VERSION 5.8 ;
BUSBITCHARS "[]" ;
DIVIDERCHAR "/" ;
UNITS
    DATABASE MICRONS 1000 ;
END UNITS

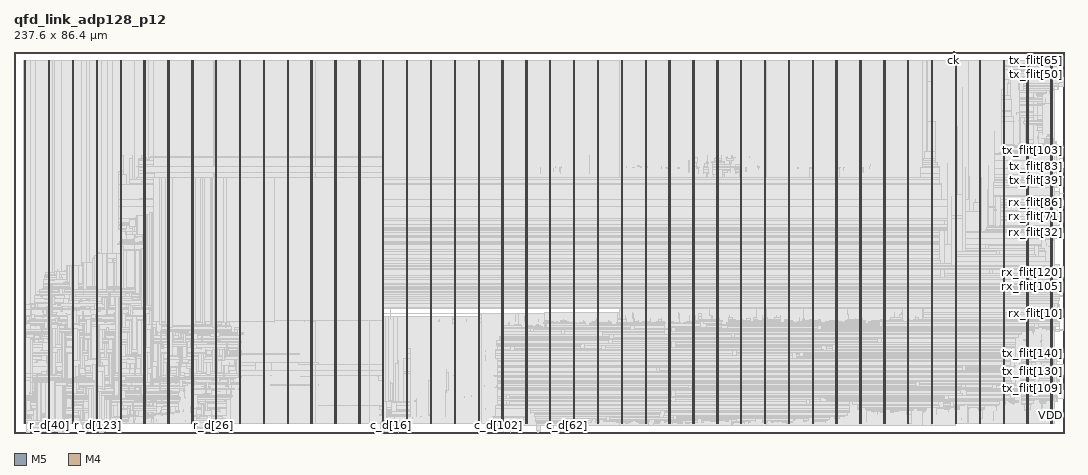
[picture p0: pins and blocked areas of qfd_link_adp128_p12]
MACRO qfd_link_adp128_p12
  FOREIGN qfd_link_adp128_p12 0 0 ;
  CLASS BLOCK ;
  SIZE 237.6 BY 86.4 ;
  PIN c_cr
    DIRECTION OUTPUT ;
    USE SIGNAL ;
    PORT
      LAYER M5 ;
        RECT  83.664 0 83.688 0.084 ;
    END
  END c_cr
  PIN c_d[0]
    DIRECTION INPUT ;
    USE SIGNAL ;
    PORT
      LAYER M5 ;
        RECT  83.76 0 83.784 0.084 ;
    END
  END c_d[0]
  PIN c_d[100]
    DIRECTION INPUT ;
    USE SIGNAL ;
    PORT
      LAYER M5 ;
        RECT  109.488 0 109.512 0.084 ;
    END
  END c_d[100]
  PIN c_d[101]
    DIRECTION INPUT ;
    USE SIGNAL ;
    PORT
      LAYER M5 ;
        RECT  109.584 0 109.608 0.084 ;
    END
  END c_d[101]
  PIN c_d[102]
    DIRECTION INPUT ;
    USE SIGNAL ;
    PORT
      LAYER M5 ;
        RECT  109.68 0 109.704 0.084 ;
    END
  END c_d[102]
  PIN c_d[103]
    DIRECTION INPUT ;
    USE SIGNAL ;
    PORT
      LAYER M5 ;
        RECT  109.776 0 109.8 0.084 ;
    END
  END c_d[103]
  PIN c_d[104]
    DIRECTION INPUT ;
    USE SIGNAL ;
    PORT
      LAYER M5 ;
        RECT  109.872 0 109.896 0.084 ;
    END
  END c_d[104]
  PIN c_d[105]
    DIRECTION INPUT ;
    USE SIGNAL ;
    PORT
      LAYER M5 ;
        RECT  109.968 0 109.992 0.084 ;
    END
  END c_d[105]
  PIN c_d[106]
    DIRECTION INPUT ;
    USE SIGNAL ;
    PORT
      LAYER M5 ;
        RECT  110.064 0 110.088 0.084 ;
    END
  END c_d[106]
  PIN c_d[107]
    DIRECTION INPUT ;
    USE SIGNAL ;
    PORT
      LAYER M5 ;
        RECT  110.16 0 110.184 0.084 ;
    END
  END c_d[107]
  PIN c_d[108]
    DIRECTION INPUT ;
    USE SIGNAL ;
    PORT
      LAYER M5 ;
        RECT  110.256 0 110.28 0.084 ;
    END
  END c_d[108]
  PIN c_d[109]
    DIRECTION INPUT ;
    USE SIGNAL ;
    PORT
      LAYER M5 ;
        RECT  110.352 0 110.376 0.084 ;
    END
  END c_d[109]
  PIN c_d[10]
    DIRECTION INPUT ;
    USE SIGNAL ;
    PORT
      LAYER M5 ;
        RECT  84.72 0 84.744 0.084 ;
    END
  END c_d[10]
  PIN c_d[110]
    DIRECTION INPUT ;
    USE SIGNAL ;
    PORT
      LAYER M5 ;
        RECT  110.448 0 110.472 0.084 ;
    END
  END c_d[110]
  PIN c_d[111]
    DIRECTION INPUT ;
    USE SIGNAL ;
    PORT
      LAYER M5 ;
        RECT  110.544 0 110.568 0.084 ;
    END
  END c_d[111]
  PIN c_d[112]
    DIRECTION INPUT ;
    USE SIGNAL ;
    PORT
      LAYER M5 ;
        RECT  110.64 0 110.664 0.084 ;
    END
  END c_d[112]
  PIN c_d[113]
    DIRECTION INPUT ;
    USE SIGNAL ;
    PORT
      LAYER M5 ;
        RECT  110.736 0 110.76 0.084 ;
    END
  END c_d[113]
  PIN c_d[114]
    DIRECTION INPUT ;
    USE SIGNAL ;
    PORT
      LAYER M5 ;
        RECT  110.832 0 110.856 0.084 ;
    END
  END c_d[114]
  PIN c_d[115]
    DIRECTION INPUT ;
    USE SIGNAL ;
    PORT
      LAYER M5 ;
        RECT  110.928 0 110.952 0.084 ;
    END
  END c_d[115]
  PIN c_d[116]
    DIRECTION INPUT ;
    USE SIGNAL ;
    PORT
      LAYER M5 ;
        RECT  111.024 0 111.048 0.084 ;
    END
  END c_d[116]
  PIN c_d[117]
    DIRECTION INPUT ;
    USE SIGNAL ;
    PORT
      LAYER M5 ;
        RECT  111.12 0 111.144 0.084 ;
    END
  END c_d[117]
  PIN c_d[118]
    DIRECTION INPUT ;
    USE SIGNAL ;
    PORT
      LAYER M5 ;
        RECT  111.216 0 111.24 0.084 ;
    END
  END c_d[118]
  PIN c_d[119]
    DIRECTION INPUT ;
    USE SIGNAL ;
    PORT
      LAYER M5 ;
        RECT  111.312 0 111.336 0.084 ;
    END
  END c_d[119]
  PIN c_d[11]
    DIRECTION INPUT ;
    USE SIGNAL ;
    PORT
      LAYER M5 ;
        RECT  84.816 0 84.84 0.084 ;
    END
  END c_d[11]
  PIN c_d[120]
    DIRECTION INPUT ;
    USE SIGNAL ;
    PORT
      LAYER M5 ;
        RECT  111.408 0 111.432 0.084 ;
    END
  END c_d[120]
  PIN c_d[121]
    DIRECTION INPUT ;
    USE SIGNAL ;
    PORT
      LAYER M5 ;
        RECT  111.504 0 111.528 0.084 ;
    END
  END c_d[121]
  PIN c_d[122]
    DIRECTION INPUT ;
    USE SIGNAL ;
    PORT
      LAYER M5 ;
        RECT  111.6 0 111.624 0.084 ;
    END
  END c_d[122]
  PIN c_d[123]
    DIRECTION INPUT ;
    USE SIGNAL ;
    PORT
      LAYER M5 ;
        RECT  111.696 0 111.72 0.084 ;
    END
  END c_d[123]
  PIN c_d[124]
    DIRECTION INPUT ;
    USE SIGNAL ;
    PORT
      LAYER M5 ;
        RECT  111.792 0 111.816 0.084 ;
    END
  END c_d[124]
  PIN c_d[125]
    DIRECTION INPUT ;
    USE SIGNAL ;
    PORT
      LAYER M5 ;
        RECT  111.888 0 111.912 0.084 ;
    END
  END c_d[125]
  PIN c_d[126]
    DIRECTION INPUT ;
    USE SIGNAL ;
    PORT
      LAYER M5 ;
        RECT  111.984 0 112.008 0.084 ;
    END
  END c_d[126]
  PIN c_d[127]
    DIRECTION INPUT ;
    USE SIGNAL ;
    PORT
      LAYER M5 ;
        RECT  42.192 0 42.216 0.084 ;
    END
  END c_d[127]
  PIN c_d[12]
    DIRECTION INPUT ;
    USE SIGNAL ;
    PORT
      LAYER M5 ;
        RECT  84.912 0 84.936 0.084 ;
    END
  END c_d[12]
  PIN c_d[13]
    DIRECTION INPUT ;
    USE SIGNAL ;
    PORT
      LAYER M5 ;
        RECT  85.008 0 85.032 0.084 ;
    END
  END c_d[13]
  PIN c_d[14]
    DIRECTION INPUT ;
    USE SIGNAL ;
    PORT
      LAYER M5 ;
        RECT  85.104 0 85.128 0.084 ;
    END
  END c_d[14]
  PIN c_d[15]
    DIRECTION INPUT ;
    USE SIGNAL ;
    PORT
      LAYER M5 ;
        RECT  85.2 0 85.224 0.084 ;
    END
  END c_d[15]
  PIN c_d[16]
    DIRECTION INPUT ;
    USE SIGNAL ;
    PORT
      LAYER M5 ;
        RECT  85.296 0 85.32 0.084 ;
    END
  END c_d[16]
  PIN c_d[17]
    DIRECTION INPUT ;
    USE SIGNAL ;
    PORT
      LAYER M5 ;
        RECT  85.392 0 85.416 0.084 ;
    END
  END c_d[17]
  PIN c_d[18]
    DIRECTION INPUT ;
    USE SIGNAL ;
    PORT
      LAYER M5 ;
        RECT  85.488 0 85.512 0.084 ;
    END
  END c_d[18]
  PIN c_d[19]
    DIRECTION INPUT ;
    USE SIGNAL ;
    PORT
      LAYER M5 ;
        RECT  85.584 0 85.608 0.084 ;
    END
  END c_d[19]
  PIN c_d[1]
    DIRECTION INPUT ;
    USE SIGNAL ;
    PORT
      LAYER M5 ;
        RECT  83.856 0 83.88 0.084 ;
    END
  END c_d[1]
  PIN c_d[20]
    DIRECTION INPUT ;
    USE SIGNAL ;
    PORT
      LAYER M5 ;
        RECT  85.68 0 85.704 0.084 ;
    END
  END c_d[20]
  PIN c_d[21]
    DIRECTION INPUT ;
    USE SIGNAL ;
    PORT
      LAYER M5 ;
        RECT  85.776 0 85.8 0.084 ;
    END
  END c_d[21]
  PIN c_d[22]
    DIRECTION INPUT ;
    USE SIGNAL ;
    PORT
      LAYER M5 ;
        RECT  85.872 0 85.896 0.084 ;
    END
  END c_d[22]
  PIN c_d[23]
    DIRECTION INPUT ;
    USE SIGNAL ;
    PORT
      LAYER M5 ;
        RECT  85.968 0 85.992 0.084 ;
    END
  END c_d[23]
  PIN c_d[24]
    DIRECTION INPUT ;
    USE SIGNAL ;
    PORT
      LAYER M5 ;
        RECT  86.064 0 86.088 0.084 ;
    END
  END c_d[24]
  PIN c_d[25]
    DIRECTION INPUT ;
    USE SIGNAL ;
    PORT
      LAYER M5 ;
        RECT  86.16 0 86.184 0.084 ;
    END
  END c_d[25]
  PIN c_d[26]
    DIRECTION INPUT ;
    USE SIGNAL ;
    PORT
      LAYER M5 ;
        RECT  86.256 0 86.28 0.084 ;
    END
  END c_d[26]
  PIN c_d[27]
    DIRECTION INPUT ;
    USE SIGNAL ;
    PORT
      LAYER M5 ;
        RECT  86.352 0 86.376 0.084 ;
    END
  END c_d[27]
  PIN c_d[28]
    DIRECTION INPUT ;
    USE SIGNAL ;
    PORT
      LAYER M5 ;
        RECT  86.448 0 86.472 0.084 ;
    END
  END c_d[28]
  PIN c_d[29]
    DIRECTION INPUT ;
    USE SIGNAL ;
    PORT
      LAYER M5 ;
        RECT  86.544 0 86.568 0.084 ;
    END
  END c_d[29]
  PIN c_d[2]
    DIRECTION INPUT ;
    USE SIGNAL ;
    PORT
      LAYER M5 ;
        RECT  83.952 0 83.976 0.084 ;
    END
  END c_d[2]
  PIN c_d[30]
    DIRECTION INPUT ;
    USE SIGNAL ;
    PORT
      LAYER M5 ;
        RECT  86.64 0 86.664 0.084 ;
    END
  END c_d[30]
  PIN c_d[31]
    DIRECTION INPUT ;
    USE SIGNAL ;
    PORT
      LAYER M5 ;
        RECT  122.064 0 122.088 0.084 ;
    END
  END c_d[31]
  PIN c_d[32]
    DIRECTION INPUT ;
    USE SIGNAL ;
    PORT
      LAYER M5 ;
        RECT  122.16 0 122.184 0.084 ;
    END
  END c_d[32]
  PIN c_d[33]
    DIRECTION INPUT ;
    USE SIGNAL ;
    PORT
      LAYER M5 ;
        RECT  122.256 0 122.28 0.084 ;
    END
  END c_d[33]
  PIN c_d[34]
    DIRECTION INPUT ;
    USE SIGNAL ;
    PORT
      LAYER M5 ;
        RECT  122.352 0 122.376 0.084 ;
    END
  END c_d[34]
  PIN c_d[35]
    DIRECTION INPUT ;
    USE SIGNAL ;
    PORT
      LAYER M5 ;
        RECT  122.448 0 122.472 0.084 ;
    END
  END c_d[35]
  PIN c_d[36]
    DIRECTION INPUT ;
    USE SIGNAL ;
    PORT
      LAYER M5 ;
        RECT  122.544 0 122.568 0.084 ;
    END
  END c_d[36]
  PIN c_d[37]
    DIRECTION INPUT ;
    USE SIGNAL ;
    PORT
      LAYER M5 ;
        RECT  122.64 0 122.664 0.084 ;
    END
  END c_d[37]
  PIN c_d[38]
    DIRECTION INPUT ;
    USE SIGNAL ;
    PORT
      LAYER M5 ;
        RECT  122.736 0 122.76 0.084 ;
    END
  END c_d[38]
  PIN c_d[39]
    DIRECTION INPUT ;
    USE SIGNAL ;
    PORT
      LAYER M5 ;
        RECT  122.832 0 122.856 0.084 ;
    END
  END c_d[39]
  PIN c_d[3]
    DIRECTION INPUT ;
    USE SIGNAL ;
    PORT
      LAYER M5 ;
        RECT  84.048 0 84.072 0.084 ;
    END
  END c_d[3]
  PIN c_d[40]
    DIRECTION INPUT ;
    USE SIGNAL ;
    PORT
      LAYER M5 ;
        RECT  122.928 0 122.952 0.084 ;
    END
  END c_d[40]
  PIN c_d[41]
    DIRECTION INPUT ;
    USE SIGNAL ;
    PORT
      LAYER M5 ;
        RECT  123.024 0 123.048 0.084 ;
    END
  END c_d[41]
  PIN c_d[42]
    DIRECTION INPUT ;
    USE SIGNAL ;
    PORT
      LAYER M5 ;
        RECT  123.12 0 123.144 0.084 ;
    END
  END c_d[42]
  PIN c_d[43]
    DIRECTION INPUT ;
    USE SIGNAL ;
    PORT
      LAYER M5 ;
        RECT  123.216 0 123.24 0.084 ;
    END
  END c_d[43]
  PIN c_d[44]
    DIRECTION INPUT ;
    USE SIGNAL ;
    PORT
      LAYER M5 ;
        RECT  123.312 0 123.336 0.084 ;
    END
  END c_d[44]
  PIN c_d[45]
    DIRECTION INPUT ;
    USE SIGNAL ;
    PORT
      LAYER M5 ;
        RECT  123.408 0 123.432 0.084 ;
    END
  END c_d[45]
  PIN c_d[46]
    DIRECTION INPUT ;
    USE SIGNAL ;
    PORT
      LAYER M5 ;
        RECT  123.504 0 123.528 0.084 ;
    END
  END c_d[46]
  PIN c_d[47]
    DIRECTION INPUT ;
    USE SIGNAL ;
    PORT
      LAYER M5 ;
        RECT  123.6 0 123.624 0.084 ;
    END
  END c_d[47]
  PIN c_d[48]
    DIRECTION INPUT ;
    USE SIGNAL ;
    PORT
      LAYER M5 ;
        RECT  123.696 0 123.72 0.084 ;
    END
  END c_d[48]
  PIN c_d[49]
    DIRECTION INPUT ;
    USE SIGNAL ;
    PORT
      LAYER M5 ;
        RECT  123.792 0 123.816 0.084 ;
    END
  END c_d[49]
  PIN c_d[4]
    DIRECTION INPUT ;
    USE SIGNAL ;
    PORT
      LAYER M5 ;
        RECT  84.144 0 84.168 0.084 ;
    END
  END c_d[4]
  PIN c_d[50]
    DIRECTION INPUT ;
    USE SIGNAL ;
    PORT
      LAYER M5 ;
        RECT  123.888 0 123.912 0.084 ;
    END
  END c_d[50]
  PIN c_d[51]
    DIRECTION INPUT ;
    USE SIGNAL ;
    PORT
      LAYER M5 ;
        RECT  123.984 0 124.008 0.084 ;
    END
  END c_d[51]
  PIN c_d[52]
    DIRECTION INPUT ;
    USE SIGNAL ;
    PORT
      LAYER M5 ;
        RECT  124.08 0 124.104 0.084 ;
    END
  END c_d[52]
  PIN c_d[53]
    DIRECTION INPUT ;
    USE SIGNAL ;
    PORT
      LAYER M5 ;
        RECT  124.176 0 124.2 0.084 ;
    END
  END c_d[53]
  PIN c_d[54]
    DIRECTION INPUT ;
    USE SIGNAL ;
    PORT
      LAYER M5 ;
        RECT  124.272 0 124.296 0.084 ;
    END
  END c_d[54]
  PIN c_d[55]
    DIRECTION INPUT ;
    USE SIGNAL ;
    PORT
      LAYER M5 ;
        RECT  124.368 0 124.392 0.084 ;
    END
  END c_d[55]
  PIN c_d[56]
    DIRECTION INPUT ;
    USE SIGNAL ;
    PORT
      LAYER M5 ;
        RECT  124.464 0 124.488 0.084 ;
    END
  END c_d[56]
  PIN c_d[57]
    DIRECTION INPUT ;
    USE SIGNAL ;
    PORT
      LAYER M5 ;
        RECT  124.56 0 124.584 0.084 ;
    END
  END c_d[57]
  PIN c_d[58]
    DIRECTION INPUT ;
    USE SIGNAL ;
    PORT
      LAYER M5 ;
        RECT  124.656 0 124.68 0.084 ;
    END
  END c_d[58]
  PIN c_d[59]
    DIRECTION INPUT ;
    USE SIGNAL ;
    PORT
      LAYER M5 ;
        RECT  124.752 0 124.776 0.084 ;
    END
  END c_d[59]
  PIN c_d[5]
    DIRECTION INPUT ;
    USE SIGNAL ;
    PORT
      LAYER M5 ;
        RECT  84.24 0 84.264 0.084 ;
    END
  END c_d[5]
  PIN c_d[60]
    DIRECTION INPUT ;
    USE SIGNAL ;
    PORT
      LAYER M5 ;
        RECT  124.848 0 124.872 0.084 ;
    END
  END c_d[60]
  PIN c_d[61]
    DIRECTION INPUT ;
    USE SIGNAL ;
    PORT
      LAYER M5 ;
        RECT  124.944 0 124.968 0.084 ;
    END
  END c_d[61]
  PIN c_d[62]
    DIRECTION INPUT ;
    USE SIGNAL ;
    PORT
      LAYER M5 ;
        RECT  125.04 0 125.064 0.084 ;
    END
  END c_d[62]
  PIN c_d[63]
    DIRECTION INPUT ;
    USE SIGNAL ;
    PORT
      LAYER M5 ;
        RECT  118.992 0 119.016 0.084 ;
    END
  END c_d[63]
  PIN c_d[64]
    DIRECTION INPUT ;
    USE SIGNAL ;
    PORT
      LAYER M5 ;
        RECT  119.088 0 119.112 0.084 ;
    END
  END c_d[64]
  PIN c_d[65]
    DIRECTION INPUT ;
    USE SIGNAL ;
    PORT
      LAYER M5 ;
        RECT  119.184 0 119.208 0.084 ;
    END
  END c_d[65]
  PIN c_d[66]
    DIRECTION INPUT ;
    USE SIGNAL ;
    PORT
      LAYER M5 ;
        RECT  119.28 0 119.304 0.084 ;
    END
  END c_d[66]
  PIN c_d[67]
    DIRECTION INPUT ;
    USE SIGNAL ;
    PORT
      LAYER M5 ;
        RECT  119.376 0 119.4 0.084 ;
    END
  END c_d[67]
  PIN c_d[68]
    DIRECTION INPUT ;
    USE SIGNAL ;
    PORT
      LAYER M5 ;
        RECT  119.472 0 119.496 0.084 ;
    END
  END c_d[68]
  PIN c_d[69]
    DIRECTION INPUT ;
    USE SIGNAL ;
    PORT
      LAYER M5 ;
        RECT  119.568 0 119.592 0.084 ;
    END
  END c_d[69]
  PIN c_d[6]
    DIRECTION INPUT ;
    USE SIGNAL ;
    PORT
      LAYER M5 ;
        RECT  84.336 0 84.36 0.084 ;
    END
  END c_d[6]
  PIN c_d[70]
    DIRECTION INPUT ;
    USE SIGNAL ;
    PORT
      LAYER M5 ;
        RECT  119.664 0 119.688 0.084 ;
    END
  END c_d[70]
  PIN c_d[71]
    DIRECTION INPUT ;
    USE SIGNAL ;
    PORT
      LAYER M5 ;
        RECT  119.76 0 119.784 0.084 ;
    END
  END c_d[71]
  PIN c_d[72]
    DIRECTION INPUT ;
    USE SIGNAL ;
    PORT
      LAYER M5 ;
        RECT  119.856 0 119.88 0.084 ;
    END
  END c_d[72]
  PIN c_d[73]
    DIRECTION INPUT ;
    USE SIGNAL ;
    PORT
      LAYER M5 ;
        RECT  119.952 0 119.976 0.084 ;
    END
  END c_d[73]
  PIN c_d[74]
    DIRECTION INPUT ;
    USE SIGNAL ;
    PORT
      LAYER M5 ;
        RECT  120.048 0 120.072 0.084 ;
    END
  END c_d[74]
  PIN c_d[75]
    DIRECTION INPUT ;
    USE SIGNAL ;
    PORT
      LAYER M5 ;
        RECT  120.144 0 120.168 0.084 ;
    END
  END c_d[75]
  PIN c_d[76]
    DIRECTION INPUT ;
    USE SIGNAL ;
    PORT
      LAYER M5 ;
        RECT  120.24 0 120.264 0.084 ;
    END
  END c_d[76]
  PIN c_d[77]
    DIRECTION INPUT ;
    USE SIGNAL ;
    PORT
      LAYER M5 ;
        RECT  120.336 0 120.36 0.084 ;
    END
  END c_d[77]
  PIN c_d[78]
    DIRECTION INPUT ;
    USE SIGNAL ;
    PORT
      LAYER M5 ;
        RECT  120.432 0 120.456 0.084 ;
    END
  END c_d[78]
  PIN c_d[79]
    DIRECTION INPUT ;
    USE SIGNAL ;
    PORT
      LAYER M5 ;
        RECT  120.528 0 120.552 0.084 ;
    END
  END c_d[79]
  PIN c_d[7]
    DIRECTION INPUT ;
    USE SIGNAL ;
    PORT
      LAYER M5 ;
        RECT  84.432 0 84.456 0.084 ;
    END
  END c_d[7]
  PIN c_d[80]
    DIRECTION INPUT ;
    USE SIGNAL ;
    PORT
      LAYER M5 ;
        RECT  120.624 0 120.648 0.084 ;
    END
  END c_d[80]
  PIN c_d[81]
    DIRECTION INPUT ;
    USE SIGNAL ;
    PORT
      LAYER M5 ;
        RECT  120.72 0 120.744 0.084 ;
    END
  END c_d[81]
  PIN c_d[82]
    DIRECTION INPUT ;
    USE SIGNAL ;
    PORT
      LAYER M5 ;
        RECT  120.816 0 120.84 0.084 ;
    END
  END c_d[82]
  PIN c_d[83]
    DIRECTION INPUT ;
    USE SIGNAL ;
    PORT
      LAYER M5 ;
        RECT  120.912 0 120.936 0.084 ;
    END
  END c_d[83]
  PIN c_d[84]
    DIRECTION INPUT ;
    USE SIGNAL ;
    PORT
      LAYER M5 ;
        RECT  121.008 0 121.032 0.084 ;
    END
  END c_d[84]
  PIN c_d[85]
    DIRECTION INPUT ;
    USE SIGNAL ;
    PORT
      LAYER M5 ;
        RECT  121.104 0 121.128 0.084 ;
    END
  END c_d[85]
  PIN c_d[86]
    DIRECTION INPUT ;
    USE SIGNAL ;
    PORT
      LAYER M5 ;
        RECT  121.2 0 121.224 0.084 ;
    END
  END c_d[86]
  PIN c_d[87]
    DIRECTION INPUT ;
    USE SIGNAL ;
    PORT
      LAYER M5 ;
        RECT  121.296 0 121.32 0.084 ;
    END
  END c_d[87]
  PIN c_d[88]
    DIRECTION INPUT ;
    USE SIGNAL ;
    PORT
      LAYER M5 ;
        RECT  121.392 0 121.416 0.084 ;
    END
  END c_d[88]
  PIN c_d[89]
    DIRECTION INPUT ;
    USE SIGNAL ;
    PORT
      LAYER M5 ;
        RECT  121.488 0 121.512 0.084 ;
    END
  END c_d[89]
  PIN c_d[8]
    DIRECTION INPUT ;
    USE SIGNAL ;
    PORT
      LAYER M5 ;
        RECT  84.528 0 84.552 0.084 ;
    END
  END c_d[8]
  PIN c_d[90]
    DIRECTION INPUT ;
    USE SIGNAL ;
    PORT
      LAYER M5 ;
        RECT  121.584 0 121.608 0.084 ;
    END
  END c_d[90]
  PIN c_d[91]
    DIRECTION INPUT ;
    USE SIGNAL ;
    PORT
      LAYER M5 ;
        RECT  121.68 0 121.704 0.084 ;
    END
  END c_d[91]
  PIN c_d[92]
    DIRECTION INPUT ;
    USE SIGNAL ;
    PORT
      LAYER M5 ;
        RECT  121.776 0 121.8 0.084 ;
    END
  END c_d[92]
  PIN c_d[93]
    DIRECTION INPUT ;
    USE SIGNAL ;
    PORT
      LAYER M5 ;
        RECT  121.872 0 121.896 0.084 ;
    END
  END c_d[93]
  PIN c_d[94]
    DIRECTION INPUT ;
    USE SIGNAL ;
    PORT
      LAYER M5 ;
        RECT  121.968 0 121.992 0.084 ;
    END
  END c_d[94]
  PIN c_d[95]
    DIRECTION INPUT ;
    USE SIGNAL ;
    PORT
      LAYER M5 ;
        RECT  109.008 0 109.032 0.084 ;
    END
  END c_d[95]
  PIN c_d[96]
    DIRECTION INPUT ;
    USE SIGNAL ;
    PORT
      LAYER M5 ;
        RECT  109.104 0 109.128 0.084 ;
    END
  END c_d[96]
  PIN c_d[97]
    DIRECTION INPUT ;
    USE SIGNAL ;
    PORT
      LAYER M5 ;
        RECT  109.2 0 109.224 0.084 ;
    END
  END c_d[97]
  PIN c_d[98]
    DIRECTION INPUT ;
    USE SIGNAL ;
    PORT
      LAYER M5 ;
        RECT  109.296 0 109.32 0.084 ;
    END
  END c_d[98]
  PIN c_d[99]
    DIRECTION INPUT ;
    USE SIGNAL ;
    PORT
      LAYER M5 ;
        RECT  109.392 0 109.416 0.084 ;
    END
  END c_d[99]
  PIN c_d[9]
    DIRECTION INPUT ;
    USE SIGNAL ;
    PORT
      LAYER M5 ;
        RECT  84.624 0 84.648 0.084 ;
    END
  END c_d[9]
  PIN c_v
    DIRECTION INPUT ;
    USE SIGNAL ;
    PORT
      LAYER M5 ;
        RECT  42.288 0 42.312 0.084 ;
    END
  END c_v
  PIN ck
    DIRECTION INPUT ;
    USE SIGNAL ;
    PORT
      LAYER M5 ;
        RECT  212.688 86.316 212.712 86.4 ;
    END
    PORT
      LAYER M5 ;
        RECT  212.688 84.263 212.712 86.352 ;
    END
  END ck
  PIN fault
    DIRECTION OUTPUT ;
    USE SIGNAL ;
    PORT
      LAYER M5 ;
        RECT  42.384 0 42.408 0.084 ;
    END
  END fault
  PIN r_cr
    DIRECTION INPUT ;
    USE SIGNAL ;
    PORT
      LAYER M5 ;
        RECT  42.48 0 42.504 0.084 ;
    END
  END r_cr
  PIN r_d[0]
    DIRECTION OUTPUT ;
    USE SIGNAL ;
    PORT
      LAYER M5 ;
        RECT  42.576 0 42.6 0.084 ;
    END
  END r_d[0]
  PIN r_d[100]
    DIRECTION OUTPUT ;
    USE SIGNAL ;
    PORT
      LAYER M5 ;
        RECT  16.848 0 16.872 0.084 ;
    END
  END r_d[100]
  PIN r_d[101]
    DIRECTION OUTPUT ;
    USE SIGNAL ;
    PORT
      LAYER M5 ;
        RECT  16.944 0 16.968 0.084 ;
    END
  END r_d[101]
  PIN r_d[102]
    DIRECTION OUTPUT ;
    USE SIGNAL ;
    PORT
      LAYER M5 ;
        RECT  17.04 0 17.064 0.084 ;
    END
  END r_d[102]
  PIN r_d[103]
    DIRECTION OUTPUT ;
    USE SIGNAL ;
    PORT
      LAYER M5 ;
        RECT  17.136 0 17.16 0.084 ;
    END
  END r_d[103]
  PIN r_d[104]
    DIRECTION OUTPUT ;
    USE SIGNAL ;
    PORT
      LAYER M5 ;
        RECT  17.232 0 17.256 0.084 ;
    END
  END r_d[104]
  PIN r_d[105]
    DIRECTION OUTPUT ;
    USE SIGNAL ;
    PORT
      LAYER M5 ;
        RECT  17.328 0 17.352 0.084 ;
    END
  END r_d[105]
  PIN r_d[106]
    DIRECTION OUTPUT ;
    USE SIGNAL ;
    PORT
      LAYER M5 ;
        RECT  17.424 0 17.448 0.084 ;
    END
  END r_d[106]
  PIN r_d[107]
    DIRECTION OUTPUT ;
    USE SIGNAL ;
    PORT
      LAYER M5 ;
        RECT  17.52 0 17.544 0.084 ;
    END
  END r_d[107]
  PIN r_d[108]
    DIRECTION OUTPUT ;
    USE SIGNAL ;
    PORT
      LAYER M5 ;
        RECT  17.616 0 17.64 0.084 ;
    END
  END r_d[108]
  PIN r_d[109]
    DIRECTION OUTPUT ;
    USE SIGNAL ;
    PORT
      LAYER M5 ;
        RECT  17.712 0 17.736 0.084 ;
    END
  END r_d[109]
  PIN r_d[10]
    DIRECTION OUTPUT ;
    USE SIGNAL ;
    PORT
      LAYER M5 ;
        RECT  43.536 0 43.56 0.084 ;
    END
  END r_d[10]
  PIN r_d[110]
    DIRECTION OUTPUT ;
    USE SIGNAL ;
    PORT
      LAYER M5 ;
        RECT  17.808 0 17.832 0.084 ;
    END
  END r_d[110]
  PIN r_d[111]
    DIRECTION OUTPUT ;
    USE SIGNAL ;
    PORT
      LAYER M5 ;
        RECT  17.904 0 17.928 0.084 ;
    END
  END r_d[111]
  PIN r_d[112]
    DIRECTION OUTPUT ;
    USE SIGNAL ;
    PORT
      LAYER M5 ;
        RECT  18 0 18.024 0.084 ;
    END
  END r_d[112]
  PIN r_d[113]
    DIRECTION OUTPUT ;
    USE SIGNAL ;
    PORT
      LAYER M5 ;
        RECT  18.096 0 18.12 0.084 ;
    END
  END r_d[113]
  PIN r_d[114]
    DIRECTION OUTPUT ;
    USE SIGNAL ;
    PORT
      LAYER M5 ;
        RECT  18.192 0 18.216 0.084 ;
    END
  END r_d[114]
  PIN r_d[115]
    DIRECTION OUTPUT ;
    USE SIGNAL ;
    PORT
      LAYER M5 ;
        RECT  18.288 0 18.312 0.084 ;
    END
  END r_d[115]
  PIN r_d[116]
    DIRECTION OUTPUT ;
    USE SIGNAL ;
    PORT
      LAYER M5 ;
        RECT  18.384 0 18.408 0.084 ;
    END
  END r_d[116]
  PIN r_d[117]
    DIRECTION OUTPUT ;
    USE SIGNAL ;
    PORT
      LAYER M5 ;
        RECT  18.48 0 18.504 0.084 ;
    END
  END r_d[117]
  PIN r_d[118]
    DIRECTION OUTPUT ;
    USE SIGNAL ;
    PORT
      LAYER M5 ;
        RECT  18.576 0 18.6 0.084 ;
    END
  END r_d[118]
  PIN r_d[119]
    DIRECTION OUTPUT ;
    USE SIGNAL ;
    PORT
      LAYER M5 ;
        RECT  18.672 0 18.696 0.084 ;
    END
  END r_d[119]
  PIN r_d[11]
    DIRECTION OUTPUT ;
    USE SIGNAL ;
    PORT
      LAYER M5 ;
        RECT  43.632 0 43.656 0.084 ;
    END
  END r_d[11]
  PIN r_d[120]
    DIRECTION OUTPUT ;
    USE SIGNAL ;
    PORT
      LAYER M5 ;
        RECT  18.768 0 18.792 0.084 ;
    END
  END r_d[120]
  PIN r_d[121]
    DIRECTION OUTPUT ;
    USE SIGNAL ;
    PORT
      LAYER M5 ;
        RECT  18.864 0 18.888 0.084 ;
    END
  END r_d[121]
  PIN r_d[122]
    DIRECTION OUTPUT ;
    USE SIGNAL ;
    PORT
      LAYER M5 ;
        RECT  18.96 0 18.984 0.084 ;
    END
  END r_d[122]
  PIN r_d[123]
    DIRECTION OUTPUT ;
    USE SIGNAL ;
    PORT
      LAYER M5 ;
        RECT  19.056 0 19.08 0.084 ;
    END
  END r_d[123]
  PIN r_d[124]
    DIRECTION OUTPUT ;
    USE SIGNAL ;
    PORT
      LAYER M5 ;
        RECT  20.496 0 20.52 0.084 ;
    END
  END r_d[124]
  PIN r_d[125]
    DIRECTION OUTPUT ;
    USE SIGNAL ;
    PORT
      LAYER M5 ;
        RECT  20.592 0 20.616 0.084 ;
    END
  END r_d[125]
  PIN r_d[126]
    DIRECTION OUTPUT ;
    USE SIGNAL ;
    PORT
      LAYER M5 ;
        RECT  20.688 0 20.712 0.084 ;
    END
  END r_d[126]
  PIN r_d[127]
    DIRECTION OUTPUT ;
    USE SIGNAL ;
    PORT
      LAYER M5 ;
        RECT  20.784 0 20.808 0.084 ;
    END
  END r_d[127]
  PIN r_d[12]
    DIRECTION OUTPUT ;
    USE SIGNAL ;
    PORT
      LAYER M5 ;
        RECT  43.728 0 43.752 0.084 ;
    END
  END r_d[12]
  PIN r_d[13]
    DIRECTION OUTPUT ;
    USE SIGNAL ;
    PORT
      LAYER M5 ;
        RECT  43.824 0 43.848 0.084 ;
    END
  END r_d[13]
  PIN r_d[14]
    DIRECTION OUTPUT ;
    USE SIGNAL ;
    PORT
      LAYER M5 ;
        RECT  43.92 0 43.944 0.084 ;
    END
  END r_d[14]
  PIN r_d[15]
    DIRECTION OUTPUT ;
    USE SIGNAL ;
    PORT
      LAYER M5 ;
        RECT  44.016 0 44.04 0.084 ;
    END
  END r_d[15]
  PIN r_d[16]
    DIRECTION OUTPUT ;
    USE SIGNAL ;
    PORT
      LAYER M5 ;
        RECT  44.112 0 44.136 0.084 ;
    END
  END r_d[16]
  PIN r_d[17]
    DIRECTION OUTPUT ;
    USE SIGNAL ;
    PORT
      LAYER M5 ;
        RECT  44.208 0 44.232 0.084 ;
    END
  END r_d[17]
  PIN r_d[18]
    DIRECTION OUTPUT ;
    USE SIGNAL ;
    PORT
      LAYER M5 ;
        RECT  44.304 0 44.328 0.084 ;
    END
  END r_d[18]
  PIN r_d[19]
    DIRECTION OUTPUT ;
    USE SIGNAL ;
    PORT
      LAYER M5 ;
        RECT  44.4 0 44.424 0.084 ;
    END
  END r_d[19]
  PIN r_d[1]
    DIRECTION OUTPUT ;
    USE SIGNAL ;
    PORT
      LAYER M5 ;
        RECT  42.672 0 42.696 0.084 ;
    END
  END r_d[1]
  PIN r_d[20]
    DIRECTION OUTPUT ;
    USE SIGNAL ;
    PORT
      LAYER M5 ;
        RECT  44.496 0 44.52 0.084 ;
    END
  END r_d[20]
  PIN r_d[21]
    DIRECTION OUTPUT ;
    USE SIGNAL ;
    PORT
      LAYER M5 ;
        RECT  44.592 0 44.616 0.084 ;
    END
  END r_d[21]
  PIN r_d[22]
    DIRECTION OUTPUT ;
    USE SIGNAL ;
    PORT
      LAYER M5 ;
        RECT  44.688 0 44.712 0.084 ;
    END
  END r_d[22]
  PIN r_d[23]
    DIRECTION OUTPUT ;
    USE SIGNAL ;
    PORT
      LAYER M5 ;
        RECT  44.784 0 44.808 0.084 ;
    END
  END r_d[23]
  PIN r_d[24]
    DIRECTION OUTPUT ;
    USE SIGNAL ;
    PORT
      LAYER M5 ;
        RECT  44.88 0 44.904 0.084 ;
    END
  END r_d[24]
  PIN r_d[25]
    DIRECTION OUTPUT ;
    USE SIGNAL ;
    PORT
      LAYER M5 ;
        RECT  44.976 0 45 0.084 ;
    END
  END r_d[25]
  PIN r_d[26]
    DIRECTION OUTPUT ;
    USE SIGNAL ;
    PORT
      LAYER M5 ;
        RECT  45.072 0 45.096 0.084 ;
    END
  END r_d[26]
  PIN r_d[27]
    DIRECTION OUTPUT ;
    USE SIGNAL ;
    PORT
      LAYER M5 ;
        RECT  45.168 0 45.192 0.084 ;
    END
  END r_d[27]
  PIN r_d[28]
    DIRECTION OUTPUT ;
    USE SIGNAL ;
    PORT
      LAYER M5 ;
        RECT  6.864 0 6.888 0.084 ;
    END
  END r_d[28]
  PIN r_d[29]
    DIRECTION OUTPUT ;
    USE SIGNAL ;
    PORT
      LAYER M5 ;
        RECT  6.96 0 6.984 0.084 ;
    END
  END r_d[29]
  PIN r_d[2]
    DIRECTION OUTPUT ;
    USE SIGNAL ;
    PORT
      LAYER M5 ;
        RECT  42.768 0 42.792 0.084 ;
    END
  END r_d[2]
  PIN r_d[30]
    DIRECTION OUTPUT ;
    USE SIGNAL ;
    PORT
      LAYER M5 ;
        RECT  7.056 0 7.08 0.084 ;
    END
  END r_d[30]
  PIN r_d[31]
    DIRECTION OUTPUT ;
    USE SIGNAL ;
    PORT
      LAYER M5 ;
        RECT  7.152 0 7.176 0.084 ;
    END
  END r_d[31]
  PIN r_d[32]
    DIRECTION OUTPUT ;
    USE SIGNAL ;
    PORT
      LAYER M5 ;
        RECT  7.248 0 7.272 0.084 ;
    END
  END r_d[32]
  PIN r_d[33]
    DIRECTION OUTPUT ;
    USE SIGNAL ;
    PORT
      LAYER M5 ;
        RECT  7.344 0 7.368 0.084 ;
    END
  END r_d[33]
  PIN r_d[34]
    DIRECTION OUTPUT ;
    USE SIGNAL ;
    PORT
      LAYER M5 ;
        RECT  7.44 0 7.464 0.084 ;
    END
  END r_d[34]
  PIN r_d[35]
    DIRECTION OUTPUT ;
    USE SIGNAL ;
    PORT
      LAYER M5 ;
        RECT  7.536 0 7.56 0.084 ;
    END
  END r_d[35]
  PIN r_d[36]
    DIRECTION OUTPUT ;
    USE SIGNAL ;
    PORT
      LAYER M5 ;
        RECT  7.632 0 7.656 0.084 ;
    END
  END r_d[36]
  PIN r_d[37]
    DIRECTION OUTPUT ;
    USE SIGNAL ;
    PORT
      LAYER M5 ;
        RECT  7.728 0 7.752 0.084 ;
    END
  END r_d[37]
  PIN r_d[38]
    DIRECTION OUTPUT ;
    USE SIGNAL ;
    PORT
      LAYER M5 ;
        RECT  7.824 0 7.848 0.084 ;
    END
  END r_d[38]
  PIN r_d[39]
    DIRECTION OUTPUT ;
    USE SIGNAL ;
    PORT
      LAYER M5 ;
        RECT  7.92 0 7.944 0.084 ;
    END
  END r_d[39]
  PIN r_d[3]
    DIRECTION OUTPUT ;
    USE SIGNAL ;
    PORT
      LAYER M5 ;
        RECT  42.864 0 42.888 0.084 ;
    END
  END r_d[3]
  PIN r_d[40]
    DIRECTION OUTPUT ;
    USE SIGNAL ;
    PORT
      LAYER M5 ;
        RECT  8.016 0 8.04 0.084 ;
    END
  END r_d[40]
  PIN r_d[41]
    DIRECTION OUTPUT ;
    USE SIGNAL ;
    PORT
      LAYER M5 ;
        RECT  8.112 0 8.136 0.084 ;
    END
  END r_d[41]
  PIN r_d[42]
    DIRECTION OUTPUT ;
    USE SIGNAL ;
    PORT
      LAYER M5 ;
        RECT  8.208 0 8.232 0.084 ;
    END
  END r_d[42]
  PIN r_d[43]
    DIRECTION OUTPUT ;
    USE SIGNAL ;
    PORT
      LAYER M5 ;
        RECT  8.304 0 8.328 0.084 ;
    END
  END r_d[43]
  PIN r_d[44]
    DIRECTION OUTPUT ;
    USE SIGNAL ;
    PORT
      LAYER M5 ;
        RECT  8.4 0 8.424 0.084 ;
    END
  END r_d[44]
  PIN r_d[45]
    DIRECTION OUTPUT ;
    USE SIGNAL ;
    PORT
      LAYER M5 ;
        RECT  8.496 0 8.52 0.084 ;
    END
  END r_d[45]
  PIN r_d[46]
    DIRECTION OUTPUT ;
    USE SIGNAL ;
    PORT
      LAYER M5 ;
        RECT  8.592 0 8.616 0.084 ;
    END
  END r_d[46]
  PIN r_d[47]
    DIRECTION OUTPUT ;
    USE SIGNAL ;
    PORT
      LAYER M5 ;
        RECT  8.688 0 8.712 0.084 ;
    END
  END r_d[47]
  PIN r_d[48]
    DIRECTION OUTPUT ;
    USE SIGNAL ;
    PORT
      LAYER M5 ;
        RECT  8.784 0 8.808 0.084 ;
    END
  END r_d[48]
  PIN r_d[49]
    DIRECTION OUTPUT ;
    USE SIGNAL ;
    PORT
      LAYER M5 ;
        RECT  8.88 0 8.904 0.084 ;
    END
  END r_d[49]
  PIN r_d[4]
    DIRECTION OUTPUT ;
    USE SIGNAL ;
    PORT
      LAYER M5 ;
        RECT  42.96 0 42.984 0.084 ;
    END
  END r_d[4]
  PIN r_d[50]
    DIRECTION OUTPUT ;
    USE SIGNAL ;
    PORT
      LAYER M5 ;
        RECT  8.976 0 9 0.084 ;
    END
  END r_d[50]
  PIN r_d[51]
    DIRECTION OUTPUT ;
    USE SIGNAL ;
    PORT
      LAYER M5 ;
        RECT  9.072 0 9.096 0.084 ;
    END
  END r_d[51]
  PIN r_d[52]
    DIRECTION OUTPUT ;
    USE SIGNAL ;
    PORT
      LAYER M5 ;
        RECT  9.168 0 9.192 0.084 ;
    END
  END r_d[52]
  PIN r_d[53]
    DIRECTION OUTPUT ;
    USE SIGNAL ;
    PORT
      LAYER M5 ;
        RECT  9.264 0 9.288 0.084 ;
    END
  END r_d[53]
  PIN r_d[54]
    DIRECTION OUTPUT ;
    USE SIGNAL ;
    PORT
      LAYER M5 ;
        RECT  9.36 0 9.384 0.084 ;
    END
  END r_d[54]
  PIN r_d[55]
    DIRECTION OUTPUT ;
    USE SIGNAL ;
    PORT
      LAYER M5 ;
        RECT  9.456 0 9.48 0.084 ;
    END
  END r_d[55]
  PIN r_d[56]
    DIRECTION OUTPUT ;
    USE SIGNAL ;
    PORT
      LAYER M5 ;
        RECT  9.552 0 9.576 0.084 ;
    END
  END r_d[56]
  PIN r_d[57]
    DIRECTION OUTPUT ;
    USE SIGNAL ;
    PORT
      LAYER M5 ;
        RECT  9.648 0 9.672 0.084 ;
    END
  END r_d[57]
  PIN r_d[58]
    DIRECTION OUTPUT ;
    USE SIGNAL ;
    PORT
      LAYER M5 ;
        RECT  9.744 0 9.768 0.084 ;
    END
  END r_d[58]
  PIN r_d[59]
    DIRECTION OUTPUT ;
    USE SIGNAL ;
    PORT
      LAYER M5 ;
        RECT  9.84 0 9.864 0.084 ;
    END
  END r_d[59]
  PIN r_d[5]
    DIRECTION OUTPUT ;
    USE SIGNAL ;
    PORT
      LAYER M5 ;
        RECT  43.056 0 43.08 0.084 ;
    END
  END r_d[5]
  PIN r_d[60]
    DIRECTION OUTPUT ;
    USE SIGNAL ;
    PORT
      LAYER M5 ;
        RECT  3.792 0 3.816 0.084 ;
    END
  END r_d[60]
  PIN r_d[61]
    DIRECTION OUTPUT ;
    USE SIGNAL ;
    PORT
      LAYER M5 ;
        RECT  3.888 0 3.912 0.084 ;
    END
  END r_d[61]
  PIN r_d[62]
    DIRECTION OUTPUT ;
    USE SIGNAL ;
    PORT
      LAYER M5 ;
        RECT  3.984 0 4.008 0.084 ;
    END
  END r_d[62]
  PIN r_d[63]
    DIRECTION OUTPUT ;
    USE SIGNAL ;
    PORT
      LAYER M5 ;
        RECT  4.08 0 4.104 0.084 ;
    END
  END r_d[63]
  PIN r_d[64]
    DIRECTION OUTPUT ;
    USE SIGNAL ;
    PORT
      LAYER M5 ;
        RECT  4.176 0 4.2 0.084 ;
    END
  END r_d[64]
  PIN r_d[65]
    DIRECTION OUTPUT ;
    USE SIGNAL ;
    PORT
      LAYER M5 ;
        RECT  4.272 0 4.296 0.084 ;
    END
  END r_d[65]
  PIN r_d[66]
    DIRECTION OUTPUT ;
    USE SIGNAL ;
    PORT
      LAYER M5 ;
        RECT  4.368 0 4.392 0.084 ;
    END
  END r_d[66]
  PIN r_d[67]
    DIRECTION OUTPUT ;
    USE SIGNAL ;
    PORT
      LAYER M5 ;
        RECT  4.464 0 4.488 0.084 ;
    END
  END r_d[67]
  PIN r_d[68]
    DIRECTION OUTPUT ;
    USE SIGNAL ;
    PORT
      LAYER M5 ;
        RECT  4.56 0 4.584 0.084 ;
    END
  END r_d[68]
  PIN r_d[69]
    DIRECTION OUTPUT ;
    USE SIGNAL ;
    PORT
      LAYER M5 ;
        RECT  4.656 0 4.68 0.084 ;
    END
  END r_d[69]
  PIN r_d[6]
    DIRECTION OUTPUT ;
    USE SIGNAL ;
    PORT
      LAYER M5 ;
        RECT  43.152 0 43.176 0.084 ;
    END
  END r_d[6]
  PIN r_d[70]
    DIRECTION OUTPUT ;
    USE SIGNAL ;
    PORT
      LAYER M5 ;
        RECT  4.752 0 4.776 0.084 ;
    END
  END r_d[70]
  PIN r_d[71]
    DIRECTION OUTPUT ;
    USE SIGNAL ;
    PORT
      LAYER M5 ;
        RECT  4.848 0 4.872 0.084 ;
    END
  END r_d[71]
  PIN r_d[72]
    DIRECTION OUTPUT ;
    USE SIGNAL ;
    PORT
      LAYER M5 ;
        RECT  4.944 0 4.968 0.084 ;
    END
  END r_d[72]
  PIN r_d[73]
    DIRECTION OUTPUT ;
    USE SIGNAL ;
    PORT
      LAYER M5 ;
        RECT  5.04 0 5.064 0.084 ;
    END
  END r_d[73]
  PIN r_d[74]
    DIRECTION OUTPUT ;
    USE SIGNAL ;
    PORT
      LAYER M5 ;
        RECT  5.136 0 5.16 0.084 ;
    END
  END r_d[74]
  PIN r_d[75]
    DIRECTION OUTPUT ;
    USE SIGNAL ;
    PORT
      LAYER M5 ;
        RECT  5.232 0 5.256 0.084 ;
    END
  END r_d[75]
  PIN r_d[76]
    DIRECTION OUTPUT ;
    USE SIGNAL ;
    PORT
      LAYER M5 ;
        RECT  5.328 0 5.352 0.084 ;
    END
  END r_d[76]
  PIN r_d[77]
    DIRECTION OUTPUT ;
    USE SIGNAL ;
    PORT
      LAYER M5 ;
        RECT  5.424 0 5.448 0.084 ;
    END
  END r_d[77]
  PIN r_d[78]
    DIRECTION OUTPUT ;
    USE SIGNAL ;
    PORT
      LAYER M5 ;
        RECT  5.52 0 5.544 0.084 ;
    END
  END r_d[78]
  PIN r_d[79]
    DIRECTION OUTPUT ;
    USE SIGNAL ;
    PORT
      LAYER M5 ;
        RECT  5.616 0 5.64 0.084 ;
    END
  END r_d[79]
  PIN r_d[7]
    DIRECTION OUTPUT ;
    USE SIGNAL ;
    PORT
      LAYER M5 ;
        RECT  43.248 0 43.272 0.084 ;
    END
  END r_d[7]
  PIN r_d[80]
    DIRECTION OUTPUT ;
    USE SIGNAL ;
    PORT
      LAYER M5 ;
        RECT  5.712 0 5.736 0.084 ;
    END
  END r_d[80]
  PIN r_d[81]
    DIRECTION OUTPUT ;
    USE SIGNAL ;
    PORT
      LAYER M5 ;
        RECT  5.808 0 5.832 0.084 ;
    END
  END r_d[81]
  PIN r_d[82]
    DIRECTION OUTPUT ;
    USE SIGNAL ;
    PORT
      LAYER M5 ;
        RECT  5.904 0 5.928 0.084 ;
    END
  END r_d[82]
  PIN r_d[83]
    DIRECTION OUTPUT ;
    USE SIGNAL ;
    PORT
      LAYER M5 ;
        RECT  6 0 6.024 0.084 ;
    END
  END r_d[83]
  PIN r_d[84]
    DIRECTION OUTPUT ;
    USE SIGNAL ;
    PORT
      LAYER M5 ;
        RECT  6.096 0 6.12 0.084 ;
    END
  END r_d[84]
  PIN r_d[85]
    DIRECTION OUTPUT ;
    USE SIGNAL ;
    PORT
      LAYER M5 ;
        RECT  6.192 0 6.216 0.084 ;
    END
  END r_d[85]
  PIN r_d[86]
    DIRECTION OUTPUT ;
    USE SIGNAL ;
    PORT
      LAYER M5 ;
        RECT  6.288 0 6.312 0.084 ;
    END
  END r_d[86]
  PIN r_d[87]
    DIRECTION OUTPUT ;
    USE SIGNAL ;
    PORT
      LAYER M5 ;
        RECT  6.384 0 6.408 0.084 ;
    END
  END r_d[87]
  PIN r_d[88]
    DIRECTION OUTPUT ;
    USE SIGNAL ;
    PORT
      LAYER M5 ;
        RECT  6.48 0 6.504 0.084 ;
    END
  END r_d[88]
  PIN r_d[89]
    DIRECTION OUTPUT ;
    USE SIGNAL ;
    PORT
      LAYER M5 ;
        RECT  6.576 0 6.6 0.084 ;
    END
  END r_d[89]
  PIN r_d[8]
    DIRECTION OUTPUT ;
    USE SIGNAL ;
    PORT
      LAYER M5 ;
        RECT  43.344 0 43.368 0.084 ;
    END
  END r_d[8]
  PIN r_d[90]
    DIRECTION OUTPUT ;
    USE SIGNAL ;
    PORT
      LAYER M5 ;
        RECT  6.672 0 6.696 0.084 ;
    END
  END r_d[90]
  PIN r_d[91]
    DIRECTION OUTPUT ;
    USE SIGNAL ;
    PORT
      LAYER M5 ;
        RECT  6.768 0 6.792 0.084 ;
    END
  END r_d[91]
  PIN r_d[92]
    DIRECTION OUTPUT ;
    USE SIGNAL ;
    PORT
      LAYER M5 ;
        RECT  16.08 0 16.104 0.084 ;
    END
  END r_d[92]
  PIN r_d[93]
    DIRECTION OUTPUT ;
    USE SIGNAL ;
    PORT
      LAYER M5 ;
        RECT  16.176 0 16.2 0.084 ;
    END
  END r_d[93]
  PIN r_d[94]
    DIRECTION OUTPUT ;
    USE SIGNAL ;
    PORT
      LAYER M5 ;
        RECT  16.272 0 16.296 0.084 ;
    END
  END r_d[94]
  PIN r_d[95]
    DIRECTION OUTPUT ;
    USE SIGNAL ;
    PORT
      LAYER M5 ;
        RECT  16.368 0 16.392 0.084 ;
    END
  END r_d[95]
  PIN r_d[96]
    DIRECTION OUTPUT ;
    USE SIGNAL ;
    PORT
      LAYER M5 ;
        RECT  16.464 0 16.488 0.084 ;
    END
  END r_d[96]
  PIN r_d[97]
    DIRECTION OUTPUT ;
    USE SIGNAL ;
    PORT
      LAYER M5 ;
        RECT  16.56 0 16.584 0.084 ;
    END
  END r_d[97]
  PIN r_d[98]
    DIRECTION OUTPUT ;
    USE SIGNAL ;
    PORT
      LAYER M5 ;
        RECT  16.656 0 16.68 0.084 ;
    END
  END r_d[98]
  PIN r_d[99]
    DIRECTION OUTPUT ;
    USE SIGNAL ;
    PORT
      LAYER M5 ;
        RECT  16.752 0 16.776 0.084 ;
    END
  END r_d[99]
  PIN r_d[9]
    DIRECTION OUTPUT ;
    USE SIGNAL ;
    PORT
      LAYER M5 ;
        RECT  43.44 0 43.464 0.084 ;
    END
  END r_d[9]
  PIN r_v
    DIRECTION OUTPUT ;
    USE SIGNAL ;
    PORT
      LAYER M5 ;
        RECT  20.88 0 20.904 0.084 ;
    END
  END r_v
  PIN rst_n
    DIRECTION INPUT ;
    USE SIGNAL ;
    PORT
      LAYER M5 ;
        RECT  20.976 0 21 0.084 ;
    END
  END rst_n
  PIN rx_flit[0]
    DIRECTION INPUT ;
    USE SIGNAL ;
    PORT
      LAYER M4 ;
        RECT  237.516 26.064 237.6 26.088 ;
    END
  END rx_flit[0]
  PIN rx_flit[100]
    DIRECTION INPUT ;
    USE SIGNAL ;
    PORT
      LAYER M4 ;
        RECT  237.516 32.592 237.6 32.616 ;
    END
  END rx_flit[100]
  PIN rx_flit[101]
    DIRECTION INPUT ;
    USE SIGNAL ;
    PORT
      LAYER M4 ;
        RECT  237.516 32.688 237.6 32.712 ;
    END
  END rx_flit[101]
  PIN rx_flit[102]
    DIRECTION INPUT ;
    USE SIGNAL ;
    PORT
      LAYER M4 ;
        RECT  237.516 32.784 237.6 32.808 ;
    END
  END rx_flit[102]
  PIN rx_flit[103]
    DIRECTION INPUT ;
    USE SIGNAL ;
    PORT
      LAYER M4 ;
        RECT  237.516 32.88 237.6 32.904 ;
    END
  END rx_flit[103]
  PIN rx_flit[104]
    DIRECTION INPUT ;
    USE SIGNAL ;
    PORT
      LAYER M4 ;
        RECT  237.516 32.976 237.6 33 ;
    END
  END rx_flit[104]
  PIN rx_flit[105]
    DIRECTION INPUT ;
    USE SIGNAL ;
    PORT
      LAYER M4 ;
        RECT  237.516 33.072 237.6 33.096 ;
    END
  END rx_flit[105]
  PIN rx_flit[106]
    DIRECTION INPUT ;
    USE SIGNAL ;
    PORT
      LAYER M4 ;
        RECT  237.516 33.168 237.6 33.192 ;
    END
  END rx_flit[106]
  PIN rx_flit[107]
    DIRECTION INPUT ;
    USE SIGNAL ;
    PORT
      LAYER M4 ;
        RECT  237.516 33.264 237.6 33.288 ;
    END
  END rx_flit[107]
  PIN rx_flit[108]
    DIRECTION INPUT ;
    USE SIGNAL ;
    PORT
      LAYER M4 ;
        RECT  237.516 33.36 237.6 33.384 ;
    END
  END rx_flit[108]
  PIN rx_flit[109]
    DIRECTION INPUT ;
    USE SIGNAL ;
    PORT
      LAYER M4 ;
        RECT  237.516 33.456 237.6 33.48 ;
    END
  END rx_flit[109]
  PIN rx_flit[10]
    DIRECTION INPUT ;
    USE SIGNAL ;
    PORT
      LAYER M4 ;
        RECT  237.516 27.024 237.6 27.048 ;
    END
  END rx_flit[10]
  PIN rx_flit[110]
    DIRECTION INPUT ;
    USE SIGNAL ;
    PORT
      LAYER M4 ;
        RECT  237.516 33.552 237.6 33.576 ;
    END
  END rx_flit[110]
  PIN rx_flit[111]
    DIRECTION INPUT ;
    USE SIGNAL ;
    PORT
      LAYER M4 ;
        RECT  237.516 33.648 237.6 33.672 ;
    END
  END rx_flit[111]
  PIN rx_flit[112]
    DIRECTION INPUT ;
    USE SIGNAL ;
    PORT
      LAYER M4 ;
        RECT  237.516 33.744 237.6 33.768 ;
    END
  END rx_flit[112]
  PIN rx_flit[113]
    DIRECTION INPUT ;
    USE SIGNAL ;
    PORT
      LAYER M4 ;
        RECT  237.516 33.84 237.6 33.864 ;
    END
  END rx_flit[113]
  PIN rx_flit[114]
    DIRECTION INPUT ;
    USE SIGNAL ;
    PORT
      LAYER M4 ;
        RECT  237.516 33.936 237.6 33.96 ;
    END
  END rx_flit[114]
  PIN rx_flit[115]
    DIRECTION INPUT ;
    USE SIGNAL ;
    PORT
      LAYER M4 ;
        RECT  237.516 34.032 237.6 34.056 ;
    END
  END rx_flit[115]
  PIN rx_flit[116]
    DIRECTION INPUT ;
    USE SIGNAL ;
    PORT
      LAYER M4 ;
        RECT  237.516 34.128 237.6 34.152 ;
    END
  END rx_flit[116]
  PIN rx_flit[117]
    DIRECTION INPUT ;
    USE SIGNAL ;
    PORT
      LAYER M4 ;
        RECT  237.516 34.224 237.6 34.248 ;
    END
  END rx_flit[117]
  PIN rx_flit[118]
    DIRECTION INPUT ;
    USE SIGNAL ;
    PORT
      LAYER M4 ;
        RECT  237.516 34.32 237.6 34.344 ;
    END
  END rx_flit[118]
  PIN rx_flit[119]
    DIRECTION INPUT ;
    USE SIGNAL ;
    PORT
      LAYER M4 ;
        RECT  237.516 34.416 237.6 34.44 ;
    END
  END rx_flit[119]
  PIN rx_flit[11]
    DIRECTION INPUT ;
    USE SIGNAL ;
    PORT
      LAYER M4 ;
        RECT  237.516 27.12 237.6 27.144 ;
    END
  END rx_flit[11]
  PIN rx_flit[120]
    DIRECTION INPUT ;
    USE SIGNAL ;
    PORT
      LAYER M4 ;
        RECT  237.516 34.512 237.6 34.536 ;
    END
  END rx_flit[120]
  PIN rx_flit[121]
    DIRECTION INPUT ;
    USE SIGNAL ;
    PORT
      LAYER M4 ;
        RECT  237.516 34.608 237.6 34.632 ;
    END
  END rx_flit[121]
  PIN rx_flit[122]
    DIRECTION INPUT ;
    USE SIGNAL ;
    PORT
      LAYER M4 ;
        RECT  237.516 34.704 237.6 34.728 ;
    END
  END rx_flit[122]
  PIN rx_flit[123]
    DIRECTION INPUT ;
    USE SIGNAL ;
    PORT
      LAYER M4 ;
        RECT  237.516 34.8 237.6 34.824 ;
    END
  END rx_flit[123]
  PIN rx_flit[124]
    DIRECTION INPUT ;
    USE SIGNAL ;
    PORT
      LAYER M4 ;
        RECT  237.516 34.896 237.6 34.92 ;
    END
  END rx_flit[124]
  PIN rx_flit[125]
    DIRECTION INPUT ;
    USE SIGNAL ;
    PORT
      LAYER M4 ;
        RECT  237.516 34.992 237.6 35.016 ;
    END
  END rx_flit[125]
  PIN rx_flit[126]
    DIRECTION INPUT ;
    USE SIGNAL ;
    PORT
      LAYER M4 ;
        RECT  237.516 35.088 237.6 35.112 ;
    END
  END rx_flit[126]
  PIN rx_flit[127]
    DIRECTION INPUT ;
    USE SIGNAL ;
    PORT
      LAYER M4 ;
        RECT  237.516 35.184 237.6 35.208 ;
    END
  END rx_flit[127]
  PIN rx_flit[128]
    DIRECTION INPUT ;
    USE SIGNAL ;
    PORT
      LAYER M4 ;
        RECT  237.516 29.136 237.6 29.16 ;
    END
  END rx_flit[128]
  PIN rx_flit[129]
    DIRECTION INPUT ;
    USE SIGNAL ;
    PORT
      LAYER M4 ;
        RECT  237.516 29.232 237.6 29.256 ;
    END
  END rx_flit[129]
  PIN rx_flit[12]
    DIRECTION INPUT ;
    USE SIGNAL ;
    PORT
      LAYER M4 ;
        RECT  237.516 27.216 237.6 27.24 ;
    END
  END rx_flit[12]
  PIN rx_flit[130]
    DIRECTION INPUT ;
    USE SIGNAL ;
    PORT
      LAYER M4 ;
        RECT  237.516 29.328 237.6 29.352 ;
    END
  END rx_flit[130]
  PIN rx_flit[131]
    DIRECTION INPUT ;
    USE SIGNAL ;
    PORT
      LAYER M4 ;
        RECT  237.516 29.424 237.6 29.448 ;
    END
  END rx_flit[131]
  PIN rx_flit[132]
    DIRECTION INPUT ;
    USE SIGNAL ;
    PORT
      LAYER M4 ;
        RECT  237.516 29.52 237.6 29.544 ;
    END
  END rx_flit[132]
  PIN rx_flit[133]
    DIRECTION INPUT ;
    USE SIGNAL ;
    PORT
      LAYER M4 ;
        RECT  237.516 29.616 237.6 29.64 ;
    END
  END rx_flit[133]
  PIN rx_flit[134]
    DIRECTION INPUT ;
    USE SIGNAL ;
    PORT
      LAYER M4 ;
        RECT  237.516 29.712 237.6 29.736 ;
    END
  END rx_flit[134]
  PIN rx_flit[135]
    DIRECTION INPUT ;
    USE SIGNAL ;
    PORT
      LAYER M4 ;
        RECT  237.516 29.808 237.6 29.832 ;
    END
  END rx_flit[135]
  PIN rx_flit[136]
    DIRECTION INPUT ;
    USE SIGNAL ;
    PORT
      LAYER M4 ;
        RECT  237.516 29.904 237.6 29.928 ;
    END
  END rx_flit[136]
  PIN rx_flit[137]
    DIRECTION INPUT ;
    USE SIGNAL ;
    PORT
      LAYER M4 ;
        RECT  237.516 30 237.6 30.024 ;
    END
  END rx_flit[137]
  PIN rx_flit[138]
    DIRECTION INPUT ;
    USE SIGNAL ;
    PORT
      LAYER M4 ;
        RECT  237.516 30.096 237.6 30.12 ;
    END
  END rx_flit[138]
  PIN rx_flit[139]
    DIRECTION INPUT ;
    USE SIGNAL ;
    PORT
      LAYER M4 ;
        RECT  237.516 30.192 237.6 30.216 ;
    END
  END rx_flit[139]
  PIN rx_flit[13]
    DIRECTION INPUT ;
    USE SIGNAL ;
    PORT
      LAYER M4 ;
        RECT  237.516 27.312 237.6 27.336 ;
    END
  END rx_flit[13]
  PIN rx_flit[140]
    DIRECTION INPUT ;
    USE SIGNAL ;
    PORT
      LAYER M4 ;
        RECT  237.516 30.288 237.6 30.312 ;
    END
  END rx_flit[140]
  PIN rx_flit[141]
    DIRECTION INPUT ;
    USE SIGNAL ;
    PORT
      LAYER M4 ;
        RECT  237.516 30.384 237.6 30.408 ;
    END
  END rx_flit[141]
  PIN rx_flit[142]
    DIRECTION INPUT ;
    USE SIGNAL ;
    PORT
      LAYER M4 ;
        RECT  237.516 30.48 237.6 30.504 ;
    END
  END rx_flit[142]
  PIN rx_flit[143]
    DIRECTION INPUT ;
    USE SIGNAL ;
    PORT
      LAYER M4 ;
        RECT  237.516 30.576 237.6 30.6 ;
    END
  END rx_flit[143]
  PIN rx_flit[144]
    DIRECTION INPUT ;
    USE SIGNAL ;
    PORT
      LAYER M4 ;
        RECT  237.516 30.672 237.6 30.696 ;
    END
  END rx_flit[144]
  PIN rx_flit[145]
    DIRECTION INPUT ;
    USE SIGNAL ;
    PORT
      LAYER M4 ;
        RECT  237.516 30.768 237.6 30.792 ;
    END
  END rx_flit[145]
  PIN rx_flit[146]
    DIRECTION INPUT ;
    USE SIGNAL ;
    PORT
      LAYER M4 ;
        RECT  237.516 30.864 237.6 30.888 ;
    END
  END rx_flit[146]
  PIN rx_flit[14]
    DIRECTION INPUT ;
    USE SIGNAL ;
    PORT
      LAYER M4 ;
        RECT  237.516 27.408 237.6 27.432 ;
    END
  END rx_flit[14]
  PIN rx_flit[15]
    DIRECTION INPUT ;
    USE SIGNAL ;
    PORT
      LAYER M4 ;
        RECT  237.516 27.504 237.6 27.528 ;
    END
  END rx_flit[15]
  PIN rx_flit[16]
    DIRECTION INPUT ;
    USE SIGNAL ;
    PORT
      LAYER M4 ;
        RECT  237.516 27.6 237.6 27.624 ;
    END
  END rx_flit[16]
  PIN rx_flit[17]
    DIRECTION INPUT ;
    USE SIGNAL ;
    PORT
      LAYER M4 ;
        RECT  237.516 27.696 237.6 27.72 ;
    END
  END rx_flit[17]
  PIN rx_flit[18]
    DIRECTION INPUT ;
    USE SIGNAL ;
    PORT
      LAYER M4 ;
        RECT  237.516 27.792 237.6 27.816 ;
    END
  END rx_flit[18]
  PIN rx_flit[19]
    DIRECTION INPUT ;
    USE SIGNAL ;
    PORT
      LAYER M4 ;
        RECT  237.516 27.888 237.6 27.912 ;
    END
  END rx_flit[19]
  PIN rx_flit[1]
    DIRECTION INPUT ;
    USE SIGNAL ;
    PORT
      LAYER M4 ;
        RECT  237.516 26.16 237.6 26.184 ;
    END
  END rx_flit[1]
  PIN rx_flit[20]
    DIRECTION INPUT ;
    USE SIGNAL ;
    PORT
      LAYER M4 ;
        RECT  237.516 27.984 237.6 28.008 ;
    END
  END rx_flit[20]
  PIN rx_flit[21]
    DIRECTION INPUT ;
    USE SIGNAL ;
    PORT
      LAYER M4 ;
        RECT  237.516 28.08 237.6 28.104 ;
    END
  END rx_flit[21]
  PIN rx_flit[22]
    DIRECTION INPUT ;
    USE SIGNAL ;
    PORT
      LAYER M4 ;
        RECT  237.516 28.176 237.6 28.2 ;
    END
  END rx_flit[22]
  PIN rx_flit[23]
    DIRECTION INPUT ;
    USE SIGNAL ;
    PORT
      LAYER M4 ;
        RECT  237.516 28.272 237.6 28.296 ;
    END
  END rx_flit[23]
  PIN rx_flit[24]
    DIRECTION INPUT ;
    USE SIGNAL ;
    PORT
      LAYER M4 ;
        RECT  237.516 28.368 237.6 28.392 ;
    END
  END rx_flit[24]
  PIN rx_flit[25]
    DIRECTION INPUT ;
    USE SIGNAL ;
    PORT
      LAYER M4 ;
        RECT  237.516 28.464 237.6 28.488 ;
    END
  END rx_flit[25]
  PIN rx_flit[26]
    DIRECTION INPUT ;
    USE SIGNAL ;
    PORT
      LAYER M4 ;
        RECT  237.516 28.56 237.6 28.584 ;
    END
  END rx_flit[26]
  PIN rx_flit[27]
    DIRECTION INPUT ;
    USE SIGNAL ;
    PORT
      LAYER M4 ;
        RECT  237.516 28.656 237.6 28.68 ;
    END
  END rx_flit[27]
  PIN rx_flit[28]
    DIRECTION INPUT ;
    USE SIGNAL ;
    PORT
      LAYER M4 ;
        RECT  237.516 28.752 237.6 28.776 ;
    END
  END rx_flit[28]
  PIN rx_flit[29]
    DIRECTION INPUT ;
    USE SIGNAL ;
    PORT
      LAYER M4 ;
        RECT  237.516 28.848 237.6 28.872 ;
    END
  END rx_flit[29]
  PIN rx_flit[2]
    DIRECTION INPUT ;
    USE SIGNAL ;
    PORT
      LAYER M4 ;
        RECT  237.516 26.256 237.6 26.28 ;
    END
  END rx_flit[2]
  PIN rx_flit[30]
    DIRECTION INPUT ;
    USE SIGNAL ;
    PORT
      LAYER M4 ;
        RECT  237.516 28.944 237.6 28.968 ;
    END
  END rx_flit[30]
  PIN rx_flit[31]
    DIRECTION INPUT ;
    USE SIGNAL ;
    PORT
      LAYER M4 ;
        RECT  237.516 29.04 237.6 29.064 ;
    END
  END rx_flit[31]
  PIN rx_flit[32]
    DIRECTION INPUT ;
    USE SIGNAL ;
    PORT
      LAYER M4 ;
        RECT  237.516 45.264 237.6 45.288 ;
    END
  END rx_flit[32]
  PIN rx_flit[33]
    DIRECTION INPUT ;
    USE SIGNAL ;
    PORT
      LAYER M4 ;
        RECT  237.516 45.36 237.6 45.384 ;
    END
  END rx_flit[33]
  PIN rx_flit[34]
    DIRECTION INPUT ;
    USE SIGNAL ;
    PORT
      LAYER M4 ;
        RECT  237.516 45.456 237.6 45.48 ;
    END
  END rx_flit[34]
  PIN rx_flit[35]
    DIRECTION INPUT ;
    USE SIGNAL ;
    PORT
      LAYER M4 ;
        RECT  237.516 45.552 237.6 45.576 ;
    END
  END rx_flit[35]
  PIN rx_flit[36]
    DIRECTION INPUT ;
    USE SIGNAL ;
    PORT
      LAYER M4 ;
        RECT  237.516 45.648 237.6 45.672 ;
    END
  END rx_flit[36]
  PIN rx_flit[37]
    DIRECTION INPUT ;
    USE SIGNAL ;
    PORT
      LAYER M4 ;
        RECT  237.516 45.744 237.6 45.768 ;
    END
  END rx_flit[37]
  PIN rx_flit[38]
    DIRECTION INPUT ;
    USE SIGNAL ;
    PORT
      LAYER M4 ;
        RECT  237.516 45.84 237.6 45.864 ;
    END
  END rx_flit[38]
  PIN rx_flit[39]
    DIRECTION INPUT ;
    USE SIGNAL ;
    PORT
      LAYER M4 ;
        RECT  237.516 45.936 237.6 45.96 ;
    END
  END rx_flit[39]
  PIN rx_flit[3]
    DIRECTION INPUT ;
    USE SIGNAL ;
    PORT
      LAYER M4 ;
        RECT  237.516 26.352 237.6 26.376 ;
    END
  END rx_flit[3]
  PIN rx_flit[40]
    DIRECTION INPUT ;
    USE SIGNAL ;
    PORT
      LAYER M4 ;
        RECT  237.516 46.032 237.6 46.056 ;
    END
  END rx_flit[40]
  PIN rx_flit[41]
    DIRECTION INPUT ;
    USE SIGNAL ;
    PORT
      LAYER M4 ;
        RECT  237.516 46.128 237.6 46.152 ;
    END
  END rx_flit[41]
  PIN rx_flit[42]
    DIRECTION INPUT ;
    USE SIGNAL ;
    PORT
      LAYER M4 ;
        RECT  237.516 46.224 237.6 46.248 ;
    END
  END rx_flit[42]
  PIN rx_flit[43]
    DIRECTION INPUT ;
    USE SIGNAL ;
    PORT
      LAYER M4 ;
        RECT  237.516 46.32 237.6 46.344 ;
    END
  END rx_flit[43]
  PIN rx_flit[44]
    DIRECTION INPUT ;
    USE SIGNAL ;
    PORT
      LAYER M4 ;
        RECT  237.516 46.416 237.6 46.44 ;
    END
  END rx_flit[44]
  PIN rx_flit[45]
    DIRECTION INPUT ;
    USE SIGNAL ;
    PORT
      LAYER M4 ;
        RECT  237.516 46.512 237.6 46.536 ;
    END
  END rx_flit[45]
  PIN rx_flit[46]
    DIRECTION INPUT ;
    USE SIGNAL ;
    PORT
      LAYER M4 ;
        RECT  237.516 46.608 237.6 46.632 ;
    END
  END rx_flit[46]
  PIN rx_flit[47]
    DIRECTION INPUT ;
    USE SIGNAL ;
    PORT
      LAYER M4 ;
        RECT  237.516 46.704 237.6 46.728 ;
    END
  END rx_flit[47]
  PIN rx_flit[48]
    DIRECTION INPUT ;
    USE SIGNAL ;
    PORT
      LAYER M4 ;
        RECT  237.516 46.8 237.6 46.824 ;
    END
  END rx_flit[48]
  PIN rx_flit[49]
    DIRECTION INPUT ;
    USE SIGNAL ;
    PORT
      LAYER M4 ;
        RECT  237.516 46.896 237.6 46.92 ;
    END
  END rx_flit[49]
  PIN rx_flit[4]
    DIRECTION INPUT ;
    USE SIGNAL ;
    PORT
      LAYER M4 ;
        RECT  237.516 26.448 237.6 26.472 ;
    END
  END rx_flit[4]
  PIN rx_flit[50]
    DIRECTION INPUT ;
    USE SIGNAL ;
    PORT
      LAYER M4 ;
        RECT  237.516 46.992 237.6 47.016 ;
    END
  END rx_flit[50]
  PIN rx_flit[51]
    DIRECTION INPUT ;
    USE SIGNAL ;
    PORT
      LAYER M4 ;
        RECT  237.516 47.088 237.6 47.112 ;
    END
  END rx_flit[51]
  PIN rx_flit[52]
    DIRECTION INPUT ;
    USE SIGNAL ;
    PORT
      LAYER M4 ;
        RECT  237.516 47.184 237.6 47.208 ;
    END
  END rx_flit[52]
  PIN rx_flit[53]
    DIRECTION INPUT ;
    USE SIGNAL ;
    PORT
      LAYER M4 ;
        RECT  237.516 47.28 237.6 47.304 ;
    END
  END rx_flit[53]
  PIN rx_flit[54]
    DIRECTION INPUT ;
    USE SIGNAL ;
    PORT
      LAYER M4 ;
        RECT  237.516 47.376 237.6 47.4 ;
    END
  END rx_flit[54]
  PIN rx_flit[55]
    DIRECTION INPUT ;
    USE SIGNAL ;
    PORT
      LAYER M4 ;
        RECT  237.516 47.472 237.6 47.496 ;
    END
  END rx_flit[55]
  PIN rx_flit[56]
    DIRECTION INPUT ;
    USE SIGNAL ;
    PORT
      LAYER M4 ;
        RECT  237.516 47.568 237.6 47.592 ;
    END
  END rx_flit[56]
  PIN rx_flit[57]
    DIRECTION INPUT ;
    USE SIGNAL ;
    PORT
      LAYER M4 ;
        RECT  237.516 47.664 237.6 47.688 ;
    END
  END rx_flit[57]
  PIN rx_flit[58]
    DIRECTION INPUT ;
    USE SIGNAL ;
    PORT
      LAYER M4 ;
        RECT  237.516 47.76 237.6 47.784 ;
    END
  END rx_flit[58]
  PIN rx_flit[59]
    DIRECTION INPUT ;
    USE SIGNAL ;
    PORT
      LAYER M4 ;
        RECT  237.516 47.856 237.6 47.88 ;
    END
  END rx_flit[59]
  PIN rx_flit[5]
    DIRECTION INPUT ;
    USE SIGNAL ;
    PORT
      LAYER M4 ;
        RECT  237.516 26.544 237.6 26.568 ;
    END
  END rx_flit[5]
  PIN rx_flit[60]
    DIRECTION INPUT ;
    USE SIGNAL ;
    PORT
      LAYER M4 ;
        RECT  237.516 47.952 237.6 47.976 ;
    END
  END rx_flit[60]
  PIN rx_flit[61]
    DIRECTION INPUT ;
    USE SIGNAL ;
    PORT
      LAYER M4 ;
        RECT  237.516 48.048 237.6 48.072 ;
    END
  END rx_flit[61]
  PIN rx_flit[62]
    DIRECTION INPUT ;
    USE SIGNAL ;
    PORT
      LAYER M4 ;
        RECT  237.516 48.144 237.6 48.168 ;
    END
  END rx_flit[62]
  PIN rx_flit[63]
    DIRECTION INPUT ;
    USE SIGNAL ;
    PORT
      LAYER M4 ;
        RECT  237.516 48.24 237.6 48.264 ;
    END
  END rx_flit[63]
  PIN rx_flit[64]
    DIRECTION INPUT ;
    USE SIGNAL ;
    PORT
      LAYER M4 ;
        RECT  237.516 48.336 237.6 48.36 ;
    END
  END rx_flit[64]
  PIN rx_flit[65]
    DIRECTION INPUT ;
    USE SIGNAL ;
    PORT
      LAYER M4 ;
        RECT  237.516 48.432 237.6 48.456 ;
    END
  END rx_flit[65]
  PIN rx_flit[66]
    DIRECTION INPUT ;
    USE SIGNAL ;
    PORT
      LAYER M4 ;
        RECT  237.516 48.528 237.6 48.552 ;
    END
  END rx_flit[66]
  PIN rx_flit[67]
    DIRECTION INPUT ;
    USE SIGNAL ;
    PORT
      LAYER M4 ;
        RECT  237.516 48.624 237.6 48.648 ;
    END
  END rx_flit[67]
  PIN rx_flit[68]
    DIRECTION INPUT ;
    USE SIGNAL ;
    PORT
      LAYER M4 ;
        RECT  237.516 48.72 237.6 48.744 ;
    END
  END rx_flit[68]
  PIN rx_flit[69]
    DIRECTION INPUT ;
    USE SIGNAL ;
    PORT
      LAYER M4 ;
        RECT  237.516 48.816 237.6 48.84 ;
    END
  END rx_flit[69]
  PIN rx_flit[6]
    DIRECTION INPUT ;
    USE SIGNAL ;
    PORT
      LAYER M4 ;
        RECT  237.516 26.64 237.6 26.664 ;
    END
  END rx_flit[6]
  PIN rx_flit[70]
    DIRECTION INPUT ;
    USE SIGNAL ;
    PORT
      LAYER M4 ;
        RECT  237.516 48.912 237.6 48.936 ;
    END
  END rx_flit[70]
  PIN rx_flit[71]
    DIRECTION INPUT ;
    USE SIGNAL ;
    PORT
      LAYER M4 ;
        RECT  237.516 49.008 237.6 49.032 ;
    END
  END rx_flit[71]
  PIN rx_flit[72]
    DIRECTION INPUT ;
    USE SIGNAL ;
    PORT
      LAYER M4 ;
        RECT  237.516 49.104 237.6 49.128 ;
    END
  END rx_flit[72]
  PIN rx_flit[73]
    DIRECTION INPUT ;
    USE SIGNAL ;
    PORT
      LAYER M4 ;
        RECT  237.516 49.2 237.6 49.224 ;
    END
  END rx_flit[73]
  PIN rx_flit[74]
    DIRECTION INPUT ;
    USE SIGNAL ;
    PORT
      LAYER M4 ;
        RECT  237.516 49.296 237.6 49.32 ;
    END
  END rx_flit[74]
  PIN rx_flit[75]
    DIRECTION INPUT ;
    USE SIGNAL ;
    PORT
      LAYER M4 ;
        RECT  237.516 49.392 237.6 49.416 ;
    END
  END rx_flit[75]
  PIN rx_flit[76]
    DIRECTION INPUT ;
    USE SIGNAL ;
    PORT
      LAYER M4 ;
        RECT  237.516 49.488 237.6 49.512 ;
    END
  END rx_flit[76]
  PIN rx_flit[77]
    DIRECTION INPUT ;
    USE SIGNAL ;
    PORT
      LAYER M4 ;
        RECT  237.516 49.584 237.6 49.608 ;
    END
  END rx_flit[77]
  PIN rx_flit[78]
    DIRECTION INPUT ;
    USE SIGNAL ;
    PORT
      LAYER M4 ;
        RECT  237.516 49.68 237.6 49.704 ;
    END
  END rx_flit[78]
  PIN rx_flit[79]
    DIRECTION INPUT ;
    USE SIGNAL ;
    PORT
      LAYER M4 ;
        RECT  237.516 49.776 237.6 49.8 ;
    END
  END rx_flit[79]
  PIN rx_flit[7]
    DIRECTION INPUT ;
    USE SIGNAL ;
    PORT
      LAYER M4 ;
        RECT  237.516 26.736 237.6 26.76 ;
    END
  END rx_flit[7]
  PIN rx_flit[80]
    DIRECTION INPUT ;
    USE SIGNAL ;
    PORT
      LAYER M4 ;
        RECT  237.516 49.872 237.6 49.896 ;
    END
  END rx_flit[80]
  PIN rx_flit[81]
    DIRECTION INPUT ;
    USE SIGNAL ;
    PORT
      LAYER M4 ;
        RECT  237.516 49.968 237.6 49.992 ;
    END
  END rx_flit[81]
  PIN rx_flit[82]
    DIRECTION INPUT ;
    USE SIGNAL ;
    PORT
      LAYER M4 ;
        RECT  237.516 50.064 237.6 50.088 ;
    END
  END rx_flit[82]
  PIN rx_flit[83]
    DIRECTION INPUT ;
    USE SIGNAL ;
    PORT
      LAYER M4 ;
        RECT  237.516 50.16 237.6 50.184 ;
    END
  END rx_flit[83]
  PIN rx_flit[84]
    DIRECTION INPUT ;
    USE SIGNAL ;
    PORT
      LAYER M4 ;
        RECT  237.516 50.256 237.6 50.28 ;
    END
  END rx_flit[84]
  PIN rx_flit[85]
    DIRECTION INPUT ;
    USE SIGNAL ;
    PORT
      LAYER M4 ;
        RECT  237.516 50.352 237.6 50.376 ;
    END
  END rx_flit[85]
  PIN rx_flit[86]
    DIRECTION INPUT ;
    USE SIGNAL ;
    PORT
      LAYER M4 ;
        RECT  237.516 50.448 237.6 50.472 ;
    END
  END rx_flit[86]
  PIN rx_flit[87]
    DIRECTION INPUT ;
    USE SIGNAL ;
    PORT
      LAYER M4 ;
        RECT  237.516 50.544 237.6 50.568 ;
    END
  END rx_flit[87]
  PIN rx_flit[88]
    DIRECTION INPUT ;
    USE SIGNAL ;
    PORT
      LAYER M4 ;
        RECT  237.516 50.64 237.6 50.664 ;
    END
  END rx_flit[88]
  PIN rx_flit[89]
    DIRECTION INPUT ;
    USE SIGNAL ;
    PORT
      LAYER M4 ;
        RECT  237.516 50.736 237.6 50.76 ;
    END
  END rx_flit[89]
  PIN rx_flit[8]
    DIRECTION INPUT ;
    USE SIGNAL ;
    PORT
      LAYER M4 ;
        RECT  237.516 26.832 237.6 26.856 ;
    END
  END rx_flit[8]
  PIN rx_flit[90]
    DIRECTION INPUT ;
    USE SIGNAL ;
    PORT
      LAYER M4 ;
        RECT  237.516 50.832 237.6 50.856 ;
    END
  END rx_flit[90]
  PIN rx_flit[91]
    DIRECTION INPUT ;
    USE SIGNAL ;
    PORT
      LAYER M4 ;
        RECT  237.516 50.928 237.6 50.952 ;
    END
  END rx_flit[91]
  PIN rx_flit[92]
    DIRECTION INPUT ;
    USE SIGNAL ;
    PORT
      LAYER M4 ;
        RECT  237.516 51.024 237.6 51.048 ;
    END
  END rx_flit[92]
  PIN rx_flit[93]
    DIRECTION INPUT ;
    USE SIGNAL ;
    PORT
      LAYER M4 ;
        RECT  237.516 51.12 237.6 51.144 ;
    END
  END rx_flit[93]
  PIN rx_flit[94]
    DIRECTION INPUT ;
    USE SIGNAL ;
    PORT
      LAYER M4 ;
        RECT  237.516 51.216 237.6 51.24 ;
    END
  END rx_flit[94]
  PIN rx_flit[95]
    DIRECTION INPUT ;
    USE SIGNAL ;
    PORT
      LAYER M4 ;
        RECT  237.516 51.312 237.6 51.336 ;
    END
  END rx_flit[95]
  PIN rx_flit[96]
    DIRECTION INPUT ;
    USE SIGNAL ;
    PORT
      LAYER M4 ;
        RECT  237.516 32.208 237.6 32.232 ;
    END
  END rx_flit[96]
  PIN rx_flit[97]
    DIRECTION INPUT ;
    USE SIGNAL ;
    PORT
      LAYER M4 ;
        RECT  237.516 32.304 237.6 32.328 ;
    END
  END rx_flit[97]
  PIN rx_flit[98]
    DIRECTION INPUT ;
    USE SIGNAL ;
    PORT
      LAYER M4 ;
        RECT  237.516 32.4 237.6 32.424 ;
    END
  END rx_flit[98]
  PIN rx_flit[99]
    DIRECTION INPUT ;
    USE SIGNAL ;
    PORT
      LAYER M4 ;
        RECT  237.516 32.496 237.6 32.52 ;
    END
  END rx_flit[99]
  PIN rx_flit[9]
    DIRECTION INPUT ;
    USE SIGNAL ;
    PORT
      LAYER M4 ;
        RECT  237.516 26.928 237.6 26.952 ;
    END
  END rx_flit[9]
  PIN rx_v
    DIRECTION INPUT ;
    USE SIGNAL ;
    PORT
      LAYER M4 ;
        RECT  237.516 30.96 237.6 30.984 ;
    END
  END rx_v
  PIN tx_flit[0]
    DIRECTION OUTPUT ;
    USE SIGNAL ;
    PORT
      LAYER M4 ;
        RECT  237.516 31.056 237.6 31.08 ;
    END
  END tx_flit[0]
  PIN tx_flit[100]
    DIRECTION OUTPUT ;
    USE SIGNAL ;
    PORT
      LAYER M4 ;
        RECT  237.516 63.696 237.6 63.72 ;
    END
  END tx_flit[100]
  PIN tx_flit[101]
    DIRECTION OUTPUT ;
    USE SIGNAL ;
    PORT
      LAYER M4 ;
        RECT  237.516 63.792 237.6 63.816 ;
    END
  END tx_flit[101]
  PIN tx_flit[102]
    DIRECTION OUTPUT ;
    USE SIGNAL ;
    PORT
      LAYER M4 ;
        RECT  237.516 63.888 237.6 63.912 ;
    END
  END tx_flit[102]
  PIN tx_flit[103]
    DIRECTION OUTPUT ;
    USE SIGNAL ;
    PORT
      LAYER M4 ;
        RECT  237.516 63.984 237.6 64.008 ;
    END
  END tx_flit[103]
  PIN tx_flit[104]
    DIRECTION OUTPUT ;
    USE SIGNAL ;
    PORT
      LAYER M4 ;
        RECT  237.516 64.08 237.6 64.104 ;
    END
  END tx_flit[104]
  PIN tx_flit[105]
    DIRECTION OUTPUT ;
    USE SIGNAL ;
    PORT
      LAYER M4 ;
        RECT  237.516 64.176 237.6 64.2 ;
    END
  END tx_flit[105]
  PIN tx_flit[106]
    DIRECTION OUTPUT ;
    USE SIGNAL ;
    PORT
      LAYER M4 ;
        RECT  237.516 64.272 237.6 64.296 ;
    END
  END tx_flit[106]
  PIN tx_flit[107]
    DIRECTION OUTPUT ;
    USE SIGNAL ;
    PORT
      LAYER M4 ;
        RECT  237.516 64.368 237.6 64.392 ;
    END
  END tx_flit[107]
  PIN tx_flit[108]
    DIRECTION OUTPUT ;
    USE SIGNAL ;
    PORT
      LAYER M4 ;
        RECT  237.516 9.936 237.6 9.96 ;
    END
  END tx_flit[108]
  PIN tx_flit[109]
    DIRECTION OUTPUT ;
    USE SIGNAL ;
    PORT
      LAYER M4 ;
        RECT  237.516 10.032 237.6 10.056 ;
    END
  END tx_flit[109]
  PIN tx_flit[10]
    DIRECTION OUTPUT ;
    USE SIGNAL ;
    PORT
      LAYER M4 ;
        RECT  237.516 32.016 237.6 32.04 ;
    END
  END tx_flit[10]
  PIN tx_flit[110]
    DIRECTION OUTPUT ;
    USE SIGNAL ;
    PORT
      LAYER M4 ;
        RECT  237.516 10.128 237.6 10.152 ;
    END
  END tx_flit[110]
  PIN tx_flit[111]
    DIRECTION OUTPUT ;
    USE SIGNAL ;
    PORT
      LAYER M4 ;
        RECT  237.516 10.224 237.6 10.248 ;
    END
  END tx_flit[111]
  PIN tx_flit[112]
    DIRECTION OUTPUT ;
    USE SIGNAL ;
    PORT
      LAYER M4 ;
        RECT  237.516 10.32 237.6 10.344 ;
    END
  END tx_flit[112]
  PIN tx_flit[113]
    DIRECTION OUTPUT ;
    USE SIGNAL ;
    PORT
      LAYER M4 ;
        RECT  237.516 10.416 237.6 10.44 ;
    END
  END tx_flit[113]
  PIN tx_flit[114]
    DIRECTION OUTPUT ;
    USE SIGNAL ;
    PORT
      LAYER M4 ;
        RECT  237.516 10.512 237.6 10.536 ;
    END
  END tx_flit[114]
  PIN tx_flit[115]
    DIRECTION OUTPUT ;
    USE SIGNAL ;
    PORT
      LAYER M4 ;
        RECT  237.516 10.608 237.6 10.632 ;
    END
  END tx_flit[115]
  PIN tx_flit[116]
    DIRECTION OUTPUT ;
    USE SIGNAL ;
    PORT
      LAYER M4 ;
        RECT  237.516 10.704 237.6 10.728 ;
    END
  END tx_flit[116]
  PIN tx_flit[117]
    DIRECTION OUTPUT ;
    USE SIGNAL ;
    PORT
      LAYER M4 ;
        RECT  237.516 10.8 237.6 10.824 ;
    END
  END tx_flit[117]
  PIN tx_flit[118]
    DIRECTION OUTPUT ;
    USE SIGNAL ;
    PORT
      LAYER M4 ;
        RECT  237.516 10.896 237.6 10.92 ;
    END
  END tx_flit[118]
  PIN tx_flit[119]
    DIRECTION OUTPUT ;
    USE SIGNAL ;
    PORT
      LAYER M4 ;
        RECT  237.516 10.992 237.6 11.016 ;
    END
  END tx_flit[119]
  PIN tx_flit[11]
    DIRECTION OUTPUT ;
    USE SIGNAL ;
    PORT
      LAYER M4 ;
        RECT  237.516 32.112 237.6 32.136 ;
    END
  END tx_flit[11]
  PIN tx_flit[120]
    DIRECTION OUTPUT ;
    USE SIGNAL ;
    PORT
      LAYER M4 ;
        RECT  237.516 11.088 237.6 11.112 ;
    END
  END tx_flit[120]
  PIN tx_flit[121]
    DIRECTION OUTPUT ;
    USE SIGNAL ;
    PORT
      LAYER M4 ;
        RECT  237.516 11.184 237.6 11.208 ;
    END
  END tx_flit[121]
  PIN tx_flit[122]
    DIRECTION OUTPUT ;
    USE SIGNAL ;
    PORT
      LAYER M4 ;
        RECT  237.516 11.28 237.6 11.304 ;
    END
  END tx_flit[122]
  PIN tx_flit[123]
    DIRECTION OUTPUT ;
    USE SIGNAL ;
    PORT
      LAYER M4 ;
        RECT  237.516 11.376 237.6 11.4 ;
    END
  END tx_flit[123]
  PIN tx_flit[124]
    DIRECTION OUTPUT ;
    USE SIGNAL ;
    PORT
      LAYER M4 ;
        RECT  237.516 11.472 237.6 11.496 ;
    END
  END tx_flit[124]
  PIN tx_flit[125]
    DIRECTION OUTPUT ;
    USE SIGNAL ;
    PORT
      LAYER M4 ;
        RECT  237.516 11.568 237.6 11.592 ;
    END
  END tx_flit[125]
  PIN tx_flit[126]
    DIRECTION OUTPUT ;
    USE SIGNAL ;
    PORT
      LAYER M4 ;
        RECT  237.516 11.664 237.6 11.688 ;
    END
  END tx_flit[126]
  PIN tx_flit[127]
    DIRECTION OUTPUT ;
    USE SIGNAL ;
    PORT
      LAYER M4 ;
        RECT  237.516 11.76 237.6 11.784 ;
    END
  END tx_flit[127]
  PIN tx_flit[128]
    DIRECTION OUTPUT ;
    USE SIGNAL ;
    PORT
      LAYER M4 ;
        RECT  237.516 11.856 237.6 11.88 ;
    END
  END tx_flit[128]
  PIN tx_flit[129]
    DIRECTION OUTPUT ;
    USE SIGNAL ;
    PORT
      LAYER M4 ;
        RECT  237.516 11.952 237.6 11.976 ;
    END
  END tx_flit[129]
  PIN tx_flit[12]
    DIRECTION OUTPUT ;
    USE SIGNAL ;
    PORT
      LAYER M4 ;
        RECT  237.516 54.48 237.6 54.504 ;
    END
  END tx_flit[12]
  PIN tx_flit[130]
    DIRECTION OUTPUT ;
    USE SIGNAL ;
    PORT
      LAYER M4 ;
        RECT  237.516 12.048 237.6 12.072 ;
    END
  END tx_flit[130]
  PIN tx_flit[131]
    DIRECTION OUTPUT ;
    USE SIGNAL ;
    PORT
      LAYER M4 ;
        RECT  237.516 12.144 237.6 12.168 ;
    END
  END tx_flit[131]
  PIN tx_flit[132]
    DIRECTION OUTPUT ;
    USE SIGNAL ;
    PORT
      LAYER M4 ;
        RECT  237.516 12.24 237.6 12.264 ;
    END
  END tx_flit[132]
  PIN tx_flit[133]
    DIRECTION OUTPUT ;
    USE SIGNAL ;
    PORT
      LAYER M4 ;
        RECT  237.516 12.336 237.6 12.36 ;
    END
  END tx_flit[133]
  PIN tx_flit[134]
    DIRECTION OUTPUT ;
    USE SIGNAL ;
    PORT
      LAYER M4 ;
        RECT  237.516 12.432 237.6 12.456 ;
    END
  END tx_flit[134]
  PIN tx_flit[135]
    DIRECTION OUTPUT ;
    USE SIGNAL ;
    PORT
      LAYER M4 ;
        RECT  237.516 12.528 237.6 12.552 ;
    END
  END tx_flit[135]
  PIN tx_flit[136]
    DIRECTION OUTPUT ;
    USE SIGNAL ;
    PORT
      LAYER M4 ;
        RECT  237.516 12.624 237.6 12.648 ;
    END
  END tx_flit[136]
  PIN tx_flit[137]
    DIRECTION OUTPUT ;
    USE SIGNAL ;
    PORT
      LAYER M4 ;
        RECT  237.516 12.72 237.6 12.744 ;
    END
  END tx_flit[137]
  PIN tx_flit[138]
    DIRECTION OUTPUT ;
    USE SIGNAL ;
    PORT
      LAYER M4 ;
        RECT  237.516 12.816 237.6 12.84 ;
    END
  END tx_flit[138]
  PIN tx_flit[139]
    DIRECTION OUTPUT ;
    USE SIGNAL ;
    PORT
      LAYER M4 ;
        RECT  237.516 12.912 237.6 12.936 ;
    END
  END tx_flit[139]
  PIN tx_flit[13]
    DIRECTION OUTPUT ;
    USE SIGNAL ;
    PORT
      LAYER M4 ;
        RECT  237.516 54.576 237.6 54.6 ;
    END
  END tx_flit[13]
  PIN tx_flit[140]
    DIRECTION OUTPUT ;
    USE SIGNAL ;
    PORT
      LAYER M4 ;
        RECT  237.516 16.08 237.6 16.104 ;
    END
  END tx_flit[140]
  PIN tx_flit[141]
    DIRECTION OUTPUT ;
    USE SIGNAL ;
    PORT
      LAYER M4 ;
        RECT  237.516 16.176 237.6 16.2 ;
    END
  END tx_flit[141]
  PIN tx_flit[142]
    DIRECTION OUTPUT ;
    USE SIGNAL ;
    PORT
      LAYER M4 ;
        RECT  237.516 16.272 237.6 16.296 ;
    END
  END tx_flit[142]
  PIN tx_flit[143]
    DIRECTION OUTPUT ;
    USE SIGNAL ;
    PORT
      LAYER M4 ;
        RECT  237.516 16.368 237.6 16.392 ;
    END
  END tx_flit[143]
  PIN tx_flit[144]
    DIRECTION OUTPUT ;
    USE SIGNAL ;
    PORT
      LAYER M4 ;
        RECT  237.516 16.464 237.6 16.488 ;
    END
  END tx_flit[144]
  PIN tx_flit[145]
    DIRECTION OUTPUT ;
    USE SIGNAL ;
    PORT
      LAYER M4 ;
        RECT  237.516 16.56 237.6 16.584 ;
    END
  END tx_flit[145]
  PIN tx_flit[146]
    DIRECTION OUTPUT ;
    USE SIGNAL ;
    PORT
      LAYER M4 ;
        RECT  237.516 16.656 237.6 16.68 ;
    END
  END tx_flit[146]
  PIN tx_flit[14]
    DIRECTION OUTPUT ;
    USE SIGNAL ;
    PORT
      LAYER M4 ;
        RECT  237.516 54.672 237.6 54.696 ;
    END
  END tx_flit[14]
  PIN tx_flit[15]
    DIRECTION OUTPUT ;
    USE SIGNAL ;
    PORT
      LAYER M4 ;
        RECT  237.516 54.768 237.6 54.792 ;
    END
  END tx_flit[15]
  PIN tx_flit[16]
    DIRECTION OUTPUT ;
    USE SIGNAL ;
    PORT
      LAYER M4 ;
        RECT  237.516 54.864 237.6 54.888 ;
    END
  END tx_flit[16]
  PIN tx_flit[17]
    DIRECTION OUTPUT ;
    USE SIGNAL ;
    PORT
      LAYER M4 ;
        RECT  237.516 54.96 237.6 54.984 ;
    END
  END tx_flit[17]
  PIN tx_flit[18]
    DIRECTION OUTPUT ;
    USE SIGNAL ;
    PORT
      LAYER M4 ;
        RECT  237.516 55.056 237.6 55.08 ;
    END
  END tx_flit[18]
  PIN tx_flit[19]
    DIRECTION OUTPUT ;
    USE SIGNAL ;
    PORT
      LAYER M4 ;
        RECT  237.516 55.152 237.6 55.176 ;
    END
  END tx_flit[19]
  PIN tx_flit[1]
    DIRECTION OUTPUT ;
    USE SIGNAL ;
    PORT
      LAYER M4 ;
        RECT  237.516 31.152 237.6 31.176 ;
    END
  END tx_flit[1]
  PIN tx_flit[20]
    DIRECTION OUTPUT ;
    USE SIGNAL ;
    PORT
      LAYER M4 ;
        RECT  237.516 55.248 237.6 55.272 ;
    END
  END tx_flit[20]
  PIN tx_flit[21]
    DIRECTION OUTPUT ;
    USE SIGNAL ;
    PORT
      LAYER M4 ;
        RECT  237.516 55.344 237.6 55.368 ;
    END
  END tx_flit[21]
  PIN tx_flit[22]
    DIRECTION OUTPUT ;
    USE SIGNAL ;
    PORT
      LAYER M4 ;
        RECT  237.516 55.44 237.6 55.464 ;
    END
  END tx_flit[22]
  PIN tx_flit[23]
    DIRECTION OUTPUT ;
    USE SIGNAL ;
    PORT
      LAYER M4 ;
        RECT  237.516 55.536 237.6 55.56 ;
    END
  END tx_flit[23]
  PIN tx_flit[24]
    DIRECTION OUTPUT ;
    USE SIGNAL ;
    PORT
      LAYER M4 ;
        RECT  237.516 55.632 237.6 55.656 ;
    END
  END tx_flit[24]
  PIN tx_flit[25]
    DIRECTION OUTPUT ;
    USE SIGNAL ;
    PORT
      LAYER M4 ;
        RECT  237.516 55.728 237.6 55.752 ;
    END
  END tx_flit[25]
  PIN tx_flit[26]
    DIRECTION OUTPUT ;
    USE SIGNAL ;
    PORT
      LAYER M4 ;
        RECT  237.516 55.824 237.6 55.848 ;
    END
  END tx_flit[26]
  PIN tx_flit[27]
    DIRECTION OUTPUT ;
    USE SIGNAL ;
    PORT
      LAYER M4 ;
        RECT  237.516 55.92 237.6 55.944 ;
    END
  END tx_flit[27]
  PIN tx_flit[28]
    DIRECTION OUTPUT ;
    USE SIGNAL ;
    PORT
      LAYER M4 ;
        RECT  237.516 56.016 237.6 56.04 ;
    END
  END tx_flit[28]
  PIN tx_flit[29]
    DIRECTION OUTPUT ;
    USE SIGNAL ;
    PORT
      LAYER M4 ;
        RECT  237.516 56.112 237.6 56.136 ;
    END
  END tx_flit[29]
  PIN tx_flit[2]
    DIRECTION OUTPUT ;
    USE SIGNAL ;
    PORT
      LAYER M4 ;
        RECT  237.516 31.248 237.6 31.272 ;
    END
  END tx_flit[2]
  PIN tx_flit[30]
    DIRECTION OUTPUT ;
    USE SIGNAL ;
    PORT
      LAYER M4 ;
        RECT  237.516 56.208 237.6 56.232 ;
    END
  END tx_flit[30]
  PIN tx_flit[31]
    DIRECTION OUTPUT ;
    USE SIGNAL ;
    PORT
      LAYER M4 ;
        RECT  237.516 56.304 237.6 56.328 ;
    END
  END tx_flit[31]
  PIN tx_flit[32]
    DIRECTION OUTPUT ;
    USE SIGNAL ;
    PORT
      LAYER M4 ;
        RECT  237.516 56.4 237.6 56.424 ;
    END
  END tx_flit[32]
  PIN tx_flit[33]
    DIRECTION OUTPUT ;
    USE SIGNAL ;
    PORT
      LAYER M4 ;
        RECT  237.516 56.496 237.6 56.52 ;
    END
  END tx_flit[33]
  PIN tx_flit[34]
    DIRECTION OUTPUT ;
    USE SIGNAL ;
    PORT
      LAYER M4 ;
        RECT  237.516 56.592 237.6 56.616 ;
    END
  END tx_flit[34]
  PIN tx_flit[35]
    DIRECTION OUTPUT ;
    USE SIGNAL ;
    PORT
      LAYER M4 ;
        RECT  237.516 56.688 237.6 56.712 ;
    END
  END tx_flit[35]
  PIN tx_flit[36]
    DIRECTION OUTPUT ;
    USE SIGNAL ;
    PORT
      LAYER M4 ;
        RECT  237.516 56.784 237.6 56.808 ;
    END
  END tx_flit[36]
  PIN tx_flit[37]
    DIRECTION OUTPUT ;
    USE SIGNAL ;
    PORT
      LAYER M4 ;
        RECT  237.516 56.88 237.6 56.904 ;
    END
  END tx_flit[37]
  PIN tx_flit[38]
    DIRECTION OUTPUT ;
    USE SIGNAL ;
    PORT
      LAYER M4 ;
        RECT  237.516 56.976 237.6 57 ;
    END
  END tx_flit[38]
  PIN tx_flit[39]
    DIRECTION OUTPUT ;
    USE SIGNAL ;
    PORT
      LAYER M4 ;
        RECT  237.516 57.072 237.6 57.096 ;
    END
  END tx_flit[39]
  PIN tx_flit[3]
    DIRECTION OUTPUT ;
    USE SIGNAL ;
    PORT
      LAYER M4 ;
        RECT  237.516 31.344 237.6 31.368 ;
    END
  END tx_flit[3]
  PIN tx_flit[40]
    DIRECTION OUTPUT ;
    USE SIGNAL ;
    PORT
      LAYER M4 ;
        RECT  237.516 57.168 237.6 57.192 ;
    END
  END tx_flit[40]
  PIN tx_flit[41]
    DIRECTION OUTPUT ;
    USE SIGNAL ;
    PORT
      LAYER M4 ;
        RECT  237.516 57.264 237.6 57.288 ;
    END
  END tx_flit[41]
  PIN tx_flit[42]
    DIRECTION OUTPUT ;
    USE SIGNAL ;
    PORT
      LAYER M4 ;
        RECT  237.516 57.36 237.6 57.384 ;
    END
  END tx_flit[42]
  PIN tx_flit[43]
    DIRECTION OUTPUT ;
    USE SIGNAL ;
    PORT
      LAYER M4 ;
        RECT  237.516 57.456 237.6 57.48 ;
    END
  END tx_flit[43]
  PIN tx_flit[44]
    DIRECTION OUTPUT ;
    USE SIGNAL ;
    PORT
      LAYER M4 ;
        RECT  237.516 80.592 237.6 80.616 ;
    END
  END tx_flit[44]
  PIN tx_flit[45]
    DIRECTION OUTPUT ;
    USE SIGNAL ;
    PORT
      LAYER M4 ;
        RECT  237.516 80.688 237.6 80.712 ;
    END
  END tx_flit[45]
  PIN tx_flit[46]
    DIRECTION OUTPUT ;
    USE SIGNAL ;
    PORT
      LAYER M4 ;
        RECT  237.516 80.784 237.6 80.808 ;
    END
  END tx_flit[46]
  PIN tx_flit[47]
    DIRECTION OUTPUT ;
    USE SIGNAL ;
    PORT
      LAYER M4 ;
        RECT  237.516 80.88 237.6 80.904 ;
    END
  END tx_flit[47]
  PIN tx_flit[48]
    DIRECTION OUTPUT ;
    USE SIGNAL ;
    PORT
      LAYER M4 ;
        RECT  237.516 80.976 237.6 81 ;
    END
  END tx_flit[48]
  PIN tx_flit[49]
    DIRECTION OUTPUT ;
    USE SIGNAL ;
    PORT
      LAYER M4 ;
        RECT  237.516 81.072 237.6 81.096 ;
    END
  END tx_flit[49]
  PIN tx_flit[4]
    DIRECTION OUTPUT ;
    USE SIGNAL ;
    PORT
      LAYER M4 ;
        RECT  237.516 31.44 237.6 31.464 ;
    END
  END tx_flit[4]
  PIN tx_flit[50]
    DIRECTION OUTPUT ;
    USE SIGNAL ;
    PORT
      LAYER M4 ;
        RECT  237.516 81.168 237.6 81.192 ;
    END
  END tx_flit[50]
  PIN tx_flit[51]
    DIRECTION OUTPUT ;
    USE SIGNAL ;
    PORT
      LAYER M4 ;
        RECT  237.516 81.264 237.6 81.288 ;
    END
  END tx_flit[51]
  PIN tx_flit[52]
    DIRECTION OUTPUT ;
    USE SIGNAL ;
    PORT
      LAYER M4 ;
        RECT  237.516 81.36 237.6 81.384 ;
    END
  END tx_flit[52]
  PIN tx_flit[53]
    DIRECTION OUTPUT ;
    USE SIGNAL ;
    PORT
      LAYER M4 ;
        RECT  237.516 81.456 237.6 81.48 ;
    END
  END tx_flit[53]
  PIN tx_flit[54]
    DIRECTION OUTPUT ;
    USE SIGNAL ;
    PORT
      LAYER M4 ;
        RECT  237.516 81.552 237.6 81.576 ;
    END
  END tx_flit[54]
  PIN tx_flit[55]
    DIRECTION OUTPUT ;
    USE SIGNAL ;
    PORT
      LAYER M4 ;
        RECT  237.516 81.648 237.6 81.672 ;
    END
  END tx_flit[55]
  PIN tx_flit[56]
    DIRECTION OUTPUT ;
    USE SIGNAL ;
    PORT
      LAYER M4 ;
        RECT  237.516 81.744 237.6 81.768 ;
    END
  END tx_flit[56]
  PIN tx_flit[57]
    DIRECTION OUTPUT ;
    USE SIGNAL ;
    PORT
      LAYER M4 ;
        RECT  237.516 81.84 237.6 81.864 ;
    END
  END tx_flit[57]
  PIN tx_flit[58]
    DIRECTION OUTPUT ;
    USE SIGNAL ;
    PORT
      LAYER M4 ;
        RECT  237.516 81.936 237.6 81.96 ;
    END
  END tx_flit[58]
  PIN tx_flit[59]
    DIRECTION OUTPUT ;
    USE SIGNAL ;
    PORT
      LAYER M4 ;
        RECT  237.516 82.032 237.6 82.056 ;
    END
  END tx_flit[59]
  PIN tx_flit[5]
    DIRECTION OUTPUT ;
    USE SIGNAL ;
    PORT
      LAYER M4 ;
        RECT  237.516 31.536 237.6 31.56 ;
    END
  END tx_flit[5]
  PIN tx_flit[60]
    DIRECTION OUTPUT ;
    USE SIGNAL ;
    PORT
      LAYER M4 ;
        RECT  237.516 82.128 237.6 82.152 ;
    END
  END tx_flit[60]
  PIN tx_flit[61]
    DIRECTION OUTPUT ;
    USE SIGNAL ;
    PORT
      LAYER M4 ;
        RECT  237.516 82.224 237.6 82.248 ;
    END
  END tx_flit[61]
  PIN tx_flit[62]
    DIRECTION OUTPUT ;
    USE SIGNAL ;
    PORT
      LAYER M4 ;
        RECT  237.516 82.32 237.6 82.344 ;
    END
  END tx_flit[62]
  PIN tx_flit[63]
    DIRECTION OUTPUT ;
    USE SIGNAL ;
    PORT
      LAYER M4 ;
        RECT  237.516 82.416 237.6 82.44 ;
    END
  END tx_flit[63]
  PIN tx_flit[64]
    DIRECTION OUTPUT ;
    USE SIGNAL ;
    PORT
      LAYER M4 ;
        RECT  237.516 82.512 237.6 82.536 ;
    END
  END tx_flit[64]
  PIN tx_flit[65]
    DIRECTION OUTPUT ;
    USE SIGNAL ;
    PORT
      LAYER M4 ;
        RECT  237.516 82.608 237.6 82.632 ;
    END
  END tx_flit[65]
  PIN tx_flit[66]
    DIRECTION OUTPUT ;
    USE SIGNAL ;
    PORT
      LAYER M4 ;
        RECT  237.516 82.704 237.6 82.728 ;
    END
  END tx_flit[66]
  PIN tx_flit[67]
    DIRECTION OUTPUT ;
    USE SIGNAL ;
    PORT
      LAYER M4 ;
        RECT  237.516 82.8 237.6 82.824 ;
    END
  END tx_flit[67]
  PIN tx_flit[68]
    DIRECTION OUTPUT ;
    USE SIGNAL ;
    PORT
      LAYER M4 ;
        RECT  237.516 82.896 237.6 82.92 ;
    END
  END tx_flit[68]
  PIN tx_flit[69]
    DIRECTION OUTPUT ;
    USE SIGNAL ;
    PORT
      LAYER M4 ;
        RECT  237.516 82.992 237.6 83.016 ;
    END
  END tx_flit[69]
  PIN tx_flit[6]
    DIRECTION OUTPUT ;
    USE SIGNAL ;
    PORT
      LAYER M4 ;
        RECT  237.516 31.632 237.6 31.656 ;
    END
  END tx_flit[6]
  PIN tx_flit[70]
    DIRECTION OUTPUT ;
    USE SIGNAL ;
    PORT
      LAYER M4 ;
        RECT  237.516 83.088 237.6 83.112 ;
    END
  END tx_flit[70]
  PIN tx_flit[71]
    DIRECTION OUTPUT ;
    USE SIGNAL ;
    PORT
      LAYER M4 ;
        RECT  237.516 83.184 237.6 83.208 ;
    END
  END tx_flit[71]
  PIN tx_flit[72]
    DIRECTION OUTPUT ;
    USE SIGNAL ;
    PORT
      LAYER M4 ;
        RECT  237.516 83.28 237.6 83.304 ;
    END
  END tx_flit[72]
  PIN tx_flit[73]
    DIRECTION OUTPUT ;
    USE SIGNAL ;
    PORT
      LAYER M4 ;
        RECT  237.516 83.376 237.6 83.4 ;
    END
  END tx_flit[73]
  PIN tx_flit[74]
    DIRECTION OUTPUT ;
    USE SIGNAL ;
    PORT
      LAYER M4 ;
        RECT  237.516 83.472 237.6 83.496 ;
    END
  END tx_flit[74]
  PIN tx_flit[75]
    DIRECTION OUTPUT ;
    USE SIGNAL ;
    PORT
      LAYER M4 ;
        RECT  237.516 83.568 237.6 83.592 ;
    END
  END tx_flit[75]
  PIN tx_flit[76]
    DIRECTION OUTPUT ;
    USE SIGNAL ;
    PORT
      LAYER M4 ;
        RECT  237.516 61.392 237.6 61.416 ;
    END
  END tx_flit[76]
  PIN tx_flit[77]
    DIRECTION OUTPUT ;
    USE SIGNAL ;
    PORT
      LAYER M4 ;
        RECT  237.516 61.488 237.6 61.512 ;
    END
  END tx_flit[77]
  PIN tx_flit[78]
    DIRECTION OUTPUT ;
    USE SIGNAL ;
    PORT
      LAYER M4 ;
        RECT  237.516 61.584 237.6 61.608 ;
    END
  END tx_flit[78]
  PIN tx_flit[79]
    DIRECTION OUTPUT ;
    USE SIGNAL ;
    PORT
      LAYER M4 ;
        RECT  237.516 61.68 237.6 61.704 ;
    END
  END tx_flit[79]
  PIN tx_flit[7]
    DIRECTION OUTPUT ;
    USE SIGNAL ;
    PORT
      LAYER M4 ;
        RECT  237.516 31.728 237.6 31.752 ;
    END
  END tx_flit[7]
  PIN tx_flit[80]
    DIRECTION OUTPUT ;
    USE SIGNAL ;
    PORT
      LAYER M4 ;
        RECT  237.516 61.776 237.6 61.8 ;
    END
  END tx_flit[80]
  PIN tx_flit[81]
    DIRECTION OUTPUT ;
    USE SIGNAL ;
    PORT
      LAYER M4 ;
        RECT  237.516 61.872 237.6 61.896 ;
    END
  END tx_flit[81]
  PIN tx_flit[82]
    DIRECTION OUTPUT ;
    USE SIGNAL ;
    PORT
      LAYER M4 ;
        RECT  237.516 61.968 237.6 61.992 ;
    END
  END tx_flit[82]
  PIN tx_flit[83]
    DIRECTION OUTPUT ;
    USE SIGNAL ;
    PORT
      LAYER M4 ;
        RECT  237.516 62.064 237.6 62.088 ;
    END
  END tx_flit[83]
  PIN tx_flit[84]
    DIRECTION OUTPUT ;
    USE SIGNAL ;
    PORT
      LAYER M4 ;
        RECT  237.516 62.16 237.6 62.184 ;
    END
  END tx_flit[84]
  PIN tx_flit[85]
    DIRECTION OUTPUT ;
    USE SIGNAL ;
    PORT
      LAYER M4 ;
        RECT  237.516 62.256 237.6 62.28 ;
    END
  END tx_flit[85]
  PIN tx_flit[86]
    DIRECTION OUTPUT ;
    USE SIGNAL ;
    PORT
      LAYER M4 ;
        RECT  237.516 62.352 237.6 62.376 ;
    END
  END tx_flit[86]
  PIN tx_flit[87]
    DIRECTION OUTPUT ;
    USE SIGNAL ;
    PORT
      LAYER M4 ;
        RECT  237.516 62.448 237.6 62.472 ;
    END
  END tx_flit[87]
  PIN tx_flit[88]
    DIRECTION OUTPUT ;
    USE SIGNAL ;
    PORT
      LAYER M4 ;
        RECT  237.516 62.544 237.6 62.568 ;
    END
  END tx_flit[88]
  PIN tx_flit[89]
    DIRECTION OUTPUT ;
    USE SIGNAL ;
    PORT
      LAYER M4 ;
        RECT  237.516 62.64 237.6 62.664 ;
    END
  END tx_flit[89]
  PIN tx_flit[8]
    DIRECTION OUTPUT ;
    USE SIGNAL ;
    PORT
      LAYER M4 ;
        RECT  237.516 31.824 237.6 31.848 ;
    END
  END tx_flit[8]
  PIN tx_flit[90]
    DIRECTION OUTPUT ;
    USE SIGNAL ;
    PORT
      LAYER M4 ;
        RECT  237.516 62.736 237.6 62.76 ;
    END
  END tx_flit[90]
  PIN tx_flit[91]
    DIRECTION OUTPUT ;
    USE SIGNAL ;
    PORT
      LAYER M4 ;
        RECT  237.516 62.832 237.6 62.856 ;
    END
  END tx_flit[91]
  PIN tx_flit[92]
    DIRECTION OUTPUT ;
    USE SIGNAL ;
    PORT
      LAYER M4 ;
        RECT  237.516 62.928 237.6 62.952 ;
    END
  END tx_flit[92]
  PIN tx_flit[93]
    DIRECTION OUTPUT ;
    USE SIGNAL ;
    PORT
      LAYER M4 ;
        RECT  237.516 63.024 237.6 63.048 ;
    END
  END tx_flit[93]
  PIN tx_flit[94]
    DIRECTION OUTPUT ;
    USE SIGNAL ;
    PORT
      LAYER M4 ;
        RECT  237.516 63.12 237.6 63.144 ;
    END
  END tx_flit[94]
  PIN tx_flit[95]
    DIRECTION OUTPUT ;
    USE SIGNAL ;
    PORT
      LAYER M4 ;
        RECT  237.516 63.216 237.6 63.24 ;
    END
  END tx_flit[95]
  PIN tx_flit[96]
    DIRECTION OUTPUT ;
    USE SIGNAL ;
    PORT
      LAYER M4 ;
        RECT  237.516 63.312 237.6 63.336 ;
    END
  END tx_flit[96]
  PIN tx_flit[97]
    DIRECTION OUTPUT ;
    USE SIGNAL ;
    PORT
      LAYER M4 ;
        RECT  237.516 63.408 237.6 63.432 ;
    END
  END tx_flit[97]
  PIN tx_flit[98]
    DIRECTION OUTPUT ;
    USE SIGNAL ;
    PORT
      LAYER M4 ;
        RECT  237.516 63.504 237.6 63.528 ;
    END
  END tx_flit[98]
  PIN tx_flit[99]
    DIRECTION OUTPUT ;
    USE SIGNAL ;
    PORT
      LAYER M4 ;
        RECT  237.516 63.6 237.6 63.624 ;
    END
  END tx_flit[99]
  PIN tx_flit[9]
    DIRECTION OUTPUT ;
    USE SIGNAL ;
    PORT
      LAYER M4 ;
        RECT  237.516 31.92 237.6 31.944 ;
    END
  END tx_flit[9]
  PIN tx_up
    DIRECTION INPUT ;
    USE SIGNAL ;
    PORT
      LAYER M4 ;
        RECT  237.516 16.752 237.6 16.776 ;
    END
  END tx_up
  PIN tx_v
    DIRECTION OUTPUT ;
    USE SIGNAL ;
    PORT
      LAYER M4 ;
        RECT  237.516 16.848 237.6 16.872 ;
    END
  END tx_v
  PIN VDD
    DIRECTION INOUT ;
    USE POWER ;
    PORT
      LAYER M5 ;
        RECT  234.792 2.151 234.912 84.249 ;
        RECT  229.392 2.151 229.512 84.249 ;
        RECT  223.992 2.151 224.112 84.249 ;
        RECT  218.592 2.151 218.712 84.249 ;
        RECT  213.192 2.151 213.312 84.249 ;
        RECT  207.792 2.151 207.912 84.249 ;
        RECT  202.392 2.151 202.512 84.249 ;
        RECT  196.992 2.151 197.112 84.249 ;
        RECT  191.592 2.151 191.712 84.249 ;
        RECT  186.192 2.151 186.312 84.249 ;
        RECT  180.792 2.151 180.912 84.249 ;
        RECT  175.392 2.151 175.512 84.249 ;
        RECT  169.992 2.151 170.112 84.249 ;
        RECT  164.592 2.151 164.712 84.249 ;
        RECT  159.192 2.151 159.312 84.249 ;
        RECT  153.792 2.151 153.912 84.249 ;
        RECT  148.392 2.151 148.512 84.249 ;
        RECT  142.992 2.151 143.112 84.249 ;
        RECT  137.592 2.151 137.712 84.249 ;
        RECT  132.192 2.151 132.312 84.249 ;
        RECT  126.792 2.151 126.912 84.249 ;
        RECT  121.392 2.151 121.512 84.249 ;
        RECT  115.992 2.151 116.112 84.249 ;
        RECT  110.592 2.151 110.712 84.249 ;
        RECT  105.192 2.151 105.312 84.249 ;
        RECT  99.792 2.151 99.912 84.249 ;
        RECT  94.392 2.151 94.512 84.249 ;
        RECT  88.992 2.151 89.112 84.249 ;
        RECT  83.592 2.151 83.712 84.249 ;
        RECT  78.192 2.151 78.312 84.249 ;
        RECT  72.792 2.151 72.912 84.249 ;
        RECT  67.392 2.151 67.512 84.249 ;
        RECT  61.992 2.151 62.112 84.249 ;
        RECT  56.592 2.151 56.712 84.249 ;
        RECT  51.192 2.151 51.312 84.249 ;
        RECT  45.792 2.151 45.912 84.249 ;
        RECT  40.392 2.151 40.512 84.249 ;
        RECT  34.992 2.151 35.112 84.249 ;
        RECT  29.592 2.151 29.712 84.249 ;
        RECT  24.192 2.151 24.312 84.249 ;
        RECT  18.792 2.151 18.912 84.249 ;
        RECT  13.392 2.151 13.512 84.249 ;
        RECT  7.992 2.151 8.112 84.249 ;
        RECT  2.592 2.151 2.712 84.249 ;
    END
  END VDD
  PIN VSS
    DIRECTION INOUT ;
    USE GROUND ;
    PORT
      LAYER M5 ;
        RECT  234.6 2.137 234.72 84.263 ;
        RECT  229.2 2.137 229.32 84.263 ;
        RECT  223.8 2.137 223.92 84.263 ;
        RECT  218.4 2.137 218.52 84.263 ;
        RECT  213 2.137 213.12 84.263 ;
        RECT  207.6 2.137 207.72 84.263 ;
        RECT  202.2 2.137 202.32 84.263 ;
        RECT  196.8 2.137 196.92 84.263 ;
        RECT  191.4 2.137 191.52 84.263 ;
        RECT  186 2.137 186.12 84.263 ;
        RECT  180.6 2.137 180.72 84.263 ;
        RECT  175.2 2.137 175.32 84.263 ;
        RECT  169.8 2.137 169.92 84.263 ;
        RECT  164.4 2.137 164.52 84.263 ;
        RECT  159 2.137 159.12 84.263 ;
        RECT  153.6 2.137 153.72 84.263 ;
        RECT  148.2 2.137 148.32 84.263 ;
        RECT  142.8 2.137 142.92 84.263 ;
        RECT  137.4 2.137 137.52 84.263 ;
        RECT  132 2.137 132.12 84.263 ;
        RECT  126.6 2.137 126.72 84.263 ;
        RECT  121.2 2.137 121.32 84.263 ;
        RECT  115.8 2.137 115.92 84.263 ;
        RECT  110.4 2.137 110.52 84.263 ;
        RECT  105 2.137 105.12 84.263 ;
        RECT  99.6 2.137 99.72 84.263 ;
        RECT  94.2 2.137 94.32 84.263 ;
        RECT  88.8 2.137 88.92 84.263 ;
        RECT  83.4 2.137 83.52 84.263 ;
        RECT  78 2.137 78.12 84.263 ;
        RECT  72.6 2.137 72.72 84.263 ;
        RECT  67.2 2.137 67.32 84.263 ;
        RECT  61.8 2.137 61.92 84.263 ;
        RECT  56.4 2.137 56.52 84.263 ;
        RECT  51 2.137 51.12 84.263 ;
        RECT  45.6 2.137 45.72 84.263 ;
        RECT  40.2 2.137 40.32 84.263 ;
        RECT  34.8 2.137 34.92 84.263 ;
        RECT  29.4 2.137 29.52 84.263 ;
        RECT  24 2.137 24.12 84.263 ;
        RECT  18.6 2.137 18.72 84.263 ;
        RECT  13.2 2.137 13.32 84.263 ;
        RECT  7.8 2.137 7.92 84.263 ;
        RECT  2.4 2.137 2.52 84.263 ;
    END
  END VSS
  # OT_OBS_CLOSED layer=M5 d_um=1.536 added=497
  OBS
    LAYER RVTN ;
     RECT  2.16 2.16 235.44 2.295 ;
     RECT  2.16 2.565 235.44 2.835 ;
     RECT  2.16 3.105 235.44 3.375 ;
     RECT  2.16 3.645 235.44 3.915 ;
     RECT  2.16 4.185 235.44 4.455 ;
     RECT  2.16 4.725 235.44 4.995 ;
     RECT  2.16 5.265 235.44 5.535 ;
     RECT  2.16 5.805 235.44 6.075 ;
     RECT  2.16 6.345 235.44 6.615 ;
     RECT  2.16 6.885 235.44 7.155 ;
     RECT  2.16 7.425 235.44 7.695 ;
     RECT  2.16 7.965 235.44 8.235 ;
     RECT  2.16 8.505 235.44 8.775 ;
     RECT  2.16 9.045 235.44 9.315 ;
     RECT  2.16 9.585 235.44 9.855 ;
     RECT  2.16 10.125 235.44 10.395 ;
     RECT  2.16 10.665 235.44 10.935 ;
     RECT  2.16 11.205 235.44 11.475 ;
     RECT  2.16 11.745 235.44 12.015 ;
     RECT  2.16 12.285 235.44 12.555 ;
     RECT  2.16 12.825 235.44 13.095 ;
     RECT  2.16 13.365 235.44 13.635 ;
     RECT  2.16 13.905 235.44 14.175 ;
     RECT  2.16 14.445 235.44 14.715 ;
     RECT  2.16 14.985 235.44 15.255 ;
     RECT  2.16 15.525 235.44 15.795 ;
     RECT  2.16 16.065 235.44 16.335 ;
     RECT  2.16 16.605 235.44 16.875 ;
     RECT  2.16 17.145 235.44 17.415 ;
     RECT  2.16 17.685 235.44 17.955 ;
     RECT  2.16 18.225 235.44 18.495 ;
     RECT  2.16 18.765 235.44 19.035 ;
     RECT  2.16 19.305 235.44 19.575 ;
     RECT  2.16 19.845 235.44 20.115 ;
     RECT  2.16 20.385 235.44 20.655 ;
     RECT  2.16 20.925 235.44 21.195 ;
     RECT  2.16 21.465 235.44 21.735 ;
     RECT  2.16 22.005 235.44 22.275 ;
     RECT  2.16 22.545 235.44 22.815 ;
     RECT  2.16 23.085 235.44 23.355 ;
     RECT  2.16 23.625 235.44 23.895 ;
     RECT  2.16 24.165 235.44 24.435 ;
     RECT  2.16 24.705 235.44 24.975 ;
     RECT  2.16 25.245 235.44 25.515 ;
     RECT  2.16 25.785 235.44 25.92 ;
     RECT  2.16 25.92 29.484 26.055 ;
     RECT  207.684 25.92 235.44 26.055 ;
     RECT  2.16 26.325 29.484 26.595 ;
     RECT  207.684 26.325 235.44 26.595 ;
     RECT  2.16 26.865 29.484 27.135 ;
     RECT  207.684 26.865 235.44 27.135 ;
     RECT  2.16 27.405 29.484 27.675 ;
     RECT  207.684 27.405 235.44 27.675 ;
     RECT  2.16 27.945 29.484 28.215 ;
     RECT  207.684 27.945 235.44 28.215 ;
     RECT  2.16 28.485 29.484 28.755 ;
     RECT  207.684 28.485 235.44 28.755 ;
     RECT  2.16 29.025 29.484 29.295 ;
     RECT  207.684 29.025 235.44 29.295 ;
     RECT  2.16 29.565 29.484 29.835 ;
     RECT  207.684 29.565 235.44 29.835 ;
     RECT  2.16 30.105 29.484 30.375 ;
     RECT  207.684 30.105 235.44 30.375 ;
     RECT  2.16 30.645 29.484 30.915 ;
     RECT  207.684 30.645 235.44 30.915 ;
     RECT  2.16 31.185 29.484 31.455 ;
     RECT  207.684 31.185 235.44 31.455 ;
     RECT  2.16 31.725 29.484 31.995 ;
     RECT  207.684 31.725 235.44 31.995 ;
     RECT  2.16 32.265 29.484 32.535 ;
     RECT  207.684 32.265 235.44 32.535 ;
     RECT  2.16 32.805 29.484 33.075 ;
     RECT  207.684 32.805 235.44 33.075 ;
     RECT  2.16 33.345 29.484 33.615 ;
     RECT  207.684 33.345 235.44 33.615 ;
     RECT  2.16 33.885 29.484 34.155 ;
     RECT  207.684 33.885 235.44 34.155 ;
     RECT  2.16 34.425 29.484 34.695 ;
     RECT  207.684 34.425 235.44 34.695 ;
     RECT  2.16 34.965 29.484 35.235 ;
     RECT  207.684 34.965 235.44 35.235 ;
     RECT  2.16 35.505 29.484 35.775 ;
     RECT  207.684 35.505 235.44 35.775 ;
     RECT  2.16 36.045 29.484 36.315 ;
     RECT  207.684 36.045 235.44 36.315 ;
     RECT  2.16 36.585 29.484 36.855 ;
     RECT  207.684 36.585 235.44 36.855 ;
     RECT  2.16 37.125 29.484 37.395 ;
     RECT  207.684 37.125 235.44 37.395 ;
     RECT  2.16 37.665 29.484 37.935 ;
     RECT  207.684 37.665 235.44 37.935 ;
     RECT  2.16 38.205 29.484 38.475 ;
     RECT  207.684 38.205 235.44 38.475 ;
     RECT  2.16 38.745 29.484 39.015 ;
     RECT  207.684 38.745 235.44 39.015 ;
     RECT  2.16 39.285 29.484 39.555 ;
     RECT  207.684 39.285 235.44 39.555 ;
     RECT  2.16 39.825 29.484 40.095 ;
     RECT  207.684 39.825 235.44 40.095 ;
     RECT  2.16 40.365 29.484 40.635 ;
     RECT  207.684 40.365 235.44 40.635 ;
     RECT  2.16 40.905 29.484 41.175 ;
     RECT  207.684 40.905 235.44 41.175 ;
     RECT  2.16 41.445 29.484 41.715 ;
     RECT  207.684 41.445 235.44 41.715 ;
     RECT  2.16 41.985 29.484 42.255 ;
     RECT  207.684 41.985 235.44 42.255 ;
     RECT  2.16 42.525 29.484 42.795 ;
     RECT  207.684 42.525 235.44 42.795 ;
     RECT  2.16 43.065 29.484 43.335 ;
     RECT  207.684 43.065 235.44 43.335 ;
     RECT  2.16 43.605 29.484 43.875 ;
     RECT  207.684 43.605 235.44 43.875 ;
     RECT  2.16 44.145 29.484 44.415 ;
     RECT  207.684 44.145 235.44 44.415 ;
     RECT  2.16 44.685 29.484 44.955 ;
     RECT  207.684 44.685 235.44 44.955 ;
     RECT  2.16 45.225 29.484 45.495 ;
     RECT  207.684 45.225 235.44 45.495 ;
     RECT  2.16 45.765 29.484 46.035 ;
     RECT  207.684 45.765 235.44 46.035 ;
     RECT  2.16 46.305 29.484 46.575 ;
     RECT  207.684 46.305 235.44 46.575 ;
     RECT  2.16 46.845 29.484 47.115 ;
     RECT  207.684 46.845 235.44 47.115 ;
     RECT  2.16 47.385 29.484 47.655 ;
     RECT  207.684 47.385 235.44 47.655 ;
     RECT  2.16 47.925 29.484 48.195 ;
     RECT  207.684 47.925 235.44 48.195 ;
     RECT  2.16 48.465 29.484 48.735 ;
     RECT  207.684 48.465 235.44 48.735 ;
     RECT  2.16 49.005 29.484 49.275 ;
     RECT  207.684 49.005 235.44 49.275 ;
     RECT  2.16 49.545 29.484 49.815 ;
     RECT  207.684 49.545 235.44 49.815 ;
     RECT  2.16 50.085 29.484 50.355 ;
     RECT  207.684 50.085 235.44 50.355 ;
     RECT  2.16 50.625 29.484 50.895 ;
     RECT  207.684 50.625 235.44 50.895 ;
     RECT  2.16 51.165 29.484 51.435 ;
     RECT  207.684 51.165 235.44 51.435 ;
     RECT  2.16 51.705 29.484 51.975 ;
     RECT  207.684 51.705 235.44 51.975 ;
     RECT  2.16 52.245 29.484 52.515 ;
     RECT  207.684 52.245 235.44 52.515 ;
     RECT  2.16 52.785 29.484 53.055 ;
     RECT  207.684 52.785 235.44 53.055 ;
     RECT  2.16 53.325 29.484 53.595 ;
     RECT  207.684 53.325 235.44 53.595 ;
     RECT  2.16 53.865 29.484 54.135 ;
     RECT  207.684 53.865 235.44 54.135 ;
     RECT  2.16 54.405 29.484 54.675 ;
     RECT  207.684 54.405 235.44 54.675 ;
     RECT  2.16 54.945 29.484 55.215 ;
     RECT  207.684 54.945 235.44 55.215 ;
     RECT  2.16 55.485 29.484 55.755 ;
     RECT  207.684 55.485 235.44 55.755 ;
     RECT  2.16 56.025 29.484 56.295 ;
     RECT  207.684 56.025 235.44 56.295 ;
     RECT  2.16 56.565 29.484 56.835 ;
     RECT  207.684 56.565 235.44 56.835 ;
     RECT  2.16 57.105 29.484 57.375 ;
     RECT  207.684 57.105 235.44 57.375 ;
     RECT  2.16 57.645 29.484 57.915 ;
     RECT  207.684 57.645 235.44 57.915 ;
     RECT  2.16 58.185 29.484 58.455 ;
     RECT  207.684 58.185 235.44 58.455 ;
     RECT  2.16 58.725 29.484 58.995 ;
     RECT  207.684 58.725 235.44 58.995 ;
     RECT  2.16 59.265 29.484 59.535 ;
     RECT  207.684 59.265 235.44 59.535 ;
     RECT  2.16 59.805 29.484 59.94 ;
     RECT  207.684 59.805 235.44 59.94 ;
     RECT  2.16 59.94 235.44 60.075 ;
     RECT  2.16 60.345 235.44 60.615 ;
     RECT  2.16 60.885 235.44 61.155 ;
     RECT  2.16 61.425 235.44 61.695 ;
     RECT  2.16 61.965 235.44 62.235 ;
     RECT  2.16 62.505 235.44 62.775 ;
     RECT  2.16 63.045 235.44 63.315 ;
     RECT  2.16 63.585 235.44 63.855 ;
     RECT  2.16 64.125 235.44 64.395 ;
     RECT  2.16 64.665 235.44 64.935 ;
     RECT  2.16 65.205 235.44 65.475 ;
     RECT  2.16 65.745 235.44 66.015 ;
     RECT  2.16 66.285 235.44 66.555 ;
     RECT  2.16 66.825 235.44 67.095 ;
     RECT  2.16 67.365 235.44 67.635 ;
     RECT  2.16 67.905 235.44 68.175 ;
     RECT  2.16 68.445 235.44 68.715 ;
     RECT  2.16 68.985 235.44 69.255 ;
     RECT  2.16 69.525 235.44 69.795 ;
     RECT  2.16 70.065 235.44 70.335 ;
     RECT  2.16 70.605 235.44 70.875 ;
     RECT  2.16 71.145 235.44 71.415 ;
     RECT  2.16 71.685 235.44 71.955 ;
     RECT  2.16 72.225 235.44 72.495 ;
     RECT  2.16 72.765 235.44 73.035 ;
     RECT  2.16 73.305 235.44 73.575 ;
     RECT  2.16 73.845 235.44 74.115 ;
     RECT  2.16 74.385 235.44 74.655 ;
     RECT  2.16 74.925 235.44 75.195 ;
     RECT  2.16 75.465 235.44 75.735 ;
     RECT  2.16 76.005 235.44 76.275 ;
     RECT  2.16 76.545 235.44 76.815 ;
     RECT  2.16 77.085 235.44 77.355 ;
     RECT  2.16 77.625 235.44 77.895 ;
     RECT  2.16 78.165 235.44 78.435 ;
     RECT  2.16 78.705 235.44 78.975 ;
     RECT  2.16 79.245 235.44 79.515 ;
     RECT  2.16 79.785 235.44 80.055 ;
     RECT  2.16 80.325 235.44 80.595 ;
     RECT  2.16 80.865 235.44 81.135 ;
     RECT  2.16 81.405 235.44 81.675 ;
     RECT  2.16 81.945 235.44 82.215 ;
     RECT  2.16 82.485 235.44 82.755 ;
     RECT  2.16 83.025 235.44 83.295 ;
     RECT  2.16 83.565 235.44 83.835 ;
     RECT  2.16 84.105 235.44 84.24 ;
    LAYER RVTP ;
     RECT  2.16 2.295 235.44 2.565 ;
     RECT  2.16 2.835 235.44 3.105 ;
     RECT  2.16 3.375 235.44 3.645 ;
     RECT  2.16 3.915 235.44 4.185 ;
     RECT  2.16 4.455 235.44 4.725 ;
     RECT  2.16 4.995 235.44 5.265 ;
     RECT  2.16 5.535 235.44 5.805 ;
     RECT  2.16 6.075 235.44 6.345 ;
     RECT  2.16 6.615 235.44 6.885 ;
     RECT  2.16 7.155 235.44 7.425 ;
     RECT  2.16 7.695 235.44 7.965 ;
     RECT  2.16 8.235 235.44 8.505 ;
     RECT  2.16 8.775 235.44 9.045 ;
     RECT  2.16 9.315 235.44 9.585 ;
     RECT  2.16 9.855 235.44 10.125 ;
     RECT  2.16 10.395 235.44 10.665 ;
     RECT  2.16 10.935 235.44 11.205 ;
     RECT  2.16 11.475 235.44 11.745 ;
     RECT  2.16 12.015 235.44 12.285 ;
     RECT  2.16 12.555 235.44 12.825 ;
     RECT  2.16 13.095 235.44 13.365 ;
     RECT  2.16 13.635 235.44 13.905 ;
     RECT  2.16 14.175 235.44 14.445 ;
     RECT  2.16 14.715 235.44 14.985 ;
     RECT  2.16 15.255 235.44 15.525 ;
     RECT  2.16 15.795 235.44 16.065 ;
     RECT  2.16 16.335 235.44 16.605 ;
     RECT  2.16 16.875 235.44 17.145 ;
     RECT  2.16 17.415 235.44 17.685 ;
     RECT  2.16 17.955 235.44 18.225 ;
     RECT  2.16 18.495 235.44 18.765 ;
     RECT  2.16 19.035 235.44 19.305 ;
     RECT  2.16 19.575 235.44 19.845 ;
     RECT  2.16 20.115 235.44 20.385 ;
     RECT  2.16 20.655 235.44 20.925 ;
     RECT  2.16 21.195 235.44 21.465 ;
     RECT  2.16 21.735 235.44 22.005 ;
     RECT  2.16 22.275 235.44 22.545 ;
     RECT  2.16 22.815 235.44 23.085 ;
     RECT  2.16 23.355 235.44 23.625 ;
     RECT  2.16 23.895 235.44 24.165 ;
     RECT  2.16 24.435 235.44 24.705 ;
     RECT  2.16 24.975 235.44 25.245 ;
     RECT  2.16 25.515 235.44 25.785 ;
     RECT  2.16 26.055 29.484 26.325 ;
     RECT  207.684 26.055 235.44 26.325 ;
     RECT  2.16 26.595 29.484 26.865 ;
     RECT  207.684 26.595 235.44 26.865 ;
     RECT  2.16 27.135 29.484 27.405 ;
     RECT  207.684 27.135 235.44 27.405 ;
     RECT  2.16 27.675 29.484 27.945 ;
     RECT  207.684 27.675 235.44 27.945 ;
     RECT  2.16 28.215 29.484 28.485 ;
     RECT  207.684 28.215 235.44 28.485 ;
     RECT  2.16 28.755 29.484 29.025 ;
     RECT  207.684 28.755 235.44 29.025 ;
     RECT  2.16 29.295 29.484 29.565 ;
     RECT  207.684 29.295 235.44 29.565 ;
     RECT  2.16 29.835 29.484 30.105 ;
     RECT  207.684 29.835 235.44 30.105 ;
     RECT  2.16 30.375 29.484 30.645 ;
     RECT  207.684 30.375 235.44 30.645 ;
     RECT  2.16 30.915 29.484 31.185 ;
     RECT  207.684 30.915 235.44 31.185 ;
     RECT  2.16 31.455 29.484 31.725 ;
     RECT  207.684 31.455 235.44 31.725 ;
     RECT  2.16 31.995 29.484 32.265 ;
     RECT  207.684 31.995 235.44 32.265 ;
     RECT  2.16 32.535 29.484 32.805 ;
     RECT  207.684 32.535 235.44 32.805 ;
     RECT  2.16 33.075 29.484 33.345 ;
     RECT  207.684 33.075 235.44 33.345 ;
     RECT  2.16 33.615 29.484 33.885 ;
     RECT  207.684 33.615 235.44 33.885 ;
     RECT  2.16 34.155 29.484 34.425 ;
     RECT  207.684 34.155 235.44 34.425 ;
     RECT  2.16 34.695 29.484 34.965 ;
     RECT  207.684 34.695 235.44 34.965 ;
     RECT  2.16 35.235 29.484 35.505 ;
     RECT  207.684 35.235 235.44 35.505 ;
     RECT  2.16 35.775 29.484 36.045 ;
     RECT  207.684 35.775 235.44 36.045 ;
     RECT  2.16 36.315 29.484 36.585 ;
     RECT  207.684 36.315 235.44 36.585 ;
     RECT  2.16 36.855 29.484 37.125 ;
     RECT  207.684 36.855 235.44 37.125 ;
     RECT  2.16 37.395 29.484 37.665 ;
     RECT  207.684 37.395 235.44 37.665 ;
     RECT  2.16 37.935 29.484 38.205 ;
     RECT  207.684 37.935 235.44 38.205 ;
     RECT  2.16 38.475 29.484 38.745 ;
     RECT  207.684 38.475 235.44 38.745 ;
     RECT  2.16 39.015 29.484 39.285 ;
     RECT  207.684 39.015 235.44 39.285 ;
     RECT  2.16 39.555 29.484 39.825 ;
     RECT  207.684 39.555 235.44 39.825 ;
     RECT  2.16 40.095 29.484 40.365 ;
     RECT  207.684 40.095 235.44 40.365 ;
     RECT  2.16 40.635 29.484 40.905 ;
     RECT  207.684 40.635 235.44 40.905 ;
     RECT  2.16 41.175 29.484 41.445 ;
     RECT  207.684 41.175 235.44 41.445 ;
     RECT  2.16 41.715 29.484 41.985 ;
     RECT  207.684 41.715 235.44 41.985 ;
     RECT  2.16 42.255 29.484 42.525 ;
     RECT  207.684 42.255 235.44 42.525 ;
     RECT  2.16 42.795 29.484 43.065 ;
     RECT  207.684 42.795 235.44 43.065 ;
     RECT  2.16 43.335 29.484 43.605 ;
     RECT  207.684 43.335 235.44 43.605 ;
     RECT  2.16 43.875 29.484 44.145 ;
     RECT  207.684 43.875 235.44 44.145 ;
     RECT  2.16 44.415 29.484 44.685 ;
     RECT  207.684 44.415 235.44 44.685 ;
     RECT  2.16 44.955 29.484 45.225 ;
     RECT  207.684 44.955 235.44 45.225 ;
     RECT  2.16 45.495 29.484 45.765 ;
     RECT  207.684 45.495 235.44 45.765 ;
     RECT  2.16 46.035 29.484 46.305 ;
     RECT  207.684 46.035 235.44 46.305 ;
     RECT  2.16 46.575 29.484 46.845 ;
     RECT  207.684 46.575 235.44 46.845 ;
     RECT  2.16 47.115 29.484 47.385 ;
     RECT  207.684 47.115 235.44 47.385 ;
     RECT  2.16 47.655 29.484 47.925 ;
     RECT  207.684 47.655 235.44 47.925 ;
     RECT  2.16 48.195 29.484 48.465 ;
     RECT  207.684 48.195 235.44 48.465 ;
     RECT  2.16 48.735 29.484 49.005 ;
     RECT  207.684 48.735 235.44 49.005 ;
     RECT  2.16 49.275 29.484 49.545 ;
     RECT  207.684 49.275 235.44 49.545 ;
     RECT  2.16 49.815 29.484 50.085 ;
     RECT  207.684 49.815 235.44 50.085 ;
     RECT  2.16 50.355 29.484 50.625 ;
     RECT  207.684 50.355 235.44 50.625 ;
     RECT  2.16 50.895 29.484 51.165 ;
     RECT  207.684 50.895 235.44 51.165 ;
     RECT  2.16 51.435 29.484 51.705 ;
     RECT  207.684 51.435 235.44 51.705 ;
     RECT  2.16 51.975 29.484 52.245 ;
     RECT  207.684 51.975 235.44 52.245 ;
     RECT  2.16 52.515 29.484 52.785 ;
     RECT  207.684 52.515 235.44 52.785 ;
     RECT  2.16 53.055 29.484 53.325 ;
     RECT  207.684 53.055 235.44 53.325 ;
     RECT  2.16 53.595 29.484 53.865 ;
     RECT  207.684 53.595 235.44 53.865 ;
     RECT  2.16 54.135 29.484 54.405 ;
     RECT  207.684 54.135 235.44 54.405 ;
     RECT  2.16 54.675 29.484 54.945 ;
     RECT  207.684 54.675 235.44 54.945 ;
     RECT  2.16 55.215 29.484 55.485 ;
     RECT  207.684 55.215 235.44 55.485 ;
     RECT  2.16 55.755 29.484 56.025 ;
     RECT  207.684 55.755 235.44 56.025 ;
     RECT  2.16 56.295 29.484 56.565 ;
     RECT  207.684 56.295 235.44 56.565 ;
     RECT  2.16 56.835 29.484 57.105 ;
     RECT  207.684 56.835 235.44 57.105 ;
     RECT  2.16 57.375 29.484 57.645 ;
     RECT  207.684 57.375 235.44 57.645 ;
     RECT  2.16 57.915 29.484 58.185 ;
     RECT  207.684 57.915 235.44 58.185 ;
     RECT  2.16 58.455 29.484 58.725 ;
     RECT  207.684 58.455 235.44 58.725 ;
     RECT  2.16 58.995 29.484 59.265 ;
     RECT  207.684 58.995 235.44 59.265 ;
     RECT  2.16 59.535 29.484 59.805 ;
     RECT  207.684 59.535 235.44 59.805 ;
     RECT  2.16 60.075 235.44 60.345 ;
     RECT  2.16 60.615 235.44 60.885 ;
     RECT  2.16 61.155 235.44 61.425 ;
     RECT  2.16 61.695 235.44 61.965 ;
     RECT  2.16 62.235 235.44 62.505 ;
     RECT  2.16 62.775 235.44 63.045 ;
     RECT  2.16 63.315 235.44 63.585 ;
     RECT  2.16 63.855 235.44 64.125 ;
     RECT  2.16 64.395 235.44 64.665 ;
     RECT  2.16 64.935 235.44 65.205 ;
     RECT  2.16 65.475 235.44 65.745 ;
     RECT  2.16 66.015 235.44 66.285 ;
     RECT  2.16 66.555 235.44 66.825 ;
     RECT  2.16 67.095 235.44 67.365 ;
     RECT  2.16 67.635 235.44 67.905 ;
     RECT  2.16 68.175 235.44 68.445 ;
     RECT  2.16 68.715 235.44 68.985 ;
     RECT  2.16 69.255 235.44 69.525 ;
     RECT  2.16 69.795 235.44 70.065 ;
     RECT  2.16 70.335 235.44 70.605 ;
     RECT  2.16 70.875 235.44 71.145 ;
     RECT  2.16 71.415 235.44 71.685 ;
     RECT  2.16 71.955 235.44 72.225 ;
     RECT  2.16 72.495 235.44 72.765 ;
     RECT  2.16 73.035 235.44 73.305 ;
     RECT  2.16 73.575 235.44 73.845 ;
     RECT  2.16 74.115 235.44 74.385 ;
     RECT  2.16 74.655 235.44 74.925 ;
     RECT  2.16 75.195 235.44 75.465 ;
     RECT  2.16 75.735 235.44 76.005 ;
     RECT  2.16 76.275 235.44 76.545 ;
     RECT  2.16 76.815 235.44 77.085 ;
     RECT  2.16 77.355 235.44 77.625 ;
     RECT  2.16 77.895 235.44 78.165 ;
     RECT  2.16 78.435 235.44 78.705 ;
     RECT  2.16 78.975 235.44 79.245 ;
     RECT  2.16 79.515 235.44 79.785 ;
     RECT  2.16 80.055 235.44 80.325 ;
     RECT  2.16 80.595 235.44 80.865 ;
     RECT  2.16 81.135 235.44 81.405 ;
     RECT  2.16 81.675 235.44 81.945 ;
     RECT  2.16 82.215 235.44 82.485 ;
     RECT  2.16 82.755 235.44 83.025 ;
     RECT  2.16 83.295 235.44 83.565 ;
     RECT  2.16 83.835 235.44 84.105 ;
    LAYER M1 ;
     RECT  2.16 2.151 235.44 25.929 ;
     RECT  31.536 28.08 205.656 57.816 ;
     RECT  2.16 25.929 29.484 59.931 ;
     RECT  207.684 25.929 235.44 59.931 ;
     RECT  2.16 59.931 235.44 84.249 ;
    LAYER M2 ;
     RECT  2.16 2.151 3.667 84.249 ;
     RECT  3.667 2.106 4.847 84.249 ;
     RECT  5.287 1.188 5.495 1.206 ;
     RECT  5.539 1.152 5.639 1.17 ;
     RECT  7.123 1.152 7.727 1.17 ;
     RECT  4.847 2.151 8.815 84.249 ;
     RECT  8.815 2.106 9.175 84.249 ;
     RECT  8.815 0.036 9.751 0.054 ;
     RECT  9.175 2.034 10.679 84.249 ;
     RECT  9.751 0.036 11.939 0.549 ;
     RECT  11.939 0.036 12.443 0.054 ;
     RECT  10.679 2.151 15.295 84.249 ;
     RECT  15.295 2.034 16.439 84.249 ;
     RECT  16.439 2.106 17.195 84.249 ;
     RECT  18.247 0.576 19.751 0.594 ;
     RECT  17.195 2.151 19.795 84.249 ;
     RECT  19.795 2.106 21.155 84.249 ;
     RECT  21.155 2.151 22.207 84.249 ;
     RECT  22.207 2.106 27.167 84.249 ;
     RECT  27.167 2.151 29.484 84.249 ;
     RECT  29.484 2.151 29.507 33.642 ;
     RECT  29.507 31.806 29.52 33.642 ;
     RECT  29.484 34.47 29.52 37.269 ;
     RECT  29.484 49.86 29.52 84.249 ;
     RECT  29.507 2.151 29.543 30.834 ;
     RECT  29.543 2.151 29.579 30.744 ;
     RECT  29.484 39.096 29.651 47.574 ;
     RECT  29.52 34.47 29.687 36.684 ;
     RECT  29.52 49.86 29.975 54.198 ;
     RECT  29.484 48.366 30.011 48.564 ;
     RECT  29.52 31.806 30.083 32.328 ;
     RECT  29.975 51.606 30.083 54.198 ;
     RECT  29.687 34.47 30.227 36.612 ;
     RECT  29.651 39.636 30.227 47.574 ;
     RECT  30.227 34.47 30.263 34.488 ;
     RECT  30.227 40.446 30.263 47.574 ;
     RECT  30.083 31.968 30.299 32.328 ;
     RECT  30.227 35.514 30.299 35.532 ;
     RECT  29.52 33.624 30.307 33.642 ;
     RECT  30.307 33.156 30.407 33.642 ;
     RECT  29.52 55.026 30.443 84.249 ;
     RECT  29.579 30.276 30.451 30.744 ;
     RECT  30.299 32.04 30.479 32.328 ;
     RECT  30.263 41.076 30.515 47.574 ;
     RECT  29.975 49.86 30.515 50.814 ;
     RECT  30.479 32.04 30.551 32.058 ;
     RECT  30.083 51.606 30.623 54.162 ;
     RECT  30.407 33.624 30.659 33.642 ;
     RECT  30.623 51.606 30.659 51.894 ;
     RECT  30.623 53.028 30.731 54.162 ;
     RECT  30.451 30.276 30.767 30.789 ;
     RECT  30.515 41.886 30.767 47.574 ;
     RECT  30.011 48.366 30.767 48.456 ;
     RECT  30.515 49.986 30.767 50.814 ;
     RECT  30.767 41.886 30.803 42.084 ;
     RECT  30.767 43.38 30.803 47.304 ;
     RECT  29.579 2.151 31.135 29.484 ;
     RECT  30.767 30.276 31.135 30.294 ;
     RECT  30.227 39.636 31.207 39.654 ;
     RECT  31.135 2.151 31.536 30.294 ;
     RECT  31.207 33.822 31.536 33.84 ;
     RECT  30.227 36.594 31.536 36.612 ;
     RECT  31.207 39.411 31.536 39.969 ;
     RECT  30.515 41.076 31.536 41.094 ;
     RECT  30.803 41.886 31.536 41.904 ;
     RECT  30.803 43.686 31.536 47.304 ;
     RECT  30.767 48.438 31.536 48.456 ;
     RECT  30.767 50.13 31.536 50.814 ;
     RECT  30.731 53.028 31.536 53.856 ;
     RECT  30.443 55.026 31.536 55.278 ;
     RECT  30.443 56.106 31.536 84.249 ;
     RECT  31.536 2.151 45.175 84.249 ;
     RECT  45.175 2.106 45.383 84.249 ;
     RECT  45.383 2.151 68.171 84.249 ;
     RECT  68.171 2.151 80.483 27.126 ;
     RECT  80.483 2.151 84.019 26.28 ;
     RECT  84.019 2.106 84.695 26.28 ;
     RECT  84.695 2.151 85.855 26.28 ;
     RECT  85.855 2.106 86.747 26.28 ;
     RECT  80.483 27.072 105.467 27.126 ;
     RECT  86.747 2.151 105.799 26.28 ;
     RECT  105.467 27.072 105.799 27.09 ;
     RECT  105.799 2.151 114.259 27.09 ;
     RECT  114.259 1.656 119.947 27.09 ;
     RECT  119.947 1.656 137.083 27.162 ;
     RECT  68.171 28.08 137.083 84.249 ;
     RECT  137.083 1.656 170.231 84.249 ;
     RECT  170.231 1.692 205.656 84.249 ;
     RECT  205.656 29.646 205.799 34.794 ;
     RECT  205.799 30.384 205.907 34.794 ;
     RECT  205.656 38.952 206.303 48.96 ;
     RECT  206.303 47.016 206.419 48.96 ;
     RECT  205.656 49.752 206.419 50.814 ;
     RECT  205.656 56.736 206.527 84.249 ;
     RECT  205.656 53.298 206.563 53.388 ;
     RECT  205.656 54.414 206.563 55.008 ;
     RECT  206.419 47.016 206.779 50.814 ;
     RECT  206.527 56.106 206.815 84.249 ;
     RECT  206.779 47.016 206.887 51.156 ;
     RECT  205.907 30.384 206.959 33.948 ;
     RECT  205.907 34.776 206.959 34.794 ;
     RECT  206.887 47.016 207.355 51.624 ;
     RECT  206.563 53.298 207.355 55.008 ;
     RECT  206.959 30.384 207.499 35.262 ;
     RECT  205.656 36.252 207.499 38.124 ;
     RECT  206.303 38.952 207.499 46.134 ;
     RECT  207.355 47.016 207.499 55.008 ;
     RECT  207.499 46.926 207.571 55.008 ;
     RECT  206.815 55.998 207.571 84.249 ;
     RECT  207.499 30.384 207.643 46.134 ;
     RECT  207.571 46.926 207.643 84.249 ;
     RECT  205.656 1.692 207.684 28.584 ;
     RECT  207.643 30.384 207.684 84.249 ;
     RECT  207.684 1.692 212.963 84.249 ;
     RECT  212.963 2.106 215.879 84.249 ;
     RECT  215.879 2.151 235.44 84.249 ;
     RECT  235.44 23.058 235.679 24.228 ;
     RECT  235.44 78.444 235.679 80.622 ;
     RECT  235.44 58.896 235.895 59.184 ;
     RECT  235.895 59.166 235.931 59.184 ;
     RECT  235.44 9.666 235.967 14.634 ;
     RECT  235.44 15.426 235.967 17.874 ;
     RECT  235.679 24.21 235.967 24.228 ;
     RECT  235.44 61.164 235.967 65.934 ;
     RECT  235.44 7.056 236.003 7.956 ;
     RECT  235.967 16.236 236.003 17.874 ;
     RECT  235.679 78.516 236.003 80.622 ;
     RECT  236.003 7.056 236.039 7.884 ;
     RECT  235.44 81.756 236.039 84.024 ;
     RECT  235.44 25.182 236.075 36.072 ;
     RECT  235.967 9.666 236.219 13.968 ;
     RECT  235.44 77.634 236.255 77.652 ;
     RECT  236.075 26.946 236.327 36.072 ;
     RECT  236.219 9.666 236.399 13.464 ;
     RECT  236.399 12.906 236.471 13.464 ;
     RECT  236.399 9.666 236.507 12.042 ;
     RECT  236.003 16.236 236.507 16.794 ;
     RECT  236.327 26.946 236.507 29.016 ;
     RECT  235.44 36.828 236.507 38.034 ;
     RECT  235.44 44.082 236.507 45.72 ;
     RECT  235.44 46.584 236.507 54.702 ;
     RECT  235.44 55.566 236.507 58.104 ;
     RECT  235.967 61.164 236.507 65.268 ;
     RECT  236.507 9.666 236.543 10.116 ;
     RECT  236.507 10.98 236.543 11.934 ;
     RECT  236.471 13.176 236.543 13.464 ;
     RECT  236.507 16.236 236.543 16.254 ;
     RECT  236.507 28.728 236.543 29.016 ;
     RECT  236.327 30.078 236.543 36.072 ;
     RECT  236.507 37.404 236.543 38.034 ;
     RECT  236.507 44.928 236.543 45.72 ;
     RECT  236.507 46.584 236.543 50.382 ;
     RECT  236.507 51.174 236.543 51.66 ;
     RECT  236.507 55.566 236.543 55.944 ;
     RECT  236.507 56.736 236.543 58.104 ;
     RECT  236.507 61.164 236.543 64.584 ;
     RECT  236.039 82.026 236.543 84.024 ;
     RECT  236.543 13.446 236.579 13.464 ;
     RECT  236.075 25.182 236.579 26.199 ;
     RECT  236.507 26.946 236.579 27.936 ;
     RECT  236.543 30.078 236.579 31.014 ;
     RECT  236.543 32.04 236.579 33.714 ;
     RECT  236.543 44.928 236.579 44.946 ;
     RECT  236.543 46.584 236.579 47.88 ;
     RECT  236.543 48.978 236.579 50.382 ;
     RECT  236.543 51.174 236.579 51.534 ;
     RECT  236.507 52.488 236.579 54.702 ;
     RECT  236.543 57.186 236.579 58.104 ;
     RECT  236.543 61.164 236.579 62.694 ;
     RECT  236.003 80.136 236.579 80.622 ;
     RECT  236.543 82.026 236.579 82.044 ;
     RECT  236.543 9.666 236.615 9.954 ;
     RECT  236.579 25.182 236.615 25.659 ;
     RECT  236.579 32.238 236.615 33.714 ;
     RECT  236.579 46.782 236.615 46.8 ;
     RECT  236.579 47.862 236.615 47.88 ;
     RECT  236.579 61.596 236.615 62.064 ;
     RECT  236.615 25.488 236.651 25.659 ;
     RECT  236.543 34.74 236.651 36.072 ;
     RECT  236.579 54.108 236.651 54.504 ;
     RECT  235.679 23.058 236.687 23.31 ;
     RECT  236.579 52.488 236.687 52.974 ;
     RECT  236.651 25.56 236.723 25.659 ;
     RECT  236.543 37.404 237.371 37.62 ;
     RECT  236.579 48.978 237.379 50.31 ;
     RECT  236.651 35.172 237.407 36.072 ;
     RECT  236.615 32.742 237.415 33.714 ;
     RECT  237.415 32.706 237.443 33.714 ;
     RECT  237.407 35.172 237.443 35.766 ;
     RECT  237.379 48.366 237.443 50.31 ;
     RECT  236.579 51.174 237.443 51.192 ;
     RECT  236.579 80.604 237.443 80.622 ;
     RECT  236.039 7.704 237.479 7.884 ;
     RECT  235.967 15.426 237.479 15.444 ;
     RECT  236.003 17.586 237.479 17.874 ;
     RECT  236.687 23.292 237.479 23.31 ;
     RECT  236.579 26.946 237.479 27.36 ;
     RECT  237.371 37.602 237.479 37.62 ;
     RECT  237.443 48.366 237.479 48.384 ;
     RECT  237.443 49.626 237.479 50.31 ;
     RECT  236.579 57.618 237.479 58.104 ;
     RECT  235.44 60.012 237.479 60.174 ;
     RECT  236.543 11.106 237.487 11.124 ;
     RECT  236.615 9.666 237.515 9.684 ;
     RECT  237.487 10.872 237.515 11.124 ;
     RECT  237.479 17.586 237.515 17.604 ;
     RECT  236.723 25.641 237.515 25.659 ;
     RECT  237.479 26.946 237.515 27.198 ;
     RECT  236.579 30.996 237.515 31.014 ;
     RECT  237.443 32.706 237.515 33.57 ;
     RECT  237.443 35.172 237.515 35.19 ;
     RECT  236.507 44.082 237.515 44.1 ;
     RECT  237.415 47.016 237.515 47.034 ;
     RECT  237.479 50.292 237.515 50.31 ;
     RECT  236.687 52.488 237.515 52.506 ;
     RECT  236.651 54.108 237.515 54.126 ;
     RECT  237.479 57.618 237.515 57.636 ;
     RECT  237.479 60.156 237.515 60.174 ;
     RECT  236.615 62.046 237.515 62.064 ;
     RECT  236.543 64.566 237.515 64.584 ;
     RECT  236.003 78.516 237.515 79.2 ;
     RECT  237.515 78.516 237.551 78.534 ;
     RECT  237.479 7.704 237.587 7.722 ;
     RECT  237.515 10.872 237.587 10.89 ;
    LAYER M3 ;
     RECT  8.82 0.031 8.838 0.091 ;
     RECT  18.612 0.043 18.63 0.091 ;
     RECT  20.16 0.043 20.178 0.091 ;
     RECT  4.104 0.091 7.794 0.139 ;
     RECT  11.376 0.091 11.394 0.139 ;
     RECT  15.948 0.091 18.63 0.139 ;
     RECT  118.44 0.091 118.458 0.139 ;
     RECT  124.2 0.091 124.218 0.139 ;
     RECT  4.032 0.139 7.794 0.187 ;
     RECT  10.836 0.139 11.394 0.187 ;
     RECT  15.552 0.139 18.63 0.187 ;
     RECT  19.548 0.091 20.718 0.187 ;
     RECT  118.44 0.139 118.746 0.187 ;
     RECT  123.624 0.139 124.506 0.187 ;
     RECT  125.532 0.091 125.55 0.187 ;
     RECT  10.836 0.187 11.502 0.235 ;
     RECT  12.42 0.031 12.438 0.235 ;
     RECT  122.076 0.091 122.094 0.235 ;
     RECT  8.748 0.091 8.838 0.269 ;
     RECT  41.508 0.091 41.526 0.523 ;
     RECT  42.372 0.091 44.874 0.523 ;
     RECT  9.756 0.52 9.774 0.557 ;
     RECT  83.664 0.091 84.834 0.571 ;
     RECT  118.44 0.187 119.106 0.571 ;
     RECT  122.076 0.235 122.13 0.571 ;
     RECT  10.836 0.235 12.438 0.619 ;
     RECT  108.684 0.571 108.702 0.619 ;
     RECT  2.88 0.091 2.898 0.811 ;
     RECT  15.552 0.187 20.718 1.099 ;
     RECT  3.96 0.187 7.794 1.147 ;
     RECT  8.748 0.269 8.766 1.147 ;
     RECT  10.728 0.619 12.438 1.147 ;
     RECT  15.552 1.099 20.79 1.147 ;
     RECT  41.508 0.523 44.874 1.147 ;
     RECT  46.296 0.139 46.314 1.147 ;
     RECT  86.976 0.091 86.994 1.147 ;
     RECT  110.736 0.091 110.754 1.147 ;
     RECT  112.284 0.091 112.302 1.147 ;
     RECT  41.508 1.147 44.946 1.195 ;
     RECT  45.756 1.147 46.314 1.195 ;
     RECT  86.688 1.147 86.994 1.195 ;
     RECT  123.624 0.187 125.55 1.195 ;
     RECT  110.124 1.147 110.754 1.627 ;
     RECT  108.684 0.619 108.81 1.675 ;
     RECT  109.98 1.627 110.754 1.675 ;
     RECT  123.624 1.195 125.586 1.675 ;
     RECT  83.664 0.571 85.302 1.723 ;
     RECT  86.688 1.195 87.318 1.723 ;
     RECT  108.576 1.675 108.81 1.723 ;
     RECT  109.836 1.675 111.114 1.723 ;
     RECT  112.284 1.147 112.734 1.723 ;
     RECT  118.224 0.571 119.106 1.723 ;
     RECT  121.68 0.571 122.13 1.723 ;
     RECT  123.012 1.675 125.586 1.723 ;
     RECT  83.664 1.723 87.318 1.771 ;
     RECT  3.852 1.147 8.766 1.819 ;
     RECT  9.864 1.147 12.438 1.819 ;
     RECT  15.552 1.147 21.258 2.029 ;
     RECT  3.852 1.819 12.438 2.101 ;
     RECT  118.224 1.723 125.586 2.101 ;
     RECT  2.772 0.811 2.898 2.143 ;
     RECT  82.872 0.139 82.89 2.143 ;
     RECT  83.664 1.771 87.534 2.143 ;
     RECT  118.224 2.101 126.09 2.143 ;
     RECT  143.604 1.915 143.622 2.143 ;
     RECT  153.972 2.059 153.99 2.143 ;
     RECT  170.208 1.651 170.226 2.143 ;
     RECT  203.004 2.065 203.022 2.143 ;
     RECT  212.94 1.687 212.958 2.143 ;
     RECT  15.3 2.029 21.258 2.191 ;
     RECT  82.872 2.143 87.534 2.191 ;
     RECT  108.576 1.723 112.734 2.191 ;
     RECT  150.192 2.155 150.21 2.191 ;
     RECT  152.748 2.155 152.766 2.191 ;
     RECT  175.215 2.143 175.305 2.191 ;
     RECT  138.816 2.191 138.834 2.203 ;
     RECT  22.212 2.101 22.23 2.219 ;
     RECT  144.72 2.011 144.738 2.219 ;
     RECT  155.088 2.059 155.106 2.219 ;
     RECT  15.12 2.191 21.258 2.227 ;
     RECT  138.42 2.203 138.834 2.227 ;
     RECT  141.588 2.191 141.966 2.227 ;
     RECT  142.815 2.143 143.622 2.227 ;
     RECT  146.124 2.191 146.142 2.227 ;
     RECT  150.192 2.191 150.606 2.227 ;
     RECT  152.316 2.191 152.766 2.227 ;
     RECT  166.176 2.191 166.194 2.227 ;
     RECT  152.316 2.227 152.838 2.251 ;
     RECT  162.468 1.963 162.486 2.251 ;
     RECT  82.872 2.191 87.714 2.255 ;
     RECT  2.415 2.143 2.898 2.263 ;
     RECT  3.672 2.101 12.438 2.263 ;
     RECT  41.508 1.195 46.314 2.263 ;
     RECT  83.016 2.255 87.714 2.263 ;
     RECT  132.015 2.143 132.105 2.263 ;
     RECT  128.16 1.687 128.178 2.299 ;
     RECT  128.916 2.101 128.934 2.299 ;
     RECT  132.015 2.263 132.39 2.299 ;
     RECT  138.42 2.227 139.158 2.299 ;
     RECT  141.588 2.227 143.622 2.299 ;
     RECT  150.192 2.227 151.29 2.299 ;
     RECT  152.028 2.251 152.838 2.299 ;
     RECT  153.615 2.143 153.99 2.299 ;
     RECT  166.176 2.227 166.302 2.299 ;
     RECT  169.815 2.143 170.226 2.299 ;
     RECT  174.816 2.191 175.305 2.299 ;
     RECT  180.615 2.143 180.705 2.299 ;
     RECT  24.015 2.143 24.105 2.335 ;
     RECT  118.224 2.143 126.705 2.335 ;
     RECT  138.276 2.299 139.446 2.335 ;
     RECT  141.156 2.299 143.622 2.335 ;
     RECT  144.864 2.227 146.142 2.335 ;
     RECT  147.42 2.263 147.438 2.335 ;
     RECT  149.076 2.191 149.094 2.335 ;
     RECT  149.976 2.299 151.29 2.335 ;
     RECT  152.028 2.299 153.99 2.335 ;
     RECT  154.728 2.299 154.746 2.335 ;
     RECT  164.415 2.143 164.505 2.335 ;
     RECT  165.312 2.251 165.33 2.335 ;
     RECT  169.815 2.299 170.334 2.335 ;
     RECT  174.564 2.299 175.305 2.335 ;
     RECT  15.048 2.227 21.258 2.371 ;
     RECT  21.996 2.263 22.086 2.371 ;
     RECT  23.364 2.335 24.174 2.371 ;
     RECT  41.508 2.263 46.746 2.371 ;
     RECT  118.224 2.335 126.774 2.371 ;
     RECT  129.888 2.065 129.906 2.371 ;
     RECT  137.415 2.143 137.505 2.371 ;
     RECT  162.468 2.251 162.738 2.371 ;
     RECT  163.8 2.335 165.33 2.371 ;
     RECT  166.176 2.299 166.482 2.371 ;
     RECT  169.815 2.335 170.442 2.371 ;
     RECT  174.024 2.335 175.305 2.371 ;
     RECT  176.04 2.299 176.058 2.371 ;
     RECT  13.215 2.143 13.305 2.413 ;
     RECT  29.415 2.143 29.505 2.413 ;
     RECT  34.815 2.143 34.905 2.413 ;
     RECT  40.215 2.143 40.305 2.413 ;
     RECT  41.112 2.371 46.746 2.413 ;
     RECT  51.015 2.143 51.105 2.413 ;
     RECT  56.415 2.143 56.505 2.413 ;
     RECT  61.815 2.143 61.905 2.413 ;
     RECT  67.215 2.143 67.305 2.413 ;
     RECT  72.615 2.143 72.705 2.413 ;
     RECT  78.015 2.143 78.105 2.413 ;
     RECT  88.815 2.143 88.905 2.413 ;
     RECT  94.215 2.143 94.305 2.413 ;
     RECT  99.615 2.143 99.705 2.413 ;
     RECT  105.015 2.143 105.105 2.413 ;
     RECT  115.815 2.143 115.905 2.413 ;
     RECT  118.188 2.371 126.774 2.413 ;
     RECT  136.44 2.371 137.505 2.413 ;
     RECT  138.24 2.335 139.482 2.413 ;
     RECT  148.215 2.143 148.305 2.413 ;
     RECT  149.076 2.335 151.29 2.413 ;
     RECT  159.015 2.143 159.105 2.413 ;
     RECT  186.015 2.143 186.105 2.413 ;
     RECT  191.415 2.143 191.505 2.413 ;
     RECT  196.815 2.143 196.905 2.413 ;
     RECT  207.615 2.143 207.705 2.413 ;
     RECT  212.94 2.143 213.105 2.413 ;
     RECT  218.415 2.143 218.505 2.413 ;
     RECT  223.815 2.143 223.905 2.413 ;
     RECT  229.215 2.143 229.305 2.413 ;
     RECT  234.615 2.143 234.705 2.413 ;
     RECT  114.264 1.651 114.282 2.461 ;
     RECT  118.188 2.413 126.897 2.461 ;
     RECT  129.888 2.371 130.554 2.461 ;
     RECT  171.36 2.371 171.738 2.461 ;
     RECT  83.016 2.263 87.75 2.489 ;
     RECT  22.86 2.371 24.642 2.497 ;
     RECT  25.38 2.299 25.398 2.497 ;
     RECT  171.36 2.461 171.846 2.497 ;
     RECT  140.976 2.335 143.622 2.533 ;
     RECT  178.812 2.497 178.83 2.533 ;
     RECT  140.616 2.533 143.622 2.569 ;
     RECT  162.468 2.371 165.33 2.569 ;
     RECT  166.176 2.371 166.554 2.569 ;
     RECT  183.636 2.371 183.654 2.569 ;
     RECT  171.324 2.497 171.846 2.587 ;
     RECT  162.468 2.569 166.554 2.597 ;
     RECT  173.844 2.371 176.094 2.597 ;
     RECT  108.576 2.191 113.202 2.605 ;
     RECT  114.012 2.461 114.282 2.605 ;
     RECT  118.188 2.461 127.17 2.605 ;
     RECT  136.44 2.413 139.482 2.605 ;
     RECT  140.616 2.569 143.766 2.605 ;
     RECT  171.288 2.587 171.846 2.605 ;
     RECT  172.728 2.299 172.818 2.605 ;
     RECT  173.844 2.597 175.497 2.605 ;
     RECT  178.812 2.533 179.118 2.605 ;
     RECT  22.86 2.497 25.398 2.641 ;
     RECT  83.196 2.489 87.75 2.641 ;
     RECT  88.815 2.413 89.097 2.641 ;
     RECT  108.576 2.605 114.282 2.641 ;
     RECT  118.08 2.605 127.17 2.641 ;
     RECT  128.16 2.299 128.934 2.641 ;
     RECT  133.416 2.605 133.434 2.641 ;
     RECT  134.82 2.605 134.838 2.641 ;
     RECT  136.44 2.605 139.734 2.641 ;
     RECT  144.864 2.335 146.178 2.641 ;
     RECT  147.24 2.335 147.438 2.641 ;
     RECT  148.215 2.413 151.29 2.641 ;
     RECT  157.608 2.605 157.734 2.641 ;
     RECT  159.015 2.413 159.297 2.641 ;
     RECT  169.344 2.371 170.442 2.641 ;
     RECT  178.596 2.605 179.118 2.641 ;
     RECT  180.615 2.299 181.17 2.641 ;
     RECT  182.988 2.569 183.654 2.641 ;
     RECT  115.815 2.413 116.097 2.731 ;
     RECT  118.08 2.641 128.934 2.731 ;
     RECT  140.616 2.605 143.802 2.731 ;
     RECT  144.864 2.641 146.394 2.731 ;
     RECT  147.204 2.641 151.29 2.731 ;
     RECT  155.484 2.263 155.934 2.731 ;
     RECT  157.608 2.641 159.297 2.731 ;
     RECT  178.596 2.641 179.262 2.731 ;
     RECT  180.615 2.641 183.654 2.731 ;
     RECT  40.215 2.413 46.746 2.759 ;
     RECT  117.972 2.731 128.934 2.767 ;
     RECT  129.888 2.461 130.626 2.767 ;
     RECT  133.416 2.641 139.878 2.795 ;
     RECT  15.048 2.371 22.086 2.803 ;
     RECT  78.015 2.413 78.297 2.803 ;
     RECT  117.972 2.767 130.626 2.803 ;
     RECT  157.32 2.731 159.297 2.803 ;
     RECT  160.92 2.641 161.658 2.803 ;
     RECT  167.688 2.533 167.706 2.803 ;
     RECT  38.772 2.569 38.79 2.831 ;
     RECT  2.415 2.263 12.438 2.839 ;
     RECT  117.972 2.803 130.698 2.839 ;
     RECT  144.864 2.731 151.29 2.839 ;
     RECT  152.028 2.335 154.746 2.839 ;
     RECT  164.415 2.597 166.554 2.839 ;
     RECT  167.364 2.803 167.706 2.839 ;
     RECT  83.196 2.641 89.097 2.861 ;
     RECT  134.82 2.795 139.878 2.861 ;
     RECT  22.86 2.641 25.938 2.875 ;
     RECT  155.484 2.731 156.186 2.875 ;
     RECT  157.32 2.803 161.658 2.875 ;
     RECT  131.616 2.299 132.39 2.911 ;
     RECT  134.856 2.861 139.878 2.911 ;
     RECT  140.616 2.731 143.874 2.911 ;
     RECT  169.344 2.641 170.55 2.911 ;
     RECT  171.288 2.605 175.497 2.911 ;
     RECT  178.596 2.731 179.334 2.911 ;
     RECT  27.144 2.101 27.162 3.001 ;
     RECT  131.616 2.911 132.462 3.001 ;
     RECT  133.416 2.795 134.082 3.001 ;
     RECT  144.864 2.839 154.746 3.001 ;
     RECT  155.484 2.875 161.658 3.001 ;
     RECT  162.468 2.597 163.566 3.001 ;
     RECT  176.4 2.803 176.562 3.001 ;
     RECT  32.184 2.533 32.202 3.029 ;
     RECT  144.792 3.001 154.746 3.065 ;
     RECT  14.868 2.803 22.086 3.073 ;
     RECT  186.015 2.413 186.297 3.109 ;
     RECT  115.776 2.731 116.097 3.115 ;
     RECT  14.724 3.073 22.086 3.145 ;
     RECT  22.86 2.875 25.974 3.145 ;
     RECT  27.144 3.001 27.342 3.145 ;
     RECT  134.856 2.911 143.91 3.145 ;
     RECT  144.792 3.065 149.13 3.145 ;
     RECT  180.615 2.731 183.978 3.145 ;
     RECT  196.815 2.413 197.097 3.163 ;
     RECT  207.615 2.413 207.897 3.163 ;
     RECT  41.292 2.759 46.746 3.181 ;
     RECT  149.868 3.065 154.746 3.181 ;
     RECT  155.484 3.001 163.566 3.181 ;
     RECT  164.415 2.839 167.706 3.181 ;
     RECT  176.4 3.001 176.742 3.181 ;
     RECT  185.832 3.109 186.297 3.181 ;
     RECT  196.704 3.163 197.097 3.209 ;
     RECT  207.504 3.163 207.897 3.209 ;
     RECT  41.292 3.181 47.646 3.245 ;
     RECT  117.972 2.839 130.842 3.259 ;
     RECT  131.616 3.001 134.082 3.259 ;
     RECT  164.415 3.181 168.354 3.271 ;
     RECT  169.344 2.911 175.497 3.271 ;
     RECT  176.4 3.181 177.426 3.271 ;
     RECT  178.596 2.911 179.766 3.271 ;
     RECT  29.415 2.413 29.697 3.301 ;
     RECT  29.415 3.301 30.186 3.307 ;
     RECT  185.688 3.181 186.714 3.307 ;
     RECT  218.415 2.413 218.697 3.307 ;
     RECT  214.344 3.163 214.362 3.341 ;
     RECT  2.376 2.839 12.438 3.343 ;
     RECT  164.415 3.271 175.497 3.343 ;
     RECT  149.868 3.181 163.566 3.379 ;
     RECT  164.415 3.343 175.626 3.379 ;
     RECT  176.4 3.271 179.766 3.379 ;
     RECT  2.34 3.343 12.438 3.389 ;
     RECT  2.376 3.389 12.438 3.415 ;
     RECT  13.215 2.413 13.497 3.415 ;
     RECT  134.856 3.145 149.13 3.443 ;
     RECT  29.415 3.307 30.51 3.451 ;
     RECT  31.248 3.379 31.266 3.451 ;
     RECT  108.576 2.641 114.354 3.451 ;
     RECT  115.236 3.115 116.097 3.451 ;
     RECT  149.868 3.379 179.766 3.451 ;
     RECT  180.615 3.145 184.554 3.451 ;
     RECT  14.724 3.145 25.974 3.541 ;
     RECT  90.072 3.181 90.09 3.605 ;
     RECT  2.376 3.415 13.497 3.613 ;
     RECT  14.724 3.541 26.19 3.613 ;
     RECT  134.856 3.443 146.142 3.643 ;
     RECT  40.215 2.759 40.497 3.649 ;
     RECT  41.292 3.245 47.286 3.649 ;
     RECT  83.304 2.861 89.097 3.649 ;
     RECT  108.576 3.451 116.097 3.649 ;
     RECT  185.688 3.307 186.822 3.649 ;
     RECT  117.972 3.259 134.082 3.685 ;
     RECT  134.82 3.643 146.142 3.685 ;
     RECT  187.74 3.649 187.758 3.685 ;
     RECT  2.376 3.613 26.19 3.721 ;
     RECT  27.144 3.145 27.558 3.721 ;
     RECT  29.415 3.451 31.266 3.721 ;
     RECT  83.304 3.649 89.298 3.721 ;
     RECT  91.116 3.685 91.134 3.721 ;
     RECT  187.74 3.685 187.866 3.721 ;
     RECT  108.36 3.649 116.097 3.749 ;
     RECT  2.376 3.721 27.558 3.811 ;
     RECT  28.296 3.721 31.266 3.811 ;
     RECT  149.868 3.451 184.77 3.811 ;
     RECT  185.544 3.649 186.822 3.811 ;
     RECT  149.868 3.811 186.822 3.835 ;
     RECT  187.668 3.721 187.866 3.835 ;
     RECT  91.044 3.721 91.134 3.839 ;
     RECT  92.088 3.721 92.106 3.839 ;
     RECT  146.952 3.443 149.13 3.875 ;
     RECT  94.215 2.413 94.497 3.955 ;
     RECT  149.868 3.835 187.866 3.955 ;
     RECT  40.215 3.649 47.286 3.983 ;
     RECT  2.376 3.811 31.266 3.991 ;
     RECT  41.256 3.983 47.286 3.991 ;
     RECT  83.304 3.721 89.802 3.991 ;
     RECT  147.204 3.875 149.13 3.991 ;
     RECT  149.868 3.955 188.19 3.991 ;
     RECT  2.376 3.991 31.914 4.081 ;
     RECT  33.264 3.919 33.498 4.081 ;
     RECT  117.864 3.685 146.142 4.189 ;
     RECT  2.376 4.081 32.058 4.217 ;
     RECT  82.656 3.991 89.802 4.217 ;
     RECT  33.264 4.081 33.786 4.225 ;
     RECT  27.036 4.217 32.058 4.261 ;
     RECT  33.192 4.225 33.786 4.261 ;
     RECT  34.815 2.413 35.097 4.261 ;
     RECT  202.215 2.143 203.022 4.261 ;
     RECT  93.708 3.955 94.497 4.289 ;
     RECT  117.864 4.189 146.178 4.351 ;
     RECT  27.036 4.261 35.097 4.415 ;
     RECT  117.864 4.351 146.322 4.415 ;
     RECT  34.344 4.415 35.097 4.459 ;
     RECT  36.18 4.261 36.198 4.459 ;
     RECT  33.192 4.415 33.498 4.487 ;
     RECT  77.976 2.803 78.297 4.523 ;
     RECT  106.596 4.423 106.614 4.523 ;
     RECT  34.344 4.459 36.198 4.531 ;
     RECT  33.192 4.487 33.39 4.541 ;
     RECT  116.82 4.495 116.838 4.555 ;
     RECT  117.864 4.415 146.25 4.555 ;
     RECT  34.344 4.531 37.134 4.559 ;
     RECT  34.815 4.559 37.134 4.621 ;
     RECT  40.215 3.983 40.497 4.621 ;
     RECT  147.204 3.991 188.55 4.621 ;
     RECT  196.815 3.209 197.097 4.621 ;
     RECT  34.815 4.621 37.422 4.649 ;
     RECT  194.508 4.621 194.526 4.765 ;
     RECT  195.336 4.171 195.354 4.765 ;
     RECT  196.164 4.621 197.097 4.765 ;
     RECT  198.396 4.621 198.918 4.765 ;
     RECT  36.432 4.649 37.422 4.801 ;
     RECT  194.004 4.765 194.526 4.801 ;
     RECT  195.336 4.765 197.097 4.801 ;
     RECT  198.396 4.765 199.206 4.801 ;
     RECT  205.884 4.729 205.902 4.801 ;
     RECT  147.204 4.621 189.018 4.891 ;
     RECT  36.432 4.801 37.458 4.919 ;
     RECT  221.688 2.827 221.706 4.919 ;
     RECT  36.432 4.919 37.422 4.955 ;
     RECT  38.232 4.801 38.394 4.955 ;
     RECT  83.232 4.217 89.802 4.963 ;
     RECT  218.415 3.307 219.15 4.999 ;
     RECT  36.432 4.955 37.314 5.027 ;
     RECT  201.852 4.261 203.022 5.035 ;
     RECT  205.884 4.801 206.37 5.035 ;
     RECT  211.536 4.891 211.554 5.035 ;
     RECT  83.124 4.963 89.802 5.071 ;
     RECT  229.215 2.413 229.497 5.071 ;
     RECT  36.468 5.027 37.314 5.117 ;
     RECT  201.384 5.035 203.022 5.131 ;
     RECT  2.376 4.217 26.298 5.161 ;
     RECT  27.036 4.415 32.238 5.161 ;
     RECT  116.82 4.555 146.25 5.161 ;
     RECT  147.132 4.891 189.018 5.161 ;
     RECT  198.396 4.801 200.142 5.161 ;
     RECT  201.384 5.131 203.562 5.161 ;
     RECT  205.344 5.035 206.37 5.161 ;
     RECT  208.656 4.219 208.674 5.161 ;
     RECT  33.228 4.541 33.39 5.189 ;
     RECT  38.268 4.955 38.394 5.189 ;
     RECT  222.3 4.999 222.39 5.189 ;
     RECT  192.996 2.605 193.014 5.197 ;
     RECT  194.004 4.801 197.097 5.197 ;
     RECT  38.268 5.189 38.286 5.225 ;
     RECT  191.415 2.413 191.697 5.269 ;
     RECT  192.996 5.197 197.097 5.269 ;
     RECT  198.396 5.161 203.562 5.269 ;
     RECT  204.444 5.161 206.37 5.269 ;
     RECT  211.428 5.035 211.554 5.269 ;
     RECT  192.996 5.269 203.598 5.275 ;
     RECT  83.088 5.071 89.802 5.305 ;
     RECT  210.708 5.269 211.554 5.305 ;
     RECT  212.94 2.413 213.297 5.305 ;
     RECT  33.264 5.189 33.39 5.341 ;
     RECT  34.815 4.649 35.478 5.341 ;
     RECT  192.672 5.275 203.598 5.341 ;
     RECT  204.444 5.269 206.442 5.341 ;
     RECT  210.708 5.305 211.734 5.341 ;
     RECT  212.904 5.305 213.354 5.341 ;
     RECT  218.304 4.999 219.15 5.341 ;
     RECT  228.636 5.071 229.497 5.341 ;
     RECT  208.656 5.161 208.782 5.431 ;
     RECT  212.904 5.341 213.93 5.459 ;
     RECT  108.864 3.749 116.097 5.467 ;
     RECT  116.82 5.161 189.018 5.467 ;
     RECT  192.672 5.341 203.634 5.467 ;
     RECT  204.408 5.341 206.442 5.467 ;
     RECT  210.492 5.341 211.734 5.467 ;
     RECT  2.376 5.161 32.238 5.495 ;
     RECT  190.98 5.269 191.697 5.503 ;
     RECT  218.304 5.341 219.618 5.503 ;
     RECT  215.856 2.101 215.874 5.515 ;
     RECT  106.596 5.341 106.614 5.531 ;
     RECT  25.632 5.495 32.238 5.567 ;
     RECT  218.268 5.503 219.618 5.575 ;
     RECT  208.656 5.431 208.962 5.611 ;
     RECT  209.88 5.467 211.734 5.611 ;
     RECT  2.376 5.495 24.858 5.639 ;
     RECT  41.256 3.991 48.006 5.645 ;
     RECT  207.615 3.209 207.897 5.701 ;
     RECT  208.656 5.611 211.986 5.701 ;
     RECT  218.016 5.575 219.618 5.701 ;
     RECT  41.292 5.645 48.006 5.729 ;
     RECT  190.908 5.503 191.697 5.737 ;
     RECT  192.672 5.467 206.442 5.737 ;
     RECT  41.58 5.729 48.006 5.801 ;
     RECT  207.18 5.701 211.986 5.801 ;
     RECT  212.904 5.459 213.894 5.809 ;
     RECT  232.596 5.611 232.614 5.809 ;
     RECT  190.908 5.737 206.442 5.881 ;
     RECT  207.18 5.801 209.394 5.881 ;
     RECT  210.348 5.801 211.986 5.881 ;
     RECT  212.832 5.809 213.894 5.881 ;
     RECT  215.856 5.515 216.306 5.881 ;
     RECT  217.512 5.701 219.618 5.881 ;
     RECT  25.668 5.567 32.238 5.909 ;
     RECT  32.22 5.909 32.238 5.971 ;
     RECT  33.264 5.341 35.478 5.971 ;
     RECT  222.372 5.189 222.39 5.971 ;
     RECT  210.348 5.881 213.894 5.999 ;
     RECT  39.924 4.621 40.497 6.035 ;
     RECT  32.22 5.971 35.478 6.079 ;
     RECT  36.468 5.117 37.17 6.079 ;
     RECT  82.656 5.305 89.802 6.125 ;
     RECT  210.348 5.999 211.842 6.143 ;
     RECT  222.156 5.971 222.39 6.151 ;
     RECT  223.815 2.413 224.097 6.151 ;
     RECT  190.908 5.881 209.394 6.179 ;
     RECT  72.615 2.413 72.897 6.235 ;
     RECT  78.015 4.523 78.297 6.235 ;
     RECT  212.58 5.999 213.894 6.241 ;
     RECT  215.856 5.881 219.618 6.241 ;
     RECT  220.752 6.151 222.39 6.241 ;
     RECT  232.596 5.809 232.686 6.241 ;
     RECT  82.656 6.125 82.674 6.269 ;
     RECT  108.864 5.467 189.018 6.269 ;
     RECT  190.908 6.179 209.286 6.269 ;
     RECT  72.615 6.235 72.99 6.275 ;
     RECT  78.015 6.235 78.39 6.275 ;
     RECT  212.58 6.241 214.362 6.277 ;
     RECT  232.596 6.241 232.794 6.277 ;
     RECT  2.415 5.639 24.858 6.313 ;
     RECT  25.668 5.909 31.446 6.313 ;
     RECT  215.856 6.241 222.534 6.313 ;
     RECT  109.332 6.269 189.018 6.341 ;
     RECT  228.636 5.341 230.094 6.349 ;
     RECT  212.58 6.277 215.082 6.376 ;
     RECT  190.908 6.269 209.142 6.385 ;
     RECT  212.58 6.376 215.118 6.412 ;
     RECT  215.856 6.313 222.822 6.412 ;
     RECT  189.756 6.349 189.774 6.421 ;
     RECT  190.764 6.385 209.142 6.421 ;
     RECT  212.58 6.412 222.822 6.421 ;
     RECT  228.528 6.349 230.094 6.421 ;
     RECT  109.332 6.341 179.226 6.539 ;
     RECT  223.815 6.151 224.19 6.547 ;
     RECT  228.528 6.421 230.238 6.547 ;
     RECT  226.08 6.547 226.098 6.619 ;
     RECT  226.08 6.619 226.17 6.655 ;
     RECT  232.524 6.277 232.794 6.655 ;
     RECT  32.22 6.079 37.17 6.691 ;
     RECT  210.348 6.143 211.806 6.691 ;
     RECT  225.684 6.655 226.17 6.691 ;
     RECT  228.06 6.547 230.238 6.691 ;
     RECT  232.344 6.655 232.794 6.691 ;
     RECT  41.832 5.801 48.006 6.763 ;
     RECT  2.415 6.313 31.446 6.844 ;
     RECT  32.22 6.691 37.242 6.844 ;
     RECT  83.415 6.125 89.802 6.845 ;
     RECT  210.276 6.691 211.806 6.925 ;
     RECT  232.344 6.691 233.442 6.925 ;
     RECT  2.415 6.844 37.242 6.955 ;
     RECT  225.684 6.691 226.422 6.961 ;
     RECT  210.276 6.925 211.842 7.051 ;
     RECT  212.58 6.421 223.074 7.051 ;
     RECT  225.18 6.961 227.286 7.051 ;
     RECT  84.888 6.845 89.802 7.079 ;
     RECT  112.104 6.539 179.226 7.079 ;
     RECT  225.108 7.051 227.286 7.079 ;
     RECT  83.415 6.845 84.042 7.085 ;
     RECT  189.756 6.421 209.142 7.099 ;
     RECT  210.276 7.051 223.074 7.099 ;
     RECT  180 6.341 189.018 7.115 ;
     RECT  84.924 7.079 89.802 7.151 ;
     RECT  2.415 6.955 37.314 7.159 ;
     RECT  183.816 7.115 189.018 7.159 ;
     RECT  189.756 7.099 223.074 7.159 ;
     RECT  232.056 6.925 233.442 7.195 ;
     RECT  234.615 2.413 234.897 7.195 ;
     RECT  86.364 7.151 89.802 7.223 ;
     RECT  41.58 6.763 48.006 7.231 ;
     RECT  91.044 3.839 91.062 7.231 ;
     RECT  234.615 7.195 235.062 7.231 ;
     RECT  112.104 7.079 148.842 7.277 ;
     RECT  109.332 6.539 111.366 7.321 ;
     RECT  112.104 7.277 148.497 7.321 ;
     RECT  232.056 7.195 233.622 7.321 ;
     RECT  234.468 7.231 235.098 7.321 ;
     RECT  84.924 7.151 85.554 7.349 ;
     RECT  90.54 7.231 91.062 7.349 ;
     RECT  225.108 7.079 227.214 7.349 ;
     RECT  223.815 6.547 224.298 7.357 ;
     RECT  225.108 7.349 226.422 7.357 ;
     RECT  227.196 7.349 227.214 7.421 ;
     RECT  183.816 7.159 223.074 7.429 ;
     RECT  223.815 7.357 226.422 7.429 ;
     RECT  228.06 6.691 230.598 7.435 ;
     RECT  41.544 7.231 48.006 7.501 ;
     RECT  49.068 3.181 49.086 7.501 ;
     RECT  149.616 7.079 179.226 7.501 ;
     RECT  180 7.115 182.61 7.501 ;
     RECT  232.056 7.321 235.134 7.501 ;
     RECT  228.06 7.435 230.958 7.591 ;
     RECT  232.02 7.501 235.134 7.591 ;
     RECT  183.816 7.429 226.422 7.661 ;
     RECT  2.415 7.159 37.35 7.663 ;
     RECT  2.415 7.663 37.566 7.771 ;
     RECT  91.044 7.349 91.062 7.799 ;
     RECT  228.06 7.591 235.134 7.861 ;
     RECT  237.564 7.699 237.582 7.861 ;
     RECT  106.596 7.771 106.614 7.889 ;
     RECT  109.332 7.321 148.497 7.889 ;
     RECT  211.464 7.661 226.422 7.889 ;
     RECT  183.816 7.661 210.618 7.897 ;
     RECT  2.415 7.771 37.71 7.925 ;
     RECT  112.176 7.889 148.497 7.925 ;
     RECT  38.772 7.771 38.79 7.933 ;
     RECT  41.544 7.501 49.086 7.933 ;
     RECT  236.016 7.051 236.034 7.933 ;
     RECT  38.592 7.933 38.79 7.961 ;
     RECT  112.212 7.925 148.497 8.041 ;
     RECT  149.616 7.501 182.61 8.041 ;
     RECT  183.348 7.897 210.618 8.041 ;
     RECT  2.415 7.925 37.494 8.159 ;
     RECT  112.212 8.041 210.618 8.159 ;
     RECT  101.988 8.131 102.006 8.189 ;
     RECT  2.415 8.159 37.35 8.195 ;
     RECT  226.404 7.889 226.422 8.267 ;
     RECT  41.544 7.933 49.194 8.311 ;
     RECT  228.06 7.861 235.17 8.311 ;
     RECT  235.98 7.933 236.034 8.311 ;
     RECT  109.332 7.889 111.366 8.339 ;
     RECT  103.536 8.311 103.554 8.381 ;
     RECT  41.436 8.311 49.41 8.429 ;
     RECT  149.58 8.159 210.618 8.437 ;
     RECT  211.464 7.889 225.486 8.437 ;
     RECT  2.415 8.195 37.314 8.525 ;
     RECT  149.58 8.437 225.486 8.525 ;
     RECT  149.616 8.525 225.486 8.537 ;
     RECT  227.988 8.311 236.034 8.537 ;
     RECT  215.532 8.537 225.486 8.671 ;
     RECT  41.436 8.429 49.266 8.735 ;
     RECT  110.415 8.339 111.366 8.743 ;
     RECT  112.212 8.159 148.842 8.743 ;
     RECT  40.215 6.035 40.497 8.779 ;
     RECT  41.436 8.735 48.114 8.779 ;
     RECT  149.616 8.537 214.614 8.969 ;
     RECT  3.42 8.525 37.314 9.041 ;
     RECT  3.42 9.041 3.438 9.113 ;
     RECT  4.212 9.041 37.314 9.121 ;
     RECT  97.668 3.685 97.686 9.211 ;
     RECT  4.212 9.121 37.458 9.239 ;
     RECT  215.532 8.671 226.134 9.319 ;
     RECT  215.46 9.319 226.134 9.355 ;
     RECT  226.908 8.941 226.926 9.355 ;
     RECT  4.212 9.239 37.386 9.389 ;
     RECT  38.592 7.961 38.61 9.391 ;
     RECT  215.46 9.355 226.926 9.499 ;
     RECT  110.415 8.743 148.842 9.553 ;
     RECT  149.616 8.969 214.146 9.553 ;
     RECT  215.46 9.499 227.178 9.625 ;
     RECT  97.668 9.211 97.794 9.661 ;
     RECT  97.668 9.661 98.334 9.689 ;
     RECT  110.415 9.553 214.146 9.739 ;
     RECT  109.332 8.339 109.35 9.751 ;
     RECT  110.268 9.739 214.146 9.751 ;
     RECT  109.332 9.751 214.146 9.787 ;
     RECT  48.996 8.735 49.266 9.823 ;
     RECT  51.015 2.413 51.297 9.823 ;
     RECT  215.28 9.625 227.178 9.823 ;
     RECT  109.332 9.787 214.326 9.859 ;
     RECT  215.1 9.823 227.178 9.859 ;
     RECT  228.024 8.537 236.034 9.859 ;
     RECT  105.015 2.413 105.297 9.883 ;
     RECT  40.215 8.779 48.114 9.895 ;
     RECT  48.924 9.823 49.302 9.895 ;
     RECT  40.215 9.895 49.374 9.931 ;
     RECT  109.332 9.859 236.034 9.931 ;
     RECT  4.248 9.389 37.386 10.021 ;
     RECT  38.304 9.391 38.61 10.021 ;
     RECT  40.215 9.931 49.878 10.049 ;
     RECT  109.332 9.931 236.61 10.049 ;
     RECT  105.015 9.883 105.39 10.061 ;
     RECT  50.688 9.823 51.297 10.085 ;
     RECT  40.215 10.049 49.374 10.121 ;
     RECT  153.396 10.049 236.61 10.121 ;
     RECT  222.192 10.121 236.61 10.157 ;
     RECT  153.396 10.121 221.454 10.253 ;
     RECT  109.332 10.049 152.622 10.267 ;
     RECT  109.152 10.267 152.622 10.315 ;
     RECT  108.828 10.315 152.622 10.349 ;
     RECT  108.828 10.349 109.35 10.355 ;
     RECT  237.456 7.861 237.582 10.445 ;
     RECT  107.748 10.555 107.766 10.595 ;
     RECT  4.248 10.021 38.61 10.625 ;
     RECT  153.396 10.253 214.47 10.625 ;
     RECT  106.416 10.561 106.434 10.637 ;
     RECT  153.396 10.625 204.138 10.661 ;
     RECT  38.232 10.625 38.61 10.669 ;
     RECT  4.248 10.625 37.422 10.733 ;
     RECT  109.152 10.355 109.35 10.829 ;
     RECT  222.264 10.157 236.61 10.829 ;
     RECT  67.215 2.413 67.497 10.831 ;
     RECT  110.268 10.349 152.622 10.831 ;
     RECT  153.396 10.661 204.066 10.831 ;
     RECT  227.664 10.829 236.61 10.832 ;
     RECT  215.244 10.253 221.454 10.867 ;
     RECT  67.104 10.831 67.497 10.877 ;
     RECT  68.868 10.831 68.886 10.877 ;
     RECT  237.492 10.445 237.582 10.895 ;
     RECT  215.244 10.867 221.526 10.903 ;
     RECT  222.264 10.829 226.602 10.903 ;
     RECT  40.215 10.121 49.266 10.975 ;
     RECT  40.215 10.975 49.41 11.011 ;
     RECT  51.015 10.085 51.297 11.011 ;
     RECT  204.912 10.625 214.47 11.011 ;
     RECT  215.244 10.903 226.602 11.011 ;
     RECT  227.664 10.832 235.422 11.039 ;
     RECT  109.332 10.829 109.35 11.101 ;
     RECT  110.268 10.831 204.066 11.101 ;
     RECT  236.52 10.832 236.61 11.117 ;
     RECT  85.212 7.349 85.554 11.237 ;
     RECT  38.232 10.669 39.33 11.245 ;
     RECT  40.215 11.011 51.297 11.245 ;
     RECT  204.912 11.011 226.602 11.273 ;
     RECT  227.808 11.039 235.422 11.273 ;
     RECT  231.84 11.273 235.422 11.309 ;
     RECT  4.248 10.733 37.35 11.323 ;
     RECT  109.332 11.101 204.066 11.407 ;
     RECT  38.232 11.245 51.297 11.435 ;
     RECT  237.492 10.895 237.51 11.501 ;
     RECT  109.332 11.407 204.174 11.659 ;
     RECT  204.912 11.273 225.81 11.659 ;
     RECT  236.52 11.117 236.538 11.659 ;
     RECT  3.816 11.323 37.35 11.669 ;
     RECT  85.212 11.237 85.23 11.705 ;
     RECT  93.852 4.289 94.497 11.777 ;
     RECT  227.808 11.273 230.994 11.821 ;
     RECT  4.104 11.669 37.35 11.849 ;
     RECT  109.332 11.659 225.81 11.849 ;
     RECT  236.484 11.659 236.538 11.851 ;
     RECT  2.415 8.525 2.697 11.911 ;
     RECT  227.736 11.821 230.994 11.939 ;
     RECT  236.448 11.851 236.538 11.947 ;
     RECT  231.84 11.309 235.134 11.975 ;
     RECT  226.584 11.273 226.602 12.091 ;
     RECT  2.415 11.911 2.898 12.139 ;
     RECT  38.232 11.435 49.698 12.181 ;
     RECT  227.844 11.939 230.994 12.181 ;
     RECT  2.415 12.139 3.042 12.209 ;
     RECT  4.248 11.849 37.35 12.217 ;
     RECT  38.124 12.181 49.698 12.217 ;
     RECT  232.056 11.975 235.134 12.235 ;
     RECT  226.224 12.091 226.602 12.281 ;
     RECT  236.412 11.947 236.538 12.331 ;
     RECT  226.26 12.281 226.602 12.353 ;
     RECT  4.248 12.217 49.698 12.361 ;
     RECT  106.596 12.289 106.614 12.389 ;
     RECT  226.26 12.353 226.278 12.389 ;
     RECT  236.376 12.331 236.538 12.427 ;
     RECT  2.415 12.209 2.862 12.479 ;
     RECT  109.332 11.849 225.45 12.479 ;
     RECT  4.248 12.361 50.166 12.487 ;
     RECT  51.015 11.435 51.297 12.487 ;
     RECT  2.415 12.479 2.754 12.515 ;
     RECT  236.196 12.427 236.538 12.619 ;
     RECT  4.248 12.487 51.297 12.631 ;
     RECT  227.844 12.181 231.138 12.721 ;
     RECT  232.056 12.235 235.386 12.721 ;
     RECT  109.332 12.479 225.342 12.763 ;
     RECT  82.26 12.757 82.278 12.797 ;
     RECT  227.844 12.721 235.386 12.811 ;
     RECT  236.196 12.619 236.574 12.811 ;
     RECT  108.72 12.763 225.342 12.893 ;
     RECT  227.844 12.811 236.574 12.893 ;
     RECT  227.844 12.893 230.022 12.901 ;
     RECT  4.248 12.631 51.426 12.929 ;
     RECT  82.584 12.901 82.602 12.941 ;
     RECT  56.415 2.413 56.697 12.991 ;
     RECT  78.015 6.275 78.297 12.991 ;
     RECT  99.615 2.413 99.897 12.991 ;
     RECT  108.72 12.893 225.198 12.991 ;
     RECT  227.736 12.901 230.022 13.019 ;
     RECT  56.304 12.991 56.697 13.037 ;
     RECT  58.14 12.991 58.158 13.037 ;
     RECT  77.904 12.991 78.297 13.037 ;
     RECT  99.504 12.991 99.897 13.037 ;
     RECT  108.396 12.991 225.198 13.037 ;
     RECT  108.72 13.037 225.198 13.085 ;
     RECT  228.024 13.019 229.878 13.085 ;
     RECT  230.76 12.893 236.574 13.325 ;
     RECT  4.248 12.929 51.297 13.397 ;
     RECT  230.76 13.325 230.814 13.397 ;
     RECT  88.056 7.223 89.802 13.469 ;
     RECT  231.984 13.325 236.574 13.469 ;
     RECT  4.248 13.397 47.214 13.483 ;
     RECT  2.415 12.515 2.697 13.531 ;
     RECT  3.636 13.483 47.214 13.531 ;
     RECT  2.415 13.531 47.214 13.559 ;
     RECT  2.415 13.559 3.33 13.568 ;
     RECT  97.776 9.689 98.334 13.595 ;
     RECT  230.76 13.397 230.778 13.595 ;
     RECT  228.024 13.085 229.806 13.613 ;
     RECT  109.332 13.085 225.198 13.711 ;
     RECT  228.024 13.613 229.497 13.945 ;
     RECT  88.056 13.469 89.622 13.973 ;
     RECT  109.332 13.711 225.702 13.973 ;
     RECT  231.984 13.469 236.214 13.973 ;
     RECT  146.088 13.973 225.702 14.207 ;
     RECT  215.28 14.207 225.702 14.251 ;
     RECT  97.776 13.595 97.794 14.405 ;
     RECT  215.28 14.251 225.738 14.405 ;
     RECT  215.352 14.405 225.738 14.441 ;
     RECT  231.984 13.973 235.962 14.639 ;
     RECT  215.388 14.441 225.738 14.683 ;
     RECT  109.332 13.973 145.278 14.755 ;
     RECT  146.088 14.207 214.542 14.755 ;
     RECT  230.436 14.611 230.454 14.755 ;
     RECT  215.388 14.683 225.99 14.791 ;
     RECT  230.436 14.755 230.562 14.881 ;
     RECT  231.984 14.639 235.314 14.909 ;
     RECT  230.436 14.881 230.85 14.953 ;
     RECT  4.248 13.559 47.214 14.989 ;
     RECT  47.952 13.397 51.297 14.989 ;
     RECT  215.388 14.791 226.458 14.989 ;
     RECT  109.332 14.755 214.542 15.025 ;
     RECT  215.388 14.989 226.53 15.089 ;
     RECT  227.736 13.945 229.497 15.151 ;
     RECT  230.22 14.953 230.85 15.151 ;
     RECT  232.488 14.909 235.314 15.179 ;
     RECT  109.332 15.025 214.614 15.187 ;
     RECT  215.388 15.089 225.486 15.187 ;
     RECT  54.72 15.019 54.738 15.197 ;
     RECT  227.736 15.151 230.85 15.197 ;
     RECT  226.296 15.089 226.53 15.251 ;
     RECT  227.736 15.197 229.497 15.331 ;
     RECT  230.22 15.197 230.85 15.331 ;
     RECT  232.488 15.179 235.17 15.359 ;
     RECT  227.448 15.331 229.497 15.389 ;
     RECT  237.456 12.907 237.474 15.449 ;
     RECT  64.332 15.448 64.35 15.485 ;
     RECT  86.364 7.223 87.066 15.629 ;
     RECT  227.592 15.389 229.497 15.629 ;
     RECT  64.656 15.601 64.674 15.677 ;
     RECT  226.296 15.251 226.314 15.719 ;
     RECT  227.7 15.629 229.497 15.827 ;
     RECT  227.88 15.827 229.497 15.979 ;
     RECT  230.22 15.331 231.21 15.979 ;
     RECT  232.488 15.359 235.134 15.979 ;
     RECT  227.88 15.979 231.21 16.105 ;
     RECT  232.308 15.979 235.134 16.105 ;
     RECT  109.332 15.187 225.486 16.141 ;
     RECT  235.944 16.033 235.962 16.171 ;
     RECT  235.944 16.171 236.538 16.259 ;
     RECT  109.332 16.141 225.558 16.295 ;
     RECT  87.048 15.629 87.066 16.439 ;
     RECT  4.248 14.989 51.297 16.565 ;
     RECT  227.88 16.105 235.134 16.651 ;
     RECT  235.944 16.259 236.502 16.651 ;
     RECT  227.88 16.651 236.502 16.709 ;
     RECT  228.384 16.709 236.502 16.799 ;
     RECT  109.332 16.295 225.486 16.807 ;
     RECT  88.2 13.973 89.622 16.835 ;
     RECT  237.492 16.363 237.51 16.843 ;
     RECT  108.864 16.807 225.486 16.871 ;
     RECT  228.384 16.799 235.998 16.979 ;
     RECT  227.628 16.843 227.646 17.035 ;
     RECT  227.484 17.035 227.646 17.069 ;
     RECT  228.384 16.979 235.422 17.069 ;
     RECT  227.484 17.069 227.502 17.105 ;
     RECT  231.12 17.069 235.134 17.105 ;
     RECT  228.384 17.069 228.438 17.114 ;
     RECT  232.308 17.105 235.134 17.117 ;
     RECT  177.156 16.871 225.486 17.185 ;
     RECT  4.284 16.565 51.297 17.221 ;
     RECT  177.156 17.185 225.522 17.339 ;
     RECT  228.42 17.114 228.438 17.339 ;
     RECT  232.452 17.117 235.134 17.339 ;
     RECT  232.452 17.339 235.062 17.375 ;
     RECT  177.156 17.339 177.822 17.411 ;
     RECT  233.496 17.375 235.062 17.411 ;
     RECT  4.284 17.221 51.354 17.491 ;
     RECT  178.56 17.339 225.522 17.491 ;
     RECT  108.864 16.871 176.094 17.519 ;
     RECT  229.215 17.069 230.31 17.519 ;
     RECT  106.596 16.411 106.614 17.609 ;
     RECT  231.12 17.105 231.138 17.609 ;
     RECT  237.456 16.843 237.51 17.609 ;
     RECT  177.156 17.411 177.786 17.725 ;
     RECT  178.56 17.491 225.702 17.761 ;
     RECT  56.415 13.037 56.697 17.851 ;
     RECT  178.56 17.761 225.846 17.879 ;
     RECT  233.568 17.411 235.026 17.879 ;
     RECT  237.456 17.609 237.474 17.879 ;
     RECT  56.304 17.851 56.697 17.888 ;
     RECT  233.568 17.879 234.897 17.915 ;
     RECT  163.512 17.519 176.094 17.923 ;
     RECT  4.284 17.491 51.462 17.981 ;
     RECT  177.12 17.725 177.786 17.995 ;
     RECT  108.864 17.519 162.594 18.029 ;
     RECT  88.776 16.835 89.622 18.059 ;
     RECT  232.452 17.375 232.47 18.091 ;
     RECT  231.984 18.091 232.47 18.121 ;
     RECT  4.284 17.981 47.682 18.149 ;
     RECT  231.588 18.121 232.47 18.149 ;
     RECT  231.588 18.149 231.606 18.173 ;
     RECT  163.512 17.923 176.13 18.193 ;
     RECT  176.868 17.995 177.786 18.193 ;
     RECT  48.456 17.981 51.462 18.301 ;
     RECT  163.512 18.193 177.786 18.301 ;
     RECT  178.56 17.879 225.558 18.301 ;
     RECT  48.456 18.301 51.534 18.419 ;
     RECT  233.712 17.915 234.897 18.419 ;
     RECT  229.215 17.519 229.662 18.571 ;
     RECT  48.456 18.419 51.462 18.689 ;
     RECT  106.596 18.499 106.614 18.689 ;
     RECT  48.456 18.689 51.39 18.725 ;
     RECT  108.864 18.029 162.522 18.725 ;
     RECT  163.512 18.301 225.558 18.725 ;
     RECT  163.512 18.725 185.166 18.761 ;
     RECT  113.184 18.725 162.522 18.769 ;
     RECT  163.512 18.761 183.078 18.769 ;
     RECT  113.184 18.769 183.078 18.797 ;
     RECT  228.996 18.571 229.662 18.797 ;
     RECT  186.015 18.725 225.558 18.805 ;
     RECT  108.864 18.725 112.41 18.869 ;
     RECT  113.184 18.797 182.826 18.869 ;
     RECT  113.184 18.869 133.002 19.067 ;
     RECT  88.815 18.059 89.622 19.103 ;
     RECT  48.456 18.725 51.297 19.111 ;
     RECT  88.815 19.103 89.19 19.133 ;
     RECT  113.184 19.067 128.322 19.139 ;
     RECT  183.888 18.761 185.166 19.229 ;
     RECT  4.284 18.149 47.574 19.243 ;
     RECT  48.42 19.111 51.297 19.243 ;
     RECT  186.015 18.805 225.63 19.345 ;
     RECT  226.584 17.347 226.602 19.345 ;
     RECT  133.776 18.869 182.826 19.409 ;
     RECT  109.332 18.869 112.41 19.471 ;
     RECT  113.184 19.139 128.25 19.471 ;
     RECT  149.616 19.409 182.826 19.535 ;
     RECT  186.015 19.345 226.602 19.573 ;
     RECT  183.888 19.229 185.13 19.651 ;
     RECT  109.332 19.471 128.25 19.771 ;
     RECT  129.132 19.067 133.002 19.849 ;
     RECT  133.776 19.409 148.878 19.849 ;
     RECT  149.76 19.535 182.826 19.885 ;
     RECT  183.636 19.651 185.13 19.885 ;
     RECT  109.224 19.771 128.25 19.921 ;
     RECT  185.976 19.573 226.602 20.011 ;
     RECT  149.76 19.885 185.13 20.047 ;
     RECT  185.904 20.011 226.602 20.047 ;
     RECT  4.284 19.243 51.297 20.111 ;
     RECT  109.224 19.921 128.322 20.155 ;
     RECT  129.132 19.849 148.878 20.155 ;
     RECT  229.215 18.797 229.662 20.191 ;
     RECT  109.224 20.155 148.878 20.309 ;
     RECT  7.704 20.111 51.297 20.461 ;
     RECT  149.76 20.047 226.602 20.489 ;
     RECT  232.452 18.149 232.47 20.539 ;
     RECT  7.704 20.461 51.462 20.615 ;
     RECT  135.432 20.309 148.878 20.695 ;
     RECT  149.76 20.489 195.498 20.695 ;
     RECT  4.284 20.111 6.714 20.731 ;
     RECT  229.068 20.191 229.662 20.779 ;
     RECT  232.344 20.539 232.47 20.821 ;
     RECT  232.344 20.821 232.65 20.849 ;
     RECT  232.452 20.849 232.65 20.861 ;
     RECT  109.224 20.309 134.622 20.885 ;
     RECT  228.996 20.779 229.662 21.001 ;
     RECT  228.492 21.001 229.662 21.053 ;
     RECT  109.764 20.885 134.622 21.127 ;
     RECT  135.432 20.695 195.498 21.127 ;
     RECT  4.176 20.731 6.714 21.235 ;
     RECT  7.704 20.615 51.297 21.235 ;
     RECT  109.764 21.127 195.498 21.355 ;
     RECT  196.38 20.489 226.602 21.355 ;
     RECT  4.032 21.235 6.714 21.361 ;
     RECT  7.668 21.235 51.297 21.361 ;
     RECT  109.764 21.355 226.602 21.389 ;
     RECT  109.764 21.389 134.91 21.395 ;
     RECT  135.72 21.389 226.602 21.667 ;
     RECT  109.764 21.395 134.73 21.695 ;
     RECT  135.72 21.667 227.286 21.695 ;
     RECT  109.836 21.695 134.73 21.929 ;
     RECT  2.415 13.568 2.697 22.171 ;
     RECT  4.032 21.361 51.297 22.171 ;
     RECT  163.008 21.695 227.286 22.207 ;
     RECT  232.452 20.861 232.47 22.235 ;
     RECT  133.128 21.929 134.73 22.279 ;
     RECT  135.72 21.695 162.27 22.279 ;
     RECT  110.415 21.929 132.354 22.307 ;
     RECT  133.128 22.279 162.27 22.307 ;
     RECT  2.415 22.171 51.297 22.351 ;
     RECT  163.008 22.207 227.43 22.351 ;
     RECT  148.176 22.307 162.27 22.507 ;
     RECT  163.008 22.351 228.006 22.507 ;
     RECT  2.415 22.351 52.002 22.577 ;
     RECT  2.415 22.577 51.894 22.739 ;
     RECT  33.084 22.739 51.75 22.775 ;
     RECT  33.084 22.775 51.297 22.811 ;
     RECT  230.724 22.207 230.742 22.819 ;
     RECT  133.128 22.307 147.114 22.843 ;
     RECT  33.084 22.811 49.158 22.883 ;
     RECT  110.415 22.307 123.858 22.883 ;
     RECT  148.176 22.507 228.006 22.891 ;
     RECT  229.068 21.053 229.662 22.891 ;
     RECT  148.176 22.891 229.662 23.009 ;
     RECT  124.668 22.307 132.354 23.035 ;
     RECT  124.596 23.035 132.354 23.053 ;
     RECT  133.092 22.843 147.114 23.053 ;
     RECT  230.58 22.819 230.742 23.053 ;
     RECT  2.415 22.739 32.346 23.081 ;
     RECT  234.615 18.419 234.897 23.125 ;
     RECT  149.616 23.009 229.662 23.161 ;
     RECT  230.58 23.053 230.886 23.161 ;
     RECT  148.176 23.009 148.878 23.264 ;
     RECT  33.084 22.883 49.122 23.279 ;
     RECT  2.415 23.081 32.238 23.315 ;
     RECT  33.3 23.279 49.122 23.315 ;
     RECT  117.54 22.883 123.858 23.323 ;
     RECT  124.596 23.053 147.114 23.323 ;
     RECT  117.54 23.323 147.114 23.357 ;
     RECT  140.436 23.357 147.114 23.359 ;
     RECT  148.068 23.264 148.878 23.359 ;
     RECT  149.616 23.161 230.886 23.387 ;
     RECT  149.616 23.387 181.782 23.423 ;
     RECT  233.568 23.287 233.586 23.431 ;
     RECT  234.615 23.125 235.242 23.431 ;
     RECT  182.664 23.387 230.886 23.557 ;
     RECT  233.568 23.431 235.242 23.557 ;
     RECT  117.54 23.357 139.59 23.585 ;
     RECT  140.436 23.359 148.878 23.585 ;
     RECT  149.616 23.423 181.746 23.585 ;
     RECT  232.704 23.431 232.722 23.591 ;
     RECT  182.664 23.557 231.606 23.593 ;
     RECT  232.704 23.591 232.758 23.593 ;
     RECT  233.568 23.557 235.674 23.593 ;
     RECT  117.54 23.585 139.554 23.597 ;
     RECT  110.415 22.883 116.802 23.629 ;
     RECT  117.54 23.597 139.482 23.629 ;
     RECT  147.996 23.585 148.878 23.657 ;
     RECT  232.704 23.593 235.674 23.665 ;
     RECT  182.664 23.593 231.75 23.701 ;
     RECT  148.068 23.657 148.878 23.791 ;
     RECT  149.616 23.585 160.11 23.791 ;
     RECT  49.932 22.811 51.297 23.819 ;
     RECT  110.415 23.629 139.482 23.819 ;
     RECT  49.932 23.819 49.95 23.855 ;
     RECT  182.664 23.701 231.822 23.855 ;
     RECT  110.415 23.819 120.474 23.891 ;
     RECT  148.068 23.791 160.11 23.891 ;
     RECT  110.415 23.891 119.502 23.927 ;
     RECT  231.732 23.855 231.822 23.935 ;
     RECT  231.732 23.935 231.93 23.971 ;
     RECT  232.668 23.665 235.674 23.971 ;
     RECT  33.336 23.315 49.122 24.089 ;
     RECT  115.704 23.927 119.502 24.089 ;
     RECT  148.068 23.891 155.322 24.089 ;
     RECT  182.664 23.855 230.994 24.089 ;
     RECT  115.776 24.089 119.322 24.125 ;
     RECT  115.776 24.125 119.214 24.161 ;
     RECT  115.815 24.161 119.214 24.197 ;
     RECT  161.46 23.585 181.746 24.205 ;
     RECT  231.732 23.971 235.674 24.205 ;
     RECT  236.664 23.053 236.682 24.205 ;
     RECT  110.415 23.927 114.75 24.233 ;
     RECT  121.215 23.819 139.482 24.331 ;
     RECT  140.436 23.585 147.222 24.331 ;
     RECT  156.6 23.891 160.11 24.331 ;
     RECT  161.46 24.205 181.818 24.331 ;
     RECT  33.336 24.089 48.942 24.359 ;
     RECT  110.415 24.233 111.186 24.359 ;
     RECT  111.996 24.233 114.75 24.359 ;
     RECT  118.044 24.197 119.214 24.359 ;
     RECT  156.6 24.331 181.818 24.379 ;
     RECT  182.664 24.089 195.786 24.379 ;
     RECT  115.815 24.197 117.234 24.395 ;
     RECT  118.188 24.359 119.214 24.395 ;
     RECT  121.215 24.331 147.222 24.395 ;
     RECT  156.6 24.379 195.786 24.461 ;
     RECT  113.364 24.359 114.714 24.467 ;
     RECT  118.188 24.395 118.602 24.467 ;
     RECT  3.708 23.315 32.238 24.503 ;
     RECT  113.616 24.467 113.634 24.539 ;
     RECT  33.336 24.359 46.998 24.571 ;
     RECT  2.415 23.315 2.697 24.601 ;
     RECT  33.048 24.571 46.998 24.629 ;
     RECT  130.248 24.395 147.222 24.629 ;
     RECT  2.376 24.601 2.697 24.653 ;
     RECT  118.188 24.467 118.314 24.665 ;
     RECT  160.956 24.461 195.786 24.665 ;
     RECT  120.276 23.891 120.474 24.709 ;
     RECT  121.215 24.395 129.294 24.709 ;
     RECT  148.215 24.089 155.322 24.737 ;
     RECT  161.244 24.665 195.786 24.737 ;
     RECT  2.415 24.653 2.697 24.745 ;
     RECT  3.708 24.503 10.854 24.745 ;
     RECT  120.276 24.709 129.294 24.749 ;
     RECT  136.368 24.629 147.222 24.781 ;
     RECT  156.6 24.461 160.146 24.781 ;
     RECT  130.248 24.629 135.162 24.809 ;
     RECT  136.368 24.781 147.33 24.811 ;
     RECT  196.56 24.089 230.994 24.848 ;
     RECT  231.732 24.205 236.682 24.848 ;
     RECT  99.615 13.037 99.897 24.871 ;
     RECT  120.276 24.749 127.278 24.871 ;
     RECT  33.048 24.629 43.254 24.899 ;
     RECT  119.772 24.871 127.278 24.899 ;
     RECT  128.052 24.749 129.294 24.899 ;
     RECT  130.464 24.809 135.162 24.899 ;
     RECT  136.368 24.811 147.366 24.899 ;
     RECT  148.215 24.737 150.786 24.899 ;
     RECT  161.244 24.737 192.582 24.899 ;
     RECT  111.996 24.359 112.014 24.935 ;
     RECT  119.772 24.899 126.897 24.935 ;
     RECT  128.232 24.899 129.294 24.935 ;
     RECT  130.464 24.899 132.642 24.935 ;
     RECT  136.368 24.899 144.486 24.935 ;
     RECT  161.244 24.899 176.454 24.935 ;
     RECT  177.192 24.899 187.218 24.935 ;
     RECT  193.32 24.737 195.786 24.935 ;
     RECT  150.516 24.899 150.642 24.941 ;
     RECT  133.38 24.899 135.162 24.971 ;
     RECT  145.44 24.899 147.366 24.989 ;
     RECT  122.76 24.935 126.897 25.007 ;
     RECT  133.488 24.971 133.614 25.007 ;
     RECT  134.352 24.971 135.162 25.007 ;
     RECT  136.368 24.935 138.582 25.007 ;
     RECT  145.44 24.989 147.33 25.007 ;
     RECT  105.015 10.061 105.297 25.015 ;
     RECT  128.808 24.935 129.294 25.043 ;
     RECT  130.536 24.935 132.297 25.043 ;
     RECT  133.596 25.007 133.614 25.043 ;
     RECT  151.524 24.737 155.322 25.043 ;
     RECT  33.048 24.899 40.698 25.079 ;
     RECT  119.772 24.935 122.022 25.079 ;
     RECT  122.76 25.007 125.55 25.079 ;
     RECT  128.808 25.043 129.258 25.079 ;
     RECT  134.352 25.007 135.018 25.079 ;
     RECT  136.548 25.007 138.582 25.079 ;
     RECT  139.68 24.935 144.09 25.079 ;
     RECT  145.44 25.007 147.294 25.079 ;
     RECT  150.552 24.941 150.642 25.079 ;
     RECT  161.244 24.935 173.538 25.079 ;
     RECT  177.192 24.935 182.61 25.085 ;
     RECT  44.388 24.629 46.998 25.099 ;
     RECT  47.808 24.359 48.69 25.099 ;
     RECT  193.356 24.935 195.786 25.141 ;
     RECT  196.56 24.848 236.682 25.141 ;
     RECT  41.472 24.899 42.318 25.169 ;
     RECT  43.056 24.899 43.254 25.169 ;
     RECT  44.388 25.099 48.69 25.169 ;
     RECT  49.608 25.051 49.626 25.169 ;
     RECT  122.76 25.079 122.922 25.169 ;
     RECT  123.696 25.079 125.478 25.169 ;
     RECT  130.896 25.043 132.297 25.169 ;
     RECT  134.532 25.079 135.018 25.169 ;
     RECT  140.076 25.079 141.39 25.169 ;
     RECT  145.44 25.079 147.15 25.169 ;
     RECT  148.215 24.899 149.274 25.169 ;
     RECT  152.136 25.043 155.322 25.169 ;
     RECT  174.42 24.935 176.454 25.169 ;
     RECT  177.228 25.085 182.61 25.169 ;
     RECT  183.564 24.935 187.218 25.169 ;
     RECT  187.992 24.899 192.582 25.169 ;
     RECT  193.356 25.141 236.682 25.169 ;
     RECT  37.944 25.079 40.698 25.205 ;
     RECT  122.76 25.169 122.778 25.205 ;
     RECT  123.696 25.169 125.262 25.205 ;
     RECT  128.88 25.079 129.006 25.205 ;
     RECT  142.2 25.079 144.09 25.205 ;
     RECT  145.44 25.169 147.078 25.205 ;
     RECT  148.215 25.169 149.13 25.205 ;
     RECT  152.46 25.169 152.766 25.205 ;
     RECT  174.42 25.169 176.31 25.205 ;
     RECT  177.624 25.169 177.678 25.205 ;
     RECT  183.564 25.169 183.654 25.205 ;
     RECT  184.428 25.169 187.038 25.205 ;
     RECT  193.356 25.169 193.374 25.205 ;
     RECT  194.148 25.169 236.682 25.205 ;
     RECT  141.12 25.169 141.39 25.241 ;
     RECT  58.896 24.943 58.914 25.243 ;
     RECT  11.664 24.503 32.238 25.249 ;
     RECT  33.048 25.079 37.17 25.249 ;
     RECT  2.415 24.745 10.854 25.285 ;
     RECT  11.664 25.249 37.17 25.285 ;
     RECT  153.615 25.169 155.322 25.285 ;
     RECT  156.132 24.781 160.146 25.285 ;
     RECT  119.952 25.079 122.022 25.313 ;
     RECT  134.532 25.169 134.946 25.313 ;
     RECT  152.532 25.205 152.766 25.313 ;
     RECT  161.604 25.079 173.538 25.313 ;
     RECT  183.564 25.205 183.582 25.313 ;
     RECT  67.215 10.877 67.497 25.321 ;
     RECT  96.156 25.243 96.174 25.321 ;
     RECT  115.815 24.395 116.097 25.321 ;
     RECT  153.615 25.285 160.146 25.321 ;
     RECT  44.496 25.169 48.15 25.349 ;
     RECT  49.68 25.291 49.698 25.349 ;
     RECT  96.156 25.321 96.246 25.349 ;
     RECT  123.696 25.205 124.938 25.349 ;
     RECT  128.88 25.205 128.898 25.349 ;
     RECT  141.372 25.241 141.39 25.349 ;
     RECT  161.604 25.313 166.662 25.349 ;
     RECT  178.416 25.169 182.61 25.349 ;
     RECT  188.1 25.169 192.582 25.349 ;
     RECT  194.148 25.205 201.294 25.349 ;
     RECT  153.615 25.321 160.398 25.373 ;
     RECT  2.415 25.285 37.17 25.439 ;
     RECT  38.124 25.205 40.698 25.439 ;
     RECT  44.676 25.349 48.15 25.439 ;
     RECT  96.228 25.349 96.246 25.439 ;
     RECT  119.952 25.313 121.497 25.439 ;
     RECT  134.532 25.313 134.55 25.439 ;
     RECT  150.552 25.079 150.606 25.439 ;
     RECT  153.615 25.373 160.218 25.439 ;
     RECT  161.604 25.349 163.35 25.439 ;
     RECT  164.088 25.349 165.042 25.439 ;
     RECT  167.436 25.313 173.538 25.439 ;
     RECT  174.42 25.205 176.058 25.439 ;
     RECT  194.22 25.349 201.294 25.439 ;
     RECT  195.048 25.439 201.15 25.469 ;
     RECT  2.415 25.439 36.522 25.475 ;
     RECT  153.615 25.439 160.146 25.475 ;
     RECT  164.088 25.439 164.754 25.475 ;
     RECT  174.42 25.439 175.914 25.475 ;
     RECT  184.428 25.205 186.462 25.475 ;
     RECT  188.1 25.349 191.898 25.475 ;
     RECT  194.22 25.439 194.31 25.475 ;
     RECT  195.048 25.469 195.354 25.475 ;
     RECT  123.696 25.349 124.29 25.511 ;
     RECT  153.615 25.475 160.038 25.511 ;
     RECT  169.2 25.439 173.538 25.511 ;
     RECT  195.048 25.475 195.066 25.511 ;
     RECT  196.092 25.469 201.15 25.511 ;
     RECT  202.176 25.205 236.682 25.511 ;
     RECT  3.42 25.475 36.522 25.547 ;
     RECT  131.616 25.169 132.297 25.547 ;
     RECT  153.615 25.511 159.534 25.547 ;
     RECT  179.676 25.349 182.61 25.547 ;
     RECT  184.428 25.475 185.094 25.547 ;
     RECT  185.832 25.475 186.462 25.547 ;
     RECT  194.22 25.475 194.238 25.547 ;
     RECT  197.856 25.511 201.042 25.547 ;
     RECT  203.652 25.511 236.682 25.555 ;
     RECT  33.624 25.547 36.522 25.583 ;
     RECT  44.676 25.439 45.897 25.583 ;
     RECT  118.584 25.321 118.602 25.583 ;
     RECT  121.068 25.439 121.497 25.583 ;
     RECT  145.8 25.205 146.574 25.583 ;
     RECT  161.604 25.439 163.314 25.583 ;
     RECT  167.436 25.439 168.138 25.583 ;
     RECT  169.272 25.511 173.538 25.583 ;
     RECT  188.568 25.475 191.898 25.583 ;
     RECT  202.215 25.511 202.59 25.583 ;
     RECT  203.652 25.555 236.718 25.583 ;
     RECT  3.42 25.547 32.814 25.619 ;
     RECT  33.624 25.583 33.822 25.619 ;
     RECT  96.264 25.531 96.282 25.619 ;
     RECT  148.215 25.205 148.554 25.619 ;
     RECT  154.944 25.547 159.534 25.619 ;
     RECT  167.436 25.583 168.066 25.619 ;
     RECT  169.272 25.583 171.234 25.619 ;
     RECT  174.42 25.475 175.497 25.619 ;
     RECT  178.416 25.349 178.938 25.619 ;
     RECT  182.124 25.547 182.61 25.619 ;
     RECT  188.568 25.583 190.458 25.619 ;
     RECT  198 25.547 201.042 25.619 ;
     RECT  203.652 25.583 204.57 25.619 ;
     RECT  237.456 23.287 237.474 25.636 ;
     RECT  80.388 25.591 80.478 25.661 ;
     RECT  102.312 25.321 102.402 25.661 ;
     RECT  154.944 25.619 158.022 25.661 ;
     RECT  34.596 25.583 36.522 25.667 ;
     RECT  45.615 25.583 45.897 25.667 ;
     RECT  51.015 23.819 51.297 25.667 ;
     RECT  56.415 17.888 56.697 25.667 ;
     RECT  72.615 6.275 72.897 25.667 ;
     RECT  78.015 13.037 78.297 25.667 ;
     RECT  83.415 7.085 83.697 25.667 ;
     RECT  88.815 19.133 89.097 25.667 ;
     RECT  94.215 11.777 94.497 25.667 ;
     RECT  99.324 24.871 99.897 25.667 ;
     RECT  110.415 24.359 110.697 25.667 ;
     RECT  115.488 25.321 116.097 25.667 ;
     RECT  121.104 25.583 121.497 25.667 ;
     RECT  126.615 25.007 126.897 25.667 ;
     RECT  131.904 25.547 132.297 25.667 ;
     RECT  136.548 25.079 138.546 25.667 ;
     RECT  142.815 25.205 143.097 25.667 ;
     RECT  148.215 25.619 148.497 25.667 ;
     RECT  175.215 25.619 175.497 25.667 ;
     RECT  180.072 25.547 180.897 25.667 ;
     RECT  185.832 25.547 186.297 25.667 ;
     RECT  196.092 25.511 197.097 25.667 ;
     RECT  202.215 25.583 202.497 25.667 ;
     RECT  35.784 25.667 36.522 25.709 ;
     RECT  39.744 25.439 40.698 25.709 ;
     RECT  42.12 25.169 42.138 25.709 ;
     RECT  43.236 25.169 43.254 25.709 ;
     RECT  44.676 25.583 44.802 25.709 ;
     RECT  46.872 25.439 47.862 25.709 ;
     RECT  102.384 25.661 102.402 25.709 ;
     RECT  156.852 25.661 158.022 25.709 ;
     RECT  164.415 25.475 164.754 25.709 ;
     RECT  188.568 25.619 189.522 25.709 ;
     RECT  191.376 25.583 191.898 25.709 ;
     RECT  196.092 25.667 196.905 25.709 ;
     RECT  34.596 25.667 34.905 25.745 ;
     RECT  35.784 25.709 35.802 25.745 ;
     RECT  38.772 25.439 38.97 25.745 ;
     RECT  44.676 25.709 44.694 25.745 ;
     RECT  156.852 25.709 156.87 25.745 ;
     RECT  198 25.619 201.006 25.745 ;
     RECT  79.452 25.717 79.47 25.757 ;
     RECT  80.46 25.661 80.478 25.771 ;
     RECT  124.272 25.511 124.29 25.781 ;
     RECT  145.8 25.583 146.502 25.781 ;
     RECT  180.072 25.667 180.705 25.781 ;
     RECT  185.832 25.667 186.105 25.781 ;
     RECT  196.164 25.709 196.905 25.781 ;
     RECT  58.896 25.243 58.986 25.789 ;
     RECT  138.348 25.667 138.546 25.817 ;
     RECT  140.076 25.169 140.346 25.817 ;
     RECT  146.484 25.781 146.502 25.817 ;
     RECT  178.56 25.619 178.938 25.817 ;
     RECT  58.896 25.789 59.31 25.819 ;
     RECT  61.815 2.413 62.097 25.819 ;
     RECT  140.076 25.817 140.274 25.825 ;
     RECT  150.552 25.439 150.57 25.825 ;
     RECT  108.036 25.816 108.054 25.853 ;
     RECT  190.44 25.619 190.458 25.853 ;
     RECT  191.415 25.709 191.898 25.853 ;
     RECT  99.324 25.667 99.81 25.861 ;
     RECT  34.776 25.745 34.905 25.889 ;
     RECT  46.98 25.709 47.862 25.889 ;
     RECT  58.716 25.819 59.31 25.889 ;
     RECT  80.46 25.771 80.586 25.889 ;
     RECT  102.528 25.819 102.546 25.889 ;
     RECT  34.815 25.889 34.905 25.937 ;
     RECT  40.215 25.709 40.698 25.937 ;
     RECT  45.615 25.667 45.774 25.937 ;
     RECT  51.015 25.667 51.105 25.937 ;
     RECT  56.415 25.667 56.505 25.937 ;
     RECT  61.815 25.819 62.118 25.937 ;
     RECT  72.615 25.667 72.705 25.937 ;
     RECT  83.415 25.667 83.505 25.937 ;
     RECT  94.215 25.667 94.305 25.937 ;
     RECT  105.015 25.015 105.822 25.937 ;
     RECT  115.488 25.667 115.905 25.937 ;
     RECT  126.615 25.667 126.705 25.937 ;
     RECT  136.548 25.667 137.505 25.937 ;
     RECT  142.815 25.667 142.905 25.937 ;
     RECT  148.215 25.667 148.374 25.937 ;
     RECT  153.615 25.547 154.134 25.937 ;
     RECT  159.015 25.619 159.534 25.937 ;
     RECT  164.415 25.709 164.505 25.937 ;
     RECT  169.272 25.619 170.406 25.937 ;
     RECT  175.215 25.667 175.305 25.937 ;
     RECT  180.615 25.781 180.705 25.937 ;
     RECT  186.015 25.781 186.105 25.937 ;
     RECT  191.415 25.853 191.505 25.937 ;
     RECT  196.815 25.781 196.905 25.937 ;
     RECT  202.215 25.667 202.446 25.937 ;
     RECT  67.215 25.321 68.166 25.951 ;
     RECT  78.015 25.667 78.21 25.951 ;
     RECT  88.815 25.667 89.01 25.951 ;
     RECT  110.415 25.667 110.61 25.951 ;
     RECT  65.628 25.321 65.754 25.979 ;
     RECT  144.072 25.205 144.09 25.979 ;
     RECT  165.816 25.349 166.662 25.979 ;
     RECT  61.992 25.937 62.118 25.997 ;
     RECT  67.104 25.951 68.166 25.997 ;
     RECT  77.904 25.951 78.21 25.997 ;
     RECT  88.704 25.951 89.01 25.997 ;
     RECT  99.18 25.861 99.81 25.997 ;
     RECT  110.304 25.951 110.61 25.997 ;
     RECT  121.104 25.667 121.41 25.997 ;
     RECT  131.904 25.667 132.21 25.997 ;
     RECT  159.516 25.937 159.534 25.997 ;
     RECT  40.68 25.937 40.698 26.015 ;
     RECT  170.244 25.937 170.406 26.015 ;
     RECT  99.18 25.997 99.198 26.045 ;
     RECT  150.264 25.825 150.57 26.051 ;
     RECT  167.436 25.619 168.03 26.051 ;
     RECT  172.044 25.583 173.538 26.051 ;
     RECT  178.56 25.817 178.614 26.087 ;
     RECT  58.716 25.889 58.734 26.093 ;
     RECT  62.1 25.997 62.118 26.093 ;
     RECT  161.604 25.583 162.63 26.093 ;
     RECT  161.604 26.093 162.522 26.123 ;
     RECT  170.388 26.015 170.406 26.159 ;
     RECT  198.36 25.745 201.006 26.159 ;
     RECT  161.928 26.123 162.522 26.189 ;
     RECT  166.824 26.059 166.842 26.189 ;
     RECT  177.66 25.205 177.678 26.204 ;
     RECT  198.9 26.159 201.006 26.204 ;
     RECT  202.428 25.937 202.446 26.204 ;
     RECT  199.152 26.204 201.006 26.237 ;
     RECT  205.668 25.583 236.718 26.237 ;
     RECT  172.512 26.051 173.538 26.249 ;
     RECT  199.152 26.237 199.566 26.249 ;
     RECT  203.976 25.619 204.57 26.249 ;
     RECT  2.415 25.475 2.697 26.251 ;
     RECT  3.42 25.619 32.238 26.251 ;
     RECT  65.628 25.979 65.646 26.285 ;
     RECT  154.944 25.661 155.646 26.285 ;
     RECT  203.976 26.249 203.994 26.321 ;
     RECT  153.972 25.937 154.134 26.357 ;
     RECT  237.456 25.636 237.51 26.381 ;
     RECT  115.488 25.937 115.506 26.393 ;
     RECT  138.348 25.817 138.366 26.477 ;
     RECT  2.415 26.251 32.238 26.519 ;
     RECT  80.46 25.889 80.478 26.519 ;
     RECT  154.116 26.357 154.134 26.525 ;
     RECT  157.86 25.709 158.022 26.527 ;
     RECT  67.824 25.997 68.166 26.555 ;
     RECT  152.748 25.313 152.766 26.555 ;
     RECT  161.928 26.189 161.946 26.555 ;
     RECT  157.32 26.527 158.022 26.573 ;
     RECT  46.98 25.889 47.718 26.591 ;
     RECT  47.016 26.591 47.718 26.627 ;
     RECT  169.272 25.937 169.29 26.627 ;
     RECT  172.512 26.249 172.53 26.663 ;
     RECT  173.52 26.249 173.538 26.699 ;
     RECT  200.448 26.237 201.006 26.744 ;
     RECT  188.784 25.709 188.802 26.761 ;
     RECT  205.704 26.237 236.718 26.765 ;
     RECT  188.676 26.761 188.802 26.789 ;
     RECT  105.444 25.937 105.822 26.861 ;
     RECT  154.944 26.285 155.466 26.969 ;
     RECT  113.4 25.321 113.418 27.053 ;
     RECT  140.004 25.825 140.274 27.095 ;
     RECT  105.444 26.861 105.462 27.131 ;
     RECT  154.944 26.969 154.962 27.131 ;
     RECT  150.264 26.051 150.534 27.149 ;
     RECT  38.952 25.745 38.97 27.167 ;
     RECT  119.952 25.439 119.97 27.167 ;
     RECT  136.548 25.937 137.106 27.197 ;
     RECT  140.004 27.095 140.022 27.203 ;
     RECT  150.264 27.149 150.282 27.239 ;
     RECT  199.152 26.249 199.17 27.284 ;
     RECT  200.736 26.744 201.006 27.329 ;
     RECT  237.492 26.381 237.51 27.337 ;
     RECT  205.704 26.765 236.61 27.341 ;
     RECT  237.456 27.337 237.51 27.437 ;
     RECT  3.852 26.519 32.238 27.877 ;
     RECT  3.492 27.877 32.238 27.917 ;
     RECT  3.852 27.917 32.238 28.08 ;
     RECT  33.624 25.619 33.642 28.08 ;
     RECT  45.756 25.937 45.774 28.08 ;
     RECT  47.7 26.627 47.718 28.08 ;
     RECT  53.856 25.321 53.874 28.08 ;
     RECT  68.148 26.555 68.166 28.08 ;
     RECT  85.212 25.591 85.23 28.08 ;
     RECT  137.088 27.197 137.106 28.08 ;
     RECT  148.356 25.937 148.374 28.08 ;
     RECT  157.32 26.573 157.338 28.08 ;
     RECT  168.012 26.051 168.03 28.08 ;
     RECT  178.56 26.087 178.578 28.08 ;
     RECT  188.676 26.789 188.694 28.08 ;
     RECT  200.988 27.329 201.006 28.08 ;
     RECT  205.704 27.341 236.574 28.08 ;
     RECT  3.852 28.08 236.574 28.109 ;
     RECT  3.852 28.109 236.538 28.409 ;
     RECT  5.328 28.409 236.538 28.481 ;
     RECT  3.852 28.409 4.554 29.083 ;
     RECT  236.304 28.481 236.538 29.165 ;
     RECT  3.492 29.083 4.554 29.179 ;
     RECT  3.492 29.179 4.59 29.219 ;
     RECT  5.328 28.481 235.422 29.227 ;
     RECT  236.304 29.165 236.322 29.227 ;
     RECT  3.492 29.219 3.51 29.255 ;
     RECT  4.536 29.219 4.59 29.263 ;
     RECT  5.328 29.227 236.322 29.263 ;
     RECT  237.492 27.437 237.51 29.357 ;
     RECT  4.536 29.263 236.322 29.399 ;
     RECT  4.536 29.399 11.214 29.561 ;
     RECT  12.24 29.399 236.322 29.899 ;
     RECT  12.24 29.899 236.43 30.073 ;
     RECT  4.572 29.561 11.214 30.415 ;
     RECT  12.24 30.073 236.574 30.415 ;
     RECT  4.572 30.415 236.574 30.461 ;
     RECT  12.492 30.461 236.574 30.941 ;
     RECT  237.42 30.763 237.438 30.941 ;
     RECT  4.572 30.461 11.538 31.109 ;
     RECT  5.148 31.109 11.538 31.351 ;
     RECT  12.492 30.941 236.538 31.351 ;
     RECT  237.492 30.991 237.51 31.373 ;
     RECT  5.148 31.351 236.538 31.379 ;
     RECT  5.688 31.379 236.538 31.685 ;
     RECT  5.724 31.685 236.538 31.853 ;
     RECT  5.724 31.853 235.314 31.919 ;
     RECT  237.384 31.723 237.402 32.011 ;
     RECT  236.412 31.853 236.538 32.035 ;
     RECT  236.412 32.035 236.574 32.233 ;
     RECT  237.312 32.011 237.402 32.233 ;
     RECT  236.412 32.233 237.402 32.237 ;
     RECT  5.724 31.919 235.17 32.459 ;
     RECT  237.348 32.237 237.402 32.683 ;
     RECT  6.516 32.459 235.17 32.765 ;
     RECT  237.348 32.683 237.51 32.765 ;
     RECT  236.412 32.237 236.61 32.813 ;
     RECT  6.588 32.765 235.17 32.881 ;
     RECT  237.384 32.765 237.51 32.999 ;
     RECT  6.588 32.881 235.278 33.163 ;
     RECT  236.412 32.813 236.466 33.163 ;
     RECT  6.588 33.163 236.466 33.547 ;
     RECT  6.588 33.547 236.646 33.917 ;
     RECT  237.42 32.999 237.51 34.315 ;
     RECT  6.732 33.917 236.646 34.655 ;
     RECT  11.88 34.655 236.646 34.699 ;
     RECT  237.384 34.315 237.51 34.699 ;
     RECT  6.732 34.655 11.106 34.727 ;
     RECT  11.88 34.699 237.51 34.733 ;
     RECT  27.036 34.733 237.51 34.763 ;
     RECT  6.732 34.727 10.89 34.799 ;
     RECT  27.036 34.763 236.61 34.844 ;
     RECT  6.984 34.799 10.89 35.159 ;
     RECT  11.88 34.733 26.082 35.159 ;
     RECT  27.036 34.844 236.574 35.195 ;
     RECT  237.348 34.763 237.51 35.195 ;
     RECT  27.036 35.195 209.718 35.231 ;
     RECT  11.88 35.159 25.074 35.429 ;
     RECT  210.456 35.195 236.574 35.573 ;
     RECT  25.848 35.159 26.082 35.581 ;
     RECT  27.036 35.231 209.646 35.581 ;
     RECT  6.984 35.159 9.918 35.609 ;
     RECT  15.156 35.429 25.074 35.645 ;
     RECT  10.836 35.159 10.854 35.699 ;
     RECT  25.848 35.581 209.646 35.699 ;
     RECT  6.984 35.609 9.126 35.735 ;
     RECT  7.164 35.735 9.126 35.789 ;
     RECT  19.728 35.645 25.074 35.807 ;
     RECT  15.156 35.645 18.897 35.879 ;
     RECT  15.156 35.879 16.362 35.885 ;
     RECT  20.7 35.807 25.074 35.899 ;
     RECT  25.848 35.699 26.082 35.899 ;
     RECT  8.964 35.789 9.126 35.969 ;
     RECT  9.864 35.609 9.918 35.969 ;
     RECT  20.7 35.899 26.082 35.969 ;
     RECT  22.176 35.969 26.082 36.005 ;
     RECT  13.104 35.429 14.274 36.029 ;
     RECT  20.7 35.969 21.294 36.077 ;
     RECT  210.456 35.573 236.538 36.077 ;
     RECT  15.156 35.885 16.11 36.239 ;
     RECT  7.164 35.789 8.097 36.365 ;
     RECT  15.156 36.239 16.074 36.472 ;
     RECT  12.024 35.429 12.258 36.475 ;
     RECT  13.104 36.029 13.662 36.475 ;
     RECT  11.232 36.472 11.25 36.509 ;
     RECT  15.12 36.472 16.074 36.509 ;
     RECT  12.024 36.475 13.662 36.523 ;
     RECT  11.376 36.523 13.662 36.545 ;
     RECT  9.108 35.969 9.126 36.605 ;
     RECT  17.316 35.879 18.897 36.653 ;
     RECT  11.376 36.545 12.258 36.779 ;
     RECT  20.7 36.077 21.15 36.851 ;
     RECT  9.864 35.969 9.882 36.923 ;
     RECT  210.456 36.077 220.662 37.021 ;
     RECT  221.4 36.077 236.538 37.021 ;
     RECT  11.772 36.779 12.258 37.049 ;
     RECT  15.264 36.509 15.822 37.049 ;
     RECT  17.532 36.653 18.897 37.051 ;
     RECT  27.036 35.699 209.646 37.093 ;
     RECT  210.456 37.021 236.538 37.093 ;
     RECT  22.212 36.005 26.082 37.133 ;
     RECT  15.264 37.049 15.606 37.181 ;
     RECT  27.036 37.093 236.538 37.193 ;
     RECT  235.872 37.193 236.538 37.355 ;
     RECT  11.916 37.049 12.042 37.421 ;
     RECT  237.348 35.195 237.474 37.427 ;
     RECT  17.532 37.051 18.918 37.471 ;
     RECT  19.728 35.807 19.782 37.471 ;
     RECT  23.436 37.133 26.082 37.565 ;
     RECT  27.036 37.193 235.026 37.589 ;
     RECT  17.532 37.471 19.782 37.613 ;
     RECT  237.456 37.427 237.474 37.625 ;
     RECT  13.215 36.545 13.662 37.757 ;
     RECT  15.3 37.181 15.606 37.895 ;
     RECT  11.916 37.421 11.934 37.901 ;
     RECT  17.82 37.613 19.782 37.949 ;
     RECT  22.212 37.133 22.59 37.975 ;
     RECT  23.436 37.565 25.074 37.975 ;
     RECT  15.48 37.895 15.606 37.997 ;
     RECT  27.036 37.589 234.897 38.003 ;
     RECT  236.52 37.355 236.538 38.039 ;
     RECT  15.48 37.997 15.534 38.285 ;
     RECT  17.82 37.949 18.897 38.395 ;
     RECT  17.64 38.395 18.897 38.399 ;
     RECT  22.212 37.975 25.074 38.399 ;
     RECT  27.036 38.003 212.238 38.399 ;
     RECT  17.64 38.399 17.838 38.435 ;
     RECT  22.212 38.399 24.894 38.477 ;
     RECT  15.516 38.285 15.534 38.525 ;
     RECT  213.015 38.003 234.897 38.705 ;
     RECT  18.615 38.399 18.897 38.749 ;
     RECT  19.764 37.949 19.782 38.749 ;
     RECT  20.7 36.851 20.826 38.749 ;
     RECT  27.036 38.399 209.646 39.047 ;
     RECT  22.572 38.477 24.894 39.053 ;
     RECT  24.015 39.053 24.894 39.245 ;
     RECT  17.784 38.435 17.838 39.355 ;
     RECT  18.615 38.749 19.026 39.355 ;
     RECT  19.764 38.749 20.826 39.355 ;
     RECT  27.036 39.047 209.538 39.479 ;
     RECT  17.784 39.355 19.026 39.533 ;
     RECT  19.764 39.355 21.114 39.533 ;
     RECT  26.064 37.565 26.082 39.631 ;
     RECT  25.056 39.355 25.11 39.721 ;
     RECT  19.764 39.533 20.718 39.749 ;
     RECT  18.072 39.533 19.026 39.785 ;
     RECT  22.572 39.053 23.274 39.785 ;
     RECT  18.216 39.785 19.026 39.883 ;
     RECT  19.764 39.749 20.07 39.883 ;
     RECT  22.572 39.785 22.806 39.883 ;
     RECT  25.056 39.721 25.146 39.883 ;
     RECT  21.852 39.883 22.806 39.893 ;
     RECT  25.056 39.883 25.218 39.893 ;
     RECT  213.015 38.705 233.514 39.929 ;
     RECT  18.216 39.883 20.07 40.019 ;
     RECT  22.788 39.893 22.806 40.019 ;
     RECT  213.015 39.929 233.406 40.019 ;
     RECT  21.852 39.893 22.014 40.055 ;
     RECT  18.216 40.019 19.926 40.109 ;
     RECT  18.615 40.109 19.926 40.157 ;
     RECT  25.092 39.893 25.218 40.205 ;
     RECT  26.064 39.631 26.154 40.267 ;
     RECT  26.064 40.267 26.622 40.289 ;
     RECT  25.2 40.205 25.218 40.325 ;
     RECT  26.496 40.289 26.622 40.441 ;
     RECT  27.36 39.479 209.538 40.441 ;
     RECT  213.015 40.019 231.066 40.445 ;
     RECT  213.015 40.445 230.994 40.469 ;
     RECT  21.996 40.055 22.014 40.589 ;
     RECT  18.615 40.157 19.278 40.733 ;
     RECT  231.804 40.019 233.406 41.035 ;
     RECT  26.496 40.441 209.538 41.071 ;
     RECT  213.015 40.469 222.318 41.099 ;
     RECT  231.804 41.035 233.622 41.099 ;
     RECT  25.344 40.441 25.362 41.131 ;
     RECT  26.388 41.071 209.538 41.131 ;
     RECT  215.352 41.099 222.318 41.377 ;
     RECT  223.056 40.469 230.994 41.377 ;
     RECT  231.804 41.099 233.19 41.405 ;
     RECT  25.344 41.131 209.538 41.485 ;
     RECT  24.015 39.245 24.297 41.611 ;
     RECT  25.2 41.485 209.538 41.611 ;
     RECT  215.352 41.377 230.994 41.819 ;
     RECT  231.876 41.405 233.19 41.837 ;
     RECT  234.615 38.705 234.897 42.139 ;
     RECT  231.876 41.837 232.542 42.179 ;
     RECT  234.036 42.139 234.897 42.179 ;
     RECT  220.5 41.819 230.994 42.421 ;
     RECT  231.876 42.179 232.47 42.421 ;
     RECT  210.456 38.399 212.238 42.557 ;
     RECT  24.015 41.611 209.538 42.601 ;
     RECT  215.352 41.819 219.762 42.601 ;
     RECT  220.5 42.421 232.47 42.601 ;
     RECT  23.58 42.601 209.538 42.763 ;
     RECT  233.604 42.331 233.622 42.791 ;
     RECT  23.4 42.763 209.538 42.8 ;
     RECT  23.904 42.8 209.538 43.025 ;
     RECT  27.828 43.025 209.538 43.061 ;
     RECT  27.936 43.061 209.538 43.169 ;
     RECT  234.615 42.179 234.897 43.231 ;
     RECT  28.404 43.169 209.538 43.259 ;
     RECT  28.548 43.259 209.538 43.295 ;
     RECT  23.904 43.025 27.09 43.403 ;
     RECT  29.016 43.295 209.538 43.403 ;
     RECT  233.316 43.303 233.334 43.537 ;
     RECT  234.615 43.231 234.954 43.537 ;
     RECT  24.015 43.403 27.09 43.565 ;
     RECT  233.316 43.537 233.442 43.681 ;
     RECT  24.015 43.565 27.054 43.709 ;
     RECT  234.615 43.537 235.242 43.771 ;
     RECT  24.015 43.709 25.614 43.799 ;
     RECT  234.504 43.771 235.242 43.807 ;
     RECT  24.015 43.799 25.434 43.835 ;
     RECT  26.892 43.709 27.054 43.835 ;
     RECT  233.316 43.681 233.766 43.843 ;
     RECT  234.504 43.807 235.386 43.843 ;
     RECT  215.352 42.601 232.47 43.951 ;
     RECT  215.352 43.951 232.578 44.077 ;
     RECT  233.316 43.843 235.386 44.077 ;
     RECT  26.928 43.835 27.054 44.105 ;
     RECT  29.016 43.403 29.034 44.311 ;
     RECT  30.06 43.403 209.538 44.311 ;
     RECT  27.54 44.311 27.558 44.347 ;
     RECT  27.54 44.347 27.954 44.491 ;
     RECT  29.016 44.311 209.538 44.491 ;
     RECT  27.54 44.491 209.538 44.525 ;
     RECT  30.168 44.525 209.538 44.621 ;
     RECT  236.484 44.725 236.502 44.923 ;
     RECT  25.38 43.835 25.398 44.995 ;
     RECT  25.236 44.995 25.398 45.005 ;
     RECT  26.784 44.827 26.802 45.005 ;
     RECT  27.54 44.525 29.142 45.101 ;
     RECT  27.828 45.101 29.142 45.355 ;
     RECT  30.456 44.621 209.538 45.391 ;
     RECT  215.352 44.077 235.386 45.391 ;
     RECT  24.015 43.835 24.297 45.571 ;
     RECT  25.236 45.005 25.254 45.571 ;
     RECT  236.484 44.923 236.574 45.581 ;
     RECT  237.492 44.077 237.51 45.677 ;
     RECT  215.352 45.391 235.422 45.689 ;
     RECT  236.52 45.581 236.574 45.773 ;
     RECT  219.852 45.689 235.422 45.833 ;
     RECT  30.168 45.391 209.538 45.841 ;
     RECT  210.456 42.557 211.23 45.841 ;
     RECT  27.828 45.355 29.358 45.883 ;
     RECT  30.168 45.841 211.23 45.883 ;
     RECT  26.82 45.571 26.838 45.967 ;
     RECT  219.924 45.833 235.422 46.061 ;
     RECT  219.924 46.061 235.35 46.103 ;
     RECT  24.015 45.571 25.254 46.111 ;
     RECT  27.828 45.883 211.23 46.123 ;
     RECT  27.72 46.123 211.23 46.349 ;
     RECT  23.724 46.111 25.254 46.381 ;
     RECT  26.784 45.967 26.838 46.381 ;
     RECT  27.72 46.349 28.998 46.381 ;
     RECT  30.168 46.349 211.23 46.499 ;
     RECT  220.068 46.103 235.35 46.535 ;
     RECT  220.212 46.535 235.35 46.643 ;
     RECT  236.556 45.773 236.574 46.777 ;
     RECT  222.984 46.643 235.35 46.805 ;
     RECT  223.056 46.805 235.35 46.849 ;
     RECT  236.556 46.777 236.61 46.849 ;
     RECT  220.212 46.643 222.174 46.877 ;
     RECT  223.056 46.849 236.61 46.877 ;
     RECT  23.724 46.381 25.362 46.921 ;
     RECT  26.136 46.381 26.838 46.921 ;
     RECT  237.492 46.987 237.51 47.011 ;
     RECT  237.42 47.011 237.51 47.039 ;
     RECT  30.456 46.499 211.23 47.083 ;
     RECT  30.456 47.083 211.266 47.147 ;
     RECT  23.724 46.921 26.838 47.179 ;
     RECT  27.648 46.381 28.998 47.179 ;
     RECT  211.212 47.147 211.266 47.219 ;
     RECT  23.724 47.179 28.998 47.731 ;
     RECT  223.236 46.877 236.61 48.119 ;
     RECT  30.456 47.147 210.474 48.163 ;
     RECT  211.212 47.219 211.23 48.163 ;
     RECT  235.908 48.119 236.61 48.173 ;
     RECT  223.236 48.119 235.134 48.235 ;
     RECT  237.42 47.039 237.438 48.331 ;
     RECT  237.42 48.331 237.474 48.361 ;
     RECT  237.384 48.361 237.474 48.389 ;
     RECT  237.384 48.389 237.438 48.413 ;
     RECT  212.22 42.557 212.238 48.469 ;
     RECT  213.015 41.099 214.614 48.469 ;
     RECT  23.724 47.731 29.286 48.505 ;
     RECT  30.456 48.163 211.23 48.505 ;
     RECT  223.128 48.235 235.134 48.907 ;
     RECT  235.908 48.173 236.538 48.907 ;
     RECT  223.128 48.907 236.538 49.073 ;
     RECT  212.22 48.469 214.614 49.109 ;
     RECT  237.42 48.413 237.438 49.291 ;
     RECT  235.944 49.073 236.538 49.747 ;
     RECT  215.352 45.689 219.042 50.117 ;
     RECT  223.128 49.073 234.99 50.161 ;
     RECT  235.944 49.747 236.61 50.189 ;
     RECT  223.128 50.161 235.026 50.299 ;
     RECT  235.944 50.189 236.574 50.299 ;
     RECT  223.128 50.299 236.574 50.387 ;
     RECT  221.652 46.877 222.174 50.431 ;
     RECT  221.652 50.431 222.318 50.549 ;
     RECT  220.212 46.877 220.518 50.935 ;
     RECT  221.652 50.549 222.174 50.935 ;
     RECT  223.128 50.387 236.502 51.115 ;
     RECT  23.724 48.505 211.23 51.197 ;
     RECT  237.42 49.291 237.51 51.197 ;
     RECT  220.212 50.935 222.174 51.233 ;
     RECT  223.128 51.115 236.574 51.539 ;
     RECT  223.128 51.539 236.538 51.665 ;
     RECT  223.128 51.665 236.502 52.079 ;
     RECT  217.08 50.117 219.042 52.169 ;
     RECT  217.62 52.169 219.042 52.205 ;
     RECT  235.656 52.079 236.502 52.205 ;
     RECT  237.492 51.197 237.51 52.511 ;
     RECT  235.656 52.205 236.178 52.547 ;
     RECT  215.352 50.117 216.234 52.745 ;
     RECT  235.656 52.547 235.674 52.745 ;
     RECT  23.724 51.197 211.194 52.817 ;
     RECT  217.62 52.205 217.638 52.853 ;
     RECT  223.128 52.079 234.897 52.861 ;
     RECT  212.22 49.109 212.238 53.429 ;
     RECT  236.664 52.951 236.682 53.491 ;
     RECT  221.652 51.233 222.174 53.527 ;
     RECT  223.128 52.861 235.386 53.527 ;
     RECT  221.652 53.527 235.386 53.563 ;
     RECT  221.652 53.563 235.422 53.833 ;
     RECT  213.015 49.109 214.614 53.861 ;
     RECT  237.492 54.103 237.51 54.605 ;
     RECT  220.212 51.233 220.518 55.013 ;
     RECT  236.556 53.491 236.682 55.469 ;
     RECT  236.556 55.469 236.574 55.561 ;
     RECT  221.652 53.833 235.458 55.565 ;
     RECT  221.652 55.565 235.206 55.661 ;
     RECT  236.52 55.561 236.574 55.759 ;
     RECT  221.652 55.661 235.17 55.949 ;
     RECT  23.724 52.817 209.97 56.129 ;
     RECT  235.98 55.759 236.574 56.395 ;
     RECT  26.1 56.129 209.97 56.399 ;
     RECT  221.652 55.949 235.134 56.683 ;
     RECT  235.944 56.395 236.574 56.683 ;
     RECT  221.652 56.683 236.574 56.759 ;
     RECT  237.492 56.779 237.51 56.971 ;
     RECT  237.456 56.971 237.51 57.163 ;
     RECT  221.94 56.759 236.574 57.209 ;
     RECT  26.1 56.399 209.502 57.299 ;
     RECT  221.94 57.209 236.538 57.299 ;
     RECT  237.42 57.163 237.51 57.641 ;
     RECT  221.94 57.299 236.502 57.713 ;
     RECT  237.42 57.641 237.474 57.749 ;
     RECT  27.648 57.299 209.502 57.816 ;
     RECT  221.94 57.713 235.962 57.839 ;
     RECT  27.648 57.816 31.698 57.875 ;
     RECT  218.415 52.205 219.042 57.875 ;
     RECT  27.828 57.875 31.698 57.911 ;
     RECT  216.216 52.745 216.234 57.947 ;
     RECT  237.456 57.749 237.474 58.109 ;
     RECT  221.94 57.839 235.926 58.451 ;
     RECT  23.724 56.129 25.362 58.523 ;
     RECT  158.364 57.816 158.886 58.576 ;
     RECT  160.416 57.816 160.686 58.576 ;
     RECT  205.2 57.816 209.502 58.649 ;
     RECT  156.744 57.816 157.014 58.657 ;
     RECT  28.188 57.911 31.698 58.702 ;
     RECT  235.872 58.451 235.926 58.919 ;
     RECT  163.368 58.657 163.386 58.963 ;
     RECT  164.124 57.816 164.142 58.963 ;
     RECT  155.988 58.801 156.006 59.035 ;
     RECT  156.744 58.657 157.122 59.035 ;
     RECT  160.236 58.576 160.686 59.035 ;
     RECT  23.724 58.523 24.858 59.063 ;
     RECT  163.368 58.963 164.142 59.116 ;
     RECT  152.64 58.891 152.658 59.161 ;
     RECT  192.24 58.939 192.258 59.161 ;
     RECT  235.908 58.919 235.926 59.189 ;
     RECT  123.732 58.657 123.75 59.233 ;
     RECT  23.724 59.063 24.786 59.261 ;
     RECT  28.224 58.702 31.698 59.341 ;
     RECT  32.904 59.269 32.922 59.341 ;
     RECT  160.236 59.035 161.406 59.341 ;
     RECT  162.216 58.963 162.234 59.341 ;
     RECT  142.992 59.116 143.01 59.515 ;
     RECT  160.236 59.341 162.234 59.539 ;
     RECT  157.968 58.576 158.886 59.575 ;
     RECT  160.164 59.539 162.234 59.575 ;
     RECT  119.052 58.729 119.07 59.611 ;
     RECT  155.988 59.035 157.122 59.611 ;
     RECT  163.188 59.116 164.142 59.737 ;
     RECT  148.356 58.927 148.374 59.773 ;
     RECT  165.636 59.071 165.654 59.809 ;
     RECT  221.94 58.451 235.098 59.809 ;
     RECT  154.8 58.621 154.818 59.845 ;
     RECT  180 57.816 180.018 59.845 ;
     RECT  148.356 59.773 148.554 59.851 ;
     RECT  150.48 59.845 150.498 59.851 ;
     RECT  177.3 59.773 177.318 59.851 ;
     RECT  122.004 59.233 122.022 59.873 ;
     RECT  142.992 59.515 143.046 59.923 ;
     RECT  163.044 59.737 164.142 59.923 ;
     RECT  179.928 59.845 180.018 59.923 ;
     RECT  186.804 57.816 186.822 59.923 ;
     RECT  192.096 59.161 192.258 59.923 ;
     RECT  147.636 59.851 148.554 59.971 ;
     RECT  154.476 59.845 154.818 59.971 ;
     RECT  187.668 59.503 187.686 59.971 ;
     RECT  28.224 59.341 32.922 59.999 ;
     RECT  147.348 59.971 148.554 59.999 ;
     RECT  150.084 59.851 150.498 59.999 ;
     RECT  155.988 59.611 157.194 59.999 ;
     RECT  165.636 59.809 165.798 59.999 ;
     RECT  177.3 59.851 177.462 59.999 ;
     RECT  179.928 59.923 180.705 59.999 ;
     RECT  191.415 59.923 192.258 59.999 ;
     RECT  119.052 59.611 119.178 60.007 ;
     RECT  123.48 59.233 123.75 60.007 ;
     RECT  140.364 59.971 140.382 60.007 ;
     RECT  142.815 59.923 143.046 60.007 ;
     RECT  150.156 59.999 150.498 60.029 ;
     RECT  205.2 58.649 209.466 60.029 ;
     RECT  119.052 60.007 119.25 60.035 ;
     RECT  123.48 60.007 123.822 60.035 ;
     RECT  150.336 60.029 150.498 60.035 ;
     RECT  165.636 59.999 165.654 60.035 ;
     RECT  177.3 59.999 177.318 60.035 ;
     RECT  184.428 59.995 184.446 60.035 ;
     RECT  187.668 59.971 187.83 60.035 ;
     RECT  191.415 59.999 192.114 60.035 ;
     RECT  215.352 52.745 215.37 60.035 ;
     RECT  141.984 59.971 142.002 60.043 ;
     RECT  146.52 59.845 146.538 60.043 ;
     RECT  157.968 59.575 162.234 60.043 ;
     RECT  123.552 60.035 123.822 60.071 ;
     RECT  154.476 59.971 155.106 60.071 ;
     RECT  147.348 59.999 147.366 60.077 ;
     RECT  187.812 60.035 187.83 60.077 ;
     RECT  140.112 60.007 140.382 60.079 ;
     RECT  186.015 59.923 186.822 60.091 ;
     RECT  32.472 59.999 32.922 60.107 ;
     RECT  114.624 60.007 114.642 60.107 ;
     RECT  119.232 60.035 119.25 60.107 ;
     RECT  123.804 60.071 123.822 60.115 ;
     RECT  138.672 60.043 138.69 60.115 ;
     RECT  142.815 60.007 143.226 60.115 ;
     RECT  157.968 60.043 162.27 60.115 ;
     RECT  163.044 59.923 164.505 60.115 ;
     RECT  168.444 59.575 168.462 60.115 ;
     RECT  140.04 60.079 140.382 60.125 ;
     RECT  122.544 60.007 122.634 60.143 ;
     RECT  123.804 60.115 123.894 60.143 ;
     RECT  140.112 60.125 140.382 60.143 ;
     RECT  32.796 60.107 32.922 60.151 ;
     RECT  138.6 60.115 138.69 60.151 ;
     RECT  142.815 60.115 143.298 60.151 ;
     RECT  168.156 60.115 168.462 60.151 ;
     RECT  237.456 60.007 237.474 60.151 ;
     RECT  140.364 60.143 140.382 60.173 ;
     RECT  150.336 60.035 150.354 60.173 ;
     RECT  138.528 60.151 138.69 60.179 ;
     RECT  184.572 60.139 184.59 60.179 ;
     RECT  186.015 60.091 186.966 60.179 ;
     RECT  34.815 59.923 34.905 60.193 ;
     RECT  40.215 59.923 40.305 60.193 ;
     RECT  45.615 59.923 45.705 60.193 ;
     RECT  51.015 59.923 51.105 60.193 ;
     RECT  56.415 59.923 56.505 60.193 ;
     RECT  61.815 59.923 61.905 60.193 ;
     RECT  67.215 59.923 67.305 60.193 ;
     RECT  72.615 59.923 72.705 60.193 ;
     RECT  78.015 59.923 78.105 60.193 ;
     RECT  83.415 59.923 83.505 60.193 ;
     RECT  88.815 59.923 88.905 60.193 ;
     RECT  94.215 59.923 94.305 60.193 ;
     RECT  99.615 59.923 99.705 60.193 ;
     RECT  105.015 59.923 105.105 60.193 ;
     RECT  110.415 59.923 110.505 60.193 ;
     RECT  115.815 59.923 115.905 60.193 ;
     RECT  126.615 59.923 126.705 60.193 ;
     RECT  132.015 59.923 132.105 60.193 ;
     RECT  137.415 59.923 137.505 60.193 ;
     RECT  153.615 59.923 153.705 60.193 ;
     RECT  154.476 60.071 154.71 60.193 ;
     RECT  157.968 60.115 164.505 60.193 ;
     RECT  169.815 59.923 169.905 60.193 ;
     RECT  175.215 59.923 175.305 60.193 ;
     RECT  180.615 59.999 180.705 60.193 ;
     RECT  196.815 59.923 196.905 60.193 ;
     RECT  202.215 59.923 202.305 60.193 ;
     RECT  32.796 60.151 33.066 60.269 ;
     RECT  122.544 60.143 122.562 60.269 ;
     RECT  123.876 60.143 123.894 60.269 ;
     RECT  138.528 60.179 138.618 60.269 ;
     RECT  153.615 60.193 154.71 60.269 ;
     RECT  156.132 59.999 157.014 60.269 ;
     RECT  157.968 60.193 164.697 60.269 ;
     RECT  205.524 60.029 209.466 60.269 ;
     RECT  148.215 59.999 148.554 60.277 ;
     RECT  141.66 60.043 142.002 60.283 ;
     RECT  32.976 60.269 33.066 60.305 ;
     RECT  193.68 59.809 193.698 60.305 ;
     RECT  146.484 60.043 146.538 60.317 ;
     RECT  141.444 60.283 142.002 60.331 ;
     RECT  28.224 59.999 31.698 60.341 ;
     RECT  168.156 60.151 168.606 60.365 ;
     RECT  33.048 60.305 33.066 60.377 ;
     RECT  138.528 60.269 138.546 60.377 ;
     RECT  142.815 60.151 143.334 60.377 ;
     RECT  146.52 60.317 146.538 60.377 ;
     RECT  148.215 60.277 148.626 60.377 ;
     RECT  141.12 60.331 142.002 60.413 ;
     RECT  153.615 60.269 154.638 60.413 ;
     RECT  141.12 60.413 141.462 60.449 ;
     RECT  220.5 55.013 220.518 60.449 ;
     RECT  168.156 60.365 168.174 60.611 ;
     RECT  205.524 60.269 208.89 60.647 ;
     RECT  193.824 60.421 193.842 60.719 ;
     RECT  28.224 60.341 31.554 60.809 ;
     RECT  157.968 60.269 162.234 60.809 ;
     RECT  163.368 60.269 164.697 60.809 ;
     RECT  156.24 60.269 157.014 60.989 ;
     RECT  211.176 52.817 211.194 60.989 ;
     RECT  156.672 60.989 157.014 61.051 ;
     RECT  161.82 60.809 162.234 61.087 ;
     RECT  156.672 61.051 157.086 61.151 ;
     RECT  205.632 60.647 208.89 61.151 ;
     RECT  157.968 60.809 160.686 61.159 ;
     RECT  161.82 61.087 162.378 61.159 ;
     RECT  153.615 60.413 154.53 61.321 ;
     RECT  157.824 61.159 160.686 61.349 ;
     RECT  157.824 61.349 160.038 61.385 ;
     RECT  158.364 61.385 160.038 61.493 ;
     RECT  156.672 61.151 156.906 61.529 ;
     RECT  161.82 61.159 162.45 61.591 ;
     RECT  236.556 61.159 236.574 61.591 ;
     RECT  152.64 59.161 152.802 61.619 ;
     RECT  152.64 61.619 152.658 61.655 ;
     RECT  205.632 61.151 208.53 61.691 ;
     RECT  221.94 59.809 235.386 61.709 ;
     RECT  205.704 61.691 208.53 61.727 ;
     RECT  28.224 60.809 31.482 61.763 ;
     RECT  158.472 61.493 160.038 61.763 ;
     RECT  161.82 61.591 162.882 61.771 ;
     RECT  236.556 61.591 236.61 61.771 ;
     RECT  28.224 61.763 30.726 61.997 ;
     RECT  28.224 61.997 29.934 62.033 ;
     RECT  158.616 61.763 160.038 62.033 ;
     RECT  161.208 61.771 162.882 62.069 ;
     RECT  205.776 61.727 208.53 62.159 ;
     RECT  26.1 57.299 26.838 62.195 ;
     RECT  158.616 62.033 159.297 62.195 ;
     RECT  31.464 61.763 31.482 62.231 ;
     RECT  153.615 61.321 154.566 62.231 ;
     RECT  162.36 62.069 162.882 62.231 ;
     RECT  162.468 62.231 162.882 62.239 ;
     RECT  28.872 62.033 29.934 62.267 ;
     RECT  237.456 60.151 237.51 62.285 ;
     RECT  161.208 62.069 161.442 62.311 ;
     RECT  30.708 61.997 30.726 62.339 ;
     RECT  236.52 61.771 236.61 62.381 ;
     RECT  158.724 62.195 159.297 62.429 ;
     RECT  161.1 62.311 161.442 62.429 ;
     RECT  162.468 62.239 163.17 62.429 ;
     RECT  161.424 62.429 161.442 62.477 ;
     RECT  166.428 62.401 166.446 62.501 ;
     RECT  237.456 62.285 237.474 62.669 ;
     RECT  130.212 58.621 130.23 62.699 ;
     RECT  28.872 62.267 29.697 62.735 ;
     RECT  162.468 62.429 162.486 62.735 ;
     RECT  26.82 62.195 26.838 62.743 ;
     RECT  236.52 62.381 236.574 62.765 ;
     RECT  160.02 62.033 160.038 62.771 ;
     RECT  24.015 59.261 24.786 62.807 ;
     RECT  156.888 61.529 156.906 62.807 ;
     RECT  26.82 62.743 26.91 62.879 ;
     RECT  221.94 61.709 235.35 63.019 ;
     RECT  221.94 63.019 235.638 63.149 ;
     RECT  236.52 62.765 236.538 63.211 ;
     RECT  236.484 63.211 236.538 63.499 ;
     RECT  222.948 63.149 235.638 63.545 ;
     RECT  223.344 63.545 235.638 63.595 ;
     RECT  236.448 63.499 236.538 63.595 ;
     RECT  206.028 62.159 208.53 63.653 ;
     RECT  223.344 63.595 236.538 63.815 ;
     RECT  231.804 63.815 236.538 64.319 ;
     RECT  223.344 63.815 230.922 64.561 ;
     RECT  231.804 64.319 236.502 64.561 ;
     RECT  237.492 63.307 237.51 64.589 ;
     RECT  223.344 64.561 236.502 64.769 ;
     RECT  231.516 64.769 236.502 64.895 ;
     RECT  223.344 64.769 230.67 65.129 ;
     RECT  231.624 64.895 236.502 65.129 ;
     RECT  227.268 65.129 230.67 65.261 ;
     RECT  231.804 65.129 236.502 65.273 ;
     RECT  223.344 65.129 226.314 65.309 ;
     RECT  227.268 65.261 230.598 65.309 ;
     RECT  231.804 65.273 235.962 65.399 ;
     RECT  227.268 65.309 227.862 65.435 ;
     RECT  227.268 65.435 227.646 65.507 ;
     RECT  228.78 65.309 230.598 65.549 ;
     RECT  231.804 65.399 232.362 65.549 ;
     RECT  233.172 65.399 235.962 65.741 ;
     RECT  233.28 65.741 235.962 65.939 ;
     RECT  233.28 65.939 235.386 66.209 ;
     RECT  228.888 65.549 230.598 66.479 ;
     RECT  233.28 66.209 235.314 66.479 ;
     RECT  233.28 66.479 235.17 66.515 ;
     RECT  233.28 66.515 235.134 66.631 ;
     RECT  231.804 65.549 231.822 66.667 ;
     RECT  232.596 66.631 235.134 66.701 ;
     RECT  231.804 66.667 231.858 66.715 ;
     RECT  233.46 66.701 235.134 66.749 ;
     RECT  231.516 66.715 231.858 67.019 ;
     RECT  233.676 66.749 235.026 67.019 ;
     RECT  231.804 67.019 231.858 67.277 ;
     RECT  233.892 67.019 235.026 67.289 ;
     RECT  233.892 67.289 234.897 67.559 ;
     RECT  231.804 67.277 231.822 68.107 ;
     RECT  232.632 67.531 232.65 68.107 ;
     RECT  221.94 63.149 221.958 68.171 ;
     RECT  231.804 68.107 232.65 68.341 ;
     RECT  231.444 68.341 232.65 68.381 ;
     RECT  231.696 68.381 232.65 69.223 ;
     RECT  213.015 53.861 213.39 69.251 ;
     RECT  231.588 69.223 232.65 69.685 ;
     RECT  228.996 66.479 230.598 69.871 ;
     RECT  231.444 69.685 232.65 69.871 ;
     RECT  228.708 69.871 232.65 70.069 ;
     RECT  223.344 65.309 226.17 70.375 ;
     RECT  206.604 63.653 208.53 70.403 ;
     RECT  228.384 70.069 232.65 70.445 ;
     RECT  223.344 70.375 226.314 70.529 ;
     RECT  227.628 65.507 227.646 70.651 ;
     RECT  227.412 70.651 227.646 70.699 ;
     RECT  227.412 70.699 227.79 70.799 ;
     RECT  228.636 70.445 232.65 70.799 ;
     RECT  231.552 70.799 232.65 70.871 ;
     RECT  227.628 70.799 227.79 71.491 ;
     RECT  228.636 70.799 230.598 71.491 ;
     RECT  223.344 70.529 226.17 71.519 ;
     RECT  227.628 71.491 230.598 71.803 ;
     RECT  231.588 70.871 232.65 71.803 ;
     RECT  227.628 71.803 232.65 71.879 ;
     RECT  227.628 71.879 230.778 71.885 ;
     RECT  226.836 72.157 226.854 72.475 ;
     RECT  227.628 71.885 230.598 72.475 ;
     RECT  226.836 72.475 230.598 72.491 ;
     RECT  227.268 72.491 230.598 72.605 ;
     RECT  227.628 72.605 230.598 72.715 ;
     RECT  223.344 71.519 225.702 72.841 ;
     RECT  223.344 72.841 225.81 72.893 ;
     RECT  227.628 72.715 230.634 74.011 ;
     RECT  227.628 74.011 230.85 74.059 ;
     RECT  231.588 71.879 232.65 74.059 ;
     RECT  227.628 74.059 232.65 74.309 ;
     RECT  231.516 74.309 232.65 74.389 ;
     RECT  234.615 67.559 234.897 74.551 ;
     RECT  231.516 74.389 233.226 74.587 ;
     RECT  234 74.551 234.897 74.587 ;
     RECT  231.516 74.587 234.897 74.651 ;
     RECT  227.628 74.309 230.742 75.115 ;
     RECT  231.516 74.651 232.65 75.115 ;
     RECT  227.628 75.115 232.65 75.505 ;
     RECT  223.344 72.893 225.702 75.533 ;
     RECT  227.484 75.505 232.65 75.581 ;
     RECT  233.424 74.651 233.442 75.659 ;
     RECT  227.484 75.581 230.814 75.929 ;
     RECT  231.588 75.581 232.65 76.081 ;
     RECT  231.588 76.081 232.83 76.351 ;
     RECT  223.344 75.533 225.522 76.469 ;
     RECT  231.444 76.351 232.83 76.621 ;
     RECT  231.444 76.621 232.974 76.855 ;
     RECT  234.615 74.651 234.897 76.891 ;
     RECT  227.484 75.929 230.706 76.939 ;
     RECT  231.444 76.855 233.586 76.939 ;
     RECT  234.396 76.891 234.897 77.395 ;
     RECT  227.484 76.939 233.586 77.431 ;
     RECT  234.396 77.395 235.134 77.431 ;
     RECT  227.484 77.431 235.206 77.549 ;
     RECT  227.484 77.549 227.502 77.791 ;
     RECT  223.344 76.469 224.097 77.819 ;
     RECT  228.348 77.549 235.206 77.971 ;
     RECT  214.596 53.861 214.614 78.161 ;
     RECT  228.348 77.971 235.386 78.439 ;
     RECT  236.232 77.629 236.25 78.439 ;
     RECT  228.348 78.439 236.25 78.637 ;
     RECT  228.348 78.637 236.322 78.979 ;
     RECT  224.856 76.469 225.522 79.079 ;
     RECT  228.348 78.979 236.538 79.141 ;
     RECT  237.528 78.511 237.546 79.177 ;
     RECT  206.604 70.403 207.897 79.439 ;
     RECT  223.815 77.819 224.097 79.963 ;
     RECT  225.036 79.079 225.522 79.963 ;
     RECT  223.815 79.963 225.522 80.015 ;
     RECT  237.492 79.177 237.546 80.395 ;
     RECT  237.456 80.395 237.546 80.429 ;
     RECT  237.456 80.429 237.51 80.599 ;
     RECT  227.196 77.791 227.502 80.761 ;
     RECT  228.348 79.141 236.61 80.761 ;
     RECT  225.036 80.015 225.522 81.301 ;
     RECT  225.036 81.301 226.17 81.409 ;
     RECT  227.196 80.761 236.61 81.409 ;
     RECT  237.42 80.599 237.51 81.677 ;
     RECT  225.036 81.409 236.61 81.913 ;
     RECT  224.964 81.913 236.61 82.061 ;
     RECT  237.42 81.677 237.438 82.157 ;
     RECT  224.964 82.061 236.574 82.255 ;
     RECT  223.815 80.015 224.097 82.291 ;
     RECT  224.856 82.255 236.574 82.291 ;
     RECT  223.815 82.291 236.574 82.949 ;
     RECT  206.604 79.439 206.622 83.021 ;
     RECT  223.815 82.949 226.314 83.021 ;
     RECT  227.664 82.949 236.574 83.021 ;
     RECT  225.36 83.021 226.314 83.129 ;
     RECT  237.42 83.035 237.438 83.213 ;
     RECT  223.815 83.021 224.55 83.219 ;
     RECT  225.36 83.129 225.846 83.219 ;
     RECT  227.664 83.021 235.098 83.219 ;
     RECT  235.98 83.021 236.574 83.309 ;
     RECT  235.98 83.309 236.538 83.501 ;
     RECT  225.36 83.219 225.45 83.525 ;
     RECT  225.36 83.525 225.378 83.669 ;
     RECT  228.312 83.219 229.497 83.669 ;
     RECT  230.328 83.219 235.098 83.759 ;
     RECT  228.924 83.669 229.497 83.795 ;
     RECT  230.328 83.759 232.146 83.795 ;
     RECT  2.415 26.519 2.697 83.987 ;
     RECT  7.815 36.365 8.097 83.987 ;
     RECT  13.215 37.757 13.497 83.987 ;
     RECT  18.615 40.733 18.897 83.987 ;
     RECT  24.015 62.807 24.297 83.987 ;
     RECT  29.415 62.735 29.697 83.987 ;
     RECT  34.815 60.193 35.097 83.987 ;
     RECT  40.215 60.193 40.497 83.987 ;
     RECT  45.615 60.193 45.897 83.987 ;
     RECT  51.015 60.193 51.297 83.987 ;
     RECT  56.415 60.193 56.697 83.987 ;
     RECT  61.815 60.193 62.097 83.987 ;
     RECT  67.215 60.193 67.497 83.987 ;
     RECT  72.615 60.193 72.897 83.987 ;
     RECT  78.015 60.193 78.297 83.987 ;
     RECT  83.415 60.193 83.697 83.987 ;
     RECT  88.815 60.193 89.097 83.987 ;
     RECT  94.215 60.193 94.497 83.987 ;
     RECT  99.615 60.193 99.897 83.987 ;
     RECT  105.015 60.193 105.297 83.987 ;
     RECT  110.415 60.193 110.697 83.987 ;
     RECT  115.815 60.193 116.097 83.987 ;
     RECT  121.215 59.923 121.497 83.987 ;
     RECT  126.615 60.193 126.897 83.987 ;
     RECT  132.015 60.193 132.297 83.987 ;
     RECT  137.415 60.193 137.697 83.987 ;
     RECT  142.815 60.377 143.097 83.987 ;
     RECT  148.215 60.377 148.497 83.987 ;
     RECT  153.615 62.231 153.897 83.987 ;
     RECT  159.015 62.429 159.297 83.987 ;
     RECT  164.415 60.809 164.697 83.987 ;
     RECT  169.815 60.193 170.097 83.987 ;
     RECT  175.215 60.193 175.497 83.987 ;
     RECT  180.615 60.193 180.897 83.987 ;
     RECT  186.015 60.179 186.297 83.987 ;
     RECT  191.415 60.035 191.697 83.987 ;
     RECT  196.815 60.193 197.097 83.987 ;
     RECT  202.215 60.193 202.497 83.987 ;
     RECT  207.615 79.439 207.897 83.987 ;
     RECT  213.015 69.251 213.297 83.987 ;
     RECT  218.415 57.875 218.697 83.987 ;
     RECT  223.815 83.219 224.097 83.987 ;
     RECT  229.215 83.795 229.497 83.987 ;
     RECT  233.028 83.759 234.897 83.987 ;
     RECT  236.52 83.501 236.538 84.029 ;
     RECT  231.66 83.795 232.146 84.065 ;
     RECT  233.028 83.987 234.705 84.065 ;
     RECT  231.984 84.065 232.146 84.137 ;
     RECT  233.028 84.065 233.154 84.137 ;
     RECT  232.128 84.137 232.146 84.173 ;
     RECT  233.028 84.137 233.046 84.209 ;
     RECT  234.324 84.065 234.705 84.209 ;
     RECT  2.415 83.987 2.505 84.257 ;
     RECT  7.815 83.987 7.905 84.257 ;
     RECT  13.215 83.987 13.305 84.257 ;
     RECT  18.615 83.987 18.705 84.257 ;
     RECT  24.015 83.987 24.105 84.257 ;
     RECT  29.415 83.987 29.505 84.257 ;
     RECT  34.815 83.987 34.905 84.257 ;
     RECT  40.215 83.987 40.305 84.257 ;
     RECT  45.615 83.987 45.705 84.257 ;
     RECT  51.015 83.987 51.105 84.257 ;
     RECT  56.415 83.987 56.505 84.257 ;
     RECT  61.815 83.987 61.905 84.257 ;
     RECT  67.215 83.987 67.305 84.257 ;
     RECT  72.615 83.987 72.705 84.257 ;
     RECT  78.015 83.987 78.105 84.257 ;
     RECT  83.415 83.987 83.505 84.257 ;
     RECT  88.815 83.987 88.905 84.257 ;
     RECT  94.215 83.987 94.305 84.257 ;
     RECT  99.615 83.987 99.705 84.257 ;
     RECT  105.015 83.987 105.105 84.257 ;
     RECT  110.415 83.987 110.505 84.257 ;
     RECT  115.815 83.987 115.905 84.257 ;
     RECT  121.215 83.987 121.305 84.257 ;
     RECT  126.615 83.987 126.705 84.257 ;
     RECT  132.015 83.987 132.105 84.257 ;
     RECT  137.415 83.987 137.505 84.257 ;
     RECT  142.815 83.987 142.905 84.257 ;
     RECT  148.215 83.987 148.305 84.257 ;
     RECT  153.615 83.987 153.705 84.257 ;
     RECT  159.015 83.987 159.105 84.257 ;
     RECT  164.415 83.987 164.505 84.257 ;
     RECT  169.815 83.987 169.905 84.257 ;
     RECT  175.215 83.987 175.305 84.257 ;
     RECT  180.615 83.987 180.705 84.257 ;
     RECT  186.015 83.987 186.105 84.257 ;
     RECT  191.415 83.987 191.505 84.257 ;
     RECT  196.815 83.987 196.905 84.257 ;
     RECT  202.215 83.987 202.305 84.257 ;
     RECT  207.615 83.987 207.705 84.257 ;
     RECT  213.015 83.987 213.105 84.257 ;
     RECT  218.415 83.987 218.505 84.257 ;
     RECT  223.815 83.987 223.905 84.257 ;
     RECT  229.215 83.987 229.305 84.257 ;
     RECT  234.615 84.209 234.705 84.257 ;
    LAYER M4 ;
     RECT  2.329 3.36 2.408 3.384 ;
     RECT  2.365 24.624 2.408 24.648 ;
     RECT  2.408 2.148 2.512 84.252 ;
     RECT  2.512 2.418 2.704 83.982 ;
     RECT  2.704 3.36 2.819 7.272 ;
     RECT  2.819 3.936 2.837 7.272 ;
     RECT  2.761 0.816 2.869 0.84 ;
     RECT  2.704 24.624 2.915 26.28 ;
     RECT  2.704 21.648 2.917 22.776 ;
     RECT  2.915 25.104 2.917 26.28 ;
     RECT  2.704 8.496 3.133 8.52 ;
     RECT  2.917 25.104 3.491 25.128 ;
     RECT  2.704 27.888 3.539 27.912 ;
     RECT  2.704 29.088 3.565 29.112 ;
     RECT  2.837 5.136 3.683 7.272 ;
     RECT  2.704 13.488 3.729 13.56 ;
     RECT  2.869 0.096 3.781 0.84 ;
     RECT  2.704 11.808 3.805 12.504 ;
     RECT  3.683 5.136 3.971 6.312 ;
     RECT  2.917 26.256 3.985 26.28 ;
     RECT  3.925 2.88 4.057 2.904 ;
     RECT  2.837 3.936 4.057 3.96 ;
     RECT  3.985 26.256 4.057 26.76 ;
     RECT  3.781 0.096 4.124 1.176 ;
     RECT  3.805 11.328 4.133 12.504 ;
     RECT  4.165 8.784 4.172 8.808 ;
     RECT  4.124 0.096 4.211 1.704 ;
     RECT  4.133 11.328 4.213 11.4 ;
     RECT  4.057 2.88 4.412 3.96 ;
     RECT  3.971 5.136 4.412 5.4 ;
     RECT  3.805 7.296 4.453 7.32 ;
     RECT  4.172 8.784 4.453 9.384 ;
     RECT  4.133 12.48 4.453 12.504 ;
     RECT  2.917 21.648 4.453 22.2 ;
     RECT  4.453 21.36 4.489 22.2 ;
     RECT  4.453 7.296 4.556 9.384 ;
     RECT  4.213 10.464 4.556 11.4 ;
     RECT  4.057 25.872 4.569 26.76 ;
     RECT  4.489 20.544 4.637 22.2 ;
     RECT  4.569 25.392 4.643 26.76 ;
     RECT  4.556 29.184 4.643 29.208 ;
     RECT  3.877 24.384 4.844 24.408 ;
     RECT  4.643 25.392 4.883 25.944 ;
     RECT  4.556 7.296 4.921 11.4 ;
     RECT  4.637 22.176 4.931 22.2 ;
     RECT  4.844 24.048 4.931 24.408 ;
     RECT  4.883 25.92 4.931 25.944 ;
     RECT  4.412 2.88 5.029 5.4 ;
     RECT  4.597 15.984 5.029 16.008 ;
     RECT  4.921 6.816 5.101 11.4 ;
     RECT  5.029 2.88 5.125 5.688 ;
     RECT  5.101 6.672 5.125 11.4 ;
     RECT  4.453 12.48 5.125 12.552 ;
     RECT  3.729 13.536 5.125 13.56 ;
     RECT  5.125 2.88 5.269 11.4 ;
     RECT  5.125 12.48 5.269 13.56 ;
     RECT  5.269 2.88 5.315 13.56 ;
     RECT  5.276 28.8 5.317 28.824 ;
     RECT  4.211 0.096 5.321 1.272 ;
     RECT  5.315 2.88 5.356 11.592 ;
     RECT  5.317 27.888 5.363 28.824 ;
     RECT  5.029 15.984 5.393 16.536 ;
     RECT  5.365 17.568 5.641 17.592 ;
     RECT  4.637 20.544 5.651 21.192 ;
     RECT  5.317 31.92 5.753 31.944 ;
     RECT  5.356 2.88 5.893 11.4 ;
     RECT  5.641 17.52 5.969 17.592 ;
     RECT  5.677 21.648 6.037 21.768 ;
     RECT  5.173 23.376 6.044 23.4 ;
     RECT  4.931 24.384 6.044 24.408 ;
     RECT  6.044 23.376 6.073 24.408 ;
     RECT  6.037 21.648 6.085 22.056 ;
     RECT  5.893 2.304 6.131 11.4 ;
     RECT  5.996 18.672 6.181 18.696 ;
     RECT  6.085 21.648 6.221 22.344 ;
     RECT  6.131 2.304 6.229 3.432 ;
     RECT  5.315 13.344 6.289 13.56 ;
     RECT  5.393 16.512 6.289 16.536 ;
     RECT  5.969 17.52 6.289 17.544 ;
     RECT  6.221 21.744 6.332 22.344 ;
     RECT  6.073 23.376 6.332 24.504 ;
     RECT  6.073 30.864 6.353 30.888 ;
     RECT  6.181 18.672 6.397 18.84 ;
     RECT  5.651 20.544 6.397 20.568 ;
     RECT  6.332 21.744 6.419 24.504 ;
     RECT  6.353 30.768 6.437 30.888 ;
     RECT  5.363 27.888 6.469 27.912 ;
     RECT  6.469 27.216 6.541 27.912 ;
     RECT  6.541 26.112 6.613 26.136 ;
     RECT  6.541 27.168 6.613 27.912 ;
     RECT  6.419 23.328 6.659 24.504 ;
     RECT  6.613 26.112 6.659 27.96 ;
     RECT  6.419 21.744 6.833 22.344 ;
     RECT  6.659 23.616 7.004 24.504 ;
     RECT  6.229 2.256 7.225 3.432 ;
     RECT  6.131 4.512 7.225 11.4 ;
     RECT  5.321 0.096 7.237 1.224 ;
     RECT  7.225 2.256 7.237 11.4 ;
     RECT  6.659 26.88 7.333 27.96 ;
     RECT  6.289 16.512 7.405 17.544 ;
     RECT  6.289 13.344 7.429 13.848 ;
     RECT  7.429 13.344 7.549 14.04 ;
     RECT  7.405 15.84 7.549 17.544 ;
     RECT  7.004 23.616 7.693 25.32 ;
     RECT  7.333 26.88 7.693 28.536 ;
     RECT  6.397 18.672 7.729 20.568 ;
     RECT  6.833 21.744 7.729 22.248 ;
     RECT  7.045 31.344 7.729 31.368 ;
     RECT  7.237 0.096 7.801 11.4 ;
     RECT  7.801 0.096 7.808 11.976 ;
     RECT  7.549 13.344 7.808 17.544 ;
     RECT  7.729 18.672 7.808 22.248 ;
     RECT  7.693 23.616 7.808 28.536 ;
     RECT  6.908 30.192 7.808 30.216 ;
     RECT  7.729 31.344 7.808 32.328 ;
     RECT  6.929 35.328 7.808 35.352 ;
     RECT  7.153 36.336 7.808 36.36 ;
     RECT  7.808 0.096 7.912 84.252 ;
     RECT  7.912 0.096 8.104 83.982 ;
     RECT  8.104 13.344 8.243 33.528 ;
     RECT  8.243 13.344 8.387 25.416 ;
     RECT  8.243 26.88 8.489 33.528 ;
     RECT  8.489 26.88 8.633 30.792 ;
     RECT  8.489 31.92 8.723 33.528 ;
     RECT  8.387 13.344 8.741 23.64 ;
     RECT  8.633 26.88 8.741 27.768 ;
     RECT  8.741 19.344 8.813 23.64 ;
     RECT  8.723 31.92 9.059 31.944 ;
     RECT  8.104 35.76 9.097 36.36 ;
     RECT  8.104 0.096 9.107 11.976 ;
     RECT  8.104 34.56 9.107 34.584 ;
     RECT  8.633 29.04 9.109 30.792 ;
     RECT  9.109 29.04 9.251 30.744 ;
     RECT  9.251 29.04 9.281 29.064 ;
     RECT  9.251 30.336 9.281 30.744 ;
     RECT  8.741 13.344 9.292 18.216 ;
     RECT  8.387 25.104 9.313 25.416 ;
     RECT  9.107 0.096 9.317 11.16 ;
     RECT  9.281 30.72 9.353 30.744 ;
     RECT  9.292 13.344 9.397 15 ;
     RECT  8.813 19.344 9.443 23.544 ;
     RECT  8.741 26.88 9.569 27.336 ;
     RECT  9.397 13.248 9.677 15 ;
     RECT  9.097 35.76 9.709 36.6 ;
     RECT  9.677 13.248 9.713 14.232 ;
     RECT  9.292 15.984 9.781 18.216 ;
     RECT  9.713 13.584 9.785 14.232 ;
     RECT  9.313 25.104 9.821 25.848 ;
     RECT  9.569 27.216 9.827 27.336 ;
     RECT  9.443 20.016 9.884 23.544 ;
     RECT  8.723 32.976 9.925 33 ;
     RECT  9.925 32.736 10.109 33 ;
     RECT  10.109 32.736 10.152 32.76 ;
     RECT  9.821 25.824 10.177 25.848 ;
     RECT  9.884 20.016 10.211 24.408 ;
     RECT  10.177 25.824 10.253 26.232 ;
     RECT  9.709 34.8 10.259 36.6 ;
     RECT  10.253 26.208 10.261 26.232 ;
     RECT  10.152 32.352 10.357 32.76 ;
     RECT  9.781 15.984 10.393 18.936 ;
     RECT  9.733 28.944 10.541 28.968 ;
     RECT  10.213 12.48 10.717 12.504 ;
     RECT  9.785 13.584 10.717 13.848 ;
     RECT  10.393 15.936 10.741 18.936 ;
     RECT  10.211 20.016 10.741 22.776 ;
     RECT  10.465 27.552 10.837 27.576 ;
     RECT  10.789 28.56 10.837 28.584 ;
     RECT  10.717 12.48 10.861 13.848 ;
     RECT  10.837 27.552 10.883 28.584 ;
     RECT  10.861 12.48 10.933 14.184 ;
     RECT  10.741 15.936 10.933 22.776 ;
     RECT  9.317 0.096 11.081 10.824 ;
     RECT  10.357 31.44 11.081 32.76 ;
     RECT  11.081 1.392 11.261 10.824 ;
     RECT  11.221 34.128 11.293 34.152 ;
     RECT  11.081 31.776 11.333 32.76 ;
     RECT  10.933 12.384 11.365 22.776 ;
     RECT  11.081 0.096 11.405 0.36 ;
     RECT  11.293 33.792 11.405 34.152 ;
     RECT  10.211 23.76 11.413 24.408 ;
     RECT  11.365 11.952 11.441 22.776 ;
     RECT  11.261 2.88 11.477 10.824 ;
     RECT  11.405 0.192 11.513 0.36 ;
     RECT  11.441 11.952 11.513 22.008 ;
     RECT  11.513 11.952 11.548 21.912 ;
     RECT  11.477 3.936 11.555 10.824 ;
     RECT  11.405 34.128 11.581 34.152 ;
     RECT  11.555 4.272 11.603 10.824 ;
     RECT  11.603 5.664 11.621 10.824 ;
     RECT  11.413 23.76 11.689 24.552 ;
     RECT  11.689 23.376 11.725 24.552 ;
     RECT  11.477 2.88 11.729 2.904 ;
     RECT  11.548 11.952 11.747 21.672 ;
     RECT  11.333 31.776 11.747 31.8 ;
     RECT  11.747 19.488 11.795 21.672 ;
     RECT  11.725 23.376 11.795 24.888 ;
     RECT  11.261 1.392 11.837 1.848 ;
     RECT  11.621 5.664 11.837 9.24 ;
     RECT  11.756 27.024 11.843 27.048 ;
     RECT  11.621 10.8 11.852 10.824 ;
     RECT  11.747 11.952 11.852 17.928 ;
     RECT  10.259 35.76 11.869 36.6 ;
     RECT  11.513 0.24 11.873 0.36 ;
     RECT  11.837 9.072 11.873 9.24 ;
     RECT  11.873 9.072 11.981 9.096 ;
     RECT  11.869 35.328 12.013 36.6 ;
     RECT  11.905 37.872 12.013 37.896 ;
     RECT  11.852 10.8 12.035 17.928 ;
     RECT  11.795 23.712 12.077 24.888 ;
     RECT  12.077 23.712 12.092 25.128 ;
     RECT  11.873 0.336 12.125 0.36 ;
     RECT  12.092 23.712 12.157 25.32 ;
     RECT  12.157 23.712 12.181 25.944 ;
     RECT  11.581 34.128 12.193 34.248 ;
     RECT  12.013 35.328 12.193 37.896 ;
     RECT  11.756 30.432 12.229 30.456 ;
     RECT  11.837 1.392 12.269 1.416 ;
     RECT  10.883 28.272 12.445 28.584 ;
     RECT  12.229 29.904 12.517 30.456 ;
     RECT  11.977 32.832 12.625 33.096 ;
     RECT  12.193 34.128 12.625 37.896 ;
     RECT  12.661 22.08 12.901 22.584 ;
     RECT  12.181 23.712 12.901 26.76 ;
     RECT  12.517 29.904 12.908 31.272 ;
     RECT  12.625 32.832 12.908 37.896 ;
     RECT  12.035 11.136 13.045 11.16 ;
     RECT  12.901 22.08 13.057 26.76 ;
     RECT  12.445 28.224 13.057 28.584 ;
     RECT  11.837 5.664 13.093 7.8 ;
     RECT  11.795 19.488 13.129 20.904 ;
     RECT  13.093 5.568 13.208 7.8 ;
     RECT  13.165 9.504 13.208 9.528 ;
     RECT  13.045 11.136 13.208 11.256 ;
     RECT  12.035 12.384 13.208 17.928 ;
     RECT  13.129 19.488 13.208 20.952 ;
     RECT  13.057 22.08 13.208 28.584 ;
     RECT  12.908 29.904 13.208 37.896 ;
     RECT  13.208 2.148 13.312 84.252 ;
     RECT  13.312 2.418 13.504 83.982 ;
     RECT  13.504 6.048 13.601 6.84 ;
     RECT  13.504 29.376 13.715 29.4 ;
     RECT  13.504 12.48 13.817 15.048 ;
     RECT  13.504 30.816 13.925 31.416 ;
     RECT  13.504 24.864 14.061 27.672 ;
     RECT  13.601 6.384 14.243 6.84 ;
     RECT  13.504 8.928 14.243 11.4 ;
     RECT  13.504 16.416 14.321 23.736 ;
     RECT  14.061 24.864 14.485 26.664 ;
     RECT  13.504 3.936 14.497 4.536 ;
     RECT  14.243 9.792 14.501 11.4 ;
     RECT  13.504 32.496 14.501 37.896 ;
     RECT  13.817 12.864 14.569 15.048 ;
     RECT  14.321 16.416 14.723 23.304 ;
     RECT  14.497 29.472 14.753 29.496 ;
     RECT  14.061 27.648 14.789 27.672 ;
     RECT  14.569 12.864 14.825 15.432 ;
     RECT  14.485 24.336 14.867 26.664 ;
     RECT  14.501 9.792 14.933 10.392 ;
     RECT  14.497 3.936 15.001 5.112 ;
     RECT  14.825 14.64 15.013 15.432 ;
     RECT  14.723 16.416 15.013 21.528 ;
     RECT  14.825 12.864 15.059 13.272 ;
     RECT  15.059 12.864 15.068 12.888 ;
     RECT  15.001 28.512 15.085 28.632 ;
     RECT  14.893 29.76 15.145 29.928 ;
     RECT  14.785 7.824 15.155 7.848 ;
     RECT  15.068 11.904 15.155 12.888 ;
     RECT  15.145 29.76 15.229 30.264 ;
     RECT  14.501 33.888 15.469 37.896 ;
     RECT  15.229 29.76 15.473 30.024 ;
     RECT  15.013 14.64 15.481 21.528 ;
     RECT  14.723 22.704 15.5 23.304 ;
     RECT  14.867 24.336 15.5 24.696 ;
     RECT  15.469 33.888 15.505 38.28 ;
     RECT  15.001 3.12 15.541 5.112 ;
     RECT  14.243 6.384 15.541 6.504 ;
     RECT  14.867 25.728 15.541 26.664 ;
     RECT  15.473 29.904 15.545 30.024 ;
     RECT  15.541 0.144 15.613 0.168 ;
     RECT  15.541 3.12 15.637 6.504 ;
     RECT  13.925 31.392 15.637 31.416 ;
     RECT  15.325 32.448 15.637 32.472 ;
     RECT  15.505 33.888 15.637 38.52 ;
     RECT  15.637 3.12 15.683 7.416 ;
     RECT  14.933 9.792 15.685 10.248 ;
     RECT  15.637 31.392 15.685 38.52 ;
     RECT  15.541 25.728 15.725 27.384 ;
     RECT  15.685 31.344 15.725 38.52 ;
     RECT  15.683 5.616 15.733 7.416 ;
     RECT  15.5 22.704 15.757 24.696 ;
     RECT  15.725 31.344 15.769 31.368 ;
     RECT  15.481 18.768 15.829 21.528 ;
     RECT  15.757 22.56 15.829 24.696 ;
     RECT  15.481 14.64 15.875 17.448 ;
     RECT  15.613 0.144 15.937 0.6 ;
     RECT  15.725 25.728 15.941 26.424 ;
     RECT  15.683 3.12 15.973 4.536 ;
     RECT  15.829 18.768 16.005 24.696 ;
     RECT  15.875 14.64 16.045 15.384 ;
     RECT  15.155 12.528 16.079 12.888 ;
     RECT  16.045 14.16 16.079 15.384 ;
     RECT  16.079 12.528 16.115 15.384 ;
     RECT  16.115 12.528 16.117 14.232 ;
     RECT  15.685 8.88 16.153 10.248 ;
     RECT  15.085 28.608 16.189 28.632 ;
     RECT  16.117 11.904 16.259 14.232 ;
     RECT  16.005 22.56 16.297 24.696 ;
     RECT  15.941 25.728 16.297 25.752 ;
     RECT  16.153 8.496 16.3 10.248 ;
     RECT  16.259 11.904 16.403 12.552 ;
     RECT  15.725 32.448 16.403 38.52 ;
     RECT  15.545 30 16.508 30.024 ;
     RECT  16.005 18.768 16.549 21.144 ;
     RECT  15.875 16.512 16.589 17.448 ;
     RECT  16.508 30 16.595 30.264 ;
     RECT  15.937 0.096 16.645 0.6 ;
     RECT  15.733 5.616 16.789 7.224 ;
     RECT  16.3 8.496 16.789 10.056 ;
     RECT  16.589 16.56 16.885 17.448 ;
     RECT  16.549 18.432 16.885 21.144 ;
     RECT  15.973 2.88 16.909 4.536 ;
     RECT  16.789 5.616 16.909 10.056 ;
     RECT  16.189 28.176 17.017 28.632 ;
     RECT  16.595 30 17.029 30.216 ;
     RECT  16.837 11.424 17.049 11.448 ;
     RECT  16.981 31.92 17.065 31.944 ;
     RECT  17.017 27.984 17.089 28.632 ;
     RECT  17.029 29.712 17.129 30.216 ;
     RECT  17.089 27.936 17.228 28.632 ;
     RECT  16.259 13.632 17.269 14.232 ;
     RECT  16.115 15.36 17.269 15.384 ;
     RECT  16.885 16.56 17.269 21.144 ;
     RECT  16.297 22.56 17.269 25.752 ;
     RECT  17.228 27.216 17.315 28.632 ;
     RECT  17.269 16.56 17.345 25.992 ;
     RECT  17.345 16.752 17.459 25.992 ;
     RECT  17.459 25.728 17.489 25.992 ;
     RECT  16.403 12.528 17.521 12.552 ;
     RECT  16.909 2.88 17.557 10.056 ;
     RECT  17.489 25.968 17.593 25.992 ;
     RECT  17.521 11.952 17.653 12.552 ;
     RECT  17.269 13.632 17.653 15.384 ;
     RECT  17.653 11.952 17.773 15.384 ;
     RECT  16.403 33.264 17.845 38.52 ;
     RECT  17.773 39.504 17.845 39.528 ;
     RECT  17.557 2.544 17.981 10.056 ;
     RECT  17.845 33.264 18.205 39.528 ;
     RECT  18.205 33.264 18.241 40.104 ;
     RECT  17.315 27.888 18.277 28.632 ;
     RECT  17.981 2.544 18.349 10.824 ;
     RECT  17.773 11.952 18.349 15.48 ;
     RECT  16.645 0.096 18.373 1.176 ;
     RECT  17.593 25.968 18.469 26.808 ;
     RECT  18.241 33.12 18.565 40.104 ;
     RECT  18.373 0.096 18.601 1.368 ;
     RECT  18.601 0.048 18.608 1.368 ;
     RECT  18.349 2.544 18.608 15.48 ;
     RECT  17.459 16.752 18.608 24.168 ;
     RECT  18.469 25.296 18.608 26.808 ;
     RECT  18.277 27.888 18.608 29.208 ;
     RECT  18.312 30.816 18.608 30.84 ;
     RECT  18.565 32.496 18.608 40.104 ;
     RECT  18.608 0.048 18.712 84.252 ;
     RECT  18.712 2.418 18.904 83.982 ;
     RECT  18.712 0.048 19.001 1.368 ;
     RECT  18.904 25.296 19.037 25.944 ;
     RECT  18.904 27.6 19.043 28.44 ;
     RECT  19.001 0.048 19.073 1.176 ;
     RECT  19.073 0.048 19.091 0.312 ;
     RECT  18.904 15.024 19.109 24.312 ;
     RECT  18.904 2.88 19.361 9.432 ;
     RECT  19.109 15.168 19.379 24.312 ;
     RECT  19.379 19.008 19.427 24.168 ;
     RECT  19.379 15.168 19.613 17.88 ;
     RECT  19.043 27.6 19.649 28.008 ;
     RECT  19.361 3.072 19.715 9.432 ;
     RECT  19.037 25.92 19.715 25.944 ;
     RECT  18.904 29.712 19.897 30.792 ;
     RECT  19.613 15.168 19.955 15.864 ;
     RECT  18.904 32.496 19.969 40.728 ;
     RECT  19.897 29.232 19.973 30.792 ;
     RECT  18.904 10.464 20.005 13.848 ;
     RECT  19.973 29.232 20.101 30.552 ;
     RECT  19.427 19.008 20.117 23.496 ;
     RECT  19.091 0.048 20.189 0.12 ;
     RECT  19.715 3.072 20.387 8.52 ;
     RECT  20.387 3.072 20.441 8.184 ;
     RECT  19.613 17.088 20.473 17.88 ;
     RECT  20.117 19.008 20.473 20.328 ;
     RECT  19.649 27.888 20.509 28.008 ;
     RECT  20.101 29.184 20.509 30.552 ;
     RECT  20.005 9.84 20.513 13.848 ;
     RECT  20.513 10.896 20.533 13.848 ;
     RECT  19.955 15.168 20.533 15.192 ;
     RECT  20.533 10.896 20.579 15.192 ;
     RECT  20.117 21.408 20.585 23.496 ;
     RECT  20.585 21.408 20.627 21.96 ;
     RECT  20.513 9.84 20.693 9.864 ;
     RECT  20.189 0.096 20.729 0.12 ;
     RECT  20.732 1.104 20.819 1.128 ;
     RECT  19.969 32.448 20.828 40.728 ;
     RECT  20.441 3.072 20.869 7.56 ;
     RECT  20.616 26.736 20.869 26.76 ;
     RECT  20.509 27.888 20.869 30.552 ;
     RECT  20.627 21.408 20.873 21.672 ;
     RECT  20.585 22.944 20.905 23.496 ;
     RECT  20.828 32.352 20.915 40.728 ;
     RECT  20.869 26.688 20.941 30.552 ;
     RECT  20.473 17.088 21.011 20.328 ;
     RECT  20.591 25.104 21.011 25.128 ;
     RECT  20.941 26.688 21.059 30.84 ;
     RECT  20.915 33.072 21.125 40.728 ;
     RECT  20.965 1.152 21.269 1.176 ;
     RECT  20.579 12.912 21.301 15.192 ;
     RECT  21.011 17.088 21.301 17.928 ;
     RECT  21.011 19.008 21.301 20.328 ;
     RECT  21.059 27.936 21.445 30.84 ;
     RECT  21.193 31.92 21.445 31.944 ;
     RECT  20.905 22.944 21.491 23.928 ;
     RECT  20.579 10.896 21.548 11.88 ;
     RECT  21.301 12.912 21.548 17.928 ;
     RECT  20.869 2.88 21.697 7.56 ;
     RECT  21.445 27.936 21.701 31.944 ;
     RECT  21.491 22.944 21.733 22.968 ;
     RECT  21.701 28.752 21.881 31.944 ;
     RECT  21.697 2.736 21.917 7.8 ;
     RECT  21.059 26.688 21.932 26.712 ;
     RECT  21.548 10.896 21.985 17.928 ;
     RECT  21.917 3.408 22.089 7.8 ;
     RECT  21.733 22.8 22.093 22.968 ;
     RECT  21.985 10.848 22.124 17.928 ;
     RECT  22.124 10.272 22.22 17.928 ;
     RECT  21.301 19.008 22.22 21.192 ;
     RECT  22.089 7.776 22.345 7.8 ;
     RECT  22.345 7.776 22.381 8.712 ;
     RECT  22.089 3.408 22.403 6.264 ;
     RECT  22.093 22.752 22.453 22.968 ;
     RECT  22.22 10.272 22.457 21.192 ;
     RECT  22.453 22.608 22.489 22.968 ;
     RECT  21.932 26.64 22.489 26.712 ;
     RECT  22.069 32.064 22.501 32.088 ;
     RECT  21.125 33.072 22.501 38.52 ;
     RECT  22.381 7.776 22.525 9.096 ;
     RECT  22.457 10.272 22.525 11.928 ;
     RECT  22.525 7.776 22.643 11.928 ;
     RECT  22.457 12.912 22.643 21.192 ;
     RECT  22.489 26.64 22.669 27.144 ;
     RECT  22.501 32.064 22.739 38.52 ;
     RECT  22.643 13.632 22.777 21.192 ;
     RECT  22.489 22.32 22.777 22.968 ;
     RECT  22.669 26.064 22.796 27.144 ;
     RECT  22.165 24.72 22.813 24.744 ;
     RECT  22.796 26.064 22.813 27.24 ;
     RECT  21.881 28.752 22.849 30.84 ;
     RECT  22.777 13.632 23.029 22.968 ;
     RECT  22.813 24.72 23.029 27.24 ;
     RECT  23.029 13.632 23.065 27.24 ;
     RECT  22.849 28.752 23.065 30.888 ;
     RECT  22.739 33.072 23.173 38.52 ;
     RECT  21.125 39.504 23.173 40.728 ;
     RECT  22.403 3.696 23.461 6.264 ;
     RECT  22.643 8.496 23.605 11.928 ;
     RECT  23.065 13.632 23.605 30.888 ;
     RECT  23.605 8.496 23.893 30.888 ;
     RECT  23.389 42.768 23.893 42.792 ;
     RECT  23.461 3.696 24.008 6.888 ;
     RECT  23.893 8.448 24.008 30.888 ;
     RECT  22.739 32.064 24.008 32.088 ;
     RECT  23.173 33.072 24.008 40.728 ;
     RECT  23.893 42.768 24.008 43.368 ;
     RECT  24.008 2.148 24.112 84.252 ;
     RECT  24.112 2.418 24.304 83.982 ;
     RECT  24.304 7.92 24.419 9.768 ;
     RECT  24.304 14.496 24.419 19.944 ;
     RECT  24.304 23.904 24.419 29.496 ;
     RECT  24.304 6.528 24.515 6.84 ;
     RECT  24.419 23.904 24.515 27.72 ;
     RECT  24.304 2.832 24.517 2.856 ;
     RECT  24.515 23.904 24.563 27.384 ;
     RECT  24.563 23.904 24.653 27.096 ;
     RECT  24.419 29.184 24.659 29.496 ;
     RECT  24.304 30.576 24.659 30.888 ;
     RECT  24.304 32.688 24.833 42.216 ;
     RECT  24.419 7.92 25.157 9.672 ;
     RECT  24.419 17.28 25.228 19.944 ;
     RECT  24.304 11.952 25.229 12.84 ;
     RECT  24.659 30.816 25.292 30.888 ;
     RECT  24.653 23.952 25.301 27.096 ;
     RECT  24.659 29.184 25.331 29.208 ;
     RECT  24.304 45.648 25.369 45.672 ;
     RECT  24.515 6.816 25.373 6.84 ;
     RECT  25.229 11.952 25.379 12.36 ;
     RECT  24.833 32.688 25.379 41.352 ;
     RECT  24.419 14.496 25.388 15.96 ;
     RECT  24.304 10.848 25.409 10.872 ;
     RECT  25.388 14.496 25.475 16.152 ;
     RECT  25.333 43.632 25.621 43.656 ;
     RECT  24.304 3.888 25.661 5.4 ;
     RECT  25.661 4.224 25.669 5.4 ;
     RECT  25.621 43.344 25.697 43.656 ;
     RECT  25.697 43.344 25.705 43.368 ;
     RECT  25.157 7.92 25.715 7.944 ;
     RECT  25.301 26.736 25.724 27.096 ;
     RECT  25.228 17.856 25.729 19.944 ;
     RECT  24.304 21.12 25.729 22.776 ;
     RECT  25.724 26.736 25.945 27.24 ;
     RECT  25.513 28.464 25.945 28.968 ;
     RECT  25.157 9.648 26.012 9.672 ;
     RECT  25.945 10.704 26.012 10.728 ;
     RECT  26.012 13.488 26.053 13.512 ;
     RECT  25.475 14.496 26.053 15.816 ;
     RECT  25.729 17.856 26.053 22.776 ;
     RECT  25.301 23.952 26.053 25.464 ;
     RECT  26.012 9.648 26.099 10.728 ;
     RECT  26.053 13.488 26.099 15.816 ;
     RECT  25.621 16.8 26.195 16.824 ;
     RECT  25.292 30.816 26.197 31.656 ;
     RECT  24.304 47.376 26.197 47.4 ;
     RECT  25.669 4.224 26.201 5.64 ;
     RECT  26.197 46.704 26.233 47.4 ;
     RECT  25.379 12.336 26.236 12.36 ;
     RECT  26.201 4.272 26.273 5.64 ;
     RECT  26.273 4.464 26.309 5.64 ;
     RECT  25.945 26.736 26.339 28.968 ;
     RECT  26.099 14.352 26.381 15.816 ;
     RECT  26.309 5.088 26.444 5.64 ;
     RECT  26.339 26.736 26.444 28.872 ;
     RECT  26.053 17.856 26.489 25.464 ;
     RECT  26.149 8.496 26.531 8.52 ;
     RECT  26.197 30.816 26.533 31.704 ;
     RECT  26.099 10.704 26.54 10.728 ;
     RECT  26.533 30.624 26.579 31.704 ;
     RECT  26.54 10.704 26.627 11.304 ;
     RECT  26.444 5.088 26.737 6.264 ;
     RECT  26.579 30.624 26.773 30.648 ;
     RECT  25.369 44.976 26.773 45.672 ;
     RECT  26.444 26.688 26.813 28.872 ;
     RECT  26.813 27.312 26.819 28.872 ;
     RECT  26.773 30.048 26.857 30.648 ;
     RECT  26.489 19.008 26.917 25.464 ;
     RECT  26.819 27.312 26.963 27.336 ;
     RECT  26.737 5.088 26.993 6.888 ;
     RECT  26.993 5.088 27.101 6.312 ;
     RECT  25.379 32.88 27.253 41.352 ;
     RECT  27.253 32.88 27.277 41.928 ;
     RECT  27.277 32.88 27.301 42.072 ;
     RECT  27.241 7.344 27.308 7.368 ;
     RECT  27.101 5.088 27.313 5.112 ;
     RECT  26.819 28.464 27.347 28.872 ;
     RECT  26.449 9.504 27.349 9.528 ;
     RECT  26.557 13.056 27.349 13.08 ;
     RECT  26.381 14.592 27.349 15.816 ;
     RECT  26.489 17.856 27.349 17.88 ;
     RECT  27.301 32.88 27.361 42.792 ;
     RECT  27.313 4.128 27.385 5.112 ;
     RECT  27.361 42.768 27.389 42.792 ;
     RECT  27.308 7.344 27.491 7.8 ;
     RECT  26.233 46.704 27.493 48.264 ;
     RECT  27.349 9.504 27.497 10.2 ;
     RECT  27.349 13.056 27.529 15.816 ;
     RECT  27.349 17.04 27.529 17.88 ;
     RECT  27.529 13.056 27.539 17.88 ;
     RECT  26.579 31.68 27.565 31.704 ;
     RECT  27.361 32.88 27.565 41.352 ;
     RECT  26.665 11.52 27.589 11.736 ;
     RECT  27.589 11.52 27.605 11.976 ;
     RECT  26.917 19.008 27.635 26.28 ;
     RECT  26.773 44.832 27.709 45.672 ;
     RECT  27.493 46.704 27.709 48.84 ;
     RECT  27.539 14.592 27.821 17.88 ;
     RECT  27.605 11.952 27.827 11.976 ;
     RECT  26.857 30.144 27.961 30.648 ;
     RECT  27.709 44.832 27.961 49.128 ;
     RECT  27.101 6.288 28.001 6.312 ;
     RECT  27.821 17.856 28.021 17.88 ;
     RECT  27.635 19.008 28.021 25.464 ;
     RECT  27.385 3.936 28.285 5.112 ;
     RECT  28.213 26.448 28.389 26.472 ;
     RECT  27.497 9.696 28.393 10.2 ;
     RECT  27.961 30.144 28.393 30.696 ;
     RECT  27.565 31.68 28.393 41.352 ;
     RECT  28.393 9.696 28.537 10.68 ;
     RECT  27.539 13.056 28.645 13.08 ;
     RECT  27.821 14.592 28.645 16.776 ;
     RECT  28.393 30.144 28.681 41.352 ;
     RECT  28.645 13.056 28.789 16.776 ;
     RECT  28.021 17.856 28.789 25.464 ;
     RECT  27.781 60.384 28.789 60.408 ;
     RECT  28.537 8.736 28.892 10.68 ;
     RECT  27.347 28.512 28.897 28.872 ;
     RECT  28.681 30 28.897 41.352 ;
     RECT  28.897 28.512 28.933 41.352 ;
     RECT  28.321 53.04 29.18 53.064 ;
     RECT  29.173 26.592 29.221 26.616 ;
     RECT  28.789 60 29.221 60.408 ;
     RECT  28.933 28.512 29.329 41.736 ;
     RECT  27.961 44.832 29.365 49.224 ;
     RECT  28.285 3.744 29.408 5.112 ;
     RECT  29.149 6.24 29.408 6.264 ;
     RECT  27.491 7.344 29.408 7.416 ;
     RECT  28.892 8.496 29.408 10.68 ;
     RECT  28.789 11.952 29.408 11.976 ;
     RECT  28.789 13.056 29.408 25.464 ;
     RECT  29.221 26.592 29.408 27.144 ;
     RECT  29.329 28.512 29.408 42.504 ;
     RECT  29.365 44.832 29.408 49.416 ;
     RECT  29.18 52.992 29.408 53.064 ;
     RECT  28.753 56.976 29.408 57 ;
     RECT  29.221 58.944 29.408 60.408 ;
     RECT  29.408 2.148 29.512 42.504 ;
     RECT  29.408 44.832 29.512 84.252 ;
     RECT  29.512 28.512 29.617 42.504 ;
     RECT  29.512 44.832 29.653 49.416 ;
     RECT  29.512 2.418 29.704 27.144 ;
     RECT  29.512 58.944 29.704 83.982 ;
     RECT  29.617 28.512 29.729 42.888 ;
     RECT  29.704 9.504 29.765 27.144 ;
     RECT  29.765 11.328 29.801 27.144 ;
     RECT  29.729 28.848 29.869 42.888 ;
     RECT  29.765 9.504 29.873 10.248 ;
     RECT  29.704 3.312 29.891 5.064 ;
     RECT  29.873 9.504 29.891 9.528 ;
     RECT  29.704 6.528 29.909 7.368 ;
     RECT  29.801 19.392 29.945 27.144 ;
     RECT  29.869 28.848 30.013 42.984 ;
     RECT  29.653 44.496 30.049 49.416 ;
     RECT  30.049 44.4 30.085 49.416 ;
     RECT  30.013 28.848 30.121 43.176 ;
     RECT  30.085 44.208 30.121 49.416 ;
     RECT  29.891 3.312 30.197 4.536 ;
     RECT  29.801 11.328 30.227 18.216 ;
     RECT  30.227 11.328 30.233 13.656 ;
     RECT  30.197 4.128 30.413 4.536 ;
     RECT  30.121 28.848 30.589 49.416 ;
     RECT  29.945 24.48 30.709 27.144 ;
     RECT  29.909 6.528 30.737 6.936 ;
     RECT  30.737 6.864 30.773 6.936 ;
     RECT  29.704 8.448 30.773 8.52 ;
     RECT  30.233 11.328 30.805 13.56 ;
     RECT  30.227 14.64 30.805 18.216 ;
     RECT  29.945 19.392 30.805 23.352 ;
     RECT  30.709 24.48 31.004 27.624 ;
     RECT  30.956 7.248 31.043 7.272 ;
     RECT  31.004 24.336 31.093 27.624 ;
     RECT  30.589 28.848 31.093 49.8 ;
     RECT  30.805 14.64 31.129 23.352 ;
     RECT  31.093 24.336 31.129 49.8 ;
     RECT  30.805 10.56 31.196 13.56 ;
     RECT  31.129 14.64 31.196 49.8 ;
     RECT  30.413 4.224 31.205 4.536 ;
     RECT  31.196 10.56 31.277 49.8 ;
     RECT  31.277 12.384 31.283 49.8 ;
     RECT  31.283 12.384 31.349 23.976 ;
     RECT  31.165 7.392 31.477 7.416 ;
     RECT  31.205 4.464 31.523 4.536 ;
     RECT  31.349 16.08 31.529 23.976 ;
     RECT  31.477 7.392 31.564 7.896 ;
     RECT  31.277 10.56 31.601 11.4 ;
     RECT  31.283 25.248 31.608 49.8 ;
     RECT  29.512 53.04 31.608 53.064 ;
     RECT  31.523 4.464 31.925 4.488 ;
     RECT  30.997 9.024 31.957 9.048 ;
     RECT  31.957 9.024 31.993 9.096 ;
     RECT  31.529 21.984 32.003 23.976 ;
     RECT  31.349 12.384 32.177 14.952 ;
     RECT  32.003 21.984 32.213 23.16 ;
     RECT  31.564 7.392 32.243 7.416 ;
     RECT  31.993 8.832 32.243 9.096 ;
     RECT  32.177 12.528 32.389 14.952 ;
     RECT  31.529 16.08 32.389 20.232 ;
     RECT  32.213 21.984 32.483 23.016 ;
     RECT  32.425 6.24 32.509 6.264 ;
     RECT  32.389 12.528 32.723 20.232 ;
     RECT  32.243 8.928 32.929 9.096 ;
     RECT  31.601 11.376 33.001 11.4 ;
     RECT  32.929 8.928 33.013 9.672 ;
     RECT  33.001 10.896 33.013 11.4 ;
     RECT  31.608 25.248 33.037 57.816 ;
     RECT  33.013 8.928 33.1 11.4 ;
     RECT  32.723 12.816 33.107 20.232 ;
     RECT  33.1 9.648 33.113 11.4 ;
     RECT  33.113 11.136 33.164 11.4 ;
     RECT  33.107 19.104 33.181 20.232 ;
     RECT  33.181 19.104 33.212 20.952 ;
     RECT  32.483 21.984 33.212 22.824 ;
     RECT  33.013 4.512 33.221 4.536 ;
     RECT  33.212 19.104 33.299 22.824 ;
     RECT  33.107 12.816 33.329 17.88 ;
     RECT  33.299 19.104 33.329 20.952 ;
     RECT  33.299 21.984 33.329 22.824 ;
     RECT  33.037 24.576 33.347 57.816 ;
     RECT  33.397 5.664 33.539 5.688 ;
     RECT  33.301 7.392 33.581 7.416 ;
     RECT  33.329 19.104 33.617 20.232 ;
     RECT  33.329 12.96 33.779 17.88 ;
     RECT  33.617 19.104 33.825 20.136 ;
     RECT  33.164 11.136 33.829 11.544 ;
     RECT  33.113 9.648 34.261 10.008 ;
     RECT  33.347 25.248 34.333 57.816 ;
     RECT  33.329 21.984 34.357 22.536 ;
     RECT  33.829 11.136 34.405 11.688 ;
     RECT  33.779 12.96 34.405 15.864 ;
     RECT  34.357 21.984 34.508 23.16 ;
     RECT  34.333 24.528 34.657 57.816 ;
     RECT  33.884 6.24 34.808 6.264 ;
     RECT  34.261 9.6 34.808 10.008 ;
     RECT  34.405 11.136 34.808 15.864 ;
     RECT  33.779 16.848 34.808 17.88 ;
     RECT  33.825 19.296 34.808 20.136 ;
     RECT  34.508 21.6 34.808 23.16 ;
     RECT  34.657 24.48 34.808 57.816 ;
     RECT  29.704 58.944 34.808 60.408 ;
     RECT  30.997 62.448 34.808 62.472 ;
     RECT  34.808 2.148 34.912 57.816 ;
     RECT  34.808 58.944 34.912 84.252 ;
     RECT  34.912 2.418 35.104 57.816 ;
     RECT  34.912 58.944 35.104 83.982 ;
     RECT  35.104 10.848 35.201 15.768 ;
     RECT  35.104 7.92 35.219 9.672 ;
     RECT  35.201 10.848 35.267 15.096 ;
     RECT  35.267 10.848 35.273 12.264 ;
     RECT  35.267 13.488 35.273 15.096 ;
     RECT  35.104 17.088 35.273 22.872 ;
     RECT  35.219 7.968 35.309 9.672 ;
     RECT  35.273 11.184 35.315 12.264 ;
     RECT  35.273 13.488 35.328 14.904 ;
     RECT  35.315 12.048 35.597 12.072 ;
     RECT  35.309 7.968 35.713 8.376 ;
     RECT  35.713 8.352 35.747 8.376 ;
     RECT  35.309 9.648 35.747 9.672 ;
     RECT  35.273 17.472 35.777 22.872 ;
     RECT  35.777 17.568 35.891 22.872 ;
     RECT  35.104 23.952 35.929 57.816 ;
     RECT  35.891 20.736 36.029 22.872 ;
     RECT  35.104 4.512 36.137 4.536 ;
     RECT  36.241 13.056 36.277 13.08 ;
     RECT  36.029 21.984 36.461 22.872 ;
     RECT  36.277 12.336 36.611 13.08 ;
     RECT  36.029 20.736 36.659 20.76 ;
     RECT  36.611 12.768 36.709 13.08 ;
     RECT  35.328 14.112 36.709 14.904 ;
     RECT  36.565 11.28 36.713 11.304 ;
     RECT  36.637 6.816 36.721 6.84 ;
     RECT  35.891 17.568 37.037 19.608 ;
     RECT  36.461 21.984 37.141 22.632 ;
     RECT  36.709 12.768 37.189 14.904 ;
     RECT  36.853 15.984 37.189 16.008 ;
     RECT  37.037 17.568 37.189 19.512 ;
     RECT  37.177 7.968 37.261 7.992 ;
     RECT  36.817 6.96 37.325 6.984 ;
     RECT  37.285 10.032 37.357 10.056 ;
     RECT  37.189 12.768 37.361 16.008 ;
     RECT  37.285 5.088 37.369 5.112 ;
     RECT  37.361 12.96 37.393 16.008 ;
     RECT  37.189 17.088 37.393 19.512 ;
     RECT  37.357 9.648 37.427 10.056 ;
     RECT  37.393 12.96 37.427 19.512 ;
     RECT  37.427 13.056 37.619 19.512 ;
     RECT  37.141 21.6 37.621 22.632 ;
     RECT  37.621 21.6 37.757 23.4 ;
     RECT  37.619 15.12 37.937 19.512 ;
     RECT  37.757 21.6 38.009 22.632 ;
     RECT  37.937 15.696 38.153 19.512 ;
     RECT  38.077 20.592 38.257 20.616 ;
     RECT  38.009 21.6 38.257 22.536 ;
     RECT  37.619 13.056 38.657 13.656 ;
     RECT  38.657 13.056 38.689 13.512 ;
     RECT  37.427 9.648 38.723 9.672 ;
     RECT  38.257 20.592 38.725 22.536 ;
     RECT  38.437 11.664 38.764 11.688 ;
     RECT  38.725 20.544 38.801 22.536 ;
     RECT  38.801 20.544 38.867 21.432 ;
     RECT  38.153 15.696 38.972 16.008 ;
     RECT  38.972 15.408 39.013 16.008 ;
     RECT  39.013 14.496 39.059 16.008 ;
     RECT  38.153 17.088 39.059 19.512 ;
     RECT  39.059 17.328 39.121 19.512 ;
     RECT  38.867 20.544 39.121 20.616 ;
     RECT  39.121 17.328 39.241 20.616 ;
     RECT  38.801 22.512 39.404 22.536 ;
     RECT  39.059 15.696 39.409 16.008 ;
     RECT  38.689 12.72 39.769 13.512 ;
     RECT  39.059 14.496 39.769 14.664 ;
     RECT  39.241 19.296 39.836 20.616 ;
     RECT  39.769 12.72 39.841 14.664 ;
     RECT  39.841 12.528 40.021 14.664 ;
     RECT  40.021 12.048 40.208 14.664 ;
     RECT  39.409 15.696 40.208 16.296 ;
     RECT  39.241 17.328 40.208 17.976 ;
     RECT  39.836 19.296 40.208 21.384 ;
     RECT  39.404 22.512 40.208 23.16 ;
     RECT  35.929 24.432 40.208 57.816 ;
     RECT  35.104 58.944 40.208 60.408 ;
     RECT  35.104 62.448 40.208 62.472 ;
     RECT  40.208 2.148 40.312 57.816 ;
     RECT  40.208 58.944 40.312 84.252 ;
     RECT  40.312 2.418 40.504 57.816 ;
     RECT  40.312 58.944 40.504 83.982 ;
     RECT  40.504 10.752 40.637 16.584 ;
     RECT  40.504 17.616 40.643 17.976 ;
     RECT  40.637 10.752 40.883 11.976 ;
     RECT  40.504 24.528 41.113 57.816 ;
     RECT  40.883 11.28 41.213 11.544 ;
     RECT  40.637 13.44 41.219 16.584 ;
     RECT  40.504 5.616 41.308 5.64 ;
     RECT  40.504 19.2 41.315 20.088 ;
     RECT  41.213 11.28 41.363 11.496 ;
     RECT  40.504 21.12 41.411 22.536 ;
     RECT  41.411 22.512 41.557 22.536 ;
     RECT  41.468 4.272 41.605 4.296 ;
     RECT  41.219 13.824 41.857 16.584 ;
     RECT  40.643 17.952 41.857 17.976 ;
     RECT  41.557 22.512 41.897 22.728 ;
     RECT  41.564 6.768 41.987 6.792 ;
     RECT  41.363 11.28 41.987 11.448 ;
     RECT  41.605 3.408 42.005 4.296 ;
     RECT  41.113 25.248 42.109 57.816 ;
     RECT  41.497 0.096 42.145 0.12 ;
     RECT  41.965 1.104 42.145 1.128 ;
     RECT  42.005 3.888 42.325 4.296 ;
     RECT  41.509 5.376 42.325 5.544 ;
     RECT  42.145 6.528 42.325 6.552 ;
     RECT  41.315 19.2 42.373 19.272 ;
     RECT  41.857 13.824 42.421 17.976 ;
     RECT  41.411 21.12 42.433 21.144 ;
     RECT  41.897 22.512 42.433 22.536 ;
     RECT  42.181 2.88 42.437 2.904 ;
     RECT  42.373 18.96 42.46 19.272 ;
     RECT  42.433 21.12 42.469 22.536 ;
     RECT  42.46 19.248 42.581 19.272 ;
     RECT  42.469 20.832 42.581 22.536 ;
     RECT  42.109 25.104 42.649 57.816 ;
     RECT  42.541 8.4 42.659 8.424 ;
     RECT  42.505 12.528 42.661 12.552 ;
     RECT  42.581 20.832 42.755 20.856 ;
     RECT  42.145 0.096 42.853 1.128 ;
     RECT  42.421 13.776 42.905 17.976 ;
     RECT  42.325 3.888 42.973 6.552 ;
     RECT  42.661 12.384 42.977 12.552 ;
     RECT  42.428 10.512 43.1 10.536 ;
     RECT  43.1 10.512 43.117 10.776 ;
     RECT  43.117 10.128 43.141 10.776 ;
     RECT  43.141 10.128 43.153 11.208 ;
     RECT  42.973 3.648 43.187 6.552 ;
     RECT  42.649 24.528 43.201 57.816 ;
     RECT  43.187 5.088 43.253 6.552 ;
     RECT  42.905 17.088 43.301 17.976 ;
     RECT  43.153 10.128 43.331 11.496 ;
     RECT  43.253 5.088 43.337 7.416 ;
     RECT  42.973 8.928 43.397 8.952 ;
     RECT  43.331 10.128 43.397 11.4 ;
     RECT  43.301 17.76 43.436 17.976 ;
     RECT  43.436 17.76 43.441 18.168 ;
     RECT  43.397 8.928 43.481 11.4 ;
     RECT  43.481 9.936 43.523 11.4 ;
     RECT  42.905 13.776 43.532 15.912 ;
     RECT  42.853 0.096 43.58 1.176 ;
     RECT  43.532 13.008 43.619 15.912 ;
     RECT  43.441 17.76 43.619 18.792 ;
     RECT  43.58 0.096 43.667 1.704 ;
     RECT  43.187 3.648 43.685 3.912 ;
     RECT  43.436 20.448 43.765 20.472 ;
     RECT  43.685 2.88 43.769 3.912 ;
     RECT  43.337 5.088 43.811 6.888 ;
     RECT  43.481 8.928 43.811 8.952 ;
     RECT  43.765 20.016 44.012 20.472 ;
     RECT  43.811 6.768 44.093 6.888 ;
     RECT  43.523 10.128 44.093 11.4 ;
     RECT  44.012 20.016 44.099 20.568 ;
     RECT  44.093 10.128 44.129 10.536 ;
     RECT  43.811 5.088 44.147 5.64 ;
     RECT  44.089 7.968 44.173 8.856 ;
     RECT  42.581 22.224 44.377 22.536 ;
     RECT  43.201 25.248 44.377 57.816 ;
     RECT  44.129 10.128 44.435 10.488 ;
     RECT  43.619 13.248 44.435 15.912 ;
     RECT  44.099 20.016 44.435 20.184 ;
     RECT  44.435 10.128 44.489 10.152 ;
     RECT  44.435 13.824 44.533 15.912 ;
     RECT  44.377 25.104 44.588 57.816 ;
     RECT  43.769 3.36 44.605 3.912 ;
     RECT  43.619 17.76 44.629 18.744 ;
     RECT  44.605 3.888 44.701 3.912 ;
     RECT  44.147 5.088 44.701 5.4 ;
     RECT  43.667 0.096 44.773 1.176 ;
     RECT  44.173 8.544 44.773 8.856 ;
     RECT  44.773 0.096 44.777 1.752 ;
     RECT  44.588 24.336 44.845 57.816 ;
     RECT  44.533 13.824 44.876 15.96 ;
     RECT  44.629 17.472 44.876 18.744 ;
     RECT  44.777 0.096 44.885 0.168 ;
     RECT  44.876 13.824 44.989 18.744 ;
     RECT  44.845 23.856 45.445 57.816 ;
     RECT  44.989 13.824 45.452 18.792 ;
     RECT  44.377 21.888 45.457 22.536 ;
     RECT  45.445 23.712 45.457 57.816 ;
     RECT  44.093 6.768 45.493 6.84 ;
     RECT  44.777 1.152 45.608 1.752 ;
     RECT  45.061 2.88 45.608 2.904 ;
     RECT  44.701 3.888 45.608 5.4 ;
     RECT  45.493 6.768 45.608 7.416 ;
     RECT  44.773 8.544 45.608 9.576 ;
     RECT  44.701 11.904 45.608 11.928 ;
     RECT  45.452 13.536 45.608 18.792 ;
     RECT  44.435 20.16 45.608 20.184 ;
     RECT  45.457 21.888 45.608 57.816 ;
     RECT  40.504 58.944 45.608 60.408 ;
     RECT  40.504 62.448 45.608 62.472 ;
     RECT  45.608 58.944 45.712 84.252 ;
     RECT  45.608 1.152 45.785 57.816 ;
     RECT  45.785 1.728 45.904 57.816 ;
     RECT  45.712 58.944 45.904 83.982 ;
     RECT  45.904 13.632 46.001 19.416 ;
     RECT  45.904 11.52 46.019 12.6 ;
     RECT  46.001 17.52 46.019 19.416 ;
     RECT  45.904 1.728 46.037 1.752 ;
     RECT  45.904 23.952 46.037 23.976 ;
     RECT  45.904 2.832 46.109 3.384 ;
     RECT  44.885 0.144 46.325 0.168 ;
     RECT  45.904 4.848 46.451 5.256 ;
     RECT  46.019 11.52 46.451 12.552 ;
     RECT  45.904 21.936 46.541 22.824 ;
     RECT  46.019 17.52 46.577 18.84 ;
     RECT  46.541 22.8 46.613 22.824 ;
     RECT  45.904 9.456 46.793 9.48 ;
     RECT  46.451 11.952 46.829 12.552 ;
     RECT  46.451 4.848 46.835 4.872 ;
     RECT  45.904 20.832 46.835 20.856 ;
     RECT  46.001 13.632 46.937 16.488 ;
     RECT  46.937 16.464 47.113 16.488 ;
     RECT  46.577 17.52 47.113 18.792 ;
     RECT  47.113 16.464 47.219 18.792 ;
     RECT  46.829 12.336 47.437 12.552 ;
     RECT  46.937 13.632 47.437 15.192 ;
     RECT  45.904 25.248 47.501 57.816 ;
     RECT  47.516 8.448 47.603 8.472 ;
     RECT  47.437 12.336 47.603 15.192 ;
     RECT  46.109 3.36 47.612 3.384 ;
     RECT  47.612 3.216 47.699 3.384 ;
     RECT  47.219 16.512 47.737 18.792 ;
     RECT  47.797 10.464 47.869 10.488 ;
     RECT  47.699 3.36 47.891 3.384 ;
     RECT  47.737 17.04 47.891 18.792 ;
     RECT  47.557 7.392 47.901 7.416 ;
     RECT  47.948 23.808 47.977 23.832 ;
     RECT  47.501 25.104 47.977 57.816 ;
     RECT  47.437 19.92 47.989 19.944 ;
     RECT  47.977 23.808 48.035 57.816 ;
     RECT  47.989 22.176 48.089 22.2 ;
     RECT  48.035 24.288 48.131 57.816 ;
     RECT  47.891 17.856 48.181 18.792 ;
     RECT  47.989 19.92 48.181 20.76 ;
     RECT  48.181 17.856 48.275 20.76 ;
     RECT  48.275 19.92 48.297 20.76 ;
     RECT  47.869 10.464 48.301 10.68 ;
     RECT  47.603 12.336 48.301 12.504 ;
     RECT  48.301 10.464 48.323 12.504 ;
     RECT  48.301 8.496 48.385 8.52 ;
     RECT  48.323 10.464 48.469 12.36 ;
     RECT  47.603 13.536 48.485 15.192 ;
     RECT  48.469 10.176 48.593 12.36 ;
     RECT  48.485 13.536 48.665 14.088 ;
     RECT  48.485 15.168 48.764 15.192 ;
     RECT  48.764 15.168 48.851 16.008 ;
     RECT  48.275 17.856 48.851 18.648 ;
     RECT  48.297 19.92 48.851 19.944 ;
     RECT  48.593 10.992 49.061 12.36 ;
     RECT  49.061 10.992 49.313 11.4 ;
     RECT  48.949 16.56 49.349 16.584 ;
     RECT  49.292 22.176 49.379 22.2 ;
     RECT  48.665 14.064 49.705 14.088 ;
     RECT  48.851 15.168 49.813 15.384 ;
     RECT  48.851 17.856 49.964 17.88 ;
     RECT  49.705 14.064 50.108 14.136 ;
     RECT  49.813 15.168 50.108 16.536 ;
     RECT  50.108 14.064 50.389 16.536 ;
     RECT  49.964 17.856 50.425 18.072 ;
     RECT  49.921 23.376 50.485 23.4 ;
     RECT  50.485 22.464 50.533 23.4 ;
     RECT  50.425 17.856 50.641 18.408 ;
     RECT  50.005 19.392 50.641 19.416 ;
     RECT  50.641 17.856 50.732 19.416 ;
     RECT  50.669 20.448 50.732 20.472 ;
     RECT  50.389 13.536 50.773 16.536 ;
     RECT  50.773 13.536 50.78 16.776 ;
     RECT  50.732 17.856 50.78 20.472 ;
     RECT  50.149 12.528 50.869 12.552 ;
     RECT  50.78 13.536 50.869 20.472 ;
     RECT  49.313 10.992 51.008 11.016 ;
     RECT  50.869 12.528 51.008 20.472 ;
     RECT  50.533 22.176 51.008 23.4 ;
     RECT  48.131 25.248 51.008 57.816 ;
     RECT  45.904 58.944 51.008 60.408 ;
     RECT  45.904 62.448 51.008 62.472 ;
     RECT  51.008 2.148 51.112 57.816 ;
     RECT  51.008 58.944 51.112 84.252 ;
     RECT  51.112 2.418 51.304 57.816 ;
     RECT  51.112 58.944 51.304 83.982 ;
     RECT  51.304 14.112 54.709 14.136 ;
     RECT  51.304 15.168 54.709 16.008 ;
     RECT  51.304 13.008 56.408 13.032 ;
     RECT  54.709 14.112 56.408 16.008 ;
     RECT  51.304 17.856 56.408 17.88 ;
     RECT  51.304 25.248 56.408 57.816 ;
     RECT  51.304 58.944 56.408 60.408 ;
     RECT  51.304 62.448 56.408 62.472 ;
     RECT  56.408 2.148 56.512 57.816 ;
     RECT  56.408 58.944 56.512 84.252 ;
     RECT  56.512 2.418 56.704 57.816 ;
     RECT  56.512 58.944 56.704 83.982 ;
     RECT  56.704 14.112 58.163 16.008 ;
     RECT  58.117 13.008 58.204 13.032 ;
     RECT  56.704 25.248 58.997 57.816 ;
     RECT  58.117 10.848 61.808 10.872 ;
     RECT  58.163 14.112 61.808 14.136 ;
     RECT  58.163 15.984 61.808 16.008 ;
     RECT  56.704 17.856 61.808 17.88 ;
     RECT  58.997 25.536 61.808 57.816 ;
     RECT  56.704 58.944 61.808 60.408 ;
     RECT  56.704 62.448 61.808 62.472 ;
     RECT  61.808 2.148 61.912 57.816 ;
     RECT  61.808 58.944 61.912 84.252 ;
     RECT  61.912 2.418 62.104 57.816 ;
     RECT  61.912 58.944 62.104 83.982 ;
     RECT  62.104 15.984 64.321 16.008 ;
     RECT  62.104 17.856 64.643 17.88 ;
     RECT  62.104 10.848 67.208 10.872 ;
     RECT  64.933 12.864 67.208 12.888 ;
     RECT  62.104 14.112 67.208 14.136 ;
     RECT  64.321 15.456 67.208 16.008 ;
     RECT  62.104 25.536 67.208 57.816 ;
     RECT  62.104 58.944 67.208 60.408 ;
     RECT  62.104 62.448 67.208 62.472 ;
     RECT  67.208 2.148 67.312 57.816 ;
     RECT  67.208 58.944 67.312 84.252 ;
     RECT  67.312 2.418 67.504 57.816 ;
     RECT  67.312 58.944 67.504 83.982 ;
     RECT  67.504 15.456 68.915 16.008 ;
     RECT  68.857 10.848 68.941 10.872 ;
     RECT  68.869 6.24 72.608 6.264 ;
     RECT  67.504 13.008 72.608 13.032 ;
     RECT  67.504 14.112 72.608 14.136 ;
     RECT  68.915 15.456 72.608 15.48 ;
     RECT  67.504 25.536 72.608 57.816 ;
     RECT  67.504 58.944 72.608 60.408 ;
     RECT  67.504 62.448 72.608 62.472 ;
     RECT  72.608 2.148 72.712 57.816 ;
     RECT  72.608 58.944 72.712 84.252 ;
     RECT  72.712 2.418 72.904 57.816 ;
     RECT  72.712 58.944 72.904 83.982 ;
     RECT  72.904 6.24 78.008 6.264 ;
     RECT  72.904 13.008 78.008 13.032 ;
     RECT  72.904 14.112 78.008 14.136 ;
     RECT  72.904 15.456 78.008 15.48 ;
     RECT  72.904 25.536 78.008 57.816 ;
     RECT  72.904 58.944 78.008 60.408 ;
     RECT  72.904 62.448 78.008 62.472 ;
     RECT  78.008 2.148 78.112 57.816 ;
     RECT  78.008 58.944 78.112 84.252 ;
     RECT  78.112 2.418 78.304 57.816 ;
     RECT  78.112 58.944 78.304 83.982 ;
     RECT  78.304 13.008 82.249 13.032 ;
     RECT  82.249 12.768 82.549 13.032 ;
     RECT  78.304 6.24 82.645 6.264 ;
     RECT  83.173 3.984 83.293 4.008 ;
     RECT  82.645 6.048 83.293 6.264 ;
     RECT  83.141 2.832 83.408 2.856 ;
     RECT  83.293 3.888 83.408 4.008 ;
     RECT  83.293 5.472 83.408 6.264 ;
     RECT  82.549 11.952 83.408 13.032 ;
     RECT  78.304 14.112 83.408 14.136 ;
     RECT  78.304 15.456 83.408 15.48 ;
     RECT  78.304 25.536 83.408 57.816 ;
     RECT  78.304 58.944 83.408 60.408 ;
     RECT  78.304 62.448 83.408 62.472 ;
     RECT  83.408 58.944 83.512 84.252 ;
     RECT  82.861 0.144 83.653 0.168 ;
     RECT  83.408 2.148 83.704 57.816 ;
     RECT  83.512 58.944 83.704 83.982 ;
     RECT  83.653 0.096 83.761 0.168 ;
     RECT  83.761 0.096 83.905 0.216 ;
     RECT  83.725 1.728 83.905 1.8 ;
     RECT  83.704 2.88 84.377 7.08 ;
     RECT  84.377 2.88 84.413 4.536 ;
     RECT  84.413 4.464 84.521 4.536 ;
     RECT  83.905 0.096 84.659 1.8 ;
     RECT  84.413 2.88 84.701 3.24 ;
     RECT  84.659 0.096 84.953 1.752 ;
     RECT  84.953 0.096 85.139 0.6 ;
     RECT  84.521 4.512 85.379 4.536 ;
     RECT  84.377 5.712 85.417 7.08 ;
     RECT  85.417 4.896 85.493 7.08 ;
     RECT  85.139 0.576 85.523 0.6 ;
     RECT  84.953 1.728 85.644 1.752 ;
     RECT  84.701 2.88 86.053 2.952 ;
     RECT  86.053 2.88 86.069 3.864 ;
     RECT  86.069 2.928 86.14 3.864 ;
     RECT  85.644 1.728 86.437 1.8 ;
     RECT  86.437 1.728 86.533 1.848 ;
     RECT  85.493 4.896 86.609 6.936 ;
     RECT  86.533 1.152 86.717 1.848 ;
     RECT  86.609 4.896 86.893 6.264 ;
     RECT  86.149 0.096 87.005 0.12 ;
     RECT  86.14 2.928 87.205 2.952 ;
     RECT  86.893 4.512 87.205 6.264 ;
     RECT  87.205 2.928 87.221 6.264 ;
     RECT  86.717 1.2 87.257 1.848 ;
     RECT  87.257 1.2 87.329 1.8 ;
     RECT  87.221 2.928 87.493 6.168 ;
     RECT  87.493 2.832 87.509 6.168 ;
     RECT  87.329 1.776 87.545 1.8 ;
     RECT  87.509 6.144 87.653 6.168 ;
     RECT  87.509 2.832 88.693 5.16 ;
     RECT  88.693 2.832 88.808 5.688 ;
     RECT  83.704 11.952 88.808 13.032 ;
     RECT  83.704 15.456 88.808 15.48 ;
     RECT  88.693 19.008 88.808 19.032 ;
     RECT  83.704 25.536 88.808 57.816 ;
     RECT  83.704 58.944 88.808 60.408 ;
     RECT  83.704 62.448 88.808 62.472 ;
     RECT  88.808 2.148 88.912 57.816 ;
     RECT  88.808 58.944 88.912 84.252 ;
     RECT  88.912 2.418 89.104 57.816 ;
     RECT  88.912 58.944 89.104 83.982 ;
     RECT  89.104 19.008 89.201 19.128 ;
     RECT  89.104 4.704 94.208 4.728 ;
     RECT  89.104 11.952 94.208 13.032 ;
     RECT  89.104 15.456 94.208 15.48 ;
     RECT  89.201 19.104 94.208 19.128 ;
     RECT  89.104 25.536 94.208 57.816 ;
     RECT  89.104 58.944 94.208 60.408 ;
     RECT  89.104 62.448 94.208 62.472 ;
     RECT  94.208 2.148 94.312 57.816 ;
     RECT  94.208 58.944 94.312 84.252 ;
     RECT  94.312 2.418 94.504 57.816 ;
     RECT  94.312 58.944 94.504 83.982 ;
     RECT  94.504 25.536 96.145 57.816 ;
     RECT  94.504 4.704 99.608 4.728 ;
     RECT  94.504 11.952 99.608 13.032 ;
     RECT  94.504 15.456 99.608 15.48 ;
     RECT  94.504 19.104 99.608 19.128 ;
     RECT  96.145 25.248 99.608 57.816 ;
     RECT  94.504 58.944 99.608 60.408 ;
     RECT  94.504 62.448 99.608 62.472 ;
     RECT  99.608 2.148 99.712 57.816 ;
     RECT  99.608 58.944 99.712 84.252 ;
     RECT  99.712 2.418 99.904 57.816 ;
     RECT  99.712 58.944 99.904 83.982 ;
     RECT  101.977 8.16 103.484 8.184 ;
     RECT  99.904 4.704 103.571 4.728 ;
     RECT  103.484 8.16 103.571 8.376 ;
     RECT  103.571 8.16 105.008 8.184 ;
     RECT  103.525 9.888 105.008 9.912 ;
     RECT  99.904 11.952 105.008 13.032 ;
     RECT  99.904 15.456 105.008 15.48 ;
     RECT  99.904 19.104 105.008 19.128 ;
     RECT  99.904 25.248 105.008 57.816 ;
     RECT  99.904 58.944 105.008 60.408 ;
     RECT  99.904 62.448 105.008 62.472 ;
     RECT  105.008 2.148 105.112 57.816 ;
     RECT  105.008 58.944 105.112 84.252 ;
     RECT  105.112 2.418 105.304 57.816 ;
     RECT  105.112 58.944 105.304 83.982 ;
     RECT  105.304 9.888 105.401 10.056 ;
     RECT  105.401 10.032 106.405 10.056 ;
     RECT  105.304 8.16 107.795 8.184 ;
     RECT  105.304 11.952 107.989 13.032 ;
     RECT  107.989 11.952 108.749 13.176 ;
     RECT  108.673 0.576 108.781 0.6 ;
     RECT  108.781 0.576 109.139 0.648 ;
     RECT  108.565 1.68 109.141 1.704 ;
     RECT  106.405 10.032 109.141 10.632 ;
     RECT  105.304 19.104 109.141 19.128 ;
     RECT  109.069 17.28 109.187 17.304 ;
     RECT  109.141 19.104 109.253 19.8 ;
     RECT  108.853 6.24 109.321 6.264 ;
     RECT  109.139 0.624 109.331 0.648 ;
     RECT  108.997 2.88 109.427 2.904 ;
     RECT  109.249 3.984 109.532 4.008 ;
     RECT  109.321 5.664 109.532 6.264 ;
     RECT  109.532 3.984 109.573 6.264 ;
     RECT  109.141 1.68 109.637 1.752 ;
     RECT  109.141 10.032 109.681 10.824 ;
     RECT  108.749 11.952 109.681 11.976 ;
     RECT  109.573 3.984 109.925 6.312 ;
     RECT  109.637 1.68 109.957 1.8 ;
     RECT  105.304 15.456 110.06 15.48 ;
     RECT  110.06 15.456 110.077 16.44 ;
     RECT  109.681 10.032 110.101 11.976 ;
     RECT  110.101 9.744 110.149 11.976 ;
     RECT  108.749 13.056 110.149 13.176 ;
     RECT  109.957 1.152 110.153 1.8 ;
     RECT  110.153 1.632 110.195 1.8 ;
     RECT  109.253 19.104 110.252 19.128 ;
     RECT  110.077 15.408 110.293 16.44 ;
     RECT  110.195 1.68 110.365 1.8 ;
     RECT  110.293 2.832 110.365 2.856 ;
     RECT  110.149 9.744 110.401 13.176 ;
     RECT  110.255 14.208 110.401 14.232 ;
     RECT  110.365 1.68 110.408 2.856 ;
     RECT  109.925 3.984 110.408 6.36 ;
     RECT  110.401 9.744 110.408 14.232 ;
     RECT  110.293 15.408 110.408 17.208 ;
     RECT  110.252 19.104 110.408 19.992 ;
     RECT  109.825 21.648 110.408 21.672 ;
     RECT  105.304 25.248 110.408 57.816 ;
     RECT  105.304 58.944 110.408 60.408 ;
     RECT  105.304 62.448 110.408 62.472 ;
     RECT  110.408 58.944 110.512 84.252 ;
     RECT  110.437 0.096 110.629 0.12 ;
     RECT  110.408 1.68 110.704 57.816 ;
     RECT  110.512 58.944 110.704 83.982 ;
     RECT  110.629 0.096 110.819 0.168 ;
     RECT  110.704 10.32 110.881 23.4 ;
     RECT  110.881 15.456 110.981 23.4 ;
     RECT  110.704 2.832 111.011 7.8 ;
     RECT  110.881 10.32 111.011 14.232 ;
     RECT  111.011 10.992 111.233 14.232 ;
     RECT  111.011 7.344 111.299 7.8 ;
     RECT  110.981 15.456 111.491 21.144 ;
     RECT  110.981 22.704 111.491 23.4 ;
     RECT  111.491 23.376 111.529 23.4 ;
     RECT  111.491 15.456 111.565 19.992 ;
     RECT  111.565 15.456 111.628 17.304 ;
     RECT  111.628 15.456 111.683 16.776 ;
     RECT  111.233 10.992 111.729 13.704 ;
     RECT  111.491 21.12 111.737 21.144 ;
     RECT  110.704 1.68 111.781 1.848 ;
     RECT  111.011 2.832 111.781 6.312 ;
     RECT  111.565 18.816 111.809 19.992 ;
     RECT  111.781 1.68 111.877 6.312 ;
     RECT  111.829 9.072 111.98 9.096 ;
     RECT  111.98 9.072 112.067 9.768 ;
     RECT  111.729 10.992 112.093 11.928 ;
     RECT  111.877 1.152 112.097 6.312 ;
     RECT  112.097 1.152 112.169 6.264 ;
     RECT  111.729 13.008 112.261 13.704 ;
     RECT  111.299 7.344 112.309 7.416 ;
     RECT  110.819 0.096 112.313 0.12 ;
     RECT  112.309 7.344 112.381 7.608 ;
     RECT  112.093 10.848 112.489 11.928 ;
     RECT  112.453 22.8 112.537 22.824 ;
     RECT  112.261 13.008 112.549 13.896 ;
     RECT  111.683 15.456 112.549 16.488 ;
     RECT  112.561 21.744 112.597 21.768 ;
     RECT  112.597 21.744 112.709 22.248 ;
     RECT  112.169 1.152 112.745 1.176 ;
     RECT  112.381 7.344 112.892 7.992 ;
     RECT  112.549 13.008 112.925 16.488 ;
     RECT  111.809 18.816 112.993 19.128 ;
     RECT  112.489 10.224 113.029 11.928 ;
     RECT  112.925 13.008 113.029 15.624 ;
     RECT  112.892 7.248 113.065 7.992 ;
     RECT  112.067 9.072 113.065 9.096 ;
     RECT  113.065 7.248 113.105 9.096 ;
     RECT  113.105 7.968 113.149 9.096 ;
     RECT  112.169 2.208 113.213 6.264 ;
     RECT  113.029 10.224 113.221 15.624 ;
     RECT  113.213 2.64 113.237 6.264 ;
     RECT  113.221 9.168 113.308 15.624 ;
     RECT  113.237 2.64 113.315 6.888 ;
     RECT  113.149 7.968 113.315 8.136 ;
     RECT  113.315 6.864 113.321 6.888 ;
     RECT  113.315 2.64 113.617 5.688 ;
     RECT  113.461 21.072 113.653 21.096 ;
     RECT  112.993 18.24 113.749 19.128 ;
     RECT  112.709 22.224 113.929 22.248 ;
     RECT  113.308 10.224 113.965 15.624 ;
     RECT  113.281 16.656 113.965 16.728 ;
     RECT  113.749 18.192 113.965 19.128 ;
     RECT  113.308 9.168 113.969 9.192 ;
     RECT  113.653 20.592 114.041 21.096 ;
     RECT  113.965 10.224 114.073 19.128 ;
     RECT  113.617 2.64 114.113 5.352 ;
     RECT  114.073 10.224 114.325 20.136 ;
     RECT  114.325 9.648 114.329 20.136 ;
     RECT  114.289 6.816 114.373 6.84 ;
     RECT  113.315 7.968 114.397 7.992 ;
     RECT  113.929 22.224 114.397 22.824 ;
     RECT  114.329 10.704 114.515 20.136 ;
     RECT  114.397 21.168 114.541 22.824 ;
     RECT  113.425 23.952 114.545 23.976 ;
     RECT  114.541 21.168 114.581 22.872 ;
     RECT  114.113 4.416 114.653 5.352 ;
     RECT  114.653 4.416 114.689 5.256 ;
     RECT  114.397 7.776 114.689 7.992 ;
     RECT  114.329 9.648 114.689 9.672 ;
     RECT  114.113 3.168 115.225 3.336 ;
     RECT  114.515 15.024 115.657 20.136 ;
     RECT  114.515 10.704 115.729 13.944 ;
     RECT  115.657 14.928 115.729 20.136 ;
     RECT  115.225 3.12 115.808 3.336 ;
     RECT  114.689 4.464 115.808 5.256 ;
     RECT  115.693 6.864 115.808 6.888 ;
     RECT  114.793 8.256 115.808 8.28 ;
     RECT  115.729 10.704 115.808 20.136 ;
     RECT  114.581 21.552 115.808 22.872 ;
     RECT  110.704 25.248 115.808 57.816 ;
     RECT  110.704 58.944 115.808 60.408 ;
     RECT  110.704 62.448 115.808 62.472 ;
     RECT  115.808 2.148 115.912 57.816 ;
     RECT  115.808 58.944 115.912 84.252 ;
     RECT  115.912 2.418 116.104 57.816 ;
     RECT  115.912 58.944 116.104 83.982 ;
     RECT  116.104 6.864 116.243 9 ;
     RECT  116.243 7.152 116.579 8.904 ;
     RECT  116.104 10.176 117.133 10.728 ;
     RECT  116.104 11.76 117.133 19.368 ;
     RECT  116.104 21.12 117.133 21.192 ;
     RECT  116.104 25.248 117.205 57.816 ;
     RECT  116.579 7.152 117.241 8.76 ;
     RECT  117.133 10.176 117.281 21.192 ;
     RECT  116.104 3.12 117.313 5.256 ;
     RECT  117.281 10.56 117.317 21.192 ;
     RECT  117.317 20.736 117.347 21.192 ;
     RECT  117.205 24.336 117.347 57.816 ;
     RECT  117.241 7.056 117.385 8.76 ;
     RECT  117.313 3.12 117.637 5.544 ;
     RECT  117.385 6.528 117.637 8.76 ;
     RECT  117.347 21.168 117.637 21.192 ;
     RECT  116.104 22.176 117.637 23.064 ;
     RECT  117.637 21.168 117.641 23.064 ;
     RECT  117.317 10.56 117.713 19.368 ;
     RECT  117.713 10.56 118.037 17.688 ;
     RECT  117.641 21.168 118.309 22.2 ;
     RECT  118.037 17.04 118.369 17.688 ;
     RECT  118.213 0.576 118.429 0.6 ;
     RECT  118.037 10.56 118.433 16.008 ;
     RECT  118.309 20.544 118.469 22.2 ;
     RECT  117.637 3.12 118.501 8.76 ;
     RECT  117.845 23.376 118.573 23.4 ;
     RECT  118.369 17.472 118.7 17.688 ;
     RECT  117.713 18.816 118.7 19.368 ;
     RECT  118.573 23.376 118.717 23.64 ;
     RECT  118.501 3.12 118.753 9.24 ;
     RECT  118.469 21.12 118.757 21.192 ;
     RECT  118.7 17.472 118.787 19.368 ;
     RECT  118.787 18.768 118.793 19.368 ;
     RECT  118.757 21.12 118.829 21.144 ;
     RECT  118.429 0.096 119.026 0.6 ;
     RECT  118.753 2.88 119.036 9.24 ;
     RECT  119.026 0.096 119.123 0.648 ;
     RECT  119.036 2.784 119.123 9.24 ;
     RECT  119.123 2.832 119.125 9.24 ;
     RECT  118.433 10.56 119.125 15.576 ;
     RECT  118.469 22.176 119.132 22.2 ;
     RECT  118.717 23.328 119.132 23.64 ;
     RECT  119.132 22.176 119.173 23.64 ;
     RECT  119.123 0.144 119.219 0.648 ;
     RECT  119.219 0.192 119.315 0.648 ;
     RECT  119.173 22.176 119.333 23.976 ;
     RECT  119.315 0.192 119.411 0.216 ;
     RECT  119.125 2.832 119.653 15.576 ;
     RECT  119.653 2.832 119.761 16.488 ;
     RECT  118.787 17.472 119.761 17.496 ;
     RECT  119.66 20.16 119.843 20.424 ;
     RECT  119.293 1.728 119.986 1.752 ;
     RECT  117.347 25.248 120.085 57.816 ;
     RECT  118.793 18.768 120.092 19.128 ;
     RECT  119.333 22.176 120.121 23.64 ;
     RECT  119.986 1.728 120.157 1.8 ;
     RECT  119.761 2.832 120.157 17.496 ;
     RECT  120.085 25.104 120.179 57.816 ;
     RECT  120.092 18.576 120.337 19.128 ;
     RECT  120.157 1.728 120.553 17.496 ;
     RECT  120.337 18.576 120.553 19.32 ;
     RECT  119.843 20.4 120.949 20.424 ;
     RECT  120.553 1.728 121.093 19.32 ;
     RECT  121.093 1.728 121.208 19.368 ;
     RECT  120.949 20.4 121.208 20.712 ;
     RECT  120.121 21.792 121.208 23.64 ;
     RECT  120.179 25.248 121.208 57.816 ;
     RECT  116.104 58.944 121.208 60.408 ;
     RECT  116.104 62.448 121.208 62.472 ;
     RECT  121.208 58.944 121.312 84.252 ;
     RECT  121.381 0.096 121.477 0.12 ;
     RECT  121.208 1.728 121.504 57.816 ;
     RECT  121.312 58.944 121.504 83.982 ;
     RECT  121.477 0.096 121.669 0.168 ;
     RECT  121.669 0.096 122.003 0.6 ;
     RECT  121.504 24.192 122.033 57.816 ;
     RECT  122.003 0.096 122.105 0.264 ;
     RECT  122.105 0.24 122.141 0.264 ;
     RECT  122.033 24.192 122.533 24.216 ;
     RECT  122.533 23.472 122.537 24.216 ;
     RECT  122.537 23.472 122.677 23.496 ;
     RECT  122.677 23.376 122.681 23.496 ;
     RECT  121.504 1.728 122.962 20.904 ;
     RECT  122.677 22.176 123.037 22.2 ;
     RECT  122.962 1.68 123.1 20.904 ;
     RECT  123.1 18.144 123.107 20.904 ;
     RECT  122.681 23.376 123.107 23.4 ;
     RECT  123.1 1.68 123.109 17.064 ;
     RECT  123.037 21.936 123.109 22.2 ;
     RECT  122.033 25.248 123.325 57.816 ;
     RECT  123.589 0.096 123.613 0.12 ;
     RECT  123.325 24.72 123.865 57.816 ;
     RECT  123.107 18.624 123.877 20.904 ;
     RECT  123.109 21.936 123.877 23.16 ;
     RECT  123.877 18.624 124.117 23.16 ;
     RECT  124.117 18.576 124.163 23.16 ;
     RECT  123.613 0.096 124.165 0.168 ;
     RECT  123.109 1.152 124.165 17.064 ;
     RECT  123.865 24.528 124.301 57.816 ;
     RECT  124.163 22.176 124.405 23.16 ;
     RECT  124.165 0.096 124.837 17.064 ;
     RECT  124.163 18.576 124.837 20.952 ;
     RECT  124.405 22.176 125.053 23.4 ;
     RECT  124.837 0.096 125.129 20.952 ;
     RECT  125.129 0.096 125.237 0.216 ;
     RECT  125.129 1.2 125.413 20.952 ;
     RECT  125.237 0.096 125.561 0.12 ;
     RECT  125.413 1.2 125.597 21.144 ;
     RECT  124.301 24.72 125.633 57.816 ;
     RECT  125.597 1.92 125.665 21.144 ;
     RECT  125.053 22.176 125.665 23.448 ;
     RECT  125.665 1.92 126.608 23.448 ;
     RECT  125.633 24.912 126.608 57.816 ;
     RECT  121.504 58.944 126.608 60.408 ;
     RECT  121.504 62.448 126.608 62.472 ;
     RECT  126.608 58.944 126.712 84.252 ;
     RECT  126.608 1.92 126.904 57.816 ;
     RECT  126.712 58.944 126.904 83.982 ;
     RECT  126.904 18.144 127.001 23.16 ;
     RECT  127.001 18.144 127.043 22.44 ;
     RECT  126.904 24.528 127.145 57.816 ;
     RECT  127.043 18.432 127.475 22.44 ;
     RECT  127.475 18.432 127.757 22.248 ;
     RECT  127.757 18.432 128.081 21 ;
     RECT  127.145 24.72 128.185 57.816 ;
     RECT  128.185 24.672 128.221 57.816 ;
     RECT  126.904 1.92 128.329 17.064 ;
     RECT  128.081 18.432 128.329 19.272 ;
     RECT  127.757 22.176 128.333 22.248 ;
     RECT  128.081 20.256 128.831 21 ;
     RECT  128.333 22.176 128.831 22.2 ;
     RECT  128.329 1.92 129.053 19.272 ;
     RECT  129.053 8.256 129.109 19.272 ;
     RECT  128.831 20.256 129.109 22.2 ;
     RECT  129.193 23.376 129.229 23.4 ;
     RECT  129.109 8.256 129.509 22.2 ;
     RECT  129.229 23.376 129.509 23.496 ;
     RECT  129.509 8.256 129.805 23.496 ;
     RECT  128.221 24.528 129.805 57.816 ;
     RECT  129.053 1.92 130.597 7.176 ;
     RECT  129.805 8.256 130.597 57.816 ;
     RECT  130.597 1.92 130.673 57.816 ;
     RECT  130.673 1.92 131.893 23.4 ;
     RECT  130.673 24.672 131.893 57.816 ;
     RECT  131.893 1.92 132.008 23.64 ;
     RECT  131.893 24.624 132.008 57.816 ;
     RECT  126.904 58.944 132.008 60.408 ;
     RECT  126.904 62.448 132.008 62.472 ;
     RECT  132.008 58.944 132.112 84.252 ;
     RECT  132.112 58.944 132.304 83.982 ;
     RECT  132.008 1.92 133.121 57.816 ;
     RECT  133.121 1.92 133.553 22.296 ;
     RECT  133.553 8.256 134.449 22.296 ;
     RECT  133.121 23.28 134.449 57.816 ;
     RECT  133.553 1.92 134.557 7.176 ;
     RECT  134.449 8.256 134.557 57.816 ;
     RECT  132.304 58.944 137.408 60.408 ;
     RECT  132.304 62.448 137.408 62.472 ;
     RECT  137.408 58.944 137.512 84.252 ;
     RECT  137.512 58.944 137.704 83.982 ;
     RECT  134.557 1.92 139.565 57.816 ;
     RECT  139.565 1.92 139.601 23.496 ;
     RECT  139.601 1.92 140.147 23.352 ;
     RECT  140.147 1.92 140.393 23.256 ;
     RECT  139.565 24.528 141.037 57.816 ;
     RECT  140.393 18.48 141.109 23.256 ;
     RECT  141.037 24.384 141.109 57.816 ;
     RECT  140.393 1.92 142.165 17.448 ;
     RECT  141.109 18.48 142.165 57.816 ;
     RECT  137.704 58.944 142.808 60.408 ;
     RECT  137.704 62.448 142.808 62.472 ;
     RECT  142.808 58.944 142.912 84.252 ;
     RECT  142.912 58.944 143.104 83.982 ;
     RECT  142.165 1.92 143.633 57.816 ;
     RECT  143.633 2.064 144.497 57.816 ;
     RECT  144.497 2.064 144.709 23.544 ;
     RECT  144.709 2.016 144.749 23.544 ;
     RECT  144.749 2.016 144.785 23.4 ;
     RECT  144.785 2.016 145.793 23.016 ;
     RECT  145.793 19.872 145.897 23.016 ;
     RECT  144.497 24.624 145.897 57.816 ;
     RECT  145.793 2.016 145.901 18.888 ;
     RECT  145.901 2.016 146.153 18.552 ;
     RECT  146.153 2.016 146.339 18.504 ;
     RECT  145.897 19.872 146.477 23.544 ;
     RECT  145.897 24.576 146.513 57.816 ;
     RECT  146.339 2.016 147.373 12.888 ;
     RECT  146.339 13.968 147.373 18.504 ;
     RECT  147.373 2.016 147.553 18.504 ;
     RECT  146.477 19.872 147.553 23.448 ;
     RECT  147.553 2.016 148.208 23.448 ;
     RECT  146.513 24.816 148.208 57.816 ;
     RECT  143.104 58.944 148.208 60.36 ;
     RECT  143.104 62.448 148.208 62.472 ;
     RECT  148.208 58.944 148.312 84.252 ;
     RECT  148.312 58.944 148.504 83.982 ;
     RECT  148.208 2.016 148.643 57.816 ;
     RECT  148.643 2.016 149.677 23.928 ;
     RECT  149.677 2.016 150.005 23.976 ;
     RECT  150.005 18.48 150.397 23.976 ;
     RECT  150.397 18.48 150.505 24.072 ;
     RECT  148.643 25.248 150.505 57.816 ;
     RECT  150.005 2.016 151.089 17.496 ;
     RECT  150.505 18.48 151.089 57.816 ;
     RECT  151.089 2.016 151.427 57.816 ;
     RECT  151.427 18.48 153.013 57.816 ;
     RECT  148.504 58.944 153.013 60.36 ;
     RECT  151.427 2.016 153.097 17.496 ;
     RECT  153.013 18.48 153.097 60.36 ;
     RECT  153.097 2.016 153.608 60.36 ;
     RECT  148.504 62.448 153.608 62.472 ;
     RECT  153.608 2.016 153.712 84.252 ;
     RECT  153.712 2.016 153.904 83.982 ;
     RECT  153.904 2.016 155.621 60.36 ;
     RECT  155.621 2.016 155.981 12.984 ;
     RECT  155.981 2.016 157.381 12.888 ;
     RECT  155.621 13.968 157.381 60.36 ;
     RECT  157.381 2.016 159.008 60.36 ;
     RECT  153.904 62.448 159.008 62.472 ;
     RECT  156.277 65.232 159.008 65.256 ;
     RECT  159.008 2.016 159.112 84.252 ;
     RECT  159.112 2.016 159.304 83.982 ;
     RECT  159.304 61.872 161.453 62.472 ;
     RECT  159.304 2.016 162.457 60.36 ;
     RECT  162.457 1.968 162.605 60.36 ;
     RECT  162.605 1.968 162.813 17.496 ;
     RECT  162.813 1.968 162.929 15 ;
     RECT  159.304 80.064 163.237 80.088 ;
     RECT  162.813 15.984 163.861 17.496 ;
     RECT  162.605 18.48 163.861 60.36 ;
     RECT  162.929 1.968 164.408 14.52 ;
     RECT  163.861 15.984 164.408 60.36 ;
     RECT  161.453 61.872 164.408 61.896 ;
     RECT  159.304 65.232 164.408 65.256 ;
     RECT  163.237 79.776 164.408 80.088 ;
     RECT  164.408 1.968 164.512 84.252 ;
     RECT  164.512 1.968 164.704 83.982 ;
     RECT  164.704 1.968 165.197 60.36 ;
     RECT  165.197 1.968 166.259 23.352 ;
     RECT  166.259 2.016 166.489 23.352 ;
     RECT  165.197 24.432 166.489 60.36 ;
     RECT  166.489 2.016 167.609 60.36 ;
     RECT  167.609 24.384 168.617 60.36 ;
     RECT  167.609 2.016 168.685 23.304 ;
     RECT  168.617 24.384 168.685 60.168 ;
     RECT  168.685 2.016 169.808 60.168 ;
     RECT  164.704 61.872 169.808 61.896 ;
     RECT  164.704 65.232 169.808 65.256 ;
     RECT  164.704 74.928 169.808 74.952 ;
     RECT  166.693 76.32 169.808 76.344 ;
     RECT  164.704 79.776 169.808 80.088 ;
     RECT  169.808 2.016 169.912 84.252 ;
     RECT  169.912 2.016 170.104 83.982 ;
     RECT  170.104 2.016 171.029 60.168 ;
     RECT  171.029 2.016 172.028 17.496 ;
     RECT  171.029 18.48 172.028 60.168 ;
     RECT  170.104 74.928 173.509 74.952 ;
     RECT  172.028 2.016 175.208 60.168 ;
     RECT  170.104 61.872 175.208 61.896 ;
     RECT  170.104 65.232 175.208 65.256 ;
     RECT  173.509 74.064 175.208 74.952 ;
     RECT  170.104 76.32 175.208 76.344 ;
     RECT  170.104 79.776 175.208 80.088 ;
     RECT  175.208 2.016 175.312 84.252 ;
     RECT  175.312 2.016 175.504 83.982 ;
     RECT  175.504 2.016 176.465 60.168 ;
     RECT  176.465 15.984 177.443 60.168 ;
     RECT  176.465 2.016 177.757 15 ;
     RECT  177.443 15.984 177.757 17.496 ;
     RECT  177.757 2.016 178.585 17.496 ;
     RECT  177.443 18.48 178.585 60.168 ;
     RECT  178.585 2.016 179.129 60.168 ;
     RECT  179.129 18.48 180.029 60.168 ;
     RECT  179.129 2.016 180.349 17.496 ;
     RECT  180.029 18.48 180.349 57.816 ;
     RECT  180.029 58.944 180.608 60.168 ;
     RECT  175.504 61.872 180.608 61.896 ;
     RECT  175.504 65.232 180.608 65.256 ;
     RECT  175.504 74.064 180.608 74.952 ;
     RECT  175.504 76.32 180.608 76.344 ;
     RECT  176.917 78.72 180.608 78.744 ;
     RECT  175.504 79.776 180.608 80.088 ;
     RECT  180.608 58.944 180.712 84.252 ;
     RECT  180.712 58.944 180.904 83.982 ;
     RECT  180.904 79.776 183.781 80.088 ;
     RECT  180.904 58.944 184.601 60.168 ;
     RECT  184.601 58.944 186.008 60.12 ;
     RECT  180.904 61.872 186.008 61.896 ;
     RECT  180.904 65.232 186.008 65.256 ;
     RECT  180.904 74.064 186.008 74.952 ;
     RECT  180.904 76.32 186.008 76.344 ;
     RECT  180.904 78.72 186.008 78.744 ;
     RECT  183.781 79.776 186.008 80.904 ;
     RECT  186.008 58.944 186.112 84.252 ;
     RECT  186.112 58.944 186.304 83.982 ;
     RECT  186.304 58.944 186.977 60.12 ;
     RECT  186.977 58.944 187.841 60.072 ;
     RECT  180.349 2.016 187.877 57.816 ;
     RECT  187.877 2.016 189.097 20.952 ;
     RECT  187.877 22.032 189.097 57.816 ;
     RECT  186.304 74.064 190.645 74.952 ;
     RECT  186.304 76.32 190.645 76.344 ;
     RECT  187.841 58.944 191.408 60.024 ;
     RECT  186.304 61.872 191.408 61.896 ;
     RECT  186.304 65.232 191.408 65.256 ;
     RECT  187.333 72.72 191.408 72.744 ;
     RECT  190.645 74.064 191.408 76.344 ;
     RECT  186.304 78.72 191.408 78.744 ;
     RECT  186.304 79.776 191.408 80.904 ;
     RECT  191.408 58.944 191.512 84.252 ;
     RECT  191.512 58.944 191.704 83.982 ;
     RECT  189.097 2.016 192.161 57.816 ;
     RECT  191.704 58.944 192.269 60.024 ;
     RECT  192.161 18.48 192.413 57.816 ;
     RECT  192.413 18.48 192.449 23.4 ;
     RECT  192.449 18.48 192.557 23.256 ;
     RECT  192.161 2.016 193.165 17.496 ;
     RECT  192.557 18.48 193.165 23.16 ;
     RECT  192.413 24.384 194.029 57.816 ;
     RECT  191.704 65.232 194.053 65.256 ;
     RECT  193.165 2.016 194.065 23.16 ;
     RECT  194.029 24.24 194.065 57.816 ;
     RECT  194.065 2.016 194.249 57.816 ;
     RECT  194.249 2.016 196.021 20.952 ;
     RECT  194.249 21.984 196.021 57.816 ;
     RECT  192.269 59.52 196.808 60.024 ;
     RECT  191.704 61.872 196.808 61.896 ;
     RECT  194.053 64.992 196.808 65.256 ;
     RECT  191.704 72.72 196.808 72.744 ;
     RECT  191.704 74.064 196.808 76.344 ;
     RECT  191.704 78.72 196.808 78.744 ;
     RECT  191.704 79.776 196.808 80.904 ;
     RECT  196.808 59.52 196.912 84.252 ;
     RECT  196.912 59.52 197.104 83.982 ;
     RECT  197.104 61.872 200.869 61.896 ;
     RECT  196.021 2.016 201.097 57.816 ;
     RECT  201.097 2.016 202.208 10.488 ;
     RECT  201.097 11.472 202.208 57.816 ;
     RECT  197.104 59.52 202.208 60.024 ;
     RECT  200.869 61.872 202.208 62.808 ;
     RECT  197.104 64.992 202.208 65.256 ;
     RECT  197.104 72.72 202.208 72.744 ;
     RECT  197.104 74.064 202.208 76.344 ;
     RECT  197.104 78.72 202.208 78.744 ;
     RECT  197.104 79.776 202.208 80.904 ;
     RECT  202.208 59.52 202.312 84.252 ;
     RECT  202.312 59.52 202.504 83.982 ;
     RECT  202.208 2.016 202.883 57.816 ;
     RECT  202.883 2.016 203.507 14.904 ;
     RECT  202.883 15.936 204.149 57.816 ;
     RECT  203.507 11.664 204.253 14.904 ;
     RECT  204.149 15.936 204.253 23.16 ;
     RECT  203.507 2.016 204.515 10.584 ;
     RECT  204.515 2.016 204.941 10.44 ;
     RECT  204.253 11.664 205.085 23.16 ;
     RECT  204.941 2.016 205.187 5.544 ;
     RECT  205.085 11.712 205.189 23.16 ;
     RECT  204.149 24.192 205.189 57.816 ;
     RECT  202.504 59.52 205.229 60.024 ;
     RECT  205.189 11.712 205.475 57.816 ;
     RECT  205.475 11.712 205.481 23.4 ;
     RECT  205.187 2.064 205.523 5.544 ;
     RECT  205.475 24.384 205.584 57.816 ;
     RECT  204.941 6.624 205.729 10.44 ;
     RECT  202.504 61.872 205.763 62.808 ;
     RECT  205.584 24.384 205.805 49.704 ;
     RECT  205.584 54.24 205.805 55.512 ;
     RECT  205.729 6.624 205.841 10.728 ;
     RECT  205.805 24.384 205.841 41.448 ;
     RECT  205.481 11.76 205.949 23.4 ;
     RECT  202.504 79.776 206.005 80.904 ;
     RECT  205.949 15.936 206.051 23.4 ;
     RECT  205.523 2.256 206.089 5.544 ;
     RECT  205.841 6.624 206.089 10.44 ;
     RECT  206.051 15.984 206.284 23.4 ;
     RECT  206.284 16.224 206.339 23.4 ;
     RECT  205.949 11.76 206.531 14.904 ;
     RECT  206.005 79.776 206.581 81.192 ;
     RECT  206.531 11.76 206.869 14.808 ;
     RECT  206.089 2.256 207.157 10.44 ;
     RECT  206.869 11.52 207.157 14.808 ;
     RECT  207.157 2.256 207.493 14.808 ;
     RECT  206.339 16.224 207.493 23.304 ;
     RECT  205.841 24.384 207.493 41.4 ;
     RECT  207.493 2.256 207.608 14.952 ;
     RECT  207.493 16.224 207.608 41.4 ;
     RECT  205.229 59.52 207.608 59.544 ;
     RECT  205.763 62.784 207.608 62.808 ;
     RECT  202.504 64.992 207.608 65.256 ;
     RECT  202.504 72.72 207.608 72.744 ;
     RECT  202.504 74.064 207.608 76.344 ;
     RECT  202.504 78.72 207.608 78.744 ;
     RECT  206.581 79.776 207.608 81.72 ;
     RECT  207.608 2.148 207.712 41.4 ;
     RECT  207.608 59.52 207.712 84.252 ;
     RECT  207.712 2.256 207.8 41.4 ;
     RECT  205.805 42.768 207.8 49.608 ;
     RECT  206.629 53.856 207.8 53.88 ;
     RECT  205.805 55.2 207.8 55.512 ;
     RECT  205.584 56.832 207.8 56.856 ;
     RECT  207.712 59.52 207.8 83.982 ;
     RECT  207.8 2.256 207.904 83.982 ;
     RECT  207.904 45.552 208.001 49.608 ;
     RECT  208.001 45.744 208.037 49.608 ;
     RECT  207.904 26.688 208.109 39.432 ;
     RECT  208.037 45.744 208.109 49.368 ;
     RECT  208.109 45.744 208.181 47.88 ;
     RECT  208.181 45.84 208.217 47.592 ;
     RECT  208.109 26.688 208.253 39.24 ;
     RECT  208.253 26.688 208.289 39.096 ;
     RECT  208.109 49.008 208.289 49.368 ;
     RECT  208.289 36.624 208.325 39.096 ;
     RECT  208.217 45.936 208.361 47.592 ;
     RECT  207.904 18.384 208.403 25.704 ;
     RECT  208.361 46.512 208.433 47.496 ;
     RECT  208.403 18.48 208.499 25.704 ;
     RECT  208.433 46.512 208.505 47.4 ;
     RECT  208.325 37.248 208.577 39.096 ;
     RECT  208.505 47.376 208.613 47.4 ;
     RECT  207.904 56.832 208.613 57 ;
     RECT  207.904 42.768 208.649 42.792 ;
     RECT  208.499 18.864 208.684 25.128 ;
     RECT  207.904 2.256 208.685 10.728 ;
     RECT  208.577 37.248 208.685 38.76 ;
     RECT  207.904 11.76 208.721 17.208 ;
     RECT  208.289 26.688 209.149 35.592 ;
     RECT  208.685 37.248 209.171 38.472 ;
     RECT  208.685 4.992 209.276 10.728 ;
     RECT  208.721 11.76 209.276 16.68 ;
     RECT  208.684 19.056 209.509 25.128 ;
     RECT  209.612 17.808 209.699 17.832 ;
     RECT  209.509 19.056 209.765 25.512 ;
     RECT  209.171 37.248 210.053 37.368 ;
     RECT  209.765 19.056 210.085 25.08 ;
     RECT  210.053 37.344 210.193 37.368 ;
     RECT  209.171 38.448 210.193 38.472 ;
     RECT  209.149 26.592 210.257 35.592 ;
     RECT  209.276 4.992 210.305 16.68 ;
     RECT  210.085 18.816 210.445 25.08 ;
     RECT  210.305 13.536 210.565 16.68 ;
     RECT  210.305 4.992 210.611 12.312 ;
     RECT  210.257 26.256 210.625 35.592 ;
     RECT  210.565 13.536 210.659 16.776 ;
     RECT  210.445 18.144 210.659 25.08 ;
     RECT  210.659 18.576 210.769 25.08 ;
     RECT  210.625 26.256 210.769 35.976 ;
     RECT  210.659 14.448 210.805 16.776 ;
     RECT  210.769 18.576 210.809 35.976 ;
     RECT  210.193 37.344 210.917 38.472 ;
     RECT  210.611 11.76 211.273 12.312 ;
     RECT  210.809 27.216 211.309 35.976 ;
     RECT  211.309 27.216 211.529 36.024 ;
     RECT  210.611 4.992 211.669 10.728 ;
     RECT  211.273 11.76 211.669 13.128 ;
     RECT  210.805 14.448 211.669 17.112 ;
     RECT  211.669 14.208 211.705 17.112 ;
     RECT  210.809 18.576 211.705 26.088 ;
     RECT  211.705 14.208 211.775 26.088 ;
     RECT  211.669 4.992 211.853 13.128 ;
     RECT  211.853 6.624 211.889 13.128 ;
     RECT  211.529 27.744 212.029 36.024 ;
     RECT  211.889 11.184 212.348 13.128 ;
     RECT  211.775 14.208 212.348 26.76 ;
     RECT  212.348 11.184 212.78 26.76 ;
     RECT  212.029 27.744 212.78 36.504 ;
     RECT  208.685 2.256 213.008 3.672 ;
     RECT  211.853 4.992 213.008 5.544 ;
     RECT  211.889 6.624 213.008 10.152 ;
     RECT  212.78 11.184 213.008 36.504 ;
     RECT  210.917 37.584 213.008 38.472 ;
     RECT  208.289 49.056 213.008 49.368 ;
     RECT  207.904 53.856 213.008 53.88 ;
     RECT  207.904 55.2 213.008 55.512 ;
     RECT  208.613 56.832 213.008 56.856 ;
     RECT  207.904 59.52 213.008 59.544 ;
     RECT  207.904 62.784 213.008 62.808 ;
     RECT  207.904 64.944 213.008 65.256 ;
     RECT  207.904 72.72 213.008 72.744 ;
     RECT  207.904 74.064 213.008 76.344 ;
     RECT  207.904 78.72 213.008 78.744 ;
     RECT  207.904 79.776 213.008 81.72 ;
     RECT  213.008 2.148 213.112 84.252 ;
     RECT  213.112 2.256 213.304 83.982 ;
     RECT  213.304 4.992 213.365 36.024 ;
     RECT  213.304 2.256 214.259 3.672 ;
     RECT  213.365 4.992 214.373 35.592 ;
     RECT  214.373 16.272 214.396 35.592 ;
     RECT  214.396 16.368 214.595 35.592 ;
     RECT  214.595 22.656 214.883 35.592 ;
     RECT  214.373 4.992 215.129 12.312 ;
     RECT  214.883 26.784 215.161 35.592 ;
     RECT  215.161 26.784 215.372 36.456 ;
     RECT  213.304 37.584 215.372 38.472 ;
     RECT  215.129 6.624 215.377 12.312 ;
     RECT  214.373 13.488 215.377 14.808 ;
     RECT  215.377 6.624 215.449 14.808 ;
     RECT  215.521 39.744 215.557 39.768 ;
     RECT  214.595 16.368 215.629 21.624 ;
     RECT  214.883 22.656 215.629 25.704 ;
     RECT  215.557 39.744 215.669 40.488 ;
     RECT  215.629 16.368 215.747 25.704 ;
     RECT  215.449 6.624 215.749 15.384 ;
     RECT  215.747 16.368 215.749 25.128 ;
     RECT  215.129 4.992 216.097 5.544 ;
     RECT  215.749 6.624 216.097 25.128 ;
     RECT  215.372 26.784 216.097 38.472 ;
     RECT  216.097 4.992 216.317 25.128 ;
     RECT  216.317 6 216.323 20.184 ;
     RECT  215.669 39.744 216.745 39.816 ;
     RECT  216.323 6 216.749 19.896 ;
     RECT  216.749 6 216.929 16.824 ;
     RECT  216.745 39.552 216.929 39.816 ;
     RECT  216.097 26.688 217.001 38.472 ;
     RECT  216.317 21.168 217.069 25.128 ;
     RECT  216.997 41.04 217.139 41.064 ;
     RECT  217.069 21.168 217.141 25.656 ;
     RECT  216.929 6 217.181 16.584 ;
     RECT  216.317 4.992 217.187 5.016 ;
     RECT  217.141 21.168 217.237 25.704 ;
     RECT  217.001 26.688 217.237 35.592 ;
     RECT  217.237 21.168 217.357 35.592 ;
     RECT  217.181 6 217.621 16.2 ;
     RECT  216.929 39.744 217.681 39.816 ;
     RECT  218.077 41.616 218.293 41.64 ;
     RECT  214.259 2.832 218.408 3.672 ;
     RECT  217.621 5.616 218.408 16.2 ;
     RECT  216.749 17.856 218.408 19.896 ;
     RECT  217.357 20.976 218.408 35.592 ;
     RECT  217.001 36.576 218.408 38.472 ;
     RECT  217.681 39.744 218.408 40.536 ;
     RECT  218.293 41.616 218.408 41.928 ;
     RECT  213.304 49.056 218.408 49.368 ;
     RECT  213.304 53.856 218.408 53.88 ;
     RECT  213.304 55.2 218.408 55.512 ;
     RECT  213.304 56.832 218.408 56.856 ;
     RECT  213.304 59.52 218.408 59.544 ;
     RECT  213.304 62.784 218.408 62.808 ;
     RECT  213.304 64.944 218.408 65.256 ;
     RECT  213.304 72.72 218.408 72.744 ;
     RECT  213.304 74.064 218.408 76.344 ;
     RECT  213.304 78.72 218.408 78.744 ;
     RECT  213.304 79.776 218.408 81.72 ;
     RECT  218.408 2.148 218.512 84.252 ;
     RECT  218.512 2.418 218.704 83.982 ;
     RECT  218.704 5.472 218.765 15.576 ;
     RECT  218.704 20.976 218.765 24.888 ;
     RECT  218.765 5.472 218.819 5.496 ;
     RECT  218.704 39.744 218.909 39.816 ;
     RECT  218.704 44.064 219.011 44.472 ;
     RECT  218.704 45.456 219.011 45.48 ;
     RECT  218.765 6.576 219.053 15.576 ;
     RECT  218.704 40.944 219.053 42.024 ;
     RECT  218.704 2.832 219.161 3.336 ;
     RECT  219.053 41.952 219.161 42.024 ;
     RECT  218.704 25.92 219.203 38.472 ;
     RECT  219.053 11.232 219.233 15.576 ;
     RECT  218.909 39.744 219.233 39.768 ;
     RECT  219.161 41.952 219.269 41.976 ;
     RECT  219.203 26.208 219.305 38.472 ;
     RECT  218.704 16.992 219.635 19.944 ;
     RECT  219.233 11.76 219.692 15.576 ;
     RECT  219.635 16.992 219.692 18.408 ;
     RECT  219.635 19.872 219.733 19.944 ;
     RECT  218.765 21.024 219.733 24.888 ;
     RECT  219.692 11.76 219.773 18.408 ;
     RECT  219.773 16.224 219.779 18.408 ;
     RECT  219.692 43.104 219.779 43.128 ;
     RECT  219.733 19.872 219.845 24.888 ;
     RECT  219.733 45.6 219.953 45.624 ;
     RECT  219.773 14.4 220.061 14.808 ;
     RECT  219.053 40.944 220.097 40.968 ;
     RECT  220.061 14.448 220.133 14.808 ;
     RECT  219.305 29.712 220.133 38.472 ;
     RECT  220.133 14.688 220.277 14.808 ;
     RECT  219.305 26.208 220.316 28.584 ;
     RECT  219.011 44.448 220.364 44.472 ;
     RECT  220.316 25.872 220.381 28.584 ;
     RECT  220.133 29.712 220.381 36.6 ;
     RECT  220.364 44.16 220.381 44.472 ;
     RECT  220.381 25.872 220.403 36.6 ;
     RECT  220.381 43.92 220.451 44.472 ;
     RECT  219.053 6.576 220.453 10.248 ;
     RECT  219.773 11.76 220.453 13.272 ;
     RECT  220.451 43.92 220.499 43.944 ;
     RECT  219.779 16.992 220.529 18.408 ;
     RECT  220.405 46.176 220.601 46.2 ;
     RECT  220.345 42.816 220.673 42.84 ;
     RECT  219.845 21.12 220.705 24.888 ;
     RECT  220.453 6.576 220.709 13.272 ;
     RECT  220.277 14.736 220.709 14.808 ;
     RECT  220.709 6.576 220.741 12.792 ;
     RECT  220.133 37.584 220.777 38.472 ;
     RECT  220.529 17.712 220.789 18.408 ;
     RECT  219.845 19.872 220.789 19.896 ;
     RECT  220.741 6.192 220.835 12.792 ;
     RECT  220.789 17.712 220.885 19.896 ;
     RECT  220.705 21.12 220.885 25.176 ;
     RECT  220.777 37.584 220.885 38.76 ;
     RECT  220.709 14.736 220.961 14.76 ;
     RECT  220.741 16.176 221.075 16.2 ;
     RECT  220.453 44.976 221.101 45.096 ;
     RECT  221.137 41.136 221.209 41.304 ;
     RECT  220.741 42.288 221.209 42.36 ;
     RECT  220.885 37.584 221.353 39.384 ;
     RECT  220.403 26.256 221.448 36.6 ;
     RECT  221.269 14.352 221.459 14.376 ;
     RECT  220.885 17.712 221.501 25.176 ;
     RECT  221.501 17.712 221.533 18.6 ;
     RECT  220.777 43.536 221.533 43.56 ;
     RECT  221.101 44.976 221.533 45.768 ;
     RECT  221.501 19.872 221.555 25.176 ;
     RECT  221.555 23.088 221.569 25.176 ;
     RECT  221.448 26.208 221.569 36.6 ;
     RECT  221.555 19.872 221.603 22.056 ;
     RECT  221.533 43.536 221.605 45.768 ;
     RECT  219.161 2.832 221.717 2.856 ;
     RECT  221.603 19.968 221.717 22.056 ;
     RECT  221.209 41.136 221.861 42.36 ;
     RECT  220.835 6.576 221.987 12.792 ;
     RECT  221.533 16.56 221.987 18.6 ;
     RECT  221.987 6.576 222.001 10.152 ;
     RECT  221.861 41.28 222.109 42.36 ;
     RECT  221.605 43.536 222.109 46.104 ;
     RECT  222.109 41.28 222.113 46.104 ;
     RECT  221.987 11.76 222.145 12.792 ;
     RECT  218.704 62.784 222.145 62.808 ;
     RECT  221.569 23.088 222.185 36.6 ;
     RECT  222.113 41.52 222.185 46.104 ;
     RECT  221.353 37.584 222.217 39.96 ;
     RECT  222.145 62.16 222.325 62.808 ;
     RECT  222.001 6.432 222.329 10.152 ;
     RECT  221.987 17.04 222.329 18.6 ;
     RECT  222.217 37.584 222.329 40.056 ;
     RECT  222.185 42.288 222.38 46.104 ;
     RECT  222.38 42.288 222.419 46.632 ;
     RECT  222.419 42.576 222.467 46.632 ;
     RECT  222.325 61.536 222.577 62.808 ;
     RECT  222.467 43.536 222.581 46.104 ;
     RECT  222.145 11.76 222.613 13.608 ;
     RECT  222.577 60.912 222.613 62.808 ;
     RECT  222.613 60.912 222.617 63.048 ;
     RECT  222.617 62.16 222.659 63.048 ;
     RECT  222.329 39.84 222.797 40.056 ;
     RECT  222.505 18.768 222.829 18.792 ;
     RECT  222.185 27.744 222.829 36.6 ;
     RECT  222.329 37.584 222.829 38.472 ;
     RECT  222.659 62.784 222.937 63.048 ;
     RECT  222.613 11.76 223.045 13.656 ;
     RECT  221.717 20.544 223.081 22.056 ;
     RECT  222.829 18.768 223.153 18.984 ;
     RECT  223.081 20.064 223.153 22.056 ;
     RECT  222.329 17.04 223.244 17.448 ;
     RECT  223.117 15.456 223.261 15.48 ;
     RECT  223.153 18.768 223.285 22.056 ;
     RECT  222.185 23.088 223.285 26.664 ;
     RECT  223.285 18.768 223.292 26.664 ;
     RECT  222.829 27.744 223.292 38.472 ;
     RECT  222.329 6.624 223.429 10.152 ;
     RECT  218.704 64.944 223.513 65.256 ;
     RECT  222.937 62.784 223.621 63.528 ;
     RECT  223.045 11.376 223.669 13.656 ;
     RECT  223.261 15.264 223.669 15.48 ;
     RECT  223.244 16.656 223.669 17.448 ;
     RECT  223.292 18.768 223.669 38.472 ;
     RECT  222.581 43.536 223.669 43.56 ;
     RECT  222.581 44.736 223.669 46.104 ;
     RECT  223.429 6.624 223.808 10.248 ;
     RECT  223.669 11.376 223.808 15.48 ;
     RECT  223.669 16.656 223.808 38.472 ;
     RECT  222.797 39.936 223.808 40.056 ;
     RECT  223.669 43.536 223.808 46.104 ;
     RECT  218.704 49.056 223.808 49.368 ;
     RECT  218.704 53.856 223.808 53.88 ;
     RECT  218.704 55.2 223.808 55.512 ;
     RECT  218.704 56.832 223.808 56.856 ;
     RECT  223.693 57.888 223.808 57.912 ;
     RECT  218.704 59.52 223.808 59.544 ;
     RECT  222.617 60.912 223.808 60.936 ;
     RECT  223.621 62.784 223.808 63.624 ;
     RECT  223.513 64.944 223.808 65.448 ;
     RECT  218.704 72.72 223.808 72.744 ;
     RECT  218.704 74.064 223.808 76.344 ;
     RECT  218.704 78.72 223.808 78.744 ;
     RECT  218.704 79.776 223.808 81.72 ;
     RECT  223.808 2.148 223.912 84.252 ;
     RECT  223.912 2.418 224.104 83.982 ;
     RECT  224.104 18.72 224.165 25.224 ;
     RECT  224.104 63.504 224.165 65.448 ;
     RECT  224.104 42.72 224.237 43.56 ;
     RECT  224.104 26.208 224.387 38.952 ;
     RECT  224.104 60.912 224.489 62.424 ;
     RECT  224.104 40.8 224.525 41.688 ;
     RECT  224.387 26.208 224.561 36.6 ;
     RECT  224.387 37.632 224.561 38.952 ;
     RECT  224.165 19.008 224.62 25.224 ;
     RECT  224.489 61.536 224.627 62.424 ;
     RECT  224.237 42.72 224.633 43.368 ;
     RECT  224.104 56.448 224.633 57.912 ;
     RECT  224.104 17.28 224.777 17.304 ;
     RECT  224.104 8.784 224.819 14.232 ;
     RECT  224.104 53.856 224.849 55.32 ;
     RECT  224.104 6.624 224.915 7.416 ;
     RECT  224.104 15.984 224.921 16.152 ;
     RECT  224.921 16.128 224.963 16.152 ;
     RECT  224.633 43.344 224.963 43.368 ;
     RECT  224.104 79.776 225.029 82.68 ;
     RECT  224.104 74.064 225.065 76.344 ;
     RECT  224.525 40.8 225.097 41.496 ;
     RECT  224.819 8.784 225.137 12.312 ;
     RECT  224.627 61.536 225.137 61.56 ;
     RECT  224.165 63.6 225.155 65.448 ;
     RECT  225.137 8.784 225.169 11.784 ;
     RECT  224.62 19.008 225.203 19.08 ;
     RECT  224.819 13.488 225.205 14.232 ;
     RECT  224.62 20.064 225.205 25.224 ;
     RECT  224.561 26.208 225.205 36.504 ;
     RECT  224.561 37.68 225.209 38.952 ;
     RECT  224.849 55.2 225.308 55.32 ;
     RECT  224.633 56.448 225.308 56.856 ;
     RECT  225.205 13.488 225.443 14.28 ;
     RECT  225.443 14.256 225.445 14.28 ;
     RECT  224.104 72.72 225.457 72.888 ;
     RECT  225.445 14.256 225.491 14.712 ;
     RECT  224.104 49.056 225.493 49.368 ;
     RECT  225.169 8.544 225.497 11.784 ;
     RECT  225.205 20.064 225.529 36.504 ;
     RECT  225.155 63.6 225.529 63.624 ;
     RECT  225.491 14.688 225.532 14.712 ;
     RECT  225.529 62.64 225.569 63.624 ;
     RECT  225.097 82.992 225.569 83.016 ;
     RECT  225.529 20.064 225.605 37.032 ;
     RECT  225.569 62.64 225.637 62.664 ;
     RECT  225.209 38.448 225.673 38.952 ;
     RECT  225.497 8.784 225.677 11.784 ;
     RECT  225.605 20.448 225.731 37.032 ;
     RECT  225.097 40.704 225.749 41.496 ;
     RECT  225.731 21.168 225.757 37.032 ;
     RECT  225.757 21.168 225.779 22.2 ;
     RECT  224.104 45.168 225.779 45.192 ;
     RECT  225.677 8.784 225.785 11.016 ;
     RECT  225.757 23.184 225.785 37.032 ;
     RECT  225.749 40.704 225.821 40.728 ;
     RECT  225.785 23.184 225.827 23.736 ;
     RECT  225.785 24.72 225.857 37.032 ;
     RECT  225.029 79.776 225.929 81.72 ;
     RECT  225.733 42.864 225.993 42.888 ;
     RECT  225.827 23.184 226.037 23.592 ;
     RECT  225.308 55.2 226.145 56.856 ;
     RECT  224.915 6.624 226.181 7.224 ;
     RECT  226.357 46.368 226.429 46.392 ;
     RECT  226.145 55.2 226.433 55.56 ;
     RECT  225.637 62.544 226.529 62.664 ;
     RECT  225.857 26.112 226.573 37.032 ;
     RECT  225.673 38.448 226.573 39.096 ;
     RECT  226.2 45.264 226.595 45.288 ;
     RECT  226.529 62.112 226.613 62.664 ;
     RECT  226.429 46.368 226.717 47.112 ;
     RECT  226.717 45.648 226.781 47.112 ;
     RECT  226.613 62.544 226.789 62.664 ;
     RECT  225.457 72.72 226.825 73.032 ;
     RECT  226.789 62.544 226.835 63 ;
     RECT  225.779 21.168 226.837 21.72 ;
     RECT  226.573 26.112 226.861 39.096 ;
     RECT  226.781 45.648 226.865 47.352 ;
     RECT  226.837 21.024 226.892 21.72 ;
     RECT  226.037 23.184 226.892 23.208 ;
     RECT  226.835 62.64 226.897 63 ;
     RECT  226.433 55.2 226.933 55.224 ;
     RECT  225.785 8.784 226.979 10.728 ;
     RECT  226.892 21.024 226.979 23.208 ;
     RECT  225.857 24.72 227.039 24.744 ;
     RECT  226.753 41.376 227.081 41.4 ;
     RECT  226.145 56.832 227.113 56.856 ;
     RECT  224.633 57.888 227.113 57.912 ;
     RECT  226.979 21.024 227.123 22.104 ;
     RECT  227.123 21.024 227.171 21.672 ;
     RECT  227.041 43.92 227.171 44.04 ;
     RECT  226.865 45.648 227.171 47.112 ;
     RECT  226.979 8.784 227.219 9.528 ;
     RECT  227.171 43.92 227.219 43.944 ;
     RECT  225.929 79.776 227.297 81.336 ;
     RECT  227.297 79.776 227.315 81.048 ;
     RECT  224.104 59.52 227.401 59.544 ;
     RECT  227.171 45.648 227.405 46.104 ;
     RECT  226.979 23.088 227.509 23.208 ;
     RECT  227.039 24.72 227.509 24.888 ;
     RECT  226.861 26.112 227.509 39.96 ;
     RECT  227.509 23.088 227.513 39.96 ;
     RECT  227.468 17.04 227.555 17.064 ;
     RECT  224.849 53.856 227.557 53.88 ;
     RECT  226.933 54.864 227.557 55.224 ;
     RECT  226.897 62.64 227.653 63.144 ;
     RECT  227.315 79.776 227.657 80.904 ;
     RECT  227.113 56.832 227.689 57.912 ;
     RECT  227.401 58.896 227.689 59.544 ;
     RECT  227.653 62.64 227.689 63.72 ;
     RECT  225.155 64.704 227.689 65.448 ;
     RECT  227.401 70.656 227.717 70.68 ;
     RECT  227.513 23.088 227.729 38.808 ;
     RECT  227.717 70.656 227.749 70.728 ;
     RECT  227.513 39.84 227.756 39.96 ;
     RECT  227.557 53.856 227.759 55.224 ;
     RECT  227.473 61.536 227.795 61.56 ;
     RECT  226.825 72.24 227.795 73.032 ;
     RECT  227.749 70.08 227.801 70.728 ;
     RECT  227.365 15.36 227.837 15.384 ;
     RECT  227.756 39.84 227.843 40.248 ;
     RECT  227.405 45.648 227.843 45.672 ;
     RECT  227.689 56.832 227.843 59.544 ;
     RECT  227.759 53.568 227.905 55.224 ;
     RECT  227.843 56.832 227.905 57.912 ;
     RECT  227.689 62.64 227.909 65.448 ;
     RECT  227.219 8.784 227.969 9.336 ;
     RECT  227.941 42.096 228.028 42.12 ;
     RECT  227.843 39.84 228.053 39.864 ;
     RECT  227.905 53.568 228.089 57.912 ;
     RECT  227.171 47.088 228.188 47.112 ;
     RECT  225.493 48.384 228.188 49.368 ;
     RECT  227.869 11.856 228.229 11.88 ;
     RECT  228.188 47.088 228.229 49.368 ;
     RECT  226.789 82.656 228.301 82.68 ;
     RECT  228.229 11.808 228.332 11.88 ;
     RECT  227.977 12.912 228.332 12.936 ;
     RECT  227.257 10.8 228.373 10.824 ;
     RECT  228.332 11.808 228.373 12.936 ;
     RECT  227.977 52.368 228.373 52.392 ;
     RECT  228.229 47.088 228.38 50.28 ;
     RECT  226.181 6.816 228.517 7.224 ;
     RECT  228.517 6.816 228.589 7.416 ;
     RECT  227.969 8.496 228.589 9.336 ;
     RECT  227.657 79.776 228.62 80.088 ;
     RECT  228.089 53.568 228.625 54.744 ;
     RECT  228.62 79.728 228.661 80.088 ;
     RECT  228.284 81.264 228.661 81.288 ;
     RECT  227.171 21.024 228.757 21.192 ;
     RECT  227.909 63.696 228.769 65.448 ;
     RECT  228.013 22.896 228.805 22.92 ;
     RECT  227.729 24.096 228.805 38.808 ;
     RECT  225.065 74.064 228.805 74.952 ;
     RECT  228.373 10.8 228.853 12.936 ;
     RECT  228.805 22.896 228.853 38.808 ;
     RECT  228.085 62.16 228.877 62.184 ;
     RECT  228.769 63.696 228.877 65.544 ;
     RECT  228.373 51.984 228.901 52.392 ;
     RECT  228.301 44.496 228.913 44.52 ;
     RECT  225.203 19.008 228.985 19.032 ;
     RECT  228.877 62.16 228.985 62.472 ;
     RECT  227.801 70.08 229.045 70.68 ;
     RECT  228.589 6.816 229.208 9.336 ;
     RECT  228.853 10.8 229.208 13.608 ;
     RECT  228.812 16.176 229.208 16.2 ;
     RECT  228.985 18.768 229.208 19.032 ;
     RECT  228.757 20.784 229.208 21.192 ;
     RECT  228.853 22.848 229.208 38.808 ;
     RECT  228.517 41.472 229.208 41.496 ;
     RECT  228.913 44.496 229.208 45.192 ;
     RECT  228.38 46.656 229.208 50.28 ;
     RECT  228.901 51.936 229.208 52.392 ;
     RECT  228.625 53.472 229.208 54.744 ;
     RECT  228.089 55.824 229.208 57.912 ;
     RECT  227.843 59.184 229.208 59.544 ;
     RECT  228.985 61.2 229.208 62.472 ;
     RECT  228.877 63.696 229.208 66.264 ;
     RECT  229.045 69.648 229.208 70.68 ;
     RECT  227.795 72.24 229.208 72.744 ;
     RECT  228.805 74.064 229.208 75.144 ;
     RECT  225.065 76.32 229.208 76.344 ;
     RECT  224.104 78.72 229.208 78.744 ;
     RECT  228.661 79.728 229.208 81.288 ;
     RECT  228.301 82.656 229.208 83.64 ;
     RECT  229.208 2.148 229.312 84.252 ;
     RECT  229.312 2.418 229.504 83.982 ;
     RECT  229.504 6.816 229.619 13.608 ;
     RECT  229.504 41.472 229.619 41.496 ;
     RECT  229.504 53.568 229.619 62.712 ;
     RECT  229.504 78.72 229.619 80.808 ;
     RECT  229.504 14.832 229.637 17.112 ;
     RECT  229.504 24.72 229.667 39.912 ;
     RECT  229.504 63.792 229.667 63.816 ;
     RECT  229.504 72.24 229.667 72.984 ;
     RECT  229.637 16.416 229.681 17.112 ;
     RECT  229.619 6.816 229.715 11.4 ;
     RECT  229.504 21.168 229.715 21.192 ;
     RECT  229.504 22.8 229.715 23.688 ;
     RECT  229.504 42.768 229.715 52.008 ;
     RECT  229.619 56.4 229.811 62.712 ;
     RECT  229.619 13.056 229.817 13.608 ;
     RECT  229.811 62.016 229.852 62.04 ;
     RECT  229.504 82.656 229.955 82.68 ;
     RECT  229.715 8.784 230.003 11.4 ;
     RECT  229.817 13.056 230.003 13.08 ;
     RECT  229.667 26.544 230.003 39.912 ;
     RECT  229.715 43.536 230.003 52.008 ;
     RECT  230.003 8.784 230.069 9.336 ;
     RECT  229.715 23.28 230.069 23.688 ;
     RECT  229.637 14.832 230.099 15.432 ;
     RECT  230.003 26.544 230.099 37.128 ;
     RECT  230.069 8.784 230.149 9.096 ;
     RECT  230.149 8.784 230.177 8.808 ;
     RECT  229.811 56.4 230.213 61.032 ;
     RECT  229.667 24.72 230.243 25.08 ;
     RECT  229.619 78.72 230.249 80.232 ;
     RECT  229.681 16.992 230.269 17.112 ;
     RECT  229.504 18.144 230.339 19.032 ;
     RECT  229.504 65.424 230.339 66.744 ;
     RECT  230.213 56.4 230.357 59.88 ;
     RECT  230.269 16.992 230.429 17.064 ;
     RECT  229.667 72.72 230.492 72.984 ;
     RECT  229.504 74.064 230.492 74.088 ;
     RECT  230.003 44.4 230.537 52.008 ;
     RECT  229.619 53.568 230.573 55.32 ;
     RECT  230.492 72.72 230.579 74.088 ;
     RECT  229.504 75.12 230.581 76.344 ;
     RECT  230.579 72.72 230.645 72.984 ;
     RECT  230.099 15.408 230.677 15.432 ;
     RECT  230.497 64.944 230.677 65.256 ;
     RECT  230.579 74.064 230.677 74.088 ;
     RECT  230.581 75.12 230.677 76.968 ;
     RECT  230.249 78.912 230.677 80.232 ;
     RECT  230.003 10.32 230.723 11.4 ;
     RECT  230.429 16.992 230.723 17.016 ;
     RECT  230.537 44.4 230.723 45.72 ;
     RECT  230.573 54.144 230.723 55.32 ;
     RECT  230.677 64.032 230.723 65.256 ;
     RECT  230.069 23.376 230.749 23.688 ;
     RECT  230.243 24.72 230.749 24.888 ;
     RECT  230.339 66.24 230.771 66.744 ;
     RECT  230.641 12.48 230.78 12.552 ;
     RECT  230.677 74.064 230.797 76.968 ;
     RECT  230.723 10.32 230.819 10.728 ;
     RECT  230.537 46.752 230.821 52.008 ;
     RECT  230.723 64.032 230.821 64.296 ;
     RECT  230.749 23.376 230.833 24.888 ;
     RECT  230.819 10.32 230.861 10.344 ;
     RECT  230.833 23.664 230.861 24.888 ;
     RECT  230.78 11.952 230.867 12.552 ;
     RECT  230.861 23.664 230.867 23.688 ;
     RECT  230.213 60.96 230.867 61.032 ;
     RECT  230.821 63.216 230.867 64.296 ;
     RECT  230.677 78.912 230.867 81.048 ;
     RECT  230.099 26.544 230.876 37.08 ;
     RECT  230.357 56.4 230.876 58.152 ;
     RECT  229.715 6.816 230.885 7.416 ;
     RECT  230.867 63.216 230.908 63.24 ;
     RECT  229.504 70.272 230.917 70.68 ;
     RECT  230.885 6.816 230.924 7.464 ;
     RECT  230.725 8.496 230.924 8.52 ;
     RECT  230.924 6.816 230.963 8.52 ;
     RECT  230.876 55.92 230.963 58.152 ;
     RECT  230.867 64.272 230.963 64.296 ;
     RECT  230.677 15.408 230.969 16.008 ;
     RECT  230.797 74.064 231.005 74.088 ;
     RECT  230.963 7.2 231.011 8.52 ;
     RECT  230.003 38.16 231.037 39.912 ;
     RECT  230.867 12 231.109 12.552 ;
     RECT  230.677 71.808 231.113 71.88 ;
     RECT  230.645 72.96 231.155 72.984 ;
     RECT  230.876 26.208 231.217 37.08 ;
     RECT  231.109 12 231.253 12.792 ;
     RECT  230.917 69.696 231.289 70.68 ;
     RECT  231.037 83.424 231.299 83.448 ;
     RECT  231.037 38.16 231.301 40.44 ;
     RECT  231.113 71.856 231.347 71.88 ;
     RECT  230.357 59.52 231.349 59.88 ;
     RECT  231.289 69.696 231.373 70.728 ;
     RECT  230.963 56.4 231.395 58.152 ;
     RECT  230.861 24.72 231.397 24.888 ;
     RECT  231.217 25.968 231.397 37.08 ;
     RECT  231.301 38.16 231.397 41.016 ;
     RECT  230.771 66.72 231.397 66.744 ;
     RECT  229.504 67.776 231.397 67.8 ;
     RECT  230.867 61.008 231.404 61.032 ;
     RECT  231.397 66.72 231.404 67.8 ;
     RECT  230.723 44.4 231.433 45.576 ;
     RECT  231.404 66.72 231.443 68.376 ;
     RECT  231.011 8.496 231.452 8.52 ;
     RECT  231.404 61.008 231.473 61.512 ;
     RECT  230.917 62.64 231.473 62.76 ;
     RECT  231.373 69.696 231.473 70.44 ;
     RECT  231.473 61.488 231.491 61.512 ;
     RECT  231.443 68.352 231.491 68.376 ;
     RECT  230.821 46.752 231.5 52.44 ;
     RECT  231.395 56.736 231.541 58.152 ;
     RECT  231.349 59.28 231.541 59.88 ;
     RECT  230.797 75.12 231.577 76.968 ;
     RECT  230.867 78.912 231.577 79.848 ;
     RECT  231.5 46.752 231.587 52.824 ;
     RECT  231.397 38.16 231.589 41.064 ;
     RECT  230.867 80.928 231.613 81.048 ;
     RECT  231.452 8.496 231.617 9.96 ;
     RECT  230.339 18.144 231.617 18.168 ;
     RECT  231.433 44.208 231.685 45.576 ;
     RECT  231.587 46.752 231.685 52.056 ;
     RECT  231.613 82.656 231.697 82.68 ;
     RECT  230.969 15.936 231.721 16.008 ;
     RECT  231.617 9.072 231.829 9.96 ;
     RECT  231.721 15.936 231.829 16.152 ;
     RECT  231.685 44.208 231.829 52.056 ;
     RECT  230.723 54.144 231.829 54.744 ;
     RECT  231.541 56.736 231.829 59.88 ;
     RECT  231.443 66.72 231.829 67.272 ;
     RECT  231.829 9.072 231.865 10.584 ;
     RECT  231.397 24.72 231.865 37.08 ;
     RECT  231.589 38.16 231.865 41.16 ;
     RECT  231.829 66.672 231.869 67.272 ;
     RECT  231.577 75.12 231.875 77.592 ;
     RECT  231.865 9.072 231.877 10.824 ;
     RECT  231.865 24.72 231.877 41.16 ;
     RECT  231.253 12 231.884 12.84 ;
     RECT  231.877 24.72 231.884 41.544 ;
     RECT  231.877 9.36 231.901 10.824 ;
     RECT  231.884 11.808 231.901 12.84 ;
     RECT  231.829 53.232 231.923 54.744 ;
     RECT  231.473 70.416 231.923 70.44 ;
     RECT  231.923 53.568 231.925 54.744 ;
     RECT  231.877 68.88 231.964 69.336 ;
     RECT  231.829 43.776 231.971 52.056 ;
     RECT  231.925 53.568 231.971 55.32 ;
     RECT  231.884 23.952 231.973 41.544 ;
     RECT  231.971 54.144 232.013 55.32 ;
     RECT  231.829 15.936 232.019 16.968 ;
     RECT  231.757 62.592 232.019 62.616 ;
     RECT  231.973 63.792 232.045 63.816 ;
     RECT  231.901 9.36 232.117 12.84 ;
     RECT  231.875 76.176 232.117 77.592 ;
     RECT  231.577 78.624 232.117 79.848 ;
     RECT  232.117 9.36 232.125 12.936 ;
     RECT  232.045 63.792 232.163 64.776 ;
     RECT  231.011 7.2 232.268 7.224 ;
     RECT  232.019 15.984 232.268 16.968 ;
     RECT  231.964 68.88 232.307 68.904 ;
     RECT  231.971 43.776 232.309 50.808 ;
     RECT  231.613 80.928 232.316 81.48 ;
     RECT  232.309 20.832 232.333 20.856 ;
     RECT  232.268 15.984 232.337 17.112 ;
     RECT  232.125 9.36 232.355 13.8 ;
     RECT  232.337 16.944 232.355 17.112 ;
     RECT  232.316 65.52 232.403 65.544 ;
     RECT  232.316 80.928 232.405 81.624 ;
     RECT  232.309 43.152 232.409 50.808 ;
     RECT  231.829 56.736 232.417 60.024 ;
     RECT  231.932 18.096 232.451 18.12 ;
     RECT  232.333 20.544 232.451 20.856 ;
     RECT  232.013 54.672 232.477 55.32 ;
     RECT  232.417 56.736 232.477 56.76 ;
     RECT  232.268 7.2 232.481 7.8 ;
     RECT  232.355 9.36 232.517 12.936 ;
     RECT  232.417 57.888 232.517 60.024 ;
     RECT  232.117 76.176 232.517 79.848 ;
     RECT  231.875 75.12 232.547 75.144 ;
     RECT  232.517 78.48 232.589 79.848 ;
     RECT  232.405 80.928 232.595 81.864 ;
     RECT  232.595 80.928 232.633 80.952 ;
     RECT  232.451 20.832 232.661 20.856 ;
     RECT  232.517 76.176 232.697 76.92 ;
     RECT  232.621 6.816 232.705 6.84 ;
     RECT  231.973 23.952 232.729 41.832 ;
     RECT  232.697 76.176 232.733 76.728 ;
     RECT  232.355 16.944 232.739 16.968 ;
     RECT  232.657 7.968 232.741 7.992 ;
     RECT  232.517 59.52 232.748 60.024 ;
     RECT  232.163 63.792 232.765 64.056 ;
     RECT  232.748 59.52 232.769 60.984 ;
     RECT  232.733 76.176 232.769 76.392 ;
     RECT  232.769 60.96 232.789 60.984 ;
     RECT  232.729 23.616 232.835 41.832 ;
     RECT  231.971 51.792 232.835 52.056 ;
     RECT  232.789 60.96 232.835 61.608 ;
     RECT  232.835 32.016 232.837 41.832 ;
     RECT  232.477 54.672 232.841 56.76 ;
     RECT  232.769 76.368 232.841 76.392 ;
     RECT  232.517 9.696 232.877 12.936 ;
     RECT  232.835 23.616 232.877 30.744 ;
     RECT  232.877 9.696 232.883 12.504 ;
     RECT  232.877 23.616 232.883 30.552 ;
     RECT  232.409 43.776 232.883 50.808 ;
     RECT  232.841 55.296 232.913 56.472 ;
     RECT  232.769 59.52 232.931 59.544 ;
     RECT  232.835 61.584 232.933 61.608 ;
     RECT  232.837 32.016 232.979 42.792 ;
     RECT  232.765 63.552 232.979 64.056 ;
     RECT  232.589 78.48 232.979 79.272 ;
     RECT  232.835 51.888 232.981 52.056 ;
     RECT  231.869 66.672 232.985 66.696 ;
     RECT  232.979 79.248 233.021 79.272 ;
     RECT  232.979 32.016 233.093 42.168 ;
     RECT  232.883 23.616 233.171 30.36 ;
     RECT  232.883 10.128 233.201 12.504 ;
     RECT  233.093 41.04 233.201 42.168 ;
     RECT  233.093 38.784 233.219 39.912 ;
     RECT  232.913 56.448 233.237 56.472 ;
     RECT  232.933 61.584 233.237 62.328 ;
     RECT  233.201 10.128 233.267 12.36 ;
     RECT  233.171 24.72 233.267 30.36 ;
     RECT  232.981 51.888 233.269 52.392 ;
     RECT  232.913 55.296 233.273 55.32 ;
     RECT  232.979 64.032 233.309 64.056 ;
     RECT  233.267 10.128 233.381 10.152 ;
     RECT  233.341 82.608 233.453 82.632 ;
     RECT  233.219 39.168 233.525 39.912 ;
     RECT  232.883 43.776 233.525 43.896 ;
     RECT  233.269 51.888 233.633 52.968 ;
     RECT  232.883 44.928 233.893 50.808 ;
     RECT  233.633 51.888 233.893 52.392 ;
     RECT  233.525 43.872 233.989 43.896 ;
     RECT  233.893 44.928 233.989 52.392 ;
     RECT  234.061 79.68 234.133 79.704 ;
     RECT  233.171 23.616 234.205 23.64 ;
     RECT  233.267 24.72 234.205 28.2 ;
     RECT  234.205 23.616 234.313 28.2 ;
     RECT  233.267 29.808 234.313 30.36 ;
     RECT  234.313 23.616 234.385 30.36 ;
     RECT  234.133 83.04 234.421 83.064 ;
     RECT  234.349 13.104 234.457 13.128 ;
     RECT  234.133 61.248 234.565 61.272 ;
     RECT  233.267 11.376 234.608 11.4 ;
     RECT  234.457 13.104 234.608 13.32 ;
     RECT  234.529 16.896 234.608 16.92 ;
     RECT  234.385 23.616 234.608 30.6 ;
     RECT  233.093 32.016 234.608 37.704 ;
     RECT  233.201 41.04 234.608 41.064 ;
     RECT  233.201 42.144 234.608 42.168 ;
     RECT  233.989 43.872 234.608 52.392 ;
     RECT  232.517 57.888 234.608 57.912 ;
     RECT  234.565 60.816 234.608 61.272 ;
     RECT  234.529 62.832 234.608 62.856 ;
     RECT  234.413 78.048 234.608 78.072 ;
     RECT  234.133 79.68 234.608 80.376 ;
     RECT  234.421 82.08 234.608 83.064 ;
     RECT  234.608 2.148 234.712 84.252 ;
     RECT  234.712 2.418 234.904 83.982 ;
     RECT  234.904 45.264 235.073 52.056 ;
     RECT  234.904 61.2 235.109 64.296 ;
     RECT  234.904 25.008 235.145 25.032 ;
     RECT  234.904 36.48 235.145 36.936 ;
     RECT  235.145 36.48 235.261 36.504 ;
     RECT  234.904 26.064 235.325 35.208 ;
     RECT  235.073 45.264 235.325 51.384 ;
     RECT  234.904 10.032 235.933 12.744 ;
     RECT  234.904 16.656 235.933 16.776 ;
     RECT  235.109 61.488 235.933 64.296 ;
     RECT  234.904 80.784 235.933 83.064 ;
     RECT  235.933 10.032 235.969 12.84 ;
     RECT  235.933 80.592 235.969 83.064 ;
     RECT  235.325 45.264 236.473 51.048 ;
     RECT  235.969 80.592 236.509 83.496 ;
     RECT  235.325 26.064 236.545 35.112 ;
     RECT  234.904 54.672 236.545 57.48 ;
     RECT  235.969 9.936 237.445 12.84 ;
     RECT  235.933 16.08 237.445 16.776 ;
     RECT  236.509 80.592 237.445 83.592 ;
     RECT  235.933 61.488 237.481 64.392 ;
     RECT  237.445 80.4 237.557 83.592 ;
     RECT  237.445 9.936 237.564 12.936 ;
     RECT  237.445 16.08 237.564 16.872 ;
     RECT  236.545 26.064 237.564 35.208 ;
     RECT  236.473 45.264 237.564 51.336 ;
     RECT  236.545 54.48 237.564 57.48 ;
     RECT  237.481 61.392 237.564 64.392 ;
     RECT  237.557 80.592 237.564 83.592 ;
    LAYER M5 ;
     RECT  16.08 0.016 19.08 0.131 ;
     RECT  20.496 0.016 21 0.131 ;
     RECT  42.192 0.016 45.192 0.131 ;
     RECT  83.664 0.016 86.664 0.131 ;
     RECT  16.176 0.131 19.08 0.179 ;
     RECT  42.288 0.131 45.192 0.563 ;
     RECT  118.992 0.016 125.064 0.611 ;
     RECT  119.28 0.611 125.064 0.659 ;
     RECT  42.576 0.563 45.192 1.139 ;
     RECT  3.792 0.016 9.864 1.187 ;
     RECT  20.592 0.131 21 1.187 ;
     RECT  42.864 1.139 45.192 1.187 ;
     RECT  83.76 0.131 86.664 1.235 ;
     RECT  119.472 0.659 125.064 1.235 ;
     RECT  16.272 0.179 19.08 1.379 ;
     RECT  4.176 1.187 9.864 1.715 ;
     RECT  43.632 1.187 43.752 1.715 ;
     RECT  109.008 0.016 112.008 1.715 ;
     RECT  44.784 1.187 45.192 1.763 ;
     RECT  109.2 1.715 112.008 1.763 ;
     RECT  119.472 1.235 124.968 1.763 ;
     RECT  109.392 1.763 112.008 1.811 ;
     RECT  4.848 1.715 9.864 1.859 ;
     RECT  83.76 1.235 86.472 1.859 ;
     RECT  205.152 2.005 205.176 2.053 ;
     RECT  45.072 1.763 45.192 2.137 ;
     RECT  83.76 1.859 86.088 2.137 ;
     RECT  2.4 2.137 2.52 2.151 ;
     RECT  13.2 2.137 13.32 2.151 ;
     RECT  24 2.137 24.12 2.151 ;
     RECT  29.4 2.137 29.52 2.151 ;
     RECT  34.8 2.137 34.92 2.151 ;
     RECT  40.2 2.137 40.32 2.151 ;
     RECT  45.072 2.137 45.72 2.151 ;
     RECT  51 2.137 51.12 2.151 ;
     RECT  56.4 2.137 56.52 2.151 ;
     RECT  61.8 2.137 61.92 2.151 ;
     RECT  67.2 2.137 67.32 2.151 ;
     RECT  72.6 2.137 72.72 2.151 ;
     RECT  78 2.137 78.12 2.151 ;
     RECT  88.8 2.137 88.92 2.151 ;
     RECT  94.2 2.137 94.32 2.151 ;
     RECT  99.6 2.137 99.72 2.151 ;
     RECT  105 2.137 105.12 2.151 ;
     RECT  115.8 2.137 115.92 2.151 ;
     RECT  126.6 2.137 126.72 2.151 ;
     RECT  132 2.137 132.12 2.151 ;
     RECT  137.4 2.137 137.52 2.151 ;
     RECT  142.8 2.137 142.92 2.151 ;
     RECT  148.2 2.137 148.32 2.151 ;
     RECT  153.6 2.137 153.72 2.151 ;
     RECT  159 2.137 159.12 2.151 ;
     RECT  164.4 2.137 164.52 2.151 ;
     RECT  169.8 2.137 169.92 2.151 ;
     RECT  175.2 2.137 175.32 2.151 ;
     RECT  180.6 2.137 180.72 2.151 ;
     RECT  186 2.137 186.12 2.151 ;
     RECT  191.4 2.137 191.52 2.151 ;
     RECT  196.8 2.137 196.92 2.151 ;
     RECT  202.2 2.137 202.32 2.151 ;
     RECT  207.6 2.137 207.72 2.151 ;
     RECT  213 2.137 213.12 2.151 ;
     RECT  218.4 2.137 218.52 2.151 ;
     RECT  223.8 2.137 223.92 2.151 ;
     RECT  229.2 2.137 229.32 2.151 ;
     RECT  234.6 2.137 234.72 2.151 ;
     RECT  110.4 1.811 112.008 2.197 ;
     RECT  137.4 2.151 137.712 2.197 ;
     RECT  166.224 1.957 166.248 2.245 ;
     RECT  175.2 2.151 175.512 2.245 ;
     RECT  213 2.151 213.312 2.245 ;
     RECT  166.128 2.245 166.248 2.291 ;
     RECT  16.272 1.379 17.544 2.533 ;
     RECT  164.4 2.151 164.712 2.629 ;
     RECT  126.6 2.151 126.912 2.677 ;
     RECT  148.2 2.151 148.512 2.677 ;
     RECT  151.776 2.245 151.8 2.677 ;
     RECT  180.6 2.151 180.912 2.677 ;
     RECT  119.664 1.763 124.68 2.773 ;
     RECT  132 2.151 132.312 2.773 ;
     RECT  141.6 2.197 141.624 2.773 ;
     RECT  146.16 2.677 146.184 2.773 ;
     RECT  147.312 2.677 148.512 2.773 ;
     RECT  153.6 2.151 153.912 2.773 ;
     RECT  169.8 2.151 170.112 2.773 ;
     RECT  4.848 1.859 9.192 2.821 ;
     RECT  24 2.151 24.312 2.821 ;
     RECT  83.4 2.137 86.088 2.821 ;
     RECT  109.392 1.811 109.416 2.821 ;
     RECT  110.4 2.197 112.728 2.821 ;
     RECT  126.6 2.677 127.8 2.821 ;
     RECT  129.936 2.053 129.96 2.821 ;
     RECT  4.848 2.821 9.672 2.869 ;
     RECT  16.272 2.533 17.592 2.869 ;
     RECT  18.6 1.379 19.08 2.869 ;
     RECT  129.552 2.821 129.96 2.869 ;
     RECT  20.592 1.187 20.904 2.915 ;
     RECT  43.728 1.715 43.752 2.915 ;
     RECT  45.072 2.151 45.912 2.915 ;
     RECT  83.184 2.821 86.088 2.915 ;
     RECT  109.392 2.821 113.784 2.915 ;
     RECT  85.392 2.915 86.088 2.963 ;
     RECT  129.552 2.869 130.296 2.965 ;
     RECT  131.568 2.773 132.312 2.965 ;
     RECT  134.832 2.821 134.856 3.013 ;
     RECT  145.2 2.773 146.184 3.061 ;
     RECT  150.336 2.245 150.36 3.109 ;
     RECT  151.488 2.677 151.8 3.109 ;
     RECT  180.6 2.677 181.704 3.109 ;
     RECT  16.272 2.869 19.08 3.157 ;
     RECT  20.592 2.915 20.616 3.157 ;
     RECT  87.504 2.821 87.528 3.157 ;
     RECT  144.672 3.061 146.184 3.157 ;
     RECT  174.912 2.245 175.512 3.157 ;
     RECT  160.944 2.677 160.968 3.205 ;
     RECT  162.768 2.245 162.792 3.205 ;
     RECT  16.272 3.157 20.616 3.299 ;
     RECT  29.4 2.151 29.712 3.301 ;
     RECT  142.8 2.151 143.112 3.301 ;
     RECT  186 2.151 186.312 3.301 ;
     RECT  2.4 2.151 2.712 3.349 ;
     RECT  47.664 3.205 47.688 3.349 ;
     RECT  126.192 2.821 127.8 3.397 ;
     RECT  150.336 3.109 151.8 3.397 ;
     RECT  153.504 2.773 153.912 3.397 ;
     RECT  159 2.151 159.312 3.397 ;
     RECT  160.944 3.205 162.792 3.397 ;
     RECT  164.4 2.629 164.856 3.397 ;
     RECT  166.128 2.291 166.152 3.397 ;
     RECT  218.4 2.151 218.712 3.637 ;
     RECT  24 2.821 24.504 3.685 ;
     RECT  87.504 3.157 87.768 3.685 ;
     RECT  119.088 2.773 124.68 3.685 ;
     RECT  125.952 3.397 127.8 3.685 ;
     RECT  29.4 3.301 29.88 3.733 ;
     RECT  144.576 3.157 146.184 3.733 ;
     RECT  147.312 2.773 148.632 3.733 ;
     RECT  23.376 3.685 24.504 3.877 ;
     RECT  44.112 3.349 44.568 3.877 ;
     RECT  142.8 3.301 143.304 3.877 ;
     RECT  144.576 3.733 148.632 3.877 ;
     RECT  169.632 2.773 170.112 3.877 ;
     RECT  2.4 3.349 2.808 3.925 ;
     RECT  3.936 2.869 9.672 3.925 ;
     RECT  10.656 2.821 10.68 3.925 ;
     RECT  13.2 2.151 13.512 3.925 ;
     RECT  22.368 3.397 22.392 3.925 ;
     RECT  23.376 3.877 24.792 3.925 ;
     RECT  28.416 3.733 29.88 3.925 ;
     RECT  41.616 3.397 41.64 3.925 ;
     RECT  129.552 2.965 132.312 3.925 ;
     RECT  133.44 2.821 133.464 3.925 ;
     RECT  136.32 2.677 136.344 3.925 ;
     RECT  137.4 2.197 138.456 3.925 ;
     RECT  158.832 3.397 159.312 3.925 ;
     RECT  178.752 2.773 178.776 3.925 ;
     RECT  185.136 3.301 186.312 3.925 ;
     RECT  83.184 2.915 84.312 4.019 ;
     RECT  110.304 2.915 113.784 4.115 ;
     RECT  142.8 3.877 148.632 4.115 ;
     RECT  2.4 3.925 11.544 4.261 ;
     RECT  41.616 3.925 42.216 4.261 ;
     RECT  155.04 2.773 155.064 4.261 ;
     RECT  169.632 3.877 170.376 4.261 ;
     RECT  110.304 4.115 113.544 4.357 ;
     RECT  83.4 4.019 84.312 4.453 ;
     RECT  16.272 3.299 19.896 4.501 ;
     RECT  31.008 4.453 31.032 4.501 ;
     RECT  34.8 2.151 35.112 4.501 ;
     RECT  41.52 4.261 42.216 4.501 ;
     RECT  43.728 3.877 44.568 4.501 ;
     RECT  86.064 2.963 86.088 4.501 ;
     RECT  136.32 3.925 138.456 4.501 ;
     RECT  139.584 2.773 141.624 4.501 ;
     RECT  142.8 4.115 145.032 4.501 ;
     RECT  150.336 3.397 153.912 4.501 ;
     RECT  154.992 4.261 155.064 4.501 ;
     RECT  164.4 3.397 166.152 4.501 ;
     RECT  168.96 4.261 170.376 4.501 ;
     RECT  171.36 2.773 171.384 4.501 ;
     RECT  187.776 3.925 187.8 4.501 ;
     RECT  117.888 4.117 117.912 4.549 ;
     RECT  119.088 3.685 127.8 4.549 ;
     RECT  21.12 3.925 22.392 4.595 ;
     RECT  187.776 4.501 188.088 4.693 ;
     RECT  109.968 4.357 113.544 4.741 ;
     RECT  117.888 4.549 127.8 4.835 ;
     RECT  139.584 4.501 145.032 4.835 ;
     RECT  45.6 2.915 45.912 4.837 ;
     RECT  47.664 3.349 47.88 4.837 ;
     RECT  150.048 4.501 153.912 4.979 ;
     RECT  178.752 3.925 179.352 4.981 ;
     RECT  196.8 2.151 197.112 4.981 ;
     RECT  187.776 4.693 188.328 5.027 ;
     RECT  21.312 4.595 22.392 5.029 ;
     RECT  23.376 3.925 25.224 5.029 ;
     RECT  167.76 3.205 167.784 5.029 ;
     RECT  177.36 3.397 177.384 5.029 ;
     RECT  178.416 4.981 179.352 5.029 ;
     RECT  13.2 3.925 15 5.077 ;
     RECT  16.08 4.501 19.896 5.077 ;
     RECT  21.312 5.029 25.224 5.077 ;
     RECT  183.168 2.773 183.192 5.077 ;
     RECT  187.776 5.027 188.088 5.077 ;
     RECT  205.152 2.053 205.512 5.077 ;
     RECT  177.36 5.029 179.352 5.123 ;
     RECT  2.4 4.261 11.592 5.171 ;
     RECT  87.216 3.685 87.768 5.171 ;
     RECT  117.888 4.835 127.512 5.171 ;
     RECT  109.584 4.741 113.544 5.219 ;
     RECT  160.944 3.397 163.224 5.219 ;
     RECT  128.784 3.925 133.464 5.221 ;
     RECT  13.2 5.077 19.896 5.317 ;
     RECT  154.992 4.501 155.16 5.317 ;
     RECT  157.728 2.773 157.752 5.317 ;
     RECT  202.2 2.151 202.512 5.317 ;
     RECT  213 2.245 214.248 5.317 ;
     RECT  41.52 4.501 44.568 5.365 ;
     RECT  45.6 4.837 47.88 5.365 ;
     RECT  141.36 4.835 145.032 5.459 ;
     RECT  199.152 5.077 199.176 5.461 ;
     RECT  200.16 5.317 200.184 5.461 ;
     RECT  218.304 3.637 218.712 5.461 ;
     RECT  13.2 5.317 20.28 5.557 ;
     RECT  128.544 5.221 133.464 5.603 ;
     RECT  199.152 5.461 200.184 5.603 ;
     RECT  21.312 5.077 25.368 5.605 ;
     RECT  40.2 2.151 40.512 5.605 ;
     RECT  41.52 5.365 47.88 5.605 ;
     RECT  128.64 5.603 133.464 5.605 ;
     RECT  134.832 3.013 135.24 5.605 ;
     RECT  167.52 5.029 167.784 5.605 ;
     RECT  168.96 4.501 171.384 5.605 ;
     RECT  177.36 5.123 177.576 5.605 ;
     RECT  194.016 5.077 194.04 5.605 ;
     RECT  217.152 4.981 217.176 5.605 ;
     RECT  218.304 5.461 218.808 5.605 ;
     RECT  136.32 4.501 138.504 5.651 ;
     RECT  167.52 5.605 171.384 5.651 ;
     RECT  13.104 5.557 20.28 5.653 ;
     RECT  33.024 4.501 33.048 5.653 ;
     RECT  88.8 2.151 89.112 5.653 ;
     RECT  196.608 4.981 197.112 5.653 ;
     RECT  85.344 4.501 86.088 5.701 ;
     RECT  83.4 4.453 84.36 5.747 ;
     RECT  85.344 5.701 86.184 5.747 ;
     RECT  124.176 5.171 127.512 5.747 ;
     RECT  182.784 5.077 183.192 5.795 ;
     RECT  151.488 4.979 153.912 5.797 ;
     RECT  154.992 5.317 155.304 5.797 ;
     RECT  178.752 5.123 179.352 5.797 ;
     RECT  136.416 5.651 138.504 5.843 ;
     RECT  12.816 5.653 20.28 5.845 ;
     RECT  21.312 5.605 25.704 5.845 ;
     RECT  27.456 3.925 29.88 5.845 ;
     RECT  139.584 4.835 140.376 6.035 ;
     RECT  151.488 5.797 155.304 6.035 ;
     RECT  178.752 5.797 179.4 6.035 ;
     RECT  31.008 4.501 31.512 6.229 ;
     RECT  33.024 5.653 33.528 6.229 ;
     RECT  34.8 4.501 35.688 6.229 ;
     RECT  109.584 5.219 112.584 6.229 ;
     RECT  113.568 5.653 113.592 6.229 ;
     RECT  161.808 5.219 163.224 6.229 ;
     RECT  180.48 3.109 181.704 6.229 ;
     RECT  202.2 5.317 203.352 6.229 ;
     RECT  204.672 5.077 205.512 6.229 ;
     RECT  207.6 2.151 207.912 6.229 ;
     RECT  208.944 5.605 208.968 6.229 ;
     RECT  210.288 5.365 210.312 6.229 ;
     RECT  83.4 5.747 84.312 6.323 ;
     RECT  156.768 5.317 157.752 6.323 ;
     RECT  158.832 3.925 159.576 6.323 ;
     RECT  109.008 6.229 113.592 6.371 ;
     RECT  184.368 3.925 186.312 6.421 ;
     RECT  187.584 5.077 188.088 6.421 ;
     RECT  21.312 5.845 29.88 6.517 ;
     RECT  31.008 6.229 35.688 6.517 ;
     RECT  168.624 5.651 171.384 6.563 ;
     RECT  136.656 5.843 138.504 6.565 ;
     RECT  141.6 5.459 145.032 6.659 ;
     RECT  202.2 6.229 205.512 6.661 ;
     RECT  136.656 6.565 138.744 6.707 ;
     RECT  117.888 5.171 123.048 6.709 ;
     RECT  177.264 5.605 177.576 6.709 ;
     RECT  212.88 5.317 214.248 6.709 ;
     RECT  12.576 5.845 20.28 6.755 ;
     RECT  124.176 5.747 124.2 6.755 ;
     RECT  182.784 5.795 183.048 6.755 ;
     RECT  174.672 3.157 175.512 6.757 ;
     RECT  37.296 5.077 37.32 6.805 ;
     RECT  110.16 6.371 113.592 6.805 ;
     RECT  117.888 6.709 123.144 6.805 ;
     RECT  125.328 5.747 127.512 6.805 ;
     RECT  174.144 6.757 175.512 6.805 ;
     RECT  180.432 6.229 181.704 6.805 ;
     RECT  191.4 2.151 191.712 6.805 ;
     RECT  196.608 5.653 197.352 6.805 ;
     RECT  199.152 5.603 199.176 6.805 ;
     RECT  200.16 5.603 200.184 6.805 ;
     RECT  217.152 5.605 218.808 6.805 ;
     RECT  220.8 6.181 220.824 6.805 ;
     RECT  221.952 6.709 221.976 6.805 ;
     RECT  115.8 2.151 116.112 6.853 ;
     RECT  86.16 5.747 86.184 6.899 ;
     RECT  167.52 5.651 167.544 7.093 ;
     RECT  146.16 4.115 148.632 7.235 ;
     RECT  2.4 5.171 2.808 7.237 ;
     RECT  3.936 5.171 11.592 7.237 ;
     RECT  146.304 7.235 148.632 7.237 ;
     RECT  172.512 3.301 172.536 7.237 ;
     RECT  156.96 6.323 157.752 7.331 ;
     RECT  207.168 6.229 207.912 7.333 ;
     RECT  2.4 7.237 11.592 7.381 ;
     RECT  12.576 6.755 19.896 7.381 ;
     RECT  154.992 6.035 155.304 7.381 ;
     RECT  156.96 7.331 157.704 7.381 ;
     RECT  164.304 4.501 166.152 7.381 ;
     RECT  167.52 7.093 167.592 7.381 ;
     RECT  184.368 6.421 188.088 7.381 ;
     RECT  216.144 5.845 216.168 7.381 ;
     RECT  217.152 6.805 219.72 7.381 ;
     RECT  223.8 2.151 224.112 7.381 ;
     RECT  229.2 2.151 229.512 7.381 ;
     RECT  230.928 6.805 230.952 7.381 ;
     RECT  40.2 5.605 47.88 7.427 ;
     RECT  229.2 7.381 230.952 7.475 ;
     RECT  171.792 7.237 172.536 7.573 ;
     RECT  173.616 6.805 175.512 7.573 ;
     RECT  180.432 6.805 181.896 7.619 ;
     RECT  171.792 7.573 175.512 7.715 ;
     RECT  117.888 6.805 123.72 7.765 ;
     RECT  124.704 6.805 127.512 7.765 ;
     RECT  141.6 6.659 144.84 7.765 ;
     RECT  223.68 7.381 224.904 7.765 ;
     RECT  232.656 6.805 232.68 7.765 ;
     RECT  115.8 6.853 116.232 7.909 ;
     RECT  141.6 7.765 145.224 7.909 ;
     RECT  182.88 6.755 183.048 7.909 ;
     RECT  184.368 7.381 188.328 7.909 ;
     RECT  194.016 5.605 194.808 7.909 ;
     RECT  212.88 6.709 214.872 7.909 ;
     RECT  194.016 7.909 195.096 7.955 ;
     RECT  128.64 5.605 135.24 7.957 ;
     RECT  232.32 7.765 232.68 7.957 ;
     RECT  128.64 7.957 135.672 8.003 ;
     RECT  164.304 7.381 167.592 8.003 ;
     RECT  21.312 6.517 35.688 8.341 ;
     RECT  36.672 6.805 37.32 8.341 ;
     RECT  158.88 6.323 159.576 8.341 ;
     RECT  160.848 6.229 163.224 8.341 ;
     RECT  202.08 6.661 205.512 8.483 ;
     RECT  2.4 7.381 19.896 8.485 ;
     RECT  21.312 8.341 37.32 8.485 ;
     RECT  40.2 7.427 47.688 8.485 ;
     RECT  115.8 7.909 116.568 8.485 ;
     RECT  117.888 7.765 127.512 8.485 ;
     RECT  146.304 7.237 148.872 8.485 ;
     RECT  150.048 4.979 150.36 8.485 ;
     RECT  151.488 6.035 153.912 8.485 ;
     RECT  154.992 7.381 157.704 8.485 ;
     RECT  158.88 8.341 163.224 8.485 ;
     RECT  176.736 6.709 177.576 8.485 ;
     RECT  178.752 6.035 179.304 8.485 ;
     RECT  180.48 7.619 181.896 8.485 ;
     RECT  182.88 7.909 188.328 8.485 ;
     RECT  206.832 7.333 207.912 8.485 ;
     RECT  208.944 6.229 210.312 8.485 ;
     RECT  212.016 7.909 214.872 8.485 ;
     RECT  220.8 6.805 221.976 8.485 ;
     RECT  227.184 6.805 227.544 8.485 ;
     RECT  229.2 7.475 229.992 8.485 ;
     RECT  230.976 7.909 231 8.485 ;
     RECT  115.8 8.485 127.512 8.533 ;
     RECT  180.48 8.485 188.328 8.723 ;
     RECT  206.832 8.485 210.312 8.821 ;
     RECT  164.304 8.003 167.544 8.965 ;
     RECT  168.624 6.563 170.52 8.965 ;
     RECT  164.304 8.965 170.52 9.011 ;
     RECT  171.792 7.715 172.536 9.013 ;
     RECT  227.184 8.485 228.024 9.013 ;
     RECT  115.8 8.533 127.608 9.061 ;
     RECT  128.832 8.003 135.672 9.061 ;
     RECT  229.2 8.485 231 9.061 ;
     RECT  232.32 7.957 232.728 9.061 ;
     RECT  115.8 9.061 135.672 9.157 ;
     RECT  136.656 6.707 138.504 9.157 ;
     RECT  115.8 9.157 138.504 9.203 ;
     RECT  139.776 6.035 140.376 9.205 ;
     RECT  194.016 7.955 194.04 9.253 ;
     RECT  195.072 7.955 195.096 9.253 ;
     RECT  139.776 9.205 140.52 9.347 ;
     RECT  137.184 9.203 138.504 9.349 ;
     RECT  139.776 9.347 140.376 9.349 ;
     RECT  196.608 6.805 197.928 9.349 ;
     RECT  190.032 6.805 191.712 9.589 ;
     RECT  192.912 8.437 192.936 9.589 ;
     RECT  190.032 9.589 192.936 9.637 ;
     RECT  194.016 9.253 195.096 9.637 ;
     RECT  211.392 8.485 214.872 9.637 ;
     RECT  216.144 7.381 219.72 9.637 ;
     RECT  189.408 9.637 192.936 9.685 ;
     RECT  194.016 9.637 195.624 9.685 ;
     RECT  229.2 9.061 232.728 9.685 ;
     RECT  110.16 6.805 114.36 9.733 ;
     RECT  115.8 9.203 135.912 9.779 ;
     RECT  103.536 4.693 103.56 9.923 ;
     RECT  146.304 8.485 153.912 9.923 ;
     RECT  2.4 8.485 37.32 10.021 ;
     RECT  226.848 9.013 228.024 10.067 ;
     RECT  211.392 9.637 219.72 10.069 ;
     RECT  40.2 8.485 48.36 10.165 ;
     RECT  206.64 8.821 210.312 10.259 ;
     RECT  223.44 7.765 224.904 10.259 ;
     RECT  109.008 6.371 109.032 10.307 ;
     RECT  168.144 9.011 170.52 10.309 ;
     RECT  171.6 9.013 172.536 10.309 ;
     RECT  168.144 10.309 172.536 10.451 ;
     RECT  137.184 9.349 140.376 10.453 ;
     RECT  107.76 8.149 107.784 10.549 ;
     RECT  134.208 9.779 135.912 10.549 ;
     RECT  2.4 10.021 37.416 10.595 ;
     RECT  107.76 10.549 108.024 10.595 ;
     RECT  189.408 9.685 195.624 10.595 ;
     RECT  110.112 9.733 114.36 10.597 ;
     RECT  223.68 10.259 224.904 10.741 ;
     RECT  110.016 10.597 114.36 10.789 ;
     RECT  115.8 9.779 133.032 10.789 ;
     RECT  134.208 10.549 136.2 10.789 ;
     RECT  176.736 8.485 179.304 10.789 ;
     RECT  180.48 8.723 188.232 10.789 ;
     RECT  199.152 6.805 200.328 10.789 ;
     RECT  226.944 10.067 228.024 10.789 ;
     RECT  229.2 9.685 232.872 10.789 ;
     RECT  168.144 10.451 170.52 10.835 ;
     RECT  150.048 9.923 153.912 10.883 ;
     RECT  193.92 10.595 195.624 10.883 ;
     RECT  51 2.151 51.312 10.981 ;
     RECT  226.944 10.789 232.872 10.981 ;
     RECT  2.4 10.595 31.032 11.027 ;
     RECT  176.736 10.789 188.232 11.029 ;
     RECT  196.608 9.349 198.024 11.077 ;
     RECT  176.688 11.029 188.232 11.123 ;
     RECT  171.6 10.451 172.536 11.269 ;
     RECT  173.616 7.715 175.512 11.269 ;
     RECT  154.992 8.485 163.224 11.315 ;
     RECT  164.304 9.011 167.064 11.317 ;
     RECT  109.152 10.789 114.36 11.365 ;
     RECT  115.344 10.789 136.2 11.365 ;
     RECT  141.504 7.909 145.224 11.365 ;
     RECT  146.304 9.923 149.064 11.365 ;
     RECT  151.392 10.883 153.912 11.365 ;
     RECT  154.992 11.315 156.456 11.365 ;
     RECT  220.8 8.485 222.216 11.365 ;
     RECT  223.68 10.741 225.24 11.365 ;
     RECT  157.68 11.315 163.224 11.459 ;
     RECT  189.408 10.595 192.936 11.459 ;
     RECT  196.608 11.077 198.12 11.509 ;
     RECT  141.504 11.365 149.064 11.605 ;
     RECT  150.048 10.883 150.36 11.605 ;
     RECT  141.504 11.605 150.36 11.651 ;
     RECT  38.688 9.637 38.712 11.653 ;
     RECT  206.736 10.259 210.312 11.653 ;
     RECT  211.392 10.069 219.768 11.653 ;
     RECT  38.448 11.653 38.712 11.699 ;
     RECT  164.304 11.317 167.208 11.845 ;
     RECT  168.384 10.835 170.52 11.845 ;
     RECT  206.736 11.653 219.768 11.891 ;
     RECT  83.4 6.323 83.712 11.941 ;
     RECT  189.408 11.459 192.552 11.941 ;
     RECT  2.4 11.027 20.568 11.987 ;
     RECT  176.688 11.123 181.944 12.035 ;
     RECT  199.152 10.789 201.048 12.035 ;
     RECT  220.8 11.365 225.24 12.035 ;
     RECT  176.736 12.035 181.944 12.181 ;
     RECT  183.024 11.123 188.232 12.181 ;
     RECT  141.6 11.651 150.36 12.227 ;
     RECT  189.264 11.941 192.552 12.275 ;
     RECT  40.2 10.165 48.504 12.325 ;
     RECT  157.68 11.459 160.44 12.469 ;
     RECT  161.472 11.459 163.224 12.469 ;
     RECT  164.304 11.845 170.52 12.469 ;
     RECT  171.6 11.269 175.512 12.469 ;
     RECT  50.4 10.981 51.312 12.517 ;
     RECT  193.92 10.883 195.096 12.517 ;
     RECT  196.56 11.509 198.12 12.517 ;
     RECT  21.6 11.027 31.032 12.563 ;
     RECT  4.608 11.987 20.568 12.755 ;
     RECT  193.92 12.517 198.12 12.803 ;
     RECT  11.568 12.755 20.568 12.901 ;
     RECT  21.6 12.563 30.84 12.901 ;
     RECT  32.208 10.595 37.416 12.901 ;
     RECT  137.184 10.453 140.472 12.901 ;
     RECT  141.6 12.227 149.112 12.901 ;
     RECT  40.2 12.325 48.84 13.045 ;
     RECT  150.192 12.227 150.36 13.045 ;
     RECT  151.392 11.365 156.456 13.045 ;
     RECT  202.2 8.483 205.512 13.045 ;
     RECT  176.736 12.181 188.232 13.091 ;
     RECT  189.36 12.275 192.552 13.091 ;
     RECT  108 10.595 108.024 13.187 ;
     RECT  109.152 11.365 136.2 13.187 ;
     RECT  109.152 13.187 124.392 13.331 ;
     RECT  137.184 12.901 149.112 13.429 ;
     RECT  150.192 13.045 156.456 13.429 ;
     RECT  2.4 11.987 3.528 13.477 ;
     RECT  4.608 12.755 10.536 13.477 ;
     RECT  38.448 11.699 38.472 13.477 ;
     RECT  221.04 12.035 225.24 13.477 ;
     RECT  183.936 13.091 188.232 13.525 ;
     RECT  189.36 13.091 192.216 13.525 ;
     RECT  11.568 12.901 30.84 13.573 ;
     RECT  31.968 12.901 37.416 13.573 ;
     RECT  164.304 12.469 175.512 13.667 ;
     RECT  125.568 13.187 136.2 13.715 ;
     RECT  183.936 13.525 192.216 13.715 ;
     RECT  129.024 13.715 136.2 13.765 ;
     RECT  137.184 13.429 156.456 13.765 ;
     RECT  2.4 13.477 10.536 13.813 ;
     RECT  11.568 13.573 37.416 13.813 ;
     RECT  193.968 12.803 198.12 13.813 ;
     RECT  199.152 12.035 200.664 13.813 ;
     RECT  129.024 13.765 156.456 13.859 ;
     RECT  157.68 12.469 163.224 13.859 ;
     RECT  206.88 11.891 219.768 14.053 ;
     RECT  176.736 13.091 182.904 14.101 ;
     RECT  82.56 11.941 83.712 14.147 ;
     RECT  157.824 13.859 163.224 14.149 ;
     RECT  164.304 13.667 172.536 14.149 ;
     RECT  2.4 13.813 37.416 14.197 ;
     RECT  38.448 13.477 39.048 14.197 ;
     RECT  221.04 13.477 225.432 14.245 ;
     RECT  173.52 13.667 175.512 14.341 ;
     RECT  176.736 14.101 182.952 14.341 ;
     RECT  183.936 13.715 188.088 14.341 ;
     RECT  2.4 14.197 39.048 14.387 ;
     RECT  50.16 12.517 51.312 14.387 ;
     RECT  115.2 13.331 124.392 14.387 ;
     RECT  124.08 14.387 124.392 14.389 ;
     RECT  157.824 14.149 172.536 14.435 ;
     RECT  202.032 13.045 205.512 14.485 ;
     RECT  206.496 14.053 219.768 14.485 ;
     RECT  202.032 14.485 219.768 14.627 ;
     RECT  189.12 13.715 191.712 14.773 ;
     RECT  173.52 14.341 188.088 14.867 ;
     RECT  109.152 13.331 114.12 14.869 ;
     RECT  115.2 14.387 123.096 14.869 ;
     RECT  193.968 13.813 200.664 14.965 ;
     RECT  58.128 10.837 58.152 15.059 ;
     RECT  129.024 13.859 146.136 15.107 ;
     RECT  193.632 14.965 200.664 15.157 ;
     RECT  202.032 14.627 203.88 15.157 ;
     RECT  141.6 15.107 146.136 15.301 ;
     RECT  147.168 13.859 156.456 15.301 ;
     RECT  157.824 14.435 163.224 15.301 ;
     RECT  124.08 14.389 124.536 15.349 ;
     RECT  125.568 13.715 127.608 15.349 ;
     RECT  50.4 14.387 51.312 15.443 ;
     RECT  109.152 14.869 123.096 15.443 ;
     RECT  124.08 15.349 127.608 15.491 ;
     RECT  193.632 15.157 203.88 15.589 ;
     RECT  204.864 14.627 219.768 15.589 ;
     RECT  40.08 13.045 48.84 15.635 ;
     RECT  2.4 14.387 33.336 15.637 ;
     RECT  64.944 12.853 64.968 15.637 ;
     RECT  2.4 15.637 33.768 15.683 ;
     RECT  64.608 15.637 64.968 15.683 ;
     RECT  11.664 15.683 33.768 15.829 ;
     RECT  34.8 14.387 39.048 15.829 ;
     RECT  11.664 15.829 39.048 15.877 ;
     RECT  40.08 15.635 41.4 15.877 ;
     RECT  193.632 15.589 219.768 15.971 ;
     RECT  2.4 15.683 10.536 16.019 ;
     RECT  68.88 6.229 68.904 16.019 ;
     RECT  129.024 15.107 140.568 16.019 ;
     RECT  164.304 14.435 172.536 16.019 ;
     RECT  168.096 16.019 172.536 16.067 ;
     RECT  193.632 15.971 199.32 16.259 ;
     RECT  50.784 15.443 51.312 16.405 ;
     RECT  109.152 15.443 109.176 16.405 ;
     RECT  110.304 15.443 123.048 16.405 ;
     RECT  193.632 16.259 193.992 16.499 ;
     RECT  141.6 15.301 163.224 16.595 ;
     RECT  173.52 14.867 187.992 16.595 ;
     RECT  168.288 16.067 172.536 16.691 ;
     RECT  109.152 16.405 123.048 16.787 ;
     RECT  112.56 16.787 123.048 16.933 ;
     RECT  124.08 15.491 124.536 16.933 ;
     RECT  173.52 16.595 175.512 16.979 ;
     RECT  4.8 16.019 10.536 17.029 ;
     RECT  11.664 15.877 41.4 17.029 ;
     RECT  164.304 16.019 166.632 17.029 ;
     RECT  168.288 16.691 170.808 17.029 ;
     RECT  112.56 16.933 124.536 17.075 ;
     RECT  125.568 15.491 127.608 17.075 ;
     RECT  173.664 16.979 175.512 17.075 ;
     RECT  134.352 16.019 140.568 17.077 ;
     RECT  194.976 16.259 199.32 17.123 ;
     RECT  4.8 17.029 41.4 17.171 ;
     RECT  141.6 16.595 146.712 17.171 ;
     RECT  147.744 16.595 163.224 17.171 ;
     RECT  109.152 16.787 111.576 17.315 ;
     RECT  200.4 15.971 219.768 17.315 ;
     RECT  177.024 16.595 184.296 17.363 ;
     RECT  152.784 17.171 163.224 17.411 ;
     RECT  164.304 17.029 170.808 17.459 ;
     RECT  124.08 17.075 124.536 17.509 ;
     RECT  125.568 17.075 127.176 17.509 ;
     RECT  200.4 17.315 204.504 17.555 ;
     RECT  182.256 17.363 184.296 17.605 ;
     RECT  185.328 16.595 187.992 17.605 ;
     RECT  152.832 17.411 163.224 17.651 ;
     RECT  129.024 16.019 132.888 17.653 ;
     RECT  133.872 17.077 140.568 17.653 ;
     RECT  173.76 17.075 175.512 17.699 ;
     RECT  193.824 16.499 193.992 17.843 ;
     RECT  42.432 15.635 48.84 17.845 ;
     RECT  64.608 15.683 64.632 17.891 ;
     RECT  152.832 17.651 157.032 18.035 ;
     RECT  112.56 17.075 123.048 18.133 ;
     RECT  193.824 17.843 193.848 18.133 ;
     RECT  173.808 17.699 175.512 18.181 ;
     RECT  34.8 17.171 41.4 18.275 ;
     RECT  112.56 18.133 123.096 18.275 ;
     RECT  164.4 17.459 170.808 18.275 ;
     RECT  129.024 17.653 140.568 18.419 ;
     RECT  158.16 17.651 163.224 18.565 ;
     RECT  164.4 18.275 165.624 18.565 ;
     RECT  196.56 17.123 199.32 18.565 ;
     RECT  200.4 17.555 204.36 18.565 ;
     RECT  113.664 18.275 123.096 18.613 ;
     RECT  124.08 17.509 127.176 18.613 ;
     RECT  177.024 17.363 181.08 18.707 ;
     RECT  189.12 14.773 192.408 18.707 ;
     RECT  166.608 18.275 170.808 18.757 ;
     RECT  171.792 16.691 172.536 18.757 ;
     RECT  196.56 18.565 204.36 18.757 ;
     RECT  205.488 17.315 219.768 18.757 ;
     RECT  109.152 17.315 111.528 18.805 ;
     RECT  112.56 18.275 112.584 18.805 ;
     RECT  109.152 18.805 112.584 18.851 ;
     RECT  136.032 18.419 140.568 18.851 ;
     RECT  154.992 18.035 157.032 18.947 ;
     RECT  140.112 18.851 140.568 18.997 ;
     RECT  141.6 17.171 146.376 18.997 ;
     RECT  88.704 5.653 89.112 19.043 ;
     RECT  4.8 17.171 33.768 19.139 ;
     RECT  34.8 18.275 35.88 19.237 ;
     RECT  37.2 18.275 41.4 19.237 ;
     RECT  194.976 17.123 195.48 19.237 ;
     RECT  194.88 19.237 195.48 19.283 ;
     RECT  221.04 14.245 225.48 19.333 ;
     RECT  50.016 16.405 51.312 19.427 ;
     RECT  196.56 18.757 219.768 19.475 ;
     RECT  179.52 18.707 181.08 19.477 ;
     RECT  154.992 18.947 156.696 19.523 ;
     RECT  158.16 18.565 165.624 19.523 ;
     RECT  182.256 17.605 187.992 19.523 ;
     RECT  163.44 19.523 165.624 19.525 ;
     RECT  166.608 18.757 172.536 19.525 ;
     RECT  34.8 19.237 41.4 19.621 ;
     RECT  196.56 19.475 204.36 19.667 ;
     RECT  109.152 18.851 112.488 19.811 ;
     RECT  182.448 19.523 187.992 19.909 ;
     RECT  42.384 17.845 48.84 19.955 ;
     RECT  110.112 19.811 112.488 20.003 ;
     RECT  140.112 18.997 146.376 20.003 ;
     RECT  163.44 19.525 172.536 20.003 ;
     RECT  173.808 18.181 175.608 20.003 ;
     RECT  189.12 18.707 192.12 20.003 ;
     RECT  182.448 19.909 188.088 20.197 ;
     RECT  189.12 20.003 191.712 20.197 ;
     RECT  166.608 20.003 172.536 20.339 ;
     RECT  50.784 19.427 51.312 20.437 ;
     RECT  220.8 19.333 225.48 20.437 ;
     RECT  158.16 19.523 162.36 20.533 ;
     RECT  4.8 19.139 33.336 20.579 ;
     RECT  34.56 19.621 41.4 20.579 ;
     RECT  42.384 19.955 48.264 20.579 ;
     RECT  113.664 18.613 127.176 20.579 ;
     RECT  140.112 20.003 146.184 20.579 ;
     RECT  220.8 20.437 225.72 20.579 ;
     RECT  193.776 18.133 193.848 20.725 ;
     RECT  44.544 20.579 48.264 20.771 ;
     RECT  173.808 20.003 175.512 20.965 ;
     RECT  226.944 10.981 233.256 21.013 ;
     RECT  34.56 20.579 38.856 21.059 ;
     RECT  113.664 20.579 117.672 21.061 ;
     RECT  113.472 21.061 117.672 21.107 ;
     RECT  39.888 20.579 41.4 21.109 ;
     RECT  42.384 20.579 43.512 21.109 ;
     RECT  198.096 19.667 204.36 21.155 ;
     RECT  140.112 20.579 144.888 21.157 ;
     RECT  193.536 20.725 193.848 21.253 ;
     RECT  194.88 19.283 195.336 21.253 ;
     RECT  119.184 20.579 127.176 21.349 ;
     RECT  193.536 21.253 195.336 21.349 ;
     RECT  196.56 19.667 197.112 21.349 ;
     RECT  39.888 21.109 43.512 21.395 ;
     RECT  205.392 19.475 219.768 21.493 ;
     RECT  220.8 20.579 221.976 21.493 ;
     RECT  114.48 21.107 117.672 21.587 ;
     RECT  34.56 21.059 37.656 21.635 ;
     RECT  152.832 18.035 154.008 21.635 ;
     RECT  199.728 21.155 204.36 21.635 ;
     RECT  129.024 18.419 135.048 21.637 ;
     RECT  193.536 21.349 197.112 21.637 ;
     RECT  198.096 21.155 198.264 21.637 ;
     RECT  205.392 21.493 221.976 21.637 ;
     RECT  223.152 20.579 225.72 21.637 ;
     RECT  2.4 16.019 3.672 21.683 ;
     RECT  110.112 20.003 111.48 21.683 ;
     RECT  128.88 21.637 135.048 21.683 ;
     RECT  168.48 20.339 172.536 21.683 ;
     RECT  182.448 20.197 191.712 21.683 ;
     RECT  226.848 21.013 233.256 21.731 ;
     RECT  139.44 21.157 144.888 21.733 ;
     RECT  147.744 17.171 151.416 21.781 ;
     RECT  44.544 20.771 48.12 21.923 ;
     RECT  115.8 21.587 117.672 21.925 ;
     RECT  179.52 19.477 181.272 21.971 ;
     RECT  147.648 21.781 151.416 22.019 ;
     RECT  199.92 21.635 204.36 22.069 ;
     RECT  205.392 21.637 225.72 22.069 ;
     RECT  4.8 20.579 6.408 22.165 ;
     RECT  7.536 20.579 33.336 22.165 ;
     RECT  199.92 22.069 225.72 22.165 ;
     RECT  4.8 22.165 33.336 22.211 ;
     RECT  119.184 21.349 127.464 22.211 ;
     RECT  40.2 21.395 43.512 22.259 ;
     RECT  115.8 21.925 117.912 22.259 ;
     RECT  154.992 19.523 156.456 22.259 ;
     RECT  166.608 20.339 167.448 22.259 ;
     RECT  179.52 21.971 181.08 22.259 ;
     RECT  199.92 22.165 225.768 22.259 ;
     RECT  123.072 22.211 127.464 22.451 ;
     RECT  158.16 20.533 162.456 22.451 ;
     RECT  50.688 20.437 51.312 22.453 ;
     RECT  136.032 18.851 138.168 22.499 ;
     RECT  139.392 21.733 144.888 22.499 ;
     RECT  182.448 21.683 189.288 22.499 ;
     RECT  40.2 22.259 43.176 22.739 ;
     RECT  136.752 22.499 138.168 22.741 ;
     RECT  147.648 22.019 149.832 22.787 ;
     RECT  112.464 20.003 112.488 22.835 ;
     RECT  114.48 21.587 114.6 22.835 ;
     RECT  128.88 21.683 129.576 22.835 ;
     RECT  141.504 22.499 144.888 22.835 ;
     RECT  147.648 22.787 148.776 22.835 ;
     RECT  154.992 22.259 155.016 22.835 ;
     RECT  158.352 22.451 162.456 22.835 ;
     RECT  163.44 20.003 165.624 22.835 ;
     RECT  173.808 20.965 175.704 22.835 ;
     RECT  182.448 22.499 184.296 22.835 ;
     RECT  130.848 21.683 135.048 22.883 ;
     RECT  177.024 18.707 178.392 22.883 ;
     RECT  193.536 21.637 198.264 22.931 ;
     RECT  185.904 22.499 189.288 22.979 ;
     RECT  7.8 22.211 33.336 23.027 ;
     RECT  193.536 22.931 198.024 23.075 ;
     RECT  169.008 21.683 172.536 23.123 ;
     RECT  34.8 21.635 37.656 23.125 ;
     RECT  38.736 21.059 38.856 23.125 ;
     RECT  40.2 22.739 41.064 23.125 ;
     RECT  151.152 22.019 151.416 23.171 ;
     RECT  175.2 22.835 175.704 23.221 ;
     RECT  177.024 22.883 177.528 23.221 ;
     RECT  139.392 22.499 140.136 23.267 ;
     RECT  136.752 22.741 138.408 23.315 ;
     RECT  130.848 22.883 132.312 23.363 ;
     RECT  139.968 23.267 140.136 23.363 ;
     RECT  34.368 23.125 37.656 23.411 ;
     RECT  50.496 22.453 51.312 23.411 ;
     RECT  110.4 21.683 111.48 23.411 ;
     RECT  117.312 22.259 117.912 23.411 ;
     RECT  119.184 22.211 121.752 23.411 ;
     RECT  123.072 22.451 127.032 23.411 ;
     RECT  128.88 22.835 129.24 23.411 ;
     RECT  133.824 22.883 135.048 23.411 ;
     RECT  147.648 22.835 148.632 23.411 ;
     RECT  160.752 22.835 162.456 23.411 ;
     RECT  171.888 23.123 172.536 23.411 ;
     RECT  185.904 22.979 188.616 23.411 ;
     RECT  199.92 22.259 204.072 23.411 ;
     RECT  133.824 23.411 134.52 23.651 ;
     RECT  179.952 22.259 181.08 23.701 ;
     RECT  205.2 22.259 225.768 23.701 ;
     RECT  190.272 21.683 191.712 23.795 ;
     RECT  175.2 23.221 177.528 23.891 ;
     RECT  169.008 23.123 170.808 23.893 ;
     RECT  7.8 23.027 31.992 23.987 ;
     RECT  113.472 21.107 113.496 23.987 ;
     RECT  114.48 22.835 114.504 23.987 ;
     RECT  119.184 23.411 120.168 23.987 ;
     RECT  141.504 22.835 144.36 23.987 ;
     RECT  149.808 22.787 149.832 23.987 ;
     RECT  151.152 23.171 151.176 23.987 ;
     RECT  193.536 23.075 194.136 23.987 ;
     RECT  195.312 23.075 198.024 23.987 ;
     RECT  199.92 23.411 203.4 23.987 ;
     RECT  159 22.835 159.672 24.131 ;
     RECT  179.232 23.701 181.08 24.131 ;
     RECT  183.024 22.835 184.296 24.131 ;
     RECT  205.2 23.701 225.816 24.181 ;
     RECT  168.912 23.893 170.808 24.277 ;
     RECT  171.888 23.411 171.912 24.277 ;
     RECT  44.64 21.923 48.12 24.323 ;
     RECT  168.912 24.277 171.912 24.323 ;
     RECT  117.312 23.411 117.336 24.371 ;
     RECT  4.848 22.211 6.648 24.373 ;
     RECT  7.8 23.987 31.272 24.373 ;
     RECT  204.576 24.181 225.816 24.419 ;
     RECT  34.368 23.411 37.176 24.563 ;
     RECT  38.736 23.125 41.064 24.563 ;
     RECT  42.384 22.739 43.176 24.563 ;
     RECT  121.2 23.411 121.752 24.563 ;
     RECT  123.888 23.411 124.152 24.563 ;
     RECT  126.6 23.411 127.032 24.563 ;
     RECT  128.88 23.411 128.904 24.563 ;
     RECT  137.28 23.315 138.408 24.563 ;
     RECT  139.968 23.363 139.992 24.563 ;
     RECT  141.504 23.987 143.112 24.563 ;
     RECT  144.336 23.987 144.36 24.563 ;
     RECT  152.832 21.635 153.912 24.563 ;
     RECT  160.944 23.411 161.784 24.563 ;
     RECT  167.424 22.259 167.448 24.563 ;
     RECT  168.912 24.323 171.336 24.563 ;
     RECT  173.808 22.835 173.832 24.563 ;
     RECT  179.232 24.131 179.256 24.563 ;
     RECT  180.6 24.131 181.08 24.563 ;
     RECT  183.648 24.131 184.296 24.563 ;
     RECT  199.92 23.987 202.512 24.563 ;
     RECT  33.312 23.027 33.336 24.611 ;
     RECT  134.304 23.651 134.52 24.659 ;
     RECT  148.2 23.411 148.632 24.659 ;
     RECT  226.944 21.731 233.256 24.709 ;
     RECT  130.944 23.363 132.312 24.803 ;
     RECT  134.496 24.659 134.52 24.851 ;
     RECT  146.16 20.579 146.184 24.899 ;
     RECT  185.904 23.411 186.312 24.899 ;
     RECT  4.848 24.373 31.272 25.139 ;
     RECT  34.8 24.563 36.648 25.139 ;
     RECT  38.736 24.563 38.856 25.139 ;
     RECT  42.384 24.563 42.408 25.139 ;
     RECT  44.64 24.323 47.544 25.139 ;
     RECT  120.144 23.987 120.168 25.139 ;
     RECT  130.944 24.803 130.968 25.139 ;
     RECT  161.76 24.563 161.784 25.139 ;
     RECT  164.112 22.835 165.624 25.139 ;
     RECT  171.312 24.563 171.336 25.139 ;
     RECT  177.504 23.891 177.528 25.139 ;
     RECT  183.648 24.563 183.672 25.139 ;
     RECT  187.344 23.411 188.616 25.139 ;
     RECT  190.32 23.795 191.712 25.139 ;
     RECT  193.536 23.987 193.56 25.139 ;
     RECT  195.312 23.987 195.336 25.139 ;
     RECT  196.704 23.987 198.024 25.139 ;
     RECT  199.92 24.563 199.944 25.139 ;
     RECT  201.504 24.563 202.512 25.139 ;
     RECT  38.832 25.139 38.856 25.187 ;
     RECT  175.2 23.891 176.328 25.187 ;
     RECT  40.2 24.563 40.632 25.235 ;
     RECT  175.2 25.187 175.704 25.235 ;
     RECT  4.848 25.139 31.224 25.381 ;
     RECT  205.2 24.419 225.816 25.427 ;
     RECT  45.6 25.139 46.824 25.475 ;
     RECT  182.256 25.237 182.28 25.475 ;
     RECT  156.432 22.259 156.456 25.621 ;
     RECT  34.8 25.139 35.832 25.715 ;
     RECT  156.288 25.621 156.456 25.715 ;
     RECT  188.592 25.139 188.616 25.715 ;
     RECT  196.8 25.139 198.024 25.715 ;
     RECT  49.344 22.165 49.368 25.763 ;
     RECT  4.608 25.381 31.224 25.955 ;
     RECT  153.408 24.563 153.912 25.957 ;
     RECT  205.44 25.427 225.816 26.003 ;
     RECT  80.928 25.621 80.952 26.099 ;
     RECT  217.296 26.003 225.816 26.101 ;
     RECT  226.944 24.709 233.4 26.101 ;
     RECT  200.976 25.621 201 26.197 ;
     RECT  159 24.131 159.312 26.533 ;
     RECT  5.616 25.955 31.224 26.675 ;
     RECT  168.912 24.563 170.112 27.059 ;
     RECT  102.576 25.621 102.6 27.107 ;
     RECT  217.296 26.101 233.4 27.301 ;
     RECT  234.6 2.151 234.912 27.301 ;
     RECT  5.616 26.675 13.992 27.347 ;
     RECT  200.88 26.197 201 27.779 ;
     RECT  4.608 25.955 4.632 27.877 ;
     RECT  5.616 27.347 13.8 27.877 ;
     RECT  15.024 26.675 31.224 27.877 ;
     RECT  4.608 27.877 13.8 27.923 ;
     RECT  205.44 26.003 216.312 27.923 ;
     RECT  205.68 27.923 216.312 27.971 ;
     RECT  15.024 27.877 31.272 28.453 ;
     RECT  15.024 28.453 31.32 28.547 ;
     RECT  2.4 21.683 3.528 29.123 ;
     RECT  205.728 27.971 216.312 29.173 ;
     RECT  217.296 27.301 234.912 29.173 ;
     RECT  4.608 27.923 5.352 29.219 ;
     RECT  15.168 28.547 31.32 30.275 ;
     RECT  6.384 27.923 13.8 30.803 ;
     RECT  205.728 29.173 234.912 31.379 ;
     RECT  15.696 30.275 31.32 31.525 ;
     RECT  5.328 29.219 5.352 31.955 ;
     RECT  6.96 30.803 13.8 31.955 ;
     RECT  15.648 31.525 31.32 31.955 ;
     RECT  237.408 32.005 237.432 32.195 ;
     RECT  216 31.379 234.912 32.293 ;
     RECT  9.744 31.955 13.8 32.387 ;
     RECT  205.728 31.379 214.872 32.437 ;
     RECT  216 32.293 235.224 32.437 ;
     RECT  22.08 31.955 31.32 32.531 ;
     RECT  28.32 32.531 31.32 32.723 ;
     RECT  6.96 31.955 8.712 32.965 ;
     RECT  9.744 32.387 10.248 32.965 ;
     RECT  205.728 32.437 235.224 33.059 ;
     RECT  212.064 33.059 235.224 33.107 ;
     RECT  15.648 31.955 20.904 33.683 ;
     RECT  212.064 33.107 216.024 33.779 ;
     RECT  28.32 32.723 31.272 33.874 ;
     RECT  212.064 33.779 214.344 34.019 ;
     RECT  28.32 33.874 31.368 34.067 ;
     RECT  15.648 33.683 19.272 34.069 ;
     RECT  22.08 32.531 27.24 34.117 ;
     RECT  28.32 34.067 31.272 34.163 ;
     RECT  11.616 32.387 13.8 34.259 ;
     RECT  205.728 33.059 210.888 34.259 ;
     RECT  21.984 34.117 27.24 34.307 ;
     RECT  6.96 32.965 10.248 34.835 ;
     RECT  215.568 33.779 216.024 34.835 ;
     RECT  217.008 33.107 235.224 34.835 ;
     RECT  6.96 34.835 9.096 35.363 ;
     RECT  11.712 34.259 13.8 35.363 ;
     RECT  212.064 34.019 213.576 35.363 ;
     RECT  217.104 34.835 222.408 35.363 ;
     RECT  210.24 34.259 210.888 35.507 ;
     RECT  20.64 33.683 20.904 35.891 ;
     RECT  205.728 34.259 209.16 35.891 ;
     RECT  7.8 35.363 9.096 35.939 ;
     RECT  22.128 34.307 27.24 35.939 ;
     RECT  20.736 35.891 20.904 35.987 ;
     RECT  15.264 34.069 19.272 36.373 ;
     RECT  11.712 35.363 13.512 36.515 ;
     RECT  15.168 36.373 19.272 36.515 ;
     RECT  212.064 35.363 213.312 36.515 ;
     RECT  221.568 35.363 222.408 36.515 ;
     RECT  223.68 34.835 235.224 36.515 ;
     RECT  11.712 36.515 11.736 36.563 ;
     RECT  16.32 36.515 16.344 36.563 ;
     RECT  217.104 35.363 217.128 36.661 ;
     RECT  217.056 36.661 217.128 36.851 ;
     RECT  215.568 34.835 215.592 37.141 ;
     RECT  22.704 35.939 24.456 37.525 ;
     RECT  26.16 35.939 27.24 37.525 ;
     RECT  15.168 36.515 15.192 37.667 ;
     RECT  210.24 35.507 210.792 37.667 ;
     RECT  212.16 36.515 213.312 37.667 ;
     RECT  206.016 35.891 209.16 37.715 ;
     RECT  206.016 37.715 208.872 38.003 ;
     RECT  215.424 37.141 215.592 38.195 ;
     RECT  210.768 37.667 210.792 38.243 ;
     RECT  17.616 36.515 19.272 38.435 ;
     RECT  206.016 38.003 208.632 38.485 ;
     RECT  205.728 38.485 208.632 38.771 ;
     RECT  205.728 38.771 208.44 39.251 ;
     RECT  20.736 35.987 20.76 39.349 ;
     RECT  17.856 38.435 19.272 39.395 ;
     RECT  20.736 39.349 20.856 39.395 ;
     RECT  28.32 34.163 31.176 39.395 ;
     RECT  20.832 39.395 20.856 39.491 ;
     RECT  28.416 39.395 31.176 39.491 ;
     RECT  22.704 37.525 27.24 39.637 ;
     RECT  22.704 39.637 27.288 39.683 ;
     RECT  18.6 39.395 19.272 39.923 ;
     RECT  22.704 39.683 26.184 39.923 ;
     RECT  29.28 39.491 31.176 39.923 ;
     RECT  29.4 39.923 31.176 40.021 ;
     RECT  29.4 40.021 31.416 40.211 ;
     RECT  215.568 38.195 215.592 40.499 ;
     RECT  27.216 39.683 27.288 40.835 ;
     RECT  217.104 36.851 217.128 41.075 ;
     RECT  223.68 36.515 234.912 41.075 ;
     RECT  23.616 39.923 25.368 41.125 ;
     RECT  23.616 41.125 25.656 41.171 ;
     RECT  23.616 41.171 24.456 41.651 ;
     RECT  218.112 35.363 220.488 41.651 ;
     RECT  27.264 40.835 27.288 41.939 ;
     RECT  23.616 41.651 24.408 42.227 ;
     RECT  222.384 36.515 222.408 42.323 ;
     RECT  23.616 42.227 24.312 42.803 ;
     RECT  27.312 42.037 27.336 42.803 ;
     RECT  23.904 42.803 24.312 43.379 ;
     RECT  25.632 41.171 25.656 43.379 ;
     RECT  29.4 40.211 31.176 43.379 ;
     RECT  29.4 43.379 31.08 43.859 ;
     RECT  30.72 43.859 31.08 43.955 ;
     RECT  218.4 41.651 220.488 43.955 ;
     RECT  223.68 41.075 233.544 43.955 ;
     RECT  30.72 43.955 30.744 44.051 ;
     RECT  223.8 43.955 233.544 44.437 ;
     RECT  234.6 41.075 234.912 44.437 ;
     RECT  29.4 43.859 29.712 44.965 ;
     RECT  218.4 43.955 220.44 45.491 ;
     RECT  219.744 45.491 220.44 45.635 ;
     RECT  220.416 45.635 220.44 46.211 ;
     RECT  206.016 39.251 208.44 49.045 ;
     RECT  205.728 49.045 208.44 53.891 ;
     RECT  223.8 44.437 234.912 54.755 ;
     RECT  223.8 54.755 227.976 55.283 ;
     RECT  222.432 42.565 222.456 55.331 ;
     RECT  227.136 55.283 227.976 55.813 ;
     RECT  229.2 54.755 234.912 55.813 ;
     RECT  223.8 55.283 225.864 56.243 ;
     RECT  225.84 56.243 225.864 56.483 ;
     RECT  227.136 55.813 234.912 56.483 ;
     RECT  28.992 44.965 29.712 56.965 ;
     RECT  223.8 56.243 224.568 57.059 ;
     RECT  227.136 56.483 232.92 57.059 ;
     RECT  227.808 57.059 231.672 57.635 ;
     RECT  229.2 57.635 231.672 57.827 ;
     RECT  234 56.483 234.912 57.923 ;
     RECT  153.024 25.957 153.912 58.403 ;
     RECT  227.808 57.635 227.832 58.739 ;
     RECT  229.2 57.827 231.576 58.739 ;
     RECT  229.2 58.739 231.384 59.315 ;
     RECT  232.896 57.059 232.92 59.555 ;
     RECT  28.8 56.965 29.712 60.035 ;
     RECT  28.992 60.035 29.712 60.083 ;
     RECT  29.136 60.083 29.712 60.323 ;
     RECT  150.432 60.037 150.456 60.323 ;
     RECT  27.792 47.269 27.816 60.419 ;
     RECT  229.2 59.315 231 60.997 ;
     RECT  229.2 60.997 231.144 61.477 ;
     RECT  223.8 57.059 224.112 61.525 ;
     RECT  232.8 60.949 232.824 61.619 ;
     RECT  205.728 53.891 206.616 61.907 ;
     RECT  222.336 61.525 222.36 62.149 ;
     RECT  222.336 62.149 222.648 62.195 ;
     RECT  229.2 61.477 231.48 62.437 ;
     RECT  31.008 53.029 31.032 62.483 ;
     RECT  226.56 62.101 226.584 62.533 ;
     RECT  227.76 61.525 227.784 62.533 ;
     RECT  226.56 62.533 227.784 62.579 ;
     RECT  229.056 62.437 231.48 62.581 ;
     RECT  232.944 62.293 232.968 62.581 ;
     RECT  226.8 62.579 227.784 62.675 ;
     RECT  229.056 62.581 232.968 62.723 ;
     RECT  200.88 27.779 200.904 62.819 ;
     RECT  222.624 62.195 222.648 63.059 ;
     RECT  226.8 62.675 227.688 63.685 ;
     RECT  226.8 63.685 227.976 63.731 ;
     RECT  223.8 61.525 224.616 63.733 ;
     RECT  229.056 62.723 229.608 63.781 ;
     RECT  230.736 62.723 232.968 64.021 ;
     RECT  226.8 63.731 226.824 64.693 ;
     RECT  227.952 63.731 227.976 64.693 ;
     RECT  226.8 64.693 227.976 64.739 ;
     RECT  229.056 63.781 229.656 64.933 ;
     RECT  230.688 64.021 232.968 64.933 ;
     RECT  207.6 53.891 208.44 64.979 ;
     RECT  194.064 27.637 194.088 65.027 ;
     RECT  156.288 25.715 156.312 65.267 ;
     RECT  227.232 64.739 227.976 65.269 ;
     RECT  229.056 64.933 232.968 65.269 ;
     RECT  227.232 65.269 232.968 65.315 ;
     RECT  227.232 65.315 227.256 70.069 ;
     RECT  228.24 65.315 232.968 70.069 ;
     RECT  227.232 70.069 232.968 72.515 ;
     RECT  187.344 25.139 187.368 72.755 ;
     RECT  223.8 63.733 225.144 72.899 ;
     RECT  227.28 72.515 232.968 73.043 ;
     RECT  173.52 26.485 173.544 74.099 ;
     RECT  164.4 25.139 165.576 74.963 ;
     RECT  190.656 25.139 191.712 75.539 ;
     RECT  166.704 26.053 166.728 76.355 ;
     RECT  234.6 57.923 234.912 78.037 ;
     RECT  176.928 25.429 176.952 78.755 ;
     RECT  228.336 73.043 232.968 79.283 ;
     RECT  163.248 25.333 163.272 79.811 ;
     RECT  159 26.533 159.864 80.099 ;
     RECT  234.432 78.037 234.912 80.341 ;
     RECT  183.792 27.589 183.816 80.915 ;
     RECT  228.336 79.283 232.392 80.917 ;
     RECT  227.28 73.043 227.304 81.059 ;
     RECT  228.336 80.917 232.584 81.059 ;
     RECT  206.016 61.907 206.616 81.203 ;
     RECT  228.336 81.059 229.944 81.299 ;
     RECT  206.592 81.203 206.616 81.731 ;
     RECT  231.264 81.059 232.584 81.875 ;
     RECT  223.8 72.899 224.856 82.115 ;
     RECT  223.8 82.115 224.568 82.691 ;
     RECT  226.848 81.301 226.872 82.691 ;
     RECT  228.672 81.299 229.944 82.691 ;
     RECT  231.264 81.875 231.672 82.691 ;
     RECT  234.144 80.341 234.912 83.075 ;
     RECT  231.264 82.691 231.288 83.459 ;
     RECT  2.4 29.123 2.712 84.249 ;
     RECT  7.8 35.939 8.112 84.249 ;
     RECT  13.2 36.515 13.512 84.249 ;
     RECT  18.6 39.923 18.912 84.249 ;
     RECT  24 43.379 24.312 84.249 ;
     RECT  29.4 60.323 29.712 84.249 ;
     RECT  34.8 25.715 35.112 84.249 ;
     RECT  40.2 25.235 40.512 84.249 ;
     RECT  45.6 25.475 45.912 84.249 ;
     RECT  51 23.411 51.312 84.249 ;
     RECT  56.4 2.151 56.712 84.249 ;
     RECT  61.8 2.151 62.112 84.249 ;
     RECT  67.2 2.151 67.512 84.249 ;
     RECT  72.6 2.151 72.912 84.249 ;
     RECT  78 2.151 78.312 84.249 ;
     RECT  83.4 14.147 83.712 84.249 ;
     RECT  88.8 19.043 89.112 84.249 ;
     RECT  94.2 2.151 94.512 84.249 ;
     RECT  99.6 2.151 99.912 84.249 ;
     RECT  105 2.151 105.312 84.249 ;
     RECT  110.4 23.411 110.712 84.249 ;
     RECT  115.8 22.259 116.112 84.249 ;
     RECT  121.2 24.563 121.512 84.249 ;
     RECT  126.6 24.563 126.912 84.249 ;
     RECT  132 24.803 132.312 84.249 ;
     RECT  137.4 24.563 137.712 84.249 ;
     RECT  142.8 24.563 143.112 84.249 ;
     RECT  148.2 24.659 148.512 84.249 ;
     RECT  153.6 58.403 153.912 84.249 ;
     RECT  159 80.099 159.312 84.249 ;
     RECT  164.4 74.963 164.712 84.249 ;
     RECT  169.8 27.059 170.112 84.249 ;
     RECT  175.2 25.235 175.512 84.249 ;
     RECT  180.6 24.563 180.912 84.249 ;
     RECT  186 24.899 186.312 84.249 ;
     RECT  191.4 75.539 191.712 84.249 ;
     RECT  196.8 25.715 197.112 84.249 ;
     RECT  202.2 25.139 202.512 84.249 ;
     RECT  207.6 64.979 207.912 84.249 ;
     RECT  212.688 37.667 213.312 84.249 ;
     RECT  218.4 45.491 218.712 84.249 ;
     RECT  223.8 82.691 224.112 84.249 ;
     RECT  229.2 82.691 229.512 84.249 ;
     RECT  234.6 83.075 234.912 84.249 ;
     RECT  2.4 84.249 2.52 84.263 ;
     RECT  7.8 84.249 7.92 84.263 ;
     RECT  13.2 84.249 13.32 84.263 ;
     RECT  18.6 84.249 18.72 84.263 ;
     RECT  24 84.249 24.12 84.263 ;
     RECT  29.4 84.249 29.52 84.263 ;
     RECT  34.8 84.249 34.92 84.263 ;
     RECT  40.2 84.249 40.32 84.263 ;
     RECT  45.6 84.249 45.72 84.263 ;
     RECT  51 84.249 51.12 84.263 ;
     RECT  56.4 84.249 56.52 84.263 ;
     RECT  61.8 84.249 61.92 84.263 ;
     RECT  67.2 84.249 67.32 84.263 ;
     RECT  72.6 84.249 72.72 84.263 ;
     RECT  78 84.249 78.12 84.263 ;
     RECT  83.4 84.249 83.52 84.263 ;
     RECT  88.8 84.249 88.92 84.263 ;
     RECT  94.2 84.249 94.32 84.263 ;
     RECT  99.6 84.249 99.72 84.263 ;
     RECT  105 84.249 105.12 84.263 ;
     RECT  110.4 84.249 110.52 84.263 ;
     RECT  115.8 84.249 115.92 84.263 ;
     RECT  121.2 84.249 121.32 84.263 ;
     RECT  126.6 84.249 126.72 84.263 ;
     RECT  132 84.249 132.12 84.263 ;
     RECT  137.4 84.249 137.52 84.263 ;
     RECT  142.8 84.249 142.92 84.263 ;
     RECT  148.2 84.249 148.32 84.263 ;
     RECT  153.6 84.249 153.72 84.263 ;
     RECT  159 84.249 159.12 84.263 ;
     RECT  164.4 84.249 164.52 84.263 ;
     RECT  169.8 84.249 169.92 84.263 ;
     RECT  175.2 84.249 175.32 84.263 ;
     RECT  180.6 84.249 180.72 84.263 ;
     RECT  186 84.249 186.12 84.263 ;
     RECT  191.4 84.249 191.52 84.263 ;
     RECT  196.8 84.249 196.92 84.263 ;
     RECT  202.2 84.249 202.32 84.263 ;
     RECT  207.6 84.249 207.72 84.263 ;
     RECT  212.688 84.249 213.12 84.263 ;
     RECT  218.4 84.249 218.52 84.263 ;
     RECT  223.8 84.249 223.92 84.263 ;
     RECT  229.2 84.249 229.32 84.263 ;
     RECT  234.6 84.249 234.72 84.263 ;
     RECT  19.128 0.016 20.448 0.132 ;
     RECT  19.08 0.132 20.592 3.157 ;
     RECT  3.792 1.187 4.176 1.715 ;
     RECT  43.752 1.187 44.784 1.763 ;
     RECT  17.544 1.379 18.6 2.533 ;
     RECT  3.792 1.715 4.848 2.137 ;
     RECT  43.752 1.763 45.072 2.915 ;
     RECT  119.472 1.763 119.664 2.773 ;
     RECT  124.68 1.763 124.968 2.821 ;
     RECT  109.416 1.811 110.4 2.821 ;
     RECT  9.192 1.859 9.864 2.821 ;
     RECT  86.088 1.859 86.472 2.821 ;
     RECT  2.52 2.137 4.848 2.151 ;
     RECT  2.712 2.151 4.848 2.869 ;
     RECT  164.712 2.151 166.224 2.245 ;
     RECT  141.624 2.197 142.8 4.501 ;
     RECT  150.36 2.245 151.776 2.677 ;
     RECT  164.712 2.245 166.128 2.629 ;
     RECT  17.592 2.533 18.6 2.869 ;
     RECT  164.856 2.629 166.128 3.397 ;
     RECT  136.344 2.677 137.4 3.925 ;
     RECT  146.184 2.677 147.312 3.733 ;
     RECT  150.36 2.677 151.488 3.109 ;
     RECT  138.456 2.773 139.584 4.501 ;
     RECT  153.912 2.773 155.04 4.261 ;
     RECT  157.752 2.773 159 3.397 ;
     RECT  170.112 2.773 171.36 3.877 ;
     RECT  181.704 2.773 183.168 5.077 ;
     RECT  9.672 2.821 10.656 3.925 ;
     RECT  86.088 2.821 87.504 3.685 ;
     RECT  87.528 2.821 88.8 3.157 ;
     RECT  124.68 2.821 126.192 3.397 ;
     RECT  132.312 2.821 133.44 3.925 ;
     RECT  133.464 2.821 134.832 5.605 ;
     RECT  134.856 2.821 136.32 3.013 ;
     RECT  2.712 2.869 3.936 3.349 ;
     RECT  130.296 2.869 131.568 2.965 ;
     RECT  20.616 2.915 20.904 3.299 ;
     RECT  43.728 2.915 45.6 3.349 ;
     RECT  84.312 2.915 85.392 2.963 ;
     RECT  109.968 2.915 110.304 4.357 ;
     RECT  84.312 2.963 84.36 4.453 ;
     RECT  135.24 3.013 136.32 5.651 ;
     RECT  87.768 3.157 88.8 5.171 ;
     RECT  143.112 3.157 144.576 3.301 ;
     RECT  19.896 3.299 20.904 3.397 ;
     RECT  143.304 3.301 144.576 3.877 ;
     RECT  171.384 3.301 172.512 6.563 ;
     RECT  2.808 3.349 3.936 3.925 ;
     RECT  43.728 3.349 44.112 3.877 ;
     RECT  44.568 3.349 45.6 5.365 ;
     RECT  19.896 3.397 22.368 3.925 ;
     RECT  40.512 3.397 41.616 4.261 ;
     RECT  124.68 3.397 125.952 3.685 ;
     RECT  157.752 3.397 158.832 6.323 ;
     RECT  163.224 3.397 164.4 4.501 ;
     RECT  177.384 3.397 178.752 4.981 ;
     RECT  22.392 3.685 23.376 5.029 ;
     RECT  86.088 3.685 87.216 5.171 ;
     RECT  170.376 3.877 171.36 4.501 ;
     RECT  15 3.925 16.272 4.501 ;
     RECT  19.896 3.925 21.12 4.595 ;
     RECT  42.216 3.925 43.728 4.501 ;
     RECT  127.8 3.925 128.784 4.835 ;
     RECT  159.576 3.925 160.944 5.219 ;
     RECT  179.352 3.925 180.48 5.797 ;
     RECT  183.192 3.925 184.368 5.795 ;
     RECT  186.312 3.925 187.776 5.077 ;
     RECT  145.032 4.115 146.16 6.659 ;
     RECT  117.912 4.117 119.088 4.549 ;
     RECT  40.512 4.261 41.52 5.605 ;
     RECT  153.912 4.261 154.992 5.797 ;
     RECT  167.784 4.261 168.96 5.605 ;
     RECT  29.88 4.453 31.008 6.517 ;
     RECT  15 4.501 16.08 5.077 ;
     RECT  31.512 4.501 33.024 6.229 ;
     RECT  84.36 4.501 85.344 5.747 ;
     RECT  138.504 4.501 139.584 6.035 ;
     RECT  148.632 4.501 150.048 7.237 ;
     RECT  163.224 4.501 164.304 14.149 ;
     RECT  19.896 4.595 21.312 5.317 ;
     RECT  103.56 4.693 105 9.923 ;
     RECT  127.512 4.835 128.784 5.221 ;
     RECT  140.376 4.835 141.36 5.459 ;
     RECT  150.36 4.979 151.488 8.485 ;
     RECT  177.384 4.981 178.416 5.029 ;
     RECT  217.176 4.981 218.304 5.605 ;
     RECT  166.152 5.029 167.52 7.381 ;
     RECT  181.704 5.077 182.784 6.755 ;
     RECT  186.312 5.077 187.584 6.421 ;
     RECT  177.576 5.123 178.752 8.485 ;
     RECT  2.808 5.171 3.936 7.237 ;
     RECT  86.088 5.171 86.184 5.701 ;
     RECT  88.704 5.171 88.8 5.653 ;
     RECT  123.048 5.171 124.176 6.709 ;
     RECT  112.584 5.219 113.544 5.653 ;
     RECT  159.576 5.219 161.808 6.229 ;
     RECT  127.512 5.221 128.544 5.603 ;
     RECT  20.28 5.317 21.312 6.755 ;
     RECT  155.304 5.317 156.768 6.323 ;
     RECT  199.176 5.317 200.16 5.461 ;
     RECT  203.352 5.317 204.672 6.229 ;
     RECT  140.376 5.459 141.6 7.909 ;
     RECT  11.592 5.557 13.104 5.653 ;
     RECT  127.512 5.603 128.64 8.003 ;
     RECT  199.176 5.603 200.16 6.805 ;
     RECT  207.912 5.605 208.944 8.485 ;
     RECT  208.968 5.605 210.288 6.229 ;
     RECT  135.24 5.651 136.416 5.843 ;
     RECT  167.544 5.651 168.624 7.093 ;
     RECT  11.592 5.653 12.816 5.845 ;
     RECT  33.528 5.653 34.8 6.229 ;
     RECT  112.584 5.653 113.568 6.229 ;
     RECT  124.2 5.747 125.328 6.755 ;
     RECT  183.048 5.795 184.368 7.909 ;
     RECT  179.4 5.797 180.48 6.035 ;
     RECT  135.24 5.843 136.656 7.957 ;
     RECT  11.592 5.845 12.576 7.381 ;
     RECT  216.168 5.845 217.152 7.381 ;
     RECT  138.504 6.035 139.776 6.565 ;
     RECT  153.912 6.035 154.992 11.365 ;
     RECT  179.304 6.035 180.48 6.229 ;
     RECT  67.512 6.229 68.88 16.019 ;
     RECT  159.576 6.229 160.848 8.341 ;
     RECT  179.304 6.229 180.432 7.619 ;
     RECT  155.304 6.323 156.96 7.381 ;
     RECT  157.752 6.323 158.88 7.331 ;
     RECT  109.032 6.371 110.16 9.733 ;
     RECT  170.52 6.563 172.512 7.237 ;
     RECT  138.744 6.565 139.776 6.707 ;
     RECT  144.84 6.659 146.16 7.235 ;
     RECT  138.504 6.707 139.776 9.349 ;
     RECT  123.144 6.709 124.176 6.755 ;
     RECT  175.512 6.709 176.736 11.029 ;
     RECT  214.872 6.709 216.144 9.637 ;
     RECT  220.824 6.709 221.952 6.805 ;
     RECT  19.896 6.755 21.312 8.485 ;
     RECT  123.144 6.755 125.328 6.805 ;
     RECT  181.704 6.755 182.88 6.805 ;
     RECT  35.688 6.805 36.672 8.341 ;
     RECT  114.36 6.805 115.8 10.789 ;
     RECT  123.72 6.805 124.704 7.765 ;
     RECT  172.536 6.805 173.616 7.573 ;
     RECT  181.896 6.805 182.88 8.485 ;
     RECT  197.928 6.805 199.152 9.349 ;
     RECT  219.72 6.805 220.8 10.069 ;
     RECT  229.512 6.805 230.928 7.381 ;
     RECT  167.592 7.093 168.624 8.003 ;
     RECT  144.84 7.235 146.304 7.765 ;
     RECT  148.872 7.237 150.048 8.485 ;
     RECT  170.52 7.237 171.792 9.013 ;
     RECT  157.704 7.331 158.88 8.485 ;
     RECT  205.512 7.333 206.832 8.821 ;
     RECT  47.688 7.427 47.88 8.485 ;
     RECT  229.992 7.475 230.952 7.765 ;
     RECT  179.304 7.619 180.48 10.789 ;
     RECT  172.536 7.715 173.616 11.269 ;
     RECT  145.224 7.765 146.304 11.365 ;
     RECT  221.976 7.765 223.44 8.485 ;
     RECT  229.992 7.765 232.32 7.909 ;
     RECT  116.568 7.909 117.888 8.485 ;
     RECT  140.376 7.909 141.504 9.205 ;
     RECT  195.096 7.909 196.608 9.637 ;
     RECT  229.992 7.909 230.976 8.485 ;
     RECT  231 7.909 232.32 9.061 ;
     RECT  194.04 7.955 195.072 9.253 ;
     RECT  135.672 7.957 136.656 9.157 ;
     RECT  127.512 8.003 128.832 8.533 ;
     RECT  167.544 8.003 168.624 8.965 ;
     RECT  107.784 8.149 109.008 10.307 ;
     RECT  191.712 8.437 192.912 9.589 ;
     RECT  192.936 8.437 194.016 9.685 ;
     RECT  210.312 8.485 211.392 11.653 ;
     RECT  222.216 8.485 223.44 10.259 ;
     RECT  228.024 8.485 229.2 10.789 ;
     RECT  127.608 8.533 128.832 9.061 ;
     RECT  188.232 8.723 188.328 9.637 ;
     RECT  205.512 8.821 206.64 10.259 ;
     RECT  167.064 9.011 168.144 10.835 ;
     RECT  170.52 9.013 171.6 10.309 ;
     RECT  135.912 9.203 137.184 10.549 ;
     RECT  140.52 9.205 141.504 9.347 ;
     RECT  140.376 9.347 141.504 10.453 ;
     RECT  198.024 9.349 199.152 11.077 ;
     RECT  37.32 9.637 38.688 10.021 ;
     RECT  38.712 9.637 40.2 11.699 ;
     RECT  188.232 9.637 189.408 11.941 ;
     RECT  195.624 9.637 196.608 10.883 ;
     RECT  109.032 9.733 110.112 10.307 ;
     RECT  133.032 9.779 134.208 10.789 ;
     RECT  149.064 9.923 150.048 11.605 ;
     RECT  37.416 10.021 38.688 11.653 ;
     RECT  219.768 10.069 220.8 12.035 ;
     RECT  205.512 10.259 206.736 11.891 ;
     RECT  222.216 10.259 223.68 11.365 ;
     RECT  107.784 10.307 110.112 10.549 ;
     RECT  170.52 10.451 171.6 12.469 ;
     RECT  140.472 10.453 141.504 11.651 ;
     RECT  108.024 10.549 110.112 10.597 ;
     RECT  136.2 10.549 137.184 13.765 ;
     RECT  31.032 10.595 32.208 12.563 ;
     RECT  192.936 10.595 193.92 11.459 ;
     RECT  108.024 10.597 110.016 10.789 ;
     RECT  108.024 10.789 109.152 13.187 ;
     RECT  114.36 10.789 115.344 11.365 ;
     RECT  201.048 10.789 202.2 12.035 ;
     RECT  167.064 10.835 168.384 11.317 ;
     RECT  56.712 10.837 58.128 15.059 ;
     RECT  150.36 10.883 151.392 13.045 ;
     RECT  195.096 10.883 196.608 11.509 ;
     RECT  233.256 10.981 234.6 24.709 ;
     RECT  20.568 11.027 21.6 12.901 ;
     RECT  175.512 11.029 176.688 12.035 ;
     RECT  198.12 11.077 199.152 13.813 ;
     RECT  181.944 11.123 183.024 12.181 ;
     RECT  156.456 11.315 157.68 13.859 ;
     RECT  167.208 11.317 168.384 11.845 ;
     RECT  160.44 11.459 161.472 12.469 ;
     RECT  192.552 11.459 193.92 12.803 ;
     RECT  195.096 11.509 196.56 12.517 ;
     RECT  140.472 11.651 141.6 12.901 ;
     RECT  37.416 11.653 38.448 14.197 ;
     RECT  40.08 11.699 40.2 13.045 ;
     RECT  205.512 11.891 206.88 14.053 ;
     RECT  188.232 11.941 189.264 12.275 ;
     RECT  3.528 11.987 4.608 13.477 ;
     RECT  175.512 12.035 176.736 14.341 ;
     RECT  200.664 12.035 202.2 13.045 ;
     RECT  219.768 12.035 221.04 19.333 ;
     RECT  149.112 12.227 150.192 13.429 ;
     RECT  188.232 12.275 189.36 13.525 ;
     RECT  48.84 12.517 50.16 14.387 ;
     RECT  30.84 12.563 32.208 12.901 ;
     RECT  10.536 12.755 11.568 13.813 ;
     RECT  192.552 12.803 193.968 13.091 ;
     RECT  30.84 12.901 31.968 13.573 ;
     RECT  200.664 13.045 202.032 15.157 ;
     RECT  182.904 13.091 183.936 14.101 ;
     RECT  124.392 13.187 125.568 14.389 ;
     RECT  114.12 13.331 115.2 14.869 ;
     RECT  39.048 13.477 40.08 15.877 ;
     RECT  225.432 13.477 226.944 14.245 ;
     RECT  172.536 13.667 173.52 16.979 ;
     RECT  127.608 13.715 129.024 17.075 ;
     RECT  188.088 13.715 189.12 14.867 ;
     RECT  191.712 13.715 192.216 14.773 ;
     RECT  146.136 13.859 147.168 15.301 ;
     RECT  156.456 13.859 157.824 15.301 ;
     RECT  205.512 14.053 206.496 14.485 ;
     RECT  182.952 14.101 183.936 14.341 ;
     RECT  225.48 14.245 226.944 20.437 ;
     RECT  33.336 14.387 34.8 15.637 ;
     RECT  123.096 14.387 124.08 15.443 ;
     RECT  124.536 14.389 125.568 15.349 ;
     RECT  163.224 14.435 164.304 17.459 ;
     RECT  203.88 14.627 204.864 15.589 ;
     RECT  187.992 14.867 189.12 19.909 ;
     RECT  192.408 14.965 193.632 16.499 ;
     RECT  140.568 15.107 141.6 18.997 ;
     RECT  50.4 15.443 50.784 16.405 ;
     RECT  109.176 15.443 110.304 16.405 ;
     RECT  123.048 15.443 124.08 16.933 ;
     RECT  124.536 15.491 125.568 17.509 ;
     RECT  41.4 15.635 42.432 17.845 ;
     RECT  33.768 15.637 34.8 15.829 ;
     RECT  10.536 15.683 11.664 17.029 ;
     RECT  199.32 15.971 200.4 18.565 ;
     RECT  3.672 16.019 4.8 21.683 ;
     RECT  132.888 16.019 134.352 17.077 ;
     RECT  166.632 16.019 168.096 16.067 ;
     RECT  166.632 16.067 168.288 17.029 ;
     RECT  193.992 16.259 194.976 17.843 ;
     RECT  48.84 16.405 50.016 19.427 ;
     RECT  192.408 16.499 193.824 18.133 ;
     RECT  146.712 16.595 147.744 17.171 ;
     RECT  175.512 16.595 177.024 18.181 ;
     RECT  184.296 16.595 185.328 17.605 ;
     RECT  170.808 16.691 171.792 18.757 ;
     RECT  111.576 16.787 112.56 17.315 ;
     RECT  172.536 16.979 173.664 17.075 ;
     RECT  123.048 17.075 124.08 18.133 ;
     RECT  172.536 17.075 173.76 17.699 ;
     RECT  132.888 17.077 133.872 17.653 ;
     RECT  195.48 17.123 196.56 19.283 ;
     RECT  33.768 17.171 34.8 19.139 ;
     RECT  146.376 17.171 147.744 20.003 ;
     RECT  151.416 17.171 152.784 17.411 ;
     RECT  111.528 17.315 112.56 18.805 ;
     RECT  204.504 17.315 205.488 17.555 ;
     RECT  181.08 17.363 182.256 19.477 ;
     RECT  151.416 17.411 152.832 23.171 ;
     RECT  163.224 17.459 164.4 18.565 ;
     RECT  204.36 17.555 205.488 18.757 ;
     RECT  157.032 17.651 158.16 18.947 ;
     RECT  172.536 17.699 173.808 23.411 ;
     RECT  193.848 17.843 194.976 19.237 ;
     RECT  41.4 17.845 42.384 21.109 ;
     RECT  154.008 18.035 154.992 21.635 ;
     RECT  123.096 18.133 124.08 18.613 ;
     RECT  192.408 18.133 193.776 18.707 ;
     RECT  175.608 18.181 177.024 20.003 ;
     RECT  35.88 18.275 37.2 19.237 ;
     RECT  112.584 18.275 113.664 18.851 ;
     RECT  165.624 18.275 166.608 19.525 ;
     RECT  135.048 18.419 136.032 22.499 ;
     RECT  178.392 18.707 179.52 22.259 ;
     RECT  112.488 18.851 113.664 21.061 ;
     RECT  156.696 18.947 158.16 19.523 ;
     RECT  33.336 19.139 34.8 19.621 ;
     RECT  193.848 19.237 194.88 21.253 ;
     RECT  195.336 19.283 196.56 21.349 ;
     RECT  219.768 19.333 220.8 21.493 ;
     RECT  50.688 19.427 50.784 20.437 ;
     RECT  204.36 19.475 205.392 22.069 ;
     RECT  181.272 19.477 182.256 19.523 ;
     RECT  162.36 19.523 163.44 20.533 ;
     RECT  181.272 19.523 182.448 21.971 ;
     RECT  33.336 19.621 34.56 21.635 ;
     RECT  197.112 19.667 198.096 21.637 ;
     RECT  188.088 19.909 189.12 20.197 ;
     RECT  111.48 20.003 112.464 22.835 ;
     RECT  165.624 20.003 166.608 22.259 ;
     RECT  175.512 20.003 177.024 20.965 ;
     RECT  167.448 20.339 168.48 21.683 ;
     RECT  225.72 20.437 226.944 21.013 ;
     RECT  162.456 20.533 163.44 22.835 ;
     RECT  6.408 20.579 7.536 22.165 ;
     RECT  38.856 20.579 39.888 21.395 ;
     RECT  43.512 20.579 44.544 21.923 ;
     RECT  117.672 20.579 119.184 21.925 ;
     RECT  144.888 20.579 146.16 22.835 ;
     RECT  221.976 20.579 223.152 21.637 ;
     RECT  48.12 20.771 48.264 22.165 ;
     RECT  175.704 20.965 177.024 23.221 ;
     RECT  225.72 21.013 226.848 21.731 ;
     RECT  37.656 21.059 38.736 23.411 ;
     RECT  112.488 21.061 113.472 22.835 ;
     RECT  113.496 21.107 114.48 23.987 ;
     RECT  198.264 21.155 199.728 21.635 ;
     RECT  138.168 21.157 139.44 21.733 ;
     RECT  38.856 21.395 40.2 23.125 ;
     RECT  114.6 21.587 115.8 22.835 ;
     RECT  33.336 21.635 34.8 23.125 ;
     RECT  153.912 21.635 154.992 22.835 ;
     RECT  127.464 21.637 128.88 22.451 ;
     RECT  3.528 21.683 4.8 22.211 ;
     RECT  129.576 21.683 130.848 22.835 ;
     RECT  189.288 21.683 190.272 22.979 ;
     RECT  225.72 21.731 226.944 22.165 ;
     RECT  138.168 21.733 139.392 22.741 ;
     RECT  146.184 21.781 147.648 23.411 ;
     RECT  43.512 21.923 44.64 22.259 ;
     RECT  117.912 21.925 119.184 23.411 ;
     RECT  181.08 21.971 182.448 22.835 ;
     RECT  149.832 22.019 151.152 23.987 ;
     RECT  48.12 22.165 49.344 24.323 ;
     RECT  49.368 22.165 50.688 22.453 ;
     RECT  225.768 22.165 226.944 23.701 ;
     RECT  3.528 22.211 4.848 25.381 ;
     RECT  6.648 22.211 7.8 24.373 ;
     RECT  121.752 22.211 123.072 23.411 ;
     RECT  43.176 22.259 44.64 24.563 ;
     RECT  116.112 22.259 117.312 24.371 ;
     RECT  155.016 22.259 156.432 22.835 ;
     RECT  178.392 22.259 179.952 22.883 ;
     RECT  204.072 22.259 205.2 23.411 ;
     RECT  49.368 22.453 50.496 23.411 ;
     RECT  140.136 22.499 141.504 23.363 ;
     RECT  41.064 22.739 42.384 24.563 ;
     RECT  138.408 22.741 139.392 23.267 ;
     RECT  148.776 22.787 149.808 22.835 ;
     RECT  114.504 22.835 115.8 23.987 ;
     RECT  148.632 22.835 149.808 23.987 ;
     RECT  159.672 22.835 160.752 23.411 ;
     RECT  173.832 22.835 175.2 24.563 ;
     RECT  132.312 22.883 133.824 23.651 ;
     RECT  179.232 22.883 179.952 23.701 ;
     RECT  31.992 23.027 33.312 23.987 ;
     RECT  194.136 23.075 195.312 23.987 ;
     RECT  170.808 23.123 171.888 24.277 ;
     RECT  33.336 23.125 34.368 24.563 ;
     RECT  139.992 23.363 141.504 24.563 ;
     RECT  120.168 23.411 121.2 25.139 ;
     RECT  159.672 23.411 160.944 24.131 ;
     RECT  186.312 23.411 187.344 72.755 ;
     RECT  203.4 23.411 205.2 23.987 ;
     RECT  225.816 23.701 226.944 26.101 ;
     RECT  176.328 23.891 177.504 25.139 ;
     RECT  167.448 23.893 168.912 24.563 ;
     RECT  143.112 23.987 144.336 24.563 ;
     RECT  195.336 23.987 196.704 25.139 ;
     RECT  204.576 23.987 205.2 24.181 ;
     RECT  179.256 24.131 180.6 24.563 ;
     RECT  33.336 24.563 34.8 24.611 ;
     RECT  38.856 24.563 40.2 25.187 ;
     RECT  153.024 24.563 153.408 25.957 ;
     RECT  170.112 24.563 171.312 25.139 ;
     RECT  180.912 24.563 181.08 25.237 ;
     RECT  199.944 24.563 201.504 25.139 ;
     RECT  233.4 24.709 234.6 27.301 ;
     RECT  130.968 24.803 132 25.139 ;
     RECT  164.112 25.139 164.4 25.333 ;
     RECT  165.576 25.139 165.624 26.053 ;
     RECT  176.328 25.139 176.952 25.187 ;
     RECT  187.368 25.139 188.592 25.715 ;
     RECT  200.88 25.139 202.2 25.621 ;
     RECT  175.704 25.187 176.952 25.235 ;
     RECT  175.512 25.235 176.952 25.429 ;
     RECT  180.912 25.237 182.256 25.475 ;
     RECT  163.272 25.333 164.4 79.811 ;
     RECT  3.528 25.381 4.608 29.123 ;
     RECT  175.512 25.429 176.928 78.755 ;
     RECT  200.88 25.621 200.976 26.197 ;
     RECT  201 25.621 202.2 27.779 ;
     RECT  4.632 25.955 5.616 27.877 ;
     RECT  216.312 26.003 217.296 29.173 ;
     RECT  165.576 26.053 166.704 74.963 ;
     RECT  13.992 26.675 15.024 27.347 ;
     RECT  13.8 27.347 15.024 28.547 ;
     RECT  200.904 27.779 202.2 62.819 ;
     RECT  5.352 27.923 6.384 30.803 ;
     RECT  13.8 28.547 15.168 30.275 ;
     RECT  15.648 30.275 15.696 31.525 ;
     RECT  214.872 31.379 216 32.437 ;
     RECT  8.712 31.955 9.744 32.965 ;
     RECT  20.904 31.955 22.08 34.117 ;
     RECT  10.248 32.387 11.616 34.259 ;
     RECT  27.24 32.531 28.32 39.395 ;
     RECT  31.272 32.723 31.32 33.874 ;
     RECT  210.888 33.059 212.064 35.507 ;
     RECT  216.024 33.107 217.008 34.835 ;
     RECT  19.272 33.683 20.64 35.891 ;
     RECT  214.344 33.779 215.568 34.019 ;
     RECT  13.8 34.069 15.264 35.363 ;
     RECT  20.904 34.117 21.984 34.307 ;
     RECT  10.248 34.259 11.712 34.835 ;
     RECT  209.16 34.259 210.24 37.667 ;
     RECT  20.904 34.307 22.128 35.939 ;
     RECT  215.592 34.835 217.104 36.661 ;
     RECT  222.408 34.835 223.68 42.323 ;
     RECT  15.168 35.363 15.264 36.373 ;
     RECT  217.128 35.363 218.112 41.075 ;
     RECT  220.488 35.363 221.568 36.515 ;
     RECT  210.792 35.507 212.064 36.515 ;
     RECT  19.272 35.891 20.736 39.395 ;
     RECT  11.736 36.515 13.2 36.563 ;
     RECT  15.192 36.515 16.32 36.563 ;
     RECT  16.344 36.515 17.616 36.563 ;
     RECT  210.792 36.515 212.16 37.667 ;
     RECT  215.592 36.661 217.056 36.851 ;
     RECT  215.592 36.851 217.104 40.499 ;
     RECT  27.24 39.395 28.416 39.491 ;
     RECT  27.24 39.491 27.288 39.637 ;
     RECT  26.184 39.683 27.216 39.923 ;
     RECT  25.368 39.923 25.656 41.125 ;
     RECT  233.544 41.075 234.6 44.437 ;
     RECT  24.456 41.171 25.632 41.651 ;
     RECT  24.408 41.651 25.632 42.227 ;
     RECT  24.312 42.227 25.632 43.379 ;
     RECT  222.432 42.323 223.68 42.565 ;
     RECT  222.456 42.565 223.68 43.955 ;
     RECT  29.712 43.859 30.72 44.051 ;
     RECT  222.456 43.955 223.8 55.331 ;
     RECT  218.712 45.491 219.744 45.635 ;
     RECT  27.816 47.269 28.992 56.965 ;
     RECT  29.712 53.029 31.008 62.483 ;
     RECT  206.616 53.891 207.6 81.731 ;
     RECT  227.976 54.755 229.2 55.813 ;
     RECT  225.864 55.283 227.136 56.483 ;
     RECT  224.568 56.243 225.84 56.483 ;
     RECT  232.92 56.483 234 57.923 ;
     RECT  27.816 56.965 28.8 60.035 ;
     RECT  231.672 57.059 232.896 57.827 ;
     RECT  227.832 57.635 229.2 58.739 ;
     RECT  231.576 57.827 232.896 58.739 ;
     RECT  231.384 58.739 232.896 59.315 ;
     RECT  27.816 60.035 28.992 60.083 ;
     RECT  27.816 60.083 29.136 60.323 ;
     RECT  231.48 61.477 232.8 61.619 ;
     RECT  222.36 61.525 223.8 62.149 ;
     RECT  227.784 61.525 229.2 62.437 ;
     RECT  231.48 61.619 232.824 62.293 ;
     RECT  226.584 62.101 227.76 62.533 ;
     RECT  222.648 62.149 223.8 63.059 ;
     RECT  231.48 62.293 232.944 62.581 ;
     RECT  227.784 62.437 229.056 62.675 ;
     RECT  227.688 62.675 229.056 63.685 ;
     RECT  229.608 62.723 230.736 63.781 ;
     RECT  227.976 63.685 229.056 65.269 ;
     RECT  226.824 63.731 227.952 64.693 ;
     RECT  229.656 63.781 230.736 64.021 ;
     RECT  229.656 64.021 230.688 64.933 ;
     RECT  227.256 65.315 228.24 70.069 ;
     RECT  227.304 73.043 228.336 81.059 ;
     RECT  232.968 78.037 234.432 79.283 ;
     RECT  234.144 79.283 234.432 80.341 ;
     RECT  229.944 81.059 231.264 82.691 ;
  END
END qfd_link_adp128_p12
END LIBRARY
